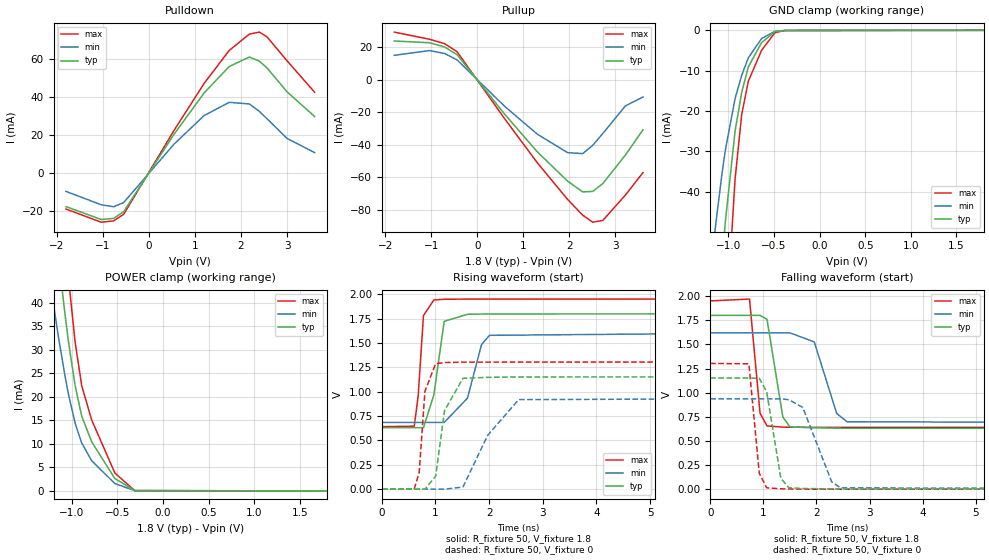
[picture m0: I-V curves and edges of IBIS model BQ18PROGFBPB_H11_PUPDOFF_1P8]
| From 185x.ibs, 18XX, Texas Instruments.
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|OQ18120COMPFZ_V_PDON_1P8; BUFFER WITH WEAK PULLDOWN ON
|   Model Cell BQ18PROGFBPB_H11_PUPDOFF_1P8
|BQ18PROGFBPB_H11_PUPDOFF_1P8
[Model]   BQ18PROGFBPB_H11_PUPDOFF_1P8
Model_type   I/O
Polarity   Non-Inverting
Enable   Active-Low
Vinl =  0.63
Vinh =  1.17
Cref =  15pF
Rref =  100.0000M
Vref =  0V
Vmeas =  0.9
C_comp   2.057622p   1.895389p   2.126353p
[Model Spec]
Vinl   0.63   0.567   0.6825
Vinh   1.17   1.053   1.2675
[Temperature Range]   25   125   -40
[Voltage Range]   1.8   1.62   1.95
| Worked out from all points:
|   slope of the pulldown table from 0 to 0.27 V, typ, clamps not added: 26.3 ohm
|   slope of the pullup table from 0 to 0.27 V, typ, clamps not added: 27.7 ohm
|   GND clamp passes 1 mA (typ) near -0.54 V on its own axis
|   POWER clamp passes 1 mA (typ) near -0.44 V on its own axis
|   rising waveform, R_fixture 50, V_fixture 1.8: 20-80 % time 158ps typ, 316ps min, 88.5ps max; typ from 0.63 V to 1.8 V
|   rising waveform, R_fixture 50, V_fixture 0: 20-80 % time 232ps typ, 451ps min, 107ps max; typ from 0 V to 1.15 V
|   falling waveform, R_fixture 50, V_fixture 1.8: 20-80 % time 173ps typ, 281ps min, 113ps max; typ from 1.8 V to 0.63 V
|   falling waveform, R_fixture 50, V_fixture 0: 20-80 % time 206ps typ, 394ps min, 117ps max; typ from 1.15 V to 0 V
| Nom Voltages:
|   BIASFET=1.8, VBBNW=1.1, VDD=1.1, VDDS=1.8, VSS=0, VSSS=0
| Min Voltages:
|   BIASFET=1.62, VBBNW=0.99, VDD=0.99, VDDS=1.62, VSS=0, VSSS=0
| Max Voltages:
|   BIASFET=1.95, VBBNW=1.21, VDD=1.21, VDDS=1.95, VSS=0, VSSS=0
[POWER_clamp]
|   voltage   I(typ)   I(min)   I(max)
-1.8V     178.9mA    128mA      243.2mA
-1.291V   75.76mA    51.65mA    107.4mA
-1.255V   68.98mA    46.64mA    97.96mA
-1.145V   49.38mA    32.55mA    70.53mA
-1.073V   37.35mA    24.29mA    53.42mA
-1.036V   31.7mA     20.49mA    45.27mA
-963.6mV  22.39mA    14.45mA    31.64mA
-890.9mV  15.9mA     10.19mA    22.36mA
-781.8mV  10.44mA    6.418mA    15.08mA
-527.3mV  2.627mA    1.561mA    3.8mA
-309.1mV  78.64uA    63.19uA    57.71uA
1.8V      -4.158nA   -210nA     -5.748nA
[Pulldown]
|   voltage   I(typ)   I(min)   I(max)
-1.8V     -17.77mA   -9.748mA   -19.05mA
-1.036V   -24.56mA   -16.8mA    -25.99mA
-763.6mV  -23.98mA   -17.86mA   -25.3mA
-545.5mV  -20.4mA    -15.61mA   -21.81mA
545.5mV   20.33mA    15.12mA    22.33mA
1.2V      42.13mA    30.21mA    47.14mA
1.745V    56.06mA    37.17mA    64.53mA
2.182V    61.03mA    36.32mA    73.12mA
2.4V      58.85mA    32.4mA     74.19mA
2.564V    55.36mA    28.55mA    71.7mA
3V        42.72mA    18.17mA    59.07mA
3.6V      29.69mA    10.66mA    42.5mA
[Pullup]
|   voltage   I(typ)   I(min)   I(max)
-1.8V     23.69mA    14.89mA    29.16mA
-1.036V   22.62mA    17.82mA    24.76mA
-709.1mV  20.05mA    16.02mA    22.07mA
-436.4mV  15.28mA    12.07mA    17.09mA
600mV     -21.35mA   -16.51mA   -24.17mA
1.309V    -44.48mA   -33.57mA   -51.19mA
1.964V    -62.36mA   -44.86mA   -73.59mA
2.291V    -68.93mA   -45.43mA   -83.23mA
2.509V    -68.65mA   -40.36mA   -87.54mA
2.727V    -63.85mA   -33.1mA    -86.46mA
3.218V    -46.34mA   -16.18mA   -70.92mA
3.6V      -30.82mA   -10.7mA    -57.09mA
[GND_clamp]
|   voltage   I(typ)   I(min)   I(max)
-1.8V     -337.7mA   -206.7mA   -550.8mA
-1.291V   -133.7mA   -80.77mA   -221.4mA
-1.145V   -81.03mA   -49.16mA   -133.6mA
-1.073V   -58.22mA   -35.89mA   -94.75mA
-1.036V   -47.89mA   -29.95mA   -77.04mA
-927.3mV  -25.01mA   -16.92mA   -36.88mA
-854.5mV  -15.35mA   -11.15mA   -20.84mA
-781.8mV  -9.051mA   -6.811mA   -12.6mA
-636.4mV  -3.048mA   -2.032mA   -4.945mA
-490.9mV  -357.6uA   -261.1uA   -600.3uA
-381.8mV  -30.89uA   -27.8uA    -45.52uA
1.8V      460.3pA    2.186uA    3.34nA
[Ramp]
| variable   typ   min   max
dV/dt_f 0.71597723/0.17847597n 0.57189968/0.29293619n 0.80177067/0.11580804n
dV/dt_r 0.69418521/0.23221913n 0.56332531/0.45155392n 0.78735006/0.10689518n
R_load = 50
[Rising Waveform]
R_fixture = 50
V_fixture = 1.8
V_fixture_min = 1.62
V_fixture_max = 1.95
|   time   V(typ)   V(min)   V(max)
0s        630.4mV    684.4mV    641mV
603.7ps   630.4mV    684.4mV    645.8mV
677.1ps   630.4mV    684.4mV    956.5mV
775.8ps   630.4mV    684.4mV    1.781V
968.9ps   966.1mV    684.4mV    1.941V
1.162ns   1.721V     684.4mV    1.948V
1.596ns   1.794V     933.4mV    1.95V
1.858ns   1.796V     1.483V     1.95V
2.007ns   1.797V     1.578V     1.95V
11.2ns    1.8V       1.62V      1.95V
[Rising Waveform]
R_fixture = 50
V_fixture = 0
V_fixture_min = 0
V_fixture_max = 0
|   time   V(typ)   V(min)   V(max)
0s        0V         0V         0V
602.3ps   0V         0V         0V
695.7ps   0V         0V         169.5mV
803.3ps   0V         0V         1.005V
1.003ns   134.2mV    0V         1.287V
1.169ns   806.6mV    0V         1.299V
1.511ns   1.137V     21.56mV    1.303V
1.973ns   1.147V     552.8mV    1.303V
2.55ns    1.151V     918.4mV    1.304V
11.2ns    1.153V     936.1mV    1.304V
[Falling Waveform]
R_fixture = 50
V_fixture = 1.8
V_fixture_min = 1.62
V_fixture_max = 1.95
|   time   V(typ)   V(min)   V(max)
0s        1.801V     1.62V      1.951V
740.3ps   1.801V     1.62V      1.97V
938.7ps   1.801V     1.62V      786.3mV
1.07ns    1.76V      1.62V      655mV
1.367ns   748.7mV    1.62V      643mV
1.5ns     645.7mV    1.62V      641.7mV
1.959ns   635.9mV    1.526V     640.7mV
2.381ns   632.2mV    785.2mV    640.6mV
2.575ns   631.6mV    698.6mV    640.6mV
11.2ns    629.7mV    684.6mV    640.3mV
[Falling Waveform]
R_fixture = 50
V_fixture = 0
V_fixture_min = 0
V_fixture_max = 0
|   time   V(typ)   V(min)   V(max)
0s        1.152V     935.8mV    1.303V
728.1ps   1.152V     935.8mV    1.299V
924.3ps   1.148V     935.8mV    164.2mV
1.063ns   1.01V      935.8mV    14.45mV
1.33ns    113.2mV    935.8mV    3.748mV
1.48ns    14.62mV    927.2mV    2.164mV
1.744ns   6.764mV    846mV      0V
2.286ns   3.142mV    77.79mV    0V
2.452ns   2.572mV    13.65mV    0V
11.2ns    0V         0V         0V
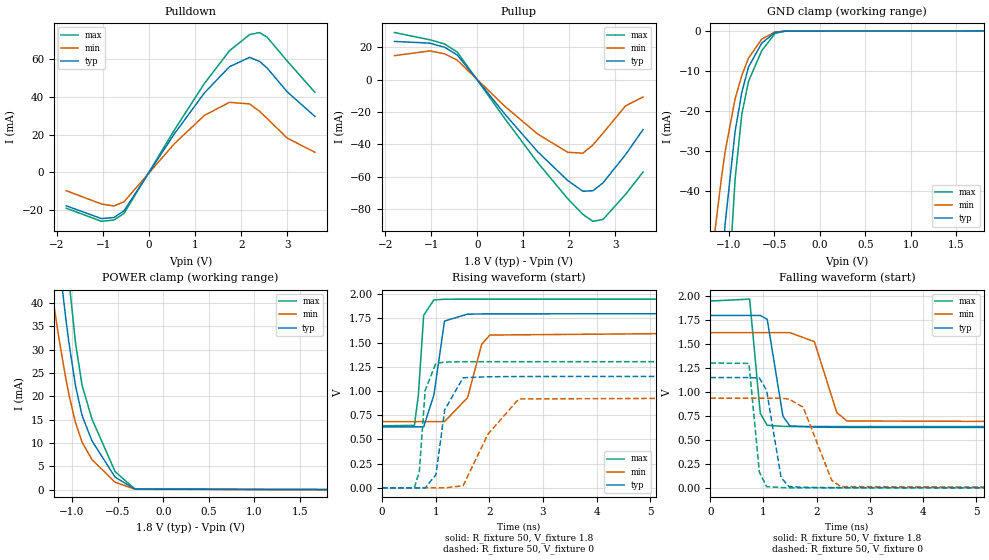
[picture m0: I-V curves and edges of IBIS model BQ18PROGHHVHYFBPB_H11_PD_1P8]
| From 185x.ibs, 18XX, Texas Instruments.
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|   Model Cell BQ18PROGHHVHYFBPB_H11_PD_1P8
|BQ18PROGHHVHYFBPB_H11_PD_1P8
[Model]   BQ18PROGHHVHYFBPB_H11_PD_1P8
Model_type   I/O
Polarity   Non-Inverting
Enable   Active-Low
Vinl =  0.63
Vinh =  1.17
Cref =  15pF
Rref =  100.0000M
Vref =  0V
Vmeas =  0.9
C_comp   2.057622p   1.895389p   2.126353p
[Model Spec]
Vinl   0.63   0.567   0.6825
Vinh   1.17   1.053   1.2675
[Temperature Range]   25   125   -40
[Voltage Range]   1.8   1.62   1.95
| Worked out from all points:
|   slope of the pulldown table from 0 to 0.27 V, typ, clamps not added: 26.3 ohm
|   slope of the pullup table from 0 to 0.27 V, typ, clamps not added: 27.7 ohm
|   GND clamp passes 1 mA (typ) near -0.54 V on its own axis
|   POWER clamp passes 1 mA (typ) near -0.44 V on its own axis
|   rising waveform, R_fixture 50, V_fixture 1.8: 20-80 % time 157ps typ, 316ps min, 88.5ps max; typ from 0.63 V to 1.8 V
|   rising waveform, R_fixture 50, V_fixture 0: 20-80 % time 232ps typ, 451ps min, 106ps max; typ from 0 V to 1.15 V
|   falling waveform, R_fixture 50, V_fixture 1.8: 20-80 % time 173ps typ, 281ps min, 113ps max; typ from 1.8 V to 0.629 V
|   falling waveform, R_fixture 50, V_fixture 0: 20-80 % time 206ps typ, 394ps min, 117ps max; typ from 1.15 V to 0 V
| Nom Voltages:
|   BIASFET=1.8, VBBNW=1.1, VDD=1.1, VDDS=1.8, VSS=0, VSSS=0
| Min Voltages:
|   BIASFET=1.62, VBBNW=0.99, VDD=0.99, VDDS=1.62, VSS=0, VSSS=0
| Max Voltages:
|   BIASFET=1.95, VBBNW=1.21, VDD=1.21, VDDS=1.95, VSS=0, VSSS=0
[POWER_clamp]
|   voltage   I(typ)   I(min)   I(max)
-1.8V     178.9mA    128mA      243.2mA
-1.291V   75.77mA    51.65mA    107.4mA
-1.255V   68.99mA    46.64mA    97.97mA
-1.145V   49.38mA    32.55mA    70.53mA
-1.073V   37.36mA    24.29mA    53.43mA
-1.036V   31.7mA     20.5mA     45.29mA
-963.6mV  22.4mA     14.45mA    31.67mA
-890.9mV  15.91mA    10.19mA    22.4mA
-781.8mV  10.46mA    6.423mA    15.12mA
-527.3mV  2.647mA    1.571mA    3.839mA
-309.1mV  99.61uA    72.86uA    97.96uA
1.8V      -4.125nA   -3.282uA   7.283uA
[Pulldown]
|   voltage   I(typ)   I(min)   I(max)
-1.8V     -17.77mA   -9.748mA   -19.05mA
-1.036V   -24.56mA   -16.8mA    -25.99mA
-763.6mV  -23.98mA   -17.86mA   -25.3mA
-545.5mV  -20.4mA    -15.61mA   -21.81mA
545.5mV   20.33mA    15.12mA    22.33mA
1.2V      42.13mA    30.21mA    47.14mA
1.745V    56.06mA    37.17mA    64.53mA
2.182V    61.03mA    36.32mA    73.12mA
2.4V      58.85mA    32.4mA     74.19mA
2.564V    55.36mA    28.55mA    71.7mA
3V        42.72mA    18.17mA    59.07mA
3.6V      29.69mA    10.66mA    42.5mA
[Pullup]
|   voltage   I(typ)   I(min)   I(max)
-1.8V     23.69mA    14.89mA    29.16mA
-1.036V   22.62mA    17.82mA    24.76mA
-709.1mV  20.05mA    16.02mA    22.07mA
-436.4mV  15.28mA    12.07mA    17.09mA
600mV     -21.35mA   -16.51mA   -24.17mA
1.309V    -44.48mA   -33.57mA   -51.19mA
1.964V    -62.36mA   -44.86mA   -73.59mA
2.291V    -68.93mA   -45.43mA   -83.23mA
2.509V    -68.65mA   -40.36mA   -87.54mA
2.727V    -63.85mA   -33.1mA    -86.46mA
3.218V    -46.34mA   -16.18mA   -70.92mA
3.6V      -30.82mA   -10.7mA    -57.09mA
[GND_clamp]
|   voltage   I(typ)   I(min)   I(max)
-1.8V     -337.7mA   -206.7mA   -550.8mA
-1.291V   -133.7mA   -80.77mA   -221.4mA
-1.145V   -81.03mA   -49.16mA   -133.6mA
-1.073V   -58.22mA   -35.9mA    -94.76mA
-1.036V   -47.89mA   -29.95mA   -77.05mA
-927.3mV  -25.01mA   -16.92mA   -36.89mA
-854.5mV  -15.36mA   -11.15mA   -20.86mA
-781.8mV  -9.064mA   -6.814mA   -12.63mA
-636.4mV  -3.063mA   -2.038mA   -4.969mA
-490.9mV  -371uA     -267.7uA   -622.4uA
-381.8mV  -42.42uA   -33.66uA   -64.54uA
1.8V      20.98uA    11.87uA    40.26uA
[Ramp]
| variable   typ   min   max
dV/dt_f 0.71590457/0.17852256n 0.57188619/0.29304934n  0.8016239/0.1157575n
dV/dt_r  0.6939603/0.2320826n 0.56320697/0.45144683n 0.78695366/0.10672385n
R_load = 50
[Rising Waveform]
R_fixture = 50
V_fixture = 1.8
V_fixture_min = 1.62
V_fixture_max = 1.95
|   time   V(typ)   V(min)   V(max)
0s        630.1mV    684.2mV    640.6mV
603.7ps   630.1mV    684.2mV    645.3mV
677.3ps   630.1mV    684.2mV    957.3mV
776ps     630.1mV    684.2mV    1.782V
966.9ps   959.9mV    684.2mV    1.941V
1.165ns   1.723V     684.2mV    1.948V
1.596ns   1.794V     933.2mV    1.949V
1.858ns   1.796V     1.483V     1.949V
2.01ns    1.797V     1.578V     1.949V
11.2ns    1.8V       1.62V      1.949V
[Rising Waveform]
R_fixture = 50
V_fixture = 0
V_fixture_min = 0
V_fixture_max = 0
|   time   V(typ)   V(min)   V(max)
0s        0V         0V         0V
602.3ps   0V         0V         0V
695.7ps   0V         0V         169.5mV
803.3ps   0V         0V         1.005V
1.004ns   134.9mV    0V         1.287V
1.169ns   806.5mV    0V         1.299V
1.511ns   1.137V     21.56mV    1.303V
1.973ns   1.147V     552.8mV    1.303V
2.55ns    1.15V      918.4mV    1.303V
11.2ns    1.152V     936mV      1.303V
[Falling Waveform]
R_fixture = 50
V_fixture = 1.8
V_fixture_min = 1.62
V_fixture_max = 1.95
|   time   V(typ)   V(min)   V(max)
0s        1.8V       1.62V      1.95V
740.3ps   1.8V       1.62V      1.97V
940.5ps   1.8V       1.62V      778.1mV
1.071ns   1.759V     1.62V      653.3mV
1.367ns   748.4mV    1.62V      641.9mV
1.499ns   644.8mV    1.62V      640.7mV
1.959ns   635.3mV    1.526V     640mV
2.381ns   631.8mV    784.9mV    639.9mV
2.573ns   631.1mV    698.3mV    639.9mV
11.2ns    629.3mV    684.4mV    639.9mV
[Falling Waveform]
R_fixture = 50
V_fixture = 0
V_fixture_min = 0
V_fixture_max = 0
|   time   V(typ)   V(min)   V(max)
0s        1.151V     935.6mV    1.303V
727.2ps   1.151V     935.6mV    1.299V
923.7ps   1.147V     935.6mV    164.7mV
1.06ns    1.017V     935.6mV    13.36mV
1.333ns   106.1mV    935.6mV    2.802mV
1.479ns   13.9mV     927.2mV    0V
1.748ns   6.062mV    841.7mV    0V
2.283ns   2.727mV    80.47mV    0V
2.451ns   2.176mV    13.21mV    0V
11.2ns    0V         0V         0V
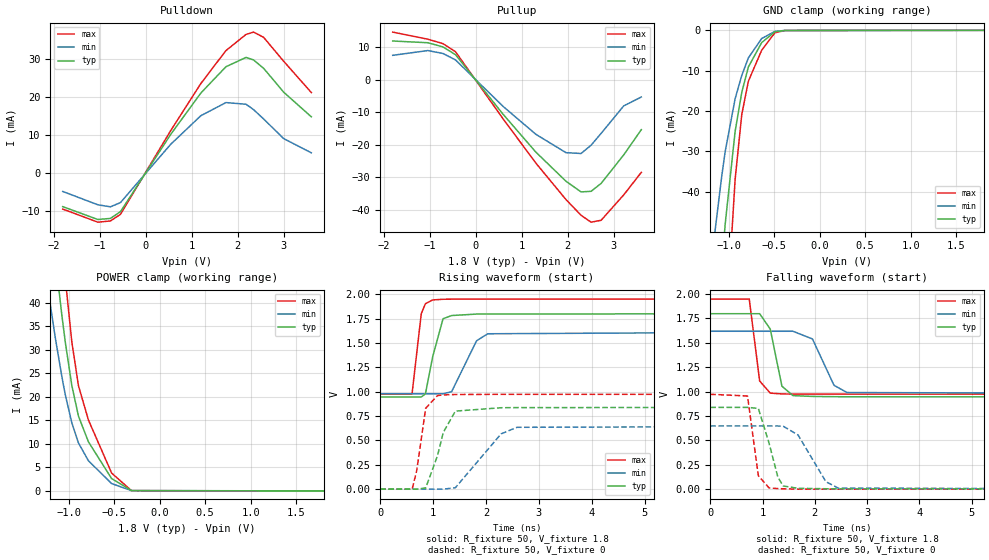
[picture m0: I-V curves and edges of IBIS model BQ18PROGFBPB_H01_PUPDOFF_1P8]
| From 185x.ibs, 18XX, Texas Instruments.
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|   Model Cell BQ18PROGFBPB_H01_PUPDOFF_1P8
|BQ18PROGFBPB_H01_PUPDOFF_1P8
[Model]   BQ18PROGFBPB_H01_PUPDOFF_1P8
Model_type   I/O
Polarity   Non-Inverting
Enable   Active-Low
Vinl =  0.63
Vinh =  1.17
Cref =  15pF
Rref =  100.0000M
Vref =  0V
Vmeas =  0.9
C_comp   2.057622p   1.895389p   2.126353p
[Model Spec]
Vinl   0.63   0.567   0.6825
Vinh   1.17   1.053   1.2675
[Temperature Range]   25   125   -40
[Voltage Range]   1.8   1.62   1.95
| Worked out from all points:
|   slope of the pulldown table from 0 to 0.27 V, typ, clamps not added: 52.6 ohm
|   slope of the pullup table from 0 to 0.27 V, typ, clamps not added: 55.3 ohm
|   GND clamp passes 1 mA (typ) near -0.54 V on its own axis
|   POWER clamp passes 1 mA (typ) near -0.44 V on its own axis
|   rising waveform, R_fixture 50, V_fixture 1.8: 20-80 % time 180ps typ, 348ps min, 111ps max; typ from 0.946 V to 1.8 V
|   rising waveform, R_fixture 50, V_fixture 0: 20-80 % time 262ps typ, 471ps min, 145ps max; typ from 0 V to 0.839 V
|   falling waveform, R_fixture 50, V_fixture 1.8: 20-80 % time 186ps typ, 311ps min, 127ps max; typ from 1.8 V to 0.945 V
|   falling waveform, R_fixture 50, V_fixture 0: 20-80 % time 222ps typ, 420ps min, 133ps max; typ from 0.839 V to 0 V
| Nom Voltages:
|   BIASFET=1.8, VBBNW=1.1, VDD=1.1, VDDS=1.8, VSS=0, VSSS=0
| Min Voltages:
|   BIASFET=1.62, VBBNW=0.99, VDD=0.99, VDDS=1.62, VSS=0, VSSS=0
| Max Voltages:
|   BIASFET=1.95, VBBNW=1.21, VDD=1.21, VDDS=1.95, VSS=0, VSSS=0
[POWER_clamp]
|   voltage   I(typ)   I(min)   I(max)
-1.8V     178.9mA    128mA      243.2mA
-1.291V   75.76mA    51.65mA    107.4mA
-1.255V   68.98mA    46.64mA    97.96mA
-1.145V   49.38mA    32.55mA    70.53mA
-1.073V   37.35mA    24.29mA    53.42mA
-1.036V   31.7mA     20.49mA    45.27mA
-963.6mV  22.39mA    14.45mA    31.64mA
-890.9mV  15.9mA     10.19mA    22.36mA
-781.8mV  10.44mA    6.418mA    15.08mA
-527.3mV  2.627mA    1.561mA    3.8mA
-309.1mV  78.64uA    63.19uA    57.71uA
1.8V      -4.158nA   -210nA     -5.748nA
[Pulldown]
|   voltage   I(typ)   I(min)   I(max)
-1.8V     -8.878mA   -4.872mA   -9.522mA
-1.036V   -12.28mA   -8.398mA   -12.99mA
-763.6mV  -11.99mA   -8.933mA   -12.66mA
-545.5mV  -10.21mA   -7.811mA   -10.92mA
545.5mV   10.19mA    7.571mA    11.19mA
1.2V      21.1mA     15.12mA    23.61mA
1.745V    28.05mA    18.59mA    32.31mA
2.182V    30.51mA    18.15mA    36.58mA
2.345V    29.85mA    16.74mA    37.2mA
2.564V    27.64mA    14.26mA    35.81mA
3V        21.33mA    9.076mA    29.49mA
3.6V      14.83mA    5.328mA    21.24mA
[Pullup]
|   voltage   I(typ)   I(min)   I(max)
-1.8V     11.84mA    7.444mA    14.58mA
-1.036V   11.31mA    8.912mA    12.39mA
-709.1mV  10.03mA    8.014mA    11.04mA
-436.4mV  7.65mA     6.042mA    8.559mA
600mV     -10.69mA   -8.267mA   -12.11mA
1.309V    -22.27mA   -16.8mA    -25.64mA
1.964V    -31.22mA   -22.44mA   -36.85mA
2.291V    -34.49mA   -22.7mA    -41.67mA
2.509V    -34.31mA   -20.15mA   -43.79mA
2.727V    -31.88mA   -16.52mA   -43.2mA
3.218V    -23.12mA   -8.08mA    -35.4mA
3.6V      -15.38mA   -5.348mA   -28.49mA
[GND_clamp]
|   voltage   I(typ)   I(min)   I(max)
-1.8V     -337.7mA   -206.7mA   -550.8mA
-1.291V   -133.7mA   -80.77mA   -221.4mA
-1.145V   -81.03mA   -49.16mA   -133.6mA
-1.073V   -58.22mA   -35.89mA   -94.75mA
-1.036V   -47.89mA   -29.95mA   -77.04mA
-927.3mV  -25.01mA   -16.92mA   -36.88mA
-854.5mV  -15.35mA   -11.15mA   -20.84mA
-781.8mV  -9.051mA   -6.811mA   -12.6mA
-636.4mV  -3.048mA   -2.032mA   -4.945mA
-490.9mV  -357.6uA   -261.1uA   -600.3uA
-381.8mV  -30.89uA   -27.8uA    -45.52uA
1.8V      460.3pA    2.186uA    3.34nA
[Ramp]
| variable   typ   min   max
dV/dt_f 0.52358561/0.19396371n 0.39343235/0.32035539n 0.59781385/0.12960236n
dV/dt_r 0.50647069/0.26284363n 0.39070878/0.47321148n 0.58938361/0.14674067n
R_load = 50
[Rising Waveform]
R_fixture = 50
V_fixture = 1.8
V_fixture_min = 1.62
V_fixture_max = 1.95
|   time   V(typ)   V(min)   V(max)
0s        945.6mV    978.6mV    974.3mV
600ps     945.6mV    978.6mV    974.3mV
775.9ps   945.6mV    978.6mV    1.802V
854.1ps   977.8mV    978.6mV    1.902V
990ps     1.356V     978.6mV    1.941V
1.187ns   1.748V     978.6mV    1.948V
1.349ns   1.781V     999.8mV    1.949V
1.821ns   1.796V     1.522V     1.95V
2.032ns   1.797V     1.594V     1.95V
11.2ns    1.8V       1.62V      1.95V
[Rising Waveform]
R_fixture = 50
V_fixture = 0
V_fixture_min = 0
V_fixture_max = 0
|   time   V(typ)   V(min)   V(max)
0s        0V         0V         0V
602.3ps   0V         0V         0V
688.9ps   0V         0V         190mV
858.7ps   12.5mV     0V         830mV
1.082ns   342.6mV    0V         960.5mV
1.192ns   582.6mV    0V         966.8mV
1.42ns    800.6mV    14.95mV    971.1mV
2.286ns   835.4mV    567.6mV    972.7mV
2.586ns   836.7mV    634.5mV    972.8mV
11.2ns    839.4mV    648mV      973.3mV
[Falling Waveform]
R_fixture = 50
V_fixture = 1.8
V_fixture_min = 1.62
V_fixture_max = 1.95
|   time   V(typ)   V(min)   V(max)
0s        1.799V     1.619V     1.949V
745.5ps   1.799V     1.619V     1.949V
944.3ps   1.799V     1.619V     1.109V
1.147ns   1.641V     1.619V     984.6mV
1.37ns    1.056V     1.619V     976.6mV
1.581ns   959mV      1.619V     974.8mV
1.954ns   950.7mV    1.54V      974.1mV
2.366ns   948.1mV    1.065V     974mV
2.615ns   947.2mV    990.6mV    974mV
11.2ns    945.1mV    978.4mV    973.9mV
[Falling Waveform]
R_fixture = 50
V_fixture = 0
V_fixture_min = 0
V_fixture_max = 0
|   time   V(typ)   V(min)   V(max)
0s        838.7mV    647.7mV    972.6mV
712.1ps   838.7mV    647.7mV    955.4mV
919.5ps   828.2mV    647.7mV    136.7mV
1.124ns   471.4mV    647.7mV    13.32mV
1.294ns   121.1mV    647.7mV    5.743mV
1.394ns   32.59mV    645.6mV    3.838mV
1.678ns   9.012mV    555.7mV    0V
2.212ns   4.261mV    76.18mV    0V
2.447ns   3.218mV    10.84mV    0V
11.2ns    0V         0V         0V
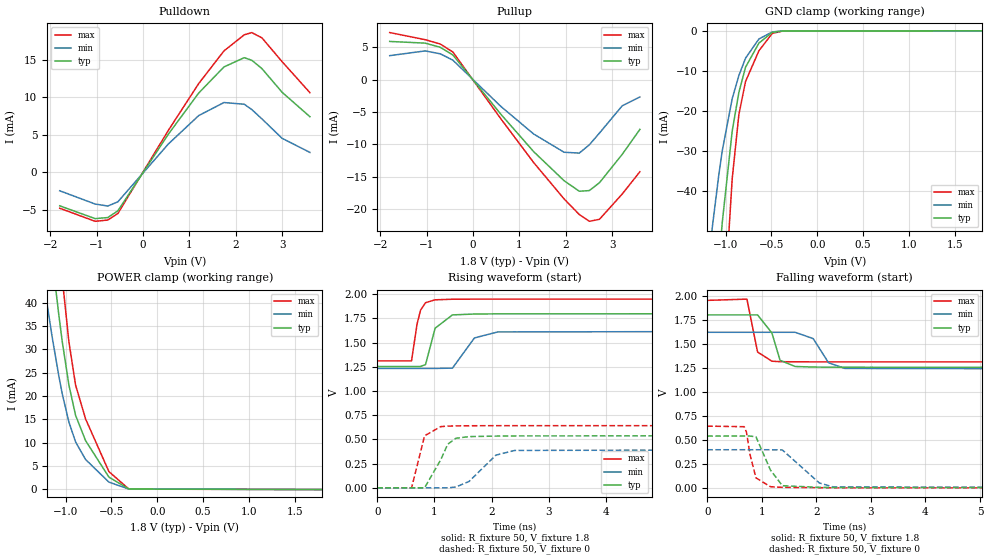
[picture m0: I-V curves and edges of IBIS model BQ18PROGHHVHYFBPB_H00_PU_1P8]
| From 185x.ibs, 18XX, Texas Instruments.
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|   Model Cell BQ18PROGHHVHYFBPB_H00_PU_1P8
|BQ18PROGHHVHYFBPB_H00_PU_1P8
[Model]   BQ18PROGHHVHYFBPB_H00_PU_1P8
Model_type   I/O
Polarity   Non-Inverting
Enable   Active-Low
Vinl =  0.63
Vinh =  1.17
Cref =  15pF
Rref =  100.0000M
Vref =  0V
Vmeas =  0.9
C_comp   2.057622p   1.895389p   2.126353p
[Model Spec]
Vinl   0.63   0.567   0.6825
Vinh   1.17   1.053   1.2675
[Temperature Range]   25   125   -40
[Voltage Range]   1.8   1.62   1.95
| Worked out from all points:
|   slope of the pulldown table from 0 to 0.27 V, typ, clamps not added: 105 ohm
|   slope of the pullup table from 0 to 0.27 V, typ, clamps not added: 110 ohm
|   GND clamp passes 1 mA (typ) near -0.54 V on its own axis
|   POWER clamp passes 1 mA (typ) near -0.44 V on its own axis
|   rising waveform, R_fixture 50, V_fixture 1.8: 20-80 % time 166ps typ, 283ps min, 114ps max; typ from 1.25 V to 1.8 V
|   rising waveform, R_fixture 50, V_fixture 0: 20-80 % time 249ps typ, 397ps min, 155ps max; typ from 0 V to 0.54 V
|   falling waveform, R_fixture 50, V_fixture 1.8: 20-80 % time 189ps typ, 243ps min, 128ps max; typ from 1.8 V to 1.25 V
|   falling waveform, R_fixture 50, V_fixture 0: 20-80 % time 223ps typ, 428ps min, 138ps max; typ from 0.539 V to 0 V
| Nom Voltages:
|   BIASFET=1.8, VBBNW=1.1, VDD=1.1, VDDS=1.8, VSS=0, VSSS=0
| Min Voltages:
|   BIASFET=1.62, VBBNW=0.99, VDD=0.99, VDDS=1.62, VSS=0, VSSS=0
| Max Voltages:
|   BIASFET=1.95, VBBNW=1.21, VDD=1.21, VDDS=1.95, VSS=0, VSSS=0
[POWER_clamp]
|   voltage   I(typ)   I(min)   I(max)
-1.8V     178.9mA    128mA      243.2mA
-1.291V   75.77mA    51.65mA    107.4mA
-1.255V   68.99mA    46.64mA    97.97mA
-1.145V   49.38mA    32.56mA    70.53mA
-1.073V   37.36mA    24.29mA    53.43mA
-1.036V   31.7mA     20.5mA     45.29mA
-963.6mV  22.4mA     14.45mA    31.67mA
-890.9mV  15.91mA    10.19mA    22.4mA
-781.8mV  10.46mA    6.424mA    15.12mA
-527.3mV  2.642mA    1.569mA    3.825mA
-309.1mV  87.37uA    67.92uA    72.68uA
1.8V      -19.86uA   -9.301uA   -38.48uA
[Pulldown]
|   voltage   I(typ)   I(min)   I(max)
-1.8V     -4.437mA   -2.435mA   -4.759mA
-1.036V   -6.139mA   -4.198mA   -6.496mA
-763.6mV  -5.999mA   -4.467mA   -6.331mA
-545.5mV  -5.109mA   -3.907mA   -5.464mA
545.5mV   5.097mA    3.788mA    5.6mA
1.2V      10.56mA    7.562mA    11.82mA
1.745V    14.03mA    9.297mA    16.16mA
2.182V    15.26mA    9.07mA     18.3mA
2.345V    14.92mA    8.367mA    18.6mA
2.564V    13.81mA    7.124mA    17.9mA
3V        10.66mA    4.536mA    14.73mA
3.6V      7.413mA    2.663mA    10.61mA
[Pullup]
|   voltage   I(typ)   I(min)   I(max)
-1.8V     5.919mA    3.721mA    7.292mA
-1.036V   5.658mA    4.456mA    6.194mA
-709.1mV  5.017mA    4.008mA    5.523mA
-436.4mV  3.827mA    3.023mA    4.283mA
600mV     -5.351mA   -4.136mA   -6.059mA
1.309V    -11.14mA   -8.407mA   -12.83mA
1.964V    -15.62mA   -11.22mA   -18.44mA
2.291V    -17.25mA   -11.35mA   -20.85mA
2.509V    -17.15mA   -10.07mA   -21.9mA
2.727V    -15.93mA   -8.253mA   -21.59mA
3.218V    -11.55mA   -4.037mA   -17.68mA
3.6V      -7.684mA   -2.673mA   -14.23mA
[GND_clamp]
|   voltage   I(typ)   I(min)   I(max)
-1.8V     -337.7mA   -206.7mA   -550.9mA
-1.291V   -133.7mA   -80.77mA   -221.4mA
-1.145V   -81.03mA   -49.16mA   -133.6mA
-1.073V   -58.22mA   -35.9mA    -94.77mA
-1.036V   -47.89mA   -29.96mA   -77.06mA
-927.3mV  -25.01mA   -16.92mA   -36.9mA
-854.5mV  -15.36mA   -11.15mA   -20.87mA
-781.8mV  -9.067mA   -6.815mA   -12.64mA
-636.4mV  -3.067mA   -2.039mA   -4.983mA
-490.9mV  -377.1uA   -269.8uA   -638.6uA
-381.8mV  -50.69uA   -36.67uA   -84.39uA
1.8V      451.8pA    4.855uA    -6.741uA
[Ramp]
| variable   typ   min   max
dV/dt_f 0.33660464/0.19893366n 0.23803924/0.25684653n 0.39263769/0.12927024n
dV/dt_r 0.32636552/0.25155921n  0.2399141/0.40049741n 0.39058123/0.15574269n
R_load = 50
[Rising Waveform]
R_fixture = 50
V_fixture = 1.8
V_fixture_min = 1.62
V_fixture_max = 1.95
|   time   V(typ)   V(min)   V(max)
0s        1.254V     1.234V     1.312V
600ps     1.254V     1.234V     1.312V
698.4ps   1.254V     1.234V     1.697V
758.8ps   1.254V     1.234V     1.837V
845.2ps   1.274V     1.234V     1.913V
1.013ns   1.65V      1.234V     1.943V
1.316ns   1.787V     1.237V     1.949V
1.7ns     1.796V     1.549V     1.95V
2.108ns   1.798V     1.611V     1.95V
11.2ns    1.8V       1.62V      1.95V
[Rising Waveform]
R_fixture = 50
V_fixture = 0
V_fixture_min = 0
V_fixture_max = 0
|   time   V(typ)   V(min)   V(max)
0s        0V         0V         0V
601.1ps   0V         0V         0V
828ps     0V         0V         537.4mV
1.111ns   290.3mV    0V         632.8mV
1.233ns   450.8mV    0V         637.5mV
1.378ns   512.8mV    9.254mV    640.1mV
1.605ns   529.5mV    65.66mV    641.7mV
2.077ns   534.9mV    338.6mV    642.4mV
2.406ns   536.6mV    386.8mV    642.5mV
11.2ns    539.8mV    396.9mV    643mV
[Falling Waveform]
R_fixture = 50
V_fixture = 1.8
V_fixture_min = 1.62
V_fixture_max = 1.95
|   time   V(typ)   V(min)   V(max)
0s        1.8V       1.619V     1.951V
728.5ps   1.8V       1.619V     1.964V
923.2ps   1.8V       1.619V     1.414V
1.186ns   1.612V     1.619V     1.318V
1.335ns   1.328V     1.619V     1.313V
1.612ns   1.263V     1.619V     1.312V
1.943ns   1.257V     1.553V     1.311V
2.224ns   1.256V     1.302V     1.311V
2.522ns   1.255V     1.243V     1.311V
11.2ns    1.253V     1.234V     1.311V
[Falling Waveform]
R_fixture = 50
V_fixture = 0
V_fixture_min = 0
V_fixture_max = 0
|   time   V(typ)   V(min)   V(max)
0s        538.9mV    396.7mV    642.4mV
677.8ps   538.9mV    396.7mV    636.5mV
720.4ps   538.9mV    396.7mV    579.5mV
783.2ps   538.9mV    396.7mV    351.2mV
894ps     531.3mV    396.7mV    103.9mV
1.159ns   185.8mV    396.7mV    11.89mV
1.378ns   22.6mV     394.1mV    5.252mV
2.055ns   5.315mV    51.26mV    2.066mV
2.309ns   4.088mV    9.328mV    0V
11.2ns    0V         0V         0V
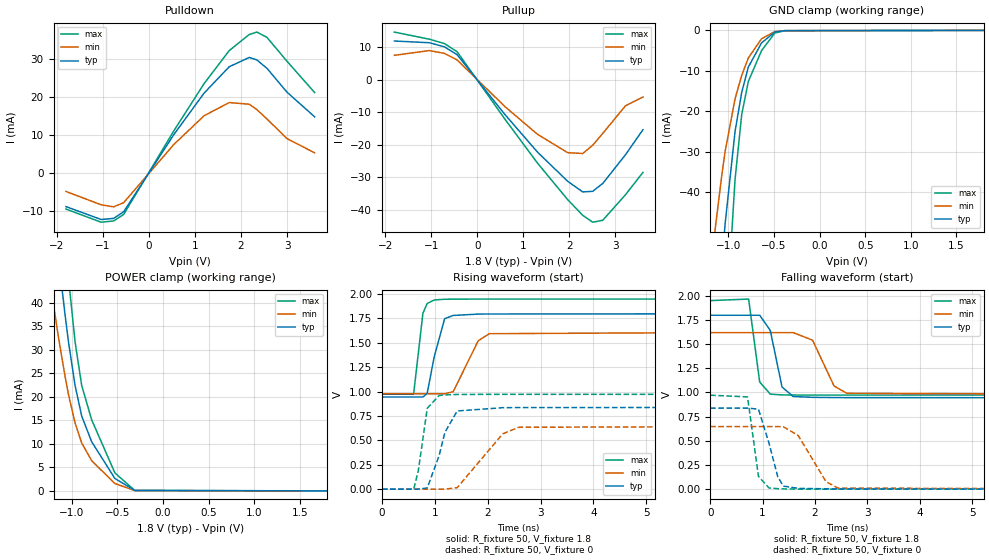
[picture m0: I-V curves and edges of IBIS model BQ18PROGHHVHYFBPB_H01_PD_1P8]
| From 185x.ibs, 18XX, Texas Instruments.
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|   Model Cell BQ18PROGHHVHYFBPB_H01_PD_1P8
|BQ18PROGHHVHYFBPB_H01_PD_1P8
[Model]   BQ18PROGHHVHYFBPB_H01_PD_1P8
Model_type   I/O
Polarity   Non-Inverting
Enable   Active-Low
Vinl =  0.63
Vinh =  1.17
Cref =  15pF
Rref =  100.0000M
Vref =  0V
Vmeas =  0.9
C_comp   2.057622p   1.895389p   2.126353p
[Model Spec]
Vinl   0.63   0.567   0.6825
Vinh   1.17   1.053   1.2675
[Temperature Range]   25   125   -40
[Voltage Range]   1.8   1.62   1.95
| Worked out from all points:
|   slope of the pulldown table from 0 to 0.27 V, typ, clamps not added: 52.6 ohm
|   slope of the pullup table from 0 to 0.27 V, typ, clamps not added: 55.3 ohm
|   GND clamp passes 1 mA (typ) near -0.54 V on its own axis
|   POWER clamp passes 1 mA (typ) near -0.44 V on its own axis
|   rising waveform, R_fixture 50, V_fixture 1.8: 20-80 % time 180ps typ, 348ps min, 111ps max; typ from 0.945 V to 1.8 V
|   rising waveform, R_fixture 50, V_fixture 0: 20-80 % time 261ps typ, 471ps min, 145ps max; typ from 0 V to 0.839 V
|   falling waveform, R_fixture 50, V_fixture 1.8: 20-80 % time 186ps typ, 311ps min, 127ps max; typ from 1.8 V to 0.945 V
|   falling waveform, R_fixture 50, V_fixture 0: 20-80 % time 222ps typ, 420ps min, 132ps max; typ from 0.838 V to 0 V
| Nom Voltages:
|   BIASFET=1.8, VBBNW=1.1, VDD=1.1, VDDS=1.8, VSS=0, VSSS=0
| Min Voltages:
|   BIASFET=1.62, VBBNW=0.99, VDD=0.99, VDDS=1.62, VSS=0, VSSS=0
| Max Voltages:
|   BIASFET=1.95, VBBNW=1.21, VDD=1.21, VDDS=1.95, VSS=0, VSSS=0
[POWER_clamp]
|   voltage   I(typ)   I(min)   I(max)
-1.8V     178.9mA    128mA      243.2mA
-1.291V   75.77mA    51.65mA    107.4mA
-1.255V   68.99mA    46.64mA    97.97mA
-1.145V   49.38mA    32.55mA    70.53mA
-1.073V   37.36mA    24.29mA    53.43mA
-1.036V   31.7mA     20.5mA     45.29mA
-963.6mV  22.4mA     14.45mA    31.67mA
-890.9mV  15.91mA    10.19mA    22.4mA
-781.8mV  10.46mA    6.423mA    15.12mA
-527.3mV  2.647mA    1.571mA    3.839mA
-309.1mV  99.61uA    72.86uA    97.96uA
1.8V      -4.125nA   -3.282uA   7.283uA
[Pulldown]
|   voltage   I(typ)   I(min)   I(max)
-1.8V     -8.878mA   -4.872mA   -9.522mA
-1.036V   -12.28mA   -8.398mA   -12.99mA
-763.6mV  -11.99mA   -8.933mA   -12.66mA
-545.5mV  -10.21mA   -7.811mA   -10.92mA
545.5mV   10.19mA    7.571mA    11.19mA
1.2V      21.1mA     15.12mA    23.61mA
1.745V    28.05mA    18.59mA    32.31mA
2.182V    30.51mA    18.15mA    36.58mA
2.345V    29.85mA    16.74mA    37.2mA
2.564V    27.64mA    14.26mA    35.81mA
3V        21.33mA    9.076mA    29.49mA
3.6V      14.83mA    5.328mA    21.24mA
[Pullup]
|   voltage   I(typ)   I(min)   I(max)
-1.8V     11.84mA    7.444mA    14.58mA
-1.036V   11.31mA    8.912mA    12.39mA
-709.1mV  10.03mA    8.014mA    11.04mA
-436.4mV  7.65mA     6.042mA    8.559mA
600mV     -10.69mA   -8.267mA   -12.11mA
1.309V    -22.27mA   -16.8mA    -25.64mA
1.964V    -31.22mA   -22.44mA   -36.85mA
2.291V    -34.49mA   -22.7mA    -41.67mA
2.509V    -34.31mA   -20.15mA   -43.79mA
2.727V    -31.88mA   -16.52mA   -43.2mA
3.218V    -23.12mA   -8.08mA    -35.4mA
3.6V      -15.38mA   -5.348mA   -28.49mA
[GND_clamp]
|   voltage   I(typ)   I(min)   I(max)
-1.8V     -337.7mA   -206.7mA   -550.8mA
-1.291V   -133.7mA   -80.77mA   -221.4mA
-1.145V   -81.03mA   -49.16mA   -133.6mA
-1.073V   -58.22mA   -35.9mA    -94.76mA
-1.036V   -47.89mA   -29.95mA   -77.05mA
-927.3mV  -25.01mA   -16.92mA   -36.89mA
-854.5mV  -15.36mA   -11.15mA   -20.86mA
-781.8mV  -9.064mA   -6.814mA   -12.63mA
-636.4mV  -3.063mA   -2.038mA   -4.969mA
-490.9mV  -371uA     -267.7uA   -622.4uA
-381.8mV  -42.42uA   -33.66uA   -64.54uA
1.8V      20.98uA    11.87uA    40.26uA
[Ramp]
| variable   typ   min   max
dV/dt_f 0.52355412/0.19413645n 0.39343369/0.32047926n 0.59773386/0.12968086n
dV/dt_r 0.50617381/0.26262029n 0.39056407/0.47298446n 0.58884915/0.14651097n
R_load = 50
[Rising Waveform]
R_fixture = 50
V_fixture = 1.8
V_fixture_min = 1.62
V_fixture_max = 1.95
|   time   V(typ)   V(min)   V(max)
0s        945.1mV    978.3mV    973.4mV
600ps     945.1mV    978.3mV    973.4mV
775.9ps   945.1mV    978.3mV    1.802V
856.3ps   981.6mV    978.3mV    1.903V
991ps     1.359V     978.3mV    1.94V
1.187ns   1.748V     978.3mV    1.947V
1.349ns   1.781V     999.5mV    1.948V
1.821ns   1.795V     1.521V     1.949V
2.031ns   1.796V     1.594V     1.949V
11.2ns    1.799V     1.619V     1.949V
[Rising Waveform]
R_fixture = 50
V_fixture = 0
V_fixture_min = 0
V_fixture_max = 0
|   time   V(typ)   V(min)   V(max)
0s        0V         0V         0V
602.3ps   0V         0V         0V
688.9ps   0V         0V         190mV
858.7ps   12.5mV     0V         829.9mV
1.083ns   345.2mV    0V         960.4mV
1.192ns   582.6mV    0V         966.7mV
1.424ns   801.6mV    15.58mV    971mV
2.286ns   835.3mV    567.6mV    972.4mV
2.586ns   836.6mV    634.5mV    972.4mV
11.2ns    839mV      647.8mV    972.5mV
[Falling Waveform]
R_fixture = 50
V_fixture = 1.8
V_fixture_min = 1.62
V_fixture_max = 1.95
|   time   V(typ)   V(min)   V(max)
0s        1.799V     1.619V     1.95V
733.3ps   1.799V     1.619V     1.966V
943.8ps   1.799V     1.619V     1.109V
1.146ns   1.642V     1.619V     982.7mV
1.37ns    1.057V     1.619V     975mV
1.583ns   957.9mV    1.619V     973.5mV
1.952ns   949.8mV    1.541V     973.1mV
2.363ns   947.4mV    1.067V     973mV
2.609ns   946.5mV    990.8mV    973mV
11.2ns    944.5mV    978.1mV    973mV
[Falling Waveform]
R_fixture = 50
V_fixture = 0
V_fixture_min = 0
V_fixture_max = 0
|   time   V(typ)   V(min)   V(max)
0s        838.2mV    647.5mV    971.7mV
712.1ps   838.2mV    647.5mV    954.4mV
920.7ps   827.2mV    647.5mV    132.3mV
1.122ns   474.8mV    647.5mV    12.24mV
1.289ns   128.3mV    647.5mV    4.836mV
1.394ns   31.77mV    645.4mV    2.907mV
1.678ns   8.347mV    555.4mV    0V
2.211ns   3.791mV    76.53mV    0V
2.442ns   2.792mV    10.72mV    0V
11.2ns    0V         0V         0V
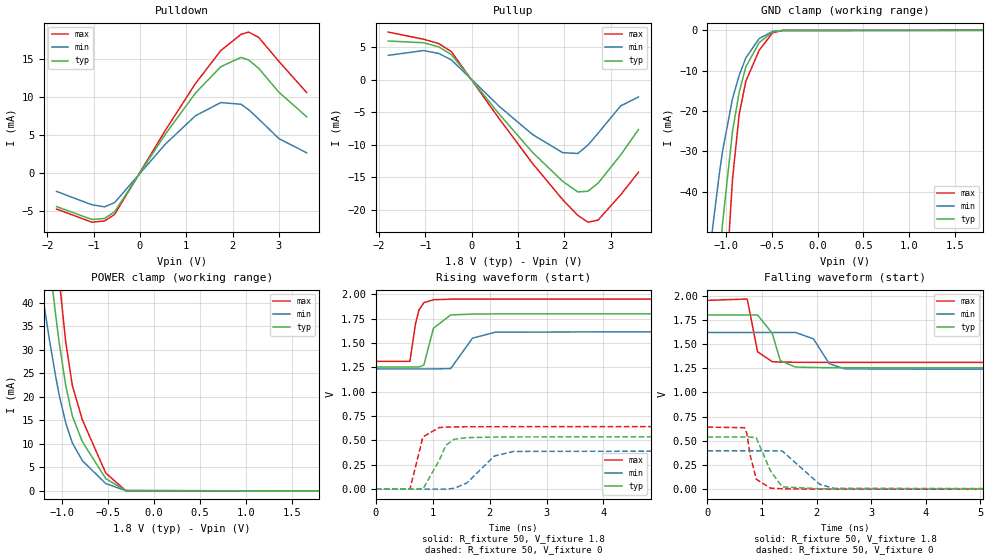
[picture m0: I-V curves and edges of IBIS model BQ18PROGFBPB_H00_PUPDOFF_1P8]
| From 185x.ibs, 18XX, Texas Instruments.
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|   Model Cell BQ18PROGFBPB_H00_PUPDOFF_1P8
|BQ18PROGFBPB_H00_PUPDOFF_1P8
[Model]   BQ18PROGFBPB_H00_PUPDOFF_1P8
Model_type   I/O
Polarity   Non-Inverting
Enable   Active-Low
Vinl =  0.63
Vinh =  1.17
Cref =  15pF
Rref =  100.0000M
Vref =  0V
Vmeas =  0.9
C_comp   2.057622p   1.895389p   2.126353p
[Model Spec]
Vinl   0.63   0.567   0.6825
Vinh   1.17   1.053   1.2675
[Temperature Range]   25   125   -40
[Voltage Range]   1.8   1.62   1.95
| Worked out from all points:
|   slope of the pulldown table from 0 to 0.27 V, typ, clamps not added: 105 ohm
|   slope of the pullup table from 0 to 0.27 V, typ, clamps not added: 110 ohm
|   GND clamp passes 1 mA (typ) near -0.54 V on its own axis
|   POWER clamp passes 1 mA (typ) near -0.44 V on its own axis
|   rising waveform, R_fixture 50, V_fixture 1.8: 20-80 % time 165ps typ, 283ps min, 114ps max; typ from 1.25 V to 1.8 V
|   rising waveform, R_fixture 50, V_fixture 0: 20-80 % time 249ps typ, 397ps min, 154ps max; typ from 0 V to 0.539 V
|   falling waveform, R_fixture 50, V_fixture 1.8: 20-80 % time 189ps typ, 243ps min, 127ps max; typ from 1.8 V to 1.25 V
|   falling waveform, R_fixture 50, V_fixture 0: 20-80 % time 222ps typ, 428ps min, 138ps max; typ from 0.538 V to 0 V
| Nom Voltages:
|   BIASFET=1.8, VBBNW=1.1, VDD=1.1, VDDS=1.8, VSS=0, VSSS=0
| Min Voltages:
|   BIASFET=1.62, VBBNW=0.99, VDD=0.99, VDDS=1.62, VSS=0, VSSS=0
| Max Voltages:
|   BIASFET=1.95, VBBNW=1.21, VDD=1.21, VDDS=1.95, VSS=0, VSSS=0
[POWER_clamp]
|   voltage   I(typ)   I(min)   I(max)
-1.8V     178.9mA    128mA      243.2mA
-1.291V   75.76mA    51.65mA    107.4mA
-1.255V   68.98mA    46.64mA    97.96mA
-1.145V   49.38mA    32.55mA    70.53mA
-1.073V   37.35mA    24.29mA    53.42mA
-1.036V   31.7mA     20.49mA    45.27mA
-963.6mV  22.39mA    14.45mA    31.64mA
-890.9mV  15.9mA     10.19mA    22.36mA
-781.8mV  10.44mA    6.418mA    15.08mA
-527.3mV  2.627mA    1.561mA    3.8mA
-309.1mV  78.64uA    63.19uA    57.71uA
1.8V      -4.158nA   -210nA     -5.748nA
[Pulldown]
|   voltage   I(typ)   I(min)   I(max)
-1.8V     -4.437mA   -2.435mA   -4.759mA
-1.036V   -6.139mA   -4.198mA   -6.496mA
-763.6mV  -5.999mA   -4.467mA   -6.331mA
-545.5mV  -5.109mA   -3.907mA   -5.464mA
545.5mV   5.097mA    3.788mA    5.6mA
1.2V      10.56mA    7.562mA    11.82mA
1.745V    14.03mA    9.297mA    16.16mA
2.182V    15.26mA    9.07mA     18.3mA
2.345V    14.92mA    8.367mA    18.6mA
2.564V    13.81mA    7.124mA    17.9mA
3V        10.66mA    4.536mA    14.73mA
3.6V      7.413mA    2.663mA    10.61mA
[Pullup]
|   voltage   I(typ)   I(min)   I(max)
-1.8V     5.919mA    3.721mA    7.292mA
-1.036V   5.658mA    4.456mA    6.194mA
-709.1mV  5.017mA    4.008mA    5.523mA
-436.4mV  3.827mA    3.023mA    4.283mA
600mV     -5.351mA   -4.136mA   -6.059mA
1.309V    -11.14mA   -8.407mA   -12.83mA
1.964V    -15.62mA   -11.22mA   -18.44mA
2.291V    -17.25mA   -11.35mA   -20.85mA
2.509V    -17.15mA   -10.07mA   -21.9mA
2.727V    -15.93mA   -8.253mA   -21.59mA
3.218V    -11.55mA   -4.037mA   -17.68mA
3.6V      -7.684mA   -2.673mA   -14.23mA
[GND_clamp]
|   voltage   I(typ)   I(min)   I(max)
-1.8V     -337.7mA   -206.7mA   -550.8mA
-1.291V   -133.7mA   -80.77mA   -221.4mA
-1.145V   -81.03mA   -49.16mA   -133.6mA
-1.073V   -58.22mA   -35.89mA   -94.75mA
-1.036V   -47.89mA   -29.95mA   -77.04mA
-927.3mV  -25.01mA   -16.92mA   -36.88mA
-854.5mV  -15.35mA   -11.15mA   -20.84mA
-781.8mV  -9.051mA   -6.811mA   -12.6mA
-636.4mV  -3.048mA   -2.032mA   -4.945mA
-490.9mV  -357.6uA   -261.1uA   -600.3uA
-381.8mV  -30.89uA   -27.8uA    -45.52uA
1.8V      460.3pA    2.186uA    3.34nA
[Ramp]
| variable   typ   min   max
dV/dt_f 0.33688529/0.19869218n 0.23816037/0.25660027n 0.39317493/0.12890122n
dV/dt_r  0.3263572/0.25156704n 0.23990668/0.40047855n 0.39059547/0.15581964n
R_load = 50
[Rising Waveform]
R_fixture = 50
V_fixture = 1.8
V_fixture_min = 1.62
V_fixture_max = 1.95
|   time   V(typ)   V(min)   V(max)
0s        1.253V     1.233V     1.311V
600ps     1.253V     1.233V     1.311V
698.4ps   1.253V     1.233V     1.697V
758.8ps   1.253V     1.233V     1.838V
845.2ps   1.273V     1.233V     1.913V
1.013ns   1.651V     1.233V     1.943V
1.316ns   1.787V     1.237V     1.949V
1.7ns     1.796V     1.549V     1.95V
2.106ns   1.798V     1.611V     1.95V
11.2ns    1.8V       1.62V      1.95V
[Rising Waveform]
R_fixture = 50
V_fixture = 0
V_fixture_min = 0
V_fixture_max = 0
|   time   V(typ)   V(min)   V(max)
0s        0V         0V         0V
601.1ps   0V         0V         0V
828ps     0V         0V         536mV
1.113ns   293.3mV    0V         631.7mV
1.233ns   449.8mV    0V         636.2mV
1.379ns   512.1mV    8.992mV    638.8mV
1.602ns   528.7mV    63.74mV    640.4mV
2.081ns   534.3mV    339.6mV    641.1mV
2.417ns   535.9mV    386.9mV    641.2mV
11.2ns    539.1mV    396.6mV    641.8mV
[Falling Waveform]
R_fixture = 50
V_fixture = 1.8
V_fixture_min = 1.62
V_fixture_max = 1.95
|   time   V(typ)   V(min)   V(max)
0s        1.8V       1.619V     1.951V
728.5ps   1.8V       1.619V     1.964V
918.9ps   1.8V       1.619V     1.419V
1.186ns   1.611V     1.619V     1.317V
1.335ns   1.328V     1.619V     1.313V
1.612ns   1.262V     1.619V     1.311V
1.943ns   1.257V     1.553V     1.31V
2.233ns   1.255V     1.296V     1.31V
2.523ns   1.254V     1.242V     1.31V
11.2ns    1.252V     1.234V     1.31V
[Falling Waveform]
R_fixture = 50
V_fixture = 0
V_fixture_min = 0
V_fixture_max = 0
|   time   V(typ)   V(min)   V(max)
0s        538.2mV    396.3mV    641.1mV
677.8ps   538.2mV    396.3mV    635.2mV
722.6ps   538.2mV    396.3mV    572.9mV
783.3ps   538.2mV    396.3mV    349.6mV
894.1ps   530.6mV    396.3mV    102.6mV
1.155ns   189.6mV    396.3mV    10.83mV
1.369ns   23.36mV    394.9mV    4.139mV
2.058ns   4.64mV     49.84mV    0V
2.313ns   3.413mV    8.84mV     0V
11.2ns    0V         0V         0V
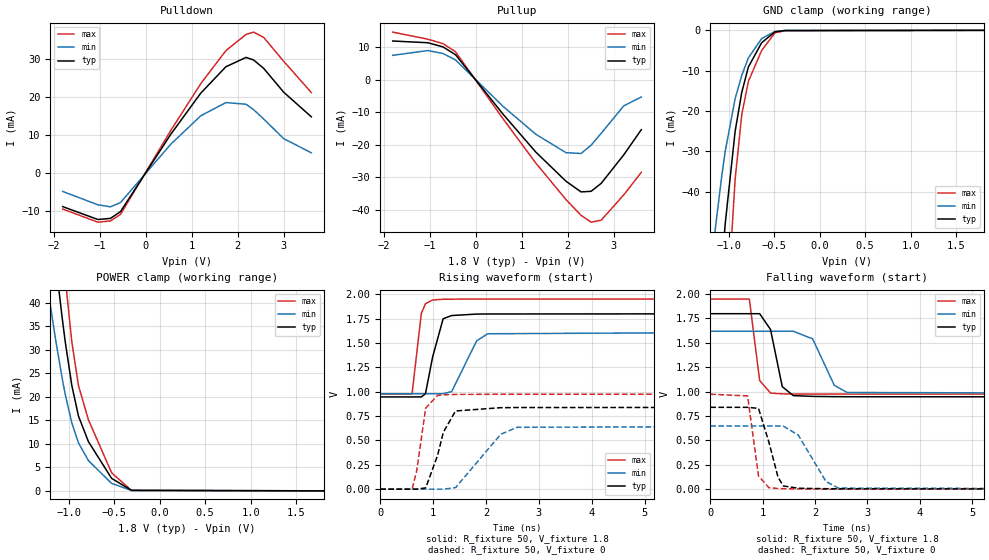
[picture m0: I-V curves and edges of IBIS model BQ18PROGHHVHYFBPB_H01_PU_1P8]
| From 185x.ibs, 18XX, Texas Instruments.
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|   Model Cell BQ18PROGHHVHYFBPB_H01_PU_1P8
|BQ18PROGHHVHYFBPB_H01_PU_1P8
[Model]   BQ18PROGHHVHYFBPB_H01_PU_1P8
Model_type   I/O
Polarity   Non-Inverting
Enable   Active-Low
Vinl =  0.63
Vinh =  1.17
Cref =  15pF
Rref =  100.0000M
Vref =  0V
Vmeas =  0.9
C_comp   2.057622p   1.895389p   2.126353p
[Model Spec]
Vinl   0.63   0.567   0.6825
Vinh   1.17   1.053   1.2675
[Temperature Range]   25   125   -40
[Voltage Range]   1.8   1.62   1.95
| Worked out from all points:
|   slope of the pulldown table from 0 to 0.27 V, typ, clamps not added: 52.6 ohm
|   slope of the pullup table from 0 to 0.27 V, typ, clamps not added: 55.3 ohm
|   GND clamp passes 1 mA (typ) near -0.54 V on its own axis
|   POWER clamp passes 1 mA (typ) near -0.44 V on its own axis
|   rising waveform, R_fixture 50, V_fixture 1.8: 20-80 % time 180ps typ, 348ps min, 111ps max; typ from 0.946 V to 1.8 V
|   rising waveform, R_fixture 50, V_fixture 0: 20-80 % time 262ps typ, 471ps min, 145ps max; typ from 0 V to 0.84 V
|   falling waveform, R_fixture 50, V_fixture 1.8: 20-80 % time 186ps typ, 311ps min, 127ps max; typ from 1.8 V to 0.946 V
|   falling waveform, R_fixture 50, V_fixture 0: 20-80 % time 223ps typ, 421ps min, 133ps max; typ from 0.839 V to 0 V
| Nom Voltages:
|   BIASFET=1.8, VBBNW=1.1, VDD=1.1, VDDS=1.8, VSS=0, VSSS=0
| Min Voltages:
|   BIASFET=1.62, VBBNW=0.99, VDD=0.99, VDDS=1.62, VSS=0, VSSS=0
| Max Voltages:
|   BIASFET=1.95, VBBNW=1.21, VDD=1.21, VDDS=1.95, VSS=0, VSSS=0
[POWER_clamp]
|   voltage   I(typ)   I(min)   I(max)
-1.8V     178.9mA    128mA      243.2mA
-1.291V   75.77mA    51.65mA    107.4mA
-1.255V   68.99mA    46.64mA    97.97mA
-1.145V   49.38mA    32.56mA    70.53mA
-1.073V   37.36mA    24.29mA    53.43mA
-1.036V   31.7mA     20.5mA     45.29mA
-963.6mV  22.4mA     14.45mA    31.67mA
-890.9mV  15.91mA    10.19mA    22.4mA
-781.8mV  10.46mA    6.424mA    15.12mA
-527.3mV  2.642mA    1.569mA    3.825mA
-309.1mV  87.37uA    67.92uA    72.68uA
1.8V      -19.86uA   -9.301uA   -38.48uA
[Pulldown]
|   voltage   I(typ)   I(min)   I(max)
-1.8V     -8.878mA   -4.872mA   -9.522mA
-1.036V   -12.28mA   -8.398mA   -12.99mA
-763.6mV  -11.99mA   -8.933mA   -12.66mA
-545.5mV  -10.21mA   -7.811mA   -10.92mA
545.5mV   10.19mA    7.571mA    11.19mA
1.2V      21.1mA     15.12mA    23.61mA
1.745V    28.05mA    18.59mA    32.31mA
2.182V    30.51mA    18.15mA    36.58mA
2.345V    29.85mA    16.74mA    37.2mA
2.564V    27.64mA    14.26mA    35.81mA
3V        21.33mA    9.076mA    29.49mA
3.6V      14.83mA    5.328mA    21.24mA
[Pullup]
|   voltage   I(typ)   I(min)   I(max)
-1.8V     11.84mA    7.444mA    14.58mA
-1.036V   11.31mA    8.912mA    12.39mA
-709.1mV  10.03mA    8.014mA    11.04mA
-436.4mV  7.65mA     6.042mA    8.559mA
600mV     -10.69mA   -8.267mA   -12.11mA
1.309V    -22.27mA   -16.8mA    -25.64mA
1.964V    -31.22mA   -22.44mA   -36.85mA
2.291V    -34.49mA   -22.7mA    -41.67mA
2.509V    -34.31mA   -20.15mA   -43.79mA
2.727V    -31.88mA   -16.52mA   -43.2mA
3.218V    -23.12mA   -8.08mA    -35.4mA
3.6V      -15.38mA   -5.348mA   -28.49mA
[GND_clamp]
|   voltage   I(typ)   I(min)   I(max)
-1.8V     -337.7mA   -206.7mA   -550.9mA
-1.291V   -133.7mA   -80.77mA   -221.4mA
-1.145V   -81.03mA   -49.16mA   -133.6mA
-1.073V   -58.22mA   -35.9mA    -94.77mA
-1.036V   -47.89mA   -29.96mA   -77.06mA
-927.3mV  -25.01mA   -16.92mA   -36.9mA
-854.5mV  -15.36mA   -11.15mA   -20.87mA
-781.8mV  -9.067mA   -6.815mA   -12.64mA
-636.4mV  -3.067mA   -2.039mA   -4.983mA
-490.9mV  -377.1uA   -269.8uA   -638.6uA
-381.8mV  -50.69uA   -36.67uA   -84.39uA
1.8V      451.8pA    4.855uA    -6.741uA
[Ramp]
| variable   typ   min   max
dV/dt_f 0.52329862/0.19400049n 0.39329283/0.3205897n 0.59728475/0.12966253n
dV/dt_r 0.50645215/0.26281451n 0.39070748/0.4732133n 0.58931064/0.14668723n
R_load = 50
[Rising Waveform]
R_fixture = 50
V_fixture = 1.8
V_fixture_min = 1.62
V_fixture_max = 1.95
|   time   V(typ)   V(min)   V(max)
0s        946.1mV    978.8mV    975.2mV
600ps     946.1mV    978.8mV    975.2mV
775.9ps   946.1mV    978.8mV    1.802V
854.3ps   978.7mV    978.8mV    1.902V
989.8ps   1.356V     978.8mV    1.941V
1.188ns   1.748V     978.8mV    1.948V
1.35ns    1.781V     1.001V     1.949V
1.821ns   1.796V     1.521V     1.95V
2.032ns   1.797V     1.594V     1.95V
11.2ns    1.8V       1.62V      1.95V
[Rising Waveform]
R_fixture = 50
V_fixture = 0
V_fixture_min = 0
V_fixture_max = 0
|   time   V(typ)   V(min)   V(max)
0s        0V         0V         0V
602.3ps   0V         0V         0V
687ps     0V         0V         184.8mV
858.6ps   12.96mV    0V         830.9mV
1.083ns   346.2mV    0V         961.5mV
1.193ns   584.4mV    0V         967.7mV
1.423ns   802.1mV    15.78mV    972mV
2.277ns   835.8mV    563.1mV    973.6mV
2.585ns   837.2mV    634.7mV    973.6mV
11.2ns    839.8mV    648.2mV    974.1mV
[Falling Waveform]
R_fixture = 50
V_fixture = 1.8
V_fixture_min = 1.62
V_fixture_max = 1.95
|   time   V(typ)   V(min)   V(max)
0s        1.799V     1.619V     1.949V
745.5ps   1.799V     1.619V     1.949V
942.6ps   1.799V     1.619V     1.114V
1.15ns    1.637V     1.619V     985.1mV
1.374ns   1.051V     1.619V     977.3mV
1.584ns   959.2mV    1.619V     975.6mV
1.954ns   951.1mV    1.541V     975mV
2.367ns   948.5mV    1.065V     974.9mV
2.61ns    947.6mV    991.2mV    974.8mV
11.2ns    945.5mV    978.6mV    974.8mV
[Falling Waveform]
R_fixture = 50
V_fixture = 0
V_fixture_min = 0
V_fixture_max = 0
|   time   V(typ)   V(min)   V(max)
0s        839.1mV    648mV      973.4mV
712.1ps   839.1mV    648mV      956.2mV
920.7ps   828.2mV    648mV      134.8mV
1.121ns   477.7mV    648mV      14.47mV
1.294ns   121.4mV    648mV      6.667mV
1.394ns   33.18mV    645.9mV    4.768mV
1.678ns   9.509mV    556mV      2.524mV
2.209ns   4.77mV     78.23mV    0V
2.447ns   3.712mV    11.1mV     0V
11.2ns    0V         0V         0V
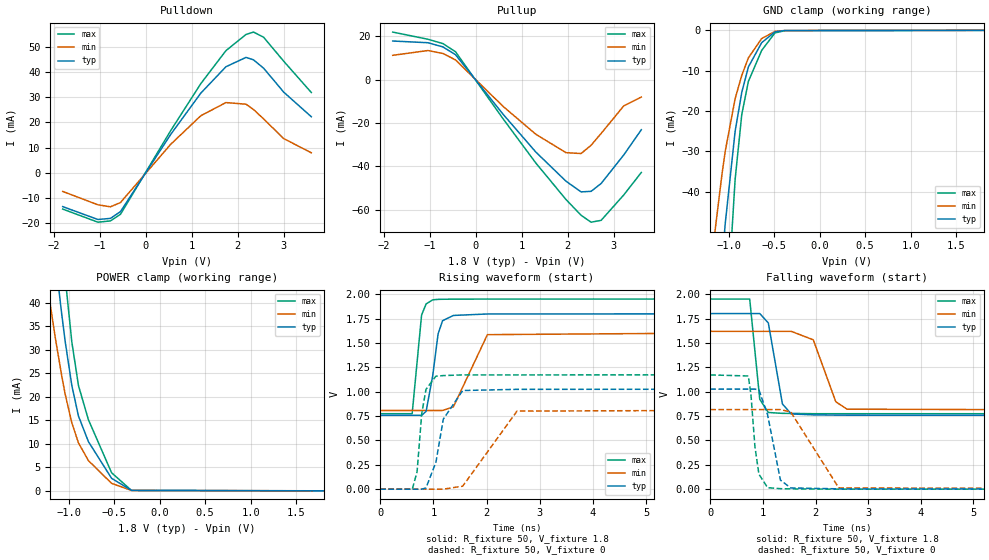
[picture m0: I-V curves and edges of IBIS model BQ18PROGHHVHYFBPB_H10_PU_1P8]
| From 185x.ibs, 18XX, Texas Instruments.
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|   Model Cell BQ18PROGHHVHYFBPB_H10_PU_1P8
|BQ18PROGHHVHYFBPB_H10_PU_1P8
[Model]   BQ18PROGHHVHYFBPB_H10_PU_1P8
Model_type   I/O
Polarity   Non-Inverting
Enable   Active-Low
Vinl =  0.63
Vinh =  1.17
Cref =  15pF
Rref =  100.0000M
Vref =  0V
Vmeas =  0.9
C_comp   2.057622p   1.895389p   2.126353p
[Model Spec]
Vinl   0.63   0.567   0.6825
Vinh   1.17   1.053   1.2675
[Temperature Range]   25   125   -40
[Voltage Range]   1.8   1.62   1.95
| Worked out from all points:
|   slope of the pulldown table from 0 to 0.27 V, typ, clamps not added: 35.1 ohm
|   slope of the pullup table from 0 to 0.27 V, typ, clamps not added: 36.9 ohm
|   GND clamp passes 1 mA (typ) near -0.54 V on its own axis
|   POWER clamp passes 1 mA (typ) near -0.44 V on its own axis
|   rising waveform, R_fixture 50, V_fixture 1.8: 20-80 % time 170ps typ, 338ps min, 99.6ps max; typ from 0.757 V to 1.8 V
|   rising waveform, R_fixture 50, V_fixture 0: 20-80 % time 245ps typ, 464ps min, 124ps max; typ from 0 V to 1.03 V
|   falling waveform, R_fixture 50, V_fixture 1.8: 20-80 % time 177ps typ, 296ps min, 118ps max; typ from 1.8 V to 0.757 V
|   falling waveform, R_fixture 50, V_fixture 0: 20-80 % time 214ps typ, 407ps min, 123ps max; typ from 1.03 V to 0 V
| Nom Voltages:
|   BIASFET=1.8, VBBNW=1.1, VDD=1.1, VDDS=1.8, VSS=0, VSSS=0
| Min Voltages:
|   BIASFET=1.62, VBBNW=0.99, VDD=0.99, VDDS=1.62, VSS=0, VSSS=0
| Max Voltages:
|   BIASFET=1.95, VBBNW=1.21, VDD=1.21, VDDS=1.95, VSS=0, VSSS=0
[POWER_clamp]
|   voltage   I(typ)   I(min)   I(max)
-1.8V     178.9mA    128mA      243.2mA
-1.291V   75.77mA    51.65mA    107.4mA
-1.255V   68.99mA    46.64mA    97.97mA
-1.145V   49.38mA    32.56mA    70.53mA
-1.073V   37.36mA    24.29mA    53.43mA
-1.036V   31.7mA     20.5mA     45.29mA
-963.6mV  22.4mA     14.45mA    31.67mA
-890.9mV  15.91mA    10.19mA    22.4mA
-781.8mV  10.46mA    6.424mA    15.12mA
-527.3mV  2.642mA    1.569mA    3.825mA
-309.1mV  87.37uA    67.92uA    72.68uA
1.8V      -19.86uA   -9.301uA   -38.48uA
[Pulldown]
|   voltage   I(typ)   I(min)   I(max)
-1.8V     -13.32mA   -7.309mA   -14.29mA
-1.036V   -18.42mA   -12.6mA    -19.49mA
-763.6mV  -17.99mA   -13.4mA    -18.98mA
-545.5mV  -15.31mA   -11.71mA   -16.37mA
545.5mV   15.26mA    11.35mA    16.77mA
1.2V      31.62mA    22.67mA    35.39mA
1.745V    42.06mA    27.88mA    48.43mA
2.182V    45.77mA    27.23mA    54.85mA
2.345V    44.8mA     25.13mA    55.79mA
2.564V    41.49mA    21.4mA     53.75mA
3V        32.02mA    13.62mA    44.26mA
3.6V      22.26mA    7.993mA    31.86mA
[Pullup]
|   voltage   I(typ)   I(min)   I(max)
-1.8V     17.76mA    11.17mA    21.87mA
-1.036V   16.97mA    13.37mA    18.58mA
-709.1mV  15.04mA    12.02mA    16.56mA
-436.4mV  11.47mA    9.059mA    12.83mA
600mV     -16.02mA   -12.39mA   -18.14mA
1.309V    -33.38mA   -25.19mA   -38.43mA
1.964V    -46.8mA    -33.65mA   -55.23mA
2.291V    -51.71mA   -34.06mA   -62.47mA
2.509V    -51.47mA   -30.25mA   -65.67mA
2.727V    -47.85mA   -24.8mA    -64.82mA
3.218V    -34.72mA   -12.13mA   -53.14mA
3.6V      -23.1mA    -8.023mA   -42.77mA
[GND_clamp]
|   voltage   I(typ)   I(min)   I(max)
-1.8V     -337.7mA   -206.7mA   -550.9mA
-1.291V   -133.7mA   -80.77mA   -221.4mA
-1.145V   -81.03mA   -49.16mA   -133.6mA
-1.073V   -58.22mA   -35.9mA    -94.77mA
-1.036V   -47.89mA   -29.96mA   -77.06mA
-927.3mV  -25.01mA   -16.92mA   -36.9mA
-854.5mV  -15.36mA   -11.15mA   -20.87mA
-781.8mV  -9.067mA   -6.815mA   -12.64mA
-636.4mV  -3.067mA   -2.039mA   -4.983mA
-490.9mV  -377.1uA   -269.8uA   -638.6uA
-381.8mV  -50.69uA   -36.67uA   -84.39uA
1.8V      451.8pA    4.855uA    -6.741uA
[Ramp]
| variable   typ   min   max
dV/dt_f 0.63839798/0.18363879n 0.49775738/0.30728171n 0.72008186/0.12058707n
dV/dt_r 0.61836911/0.24555922n 0.49166646/0.46489159n 0.70834653/0.12489331n
R_load = 50
[Rising Waveform]
R_fixture = 50
V_fixture = 1.8
V_fixture_min = 1.62
V_fixture_max = 1.95
|   time   V(typ)   V(min)   V(max)
0s        757mV      807.2mV    774.1mV
600ps     757mV      807.2mV    774.1mV
777.2ps   757mV      807.2mV    1.786V
862.4ps   798.3mV    807.2mV    1.9V
987.1ps   1.165V     807.2mV    1.942V
1.088ns   1.593V     807.2mV    1.947V
1.172ns   1.728V     807.2mV    1.948V
1.376ns   1.782V     844.2mV    1.949V
2.016ns   1.797V     1.585V     1.95V
11.2ns    1.8V       1.62V      1.95V
[Rising Waveform]
R_fixture = 50
V_fixture = 0
V_fixture_min = 0
V_fixture_max = 0
|   time   V(typ)   V(min)   V(max)
0s        0V         0V         0V
602.7ps   0V         0V         0V
692.5ps   0V         0V         178.6mV
780.1ps   0V         0V         774.1mV
860.1ps   12.5mV     0V         1.024V
1.047ns   276.4mV    0V         1.159V
1.186ns   717.9mV    0V         1.165V
1.551ns   1.012V     30.83mV    1.172V
2.573ns   1.024V     800.8mV    1.172V
11.2ns    1.026V     816.7mV    1.173V
[Falling Waveform]
R_fixture = 50
V_fixture = 1.8
V_fixture_min = 1.62
V_fixture_max = 1.95
|   time   V(typ)   V(min)   V(max)
0s        1.801V     1.619V     1.95V
749.2ps   1.801V     1.619V     1.95V
940.3ps   1.801V     1.619V     922mV
1.103ns   1.705V     1.619V     786.6mV
1.371ns   873.8mV    1.619V     777.5mV
1.538ns   771.7mV    1.619V     777.1mV
1.957ns   762.1mV    1.532V     774.1mV
2.385ns   759.5mV    896.4mV    773.9mV
2.598ns   758.7mV    820.4mV    773.9mV
11.2ns    756.7mV    806.6mV    773.7mV
[Falling Waveform]
R_fixture = 50
V_fixture = 0
V_fixture_min = 0
V_fixture_max = 0
|   time   V(typ)   V(min)   V(max)
0s        1.026V     816.3mV    1.172V
722.6ps   1.026V     816.3mV    1.161V
772.5ps   1.026V     816.3mV    970.7mV
849.3ps   1.026V     816.3mV    431.7mV
924.4ps   1.019V     816.3mV    153.2mV
1.089ns   762.2mV    816.3mV    15.42mV
1.333ns   93.03mV    816.3mV    5.045mV
1.529ns   12.48mV    792mV      2.879mV
2.442ns   3.363mV    12.84mV    0V
11.2ns    0V         0V         0V
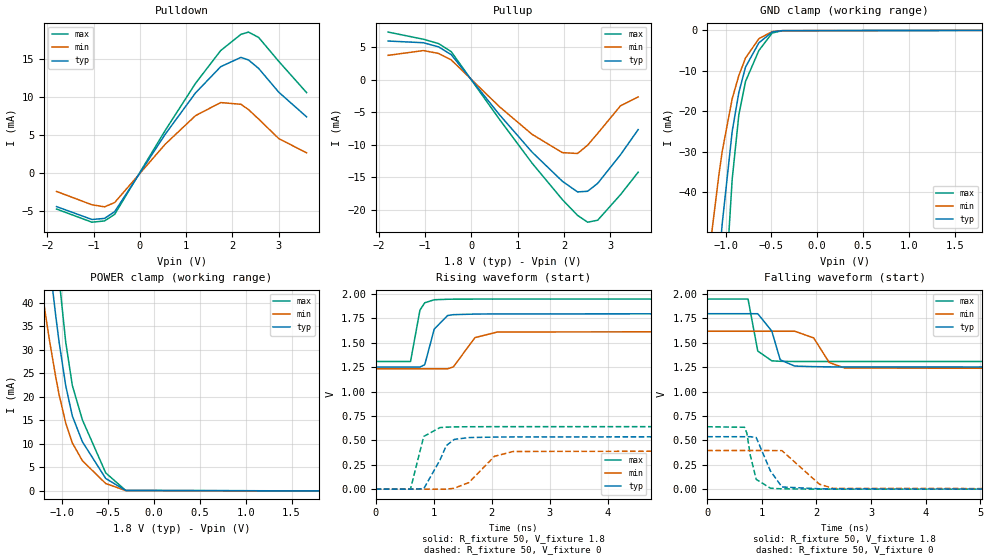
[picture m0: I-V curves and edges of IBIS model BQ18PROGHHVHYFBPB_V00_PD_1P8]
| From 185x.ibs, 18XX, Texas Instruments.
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|   Model Cell BQ18PROGHHVHYFBPB_V00_PD_1P8
|BQ18PROGHHVHYFBPB_V00_PD_1P8
[Model]   BQ18PROGHHVHYFBPB_V00_PD_1P8
Model_type   I/O
Polarity   Non-Inverting
Enable   Active-Low
Vinl =  0.63
Vinh =  1.17
Cref =  15pF
Rref =  100.0000M
Vref =  0V
Vmeas =  0.9
C_comp   2.023746p   1.863846p   2.096173p
[Model Spec]
Vinl   0.63   0.567   0.6825
Vinh   1.17   1.053   1.2675
[Temperature Range]   25   125   -40
[Voltage Range]   1.8   1.62   1.95
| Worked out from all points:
|   slope of the pulldown table from 0 to 0.27 V, typ, clamps not added: 105 ohm
|   slope of the pullup table from 0 to 0.27 V, typ, clamps not added: 110 ohm
|   GND clamp passes 1 mA (typ) near -0.54 V on its own axis
|   POWER clamp passes 1 mA (typ) near -0.44 V on its own axis
|   rising waveform, R_fixture 50, V_fixture 1.8: 20-80 % time 165ps typ, 291ps min, 113ps max; typ from 1.25 V to 1.8 V
|   rising waveform, R_fixture 50, V_fixture 0: 20-80 % time 244ps typ, 372ps min, 152ps max; typ from 0 V to 0.539 V
|   falling waveform, R_fixture 50, V_fixture 1.8: 20-80 % time 188ps typ, 245ps min, 125ps max; typ from 1.8 V to 1.25 V
|   falling waveform, R_fixture 50, V_fixture 0: 20-80 % time 221ps typ, 426ps min, 135ps max; typ from 0.538 V to 0 V
| Nom Voltages:
|   BIASFET=1.8, VBBNW=1.1, VDD=1.1, VDDS=1.8, VSS=0, VSSS=0
| Min Voltages:
|   BIASFET=1.62, VBBNW=0.99, VDD=0.99, VDDS=1.62, VSS=0, VSSS=0
| Max Voltages:
|   BIASFET=1.95, VBBNW=1.21, VDD=1.21, VDDS=1.95, VSS=0, VSSS=0
[POWER_clamp]
|   voltage   I(typ)   I(min)   I(max)
-1.8V     178.9mA    128mA      243.2mA
-1.291V   75.77mA    51.65mA    107.4mA
-1.255V   68.99mA    46.64mA    97.97mA
-1.145V   49.38mA    32.55mA    70.53mA
-1.073V   37.36mA    24.29mA    53.43mA
-1.036V   31.7mA     20.5mA     45.29mA
-963.6mV  22.4mA     14.45mA    31.67mA
-890.9mV  15.91mA    10.19mA    22.4mA
-781.8mV  10.46mA    6.423mA    15.12mA
-527.3mV  2.647mA    1.571mA    3.839mA
-309.1mV  99.61uA    72.86uA    97.96uA
1.8V      -4.125nA   -3.282uA   7.283uA
[Pulldown]
|   voltage   I(typ)   I(min)   I(max)
-1.8V     -4.437mA   -2.435mA   -4.759mA
-1.036V   -6.139mA   -4.198mA   -6.496mA
-763.6mV  -5.999mA   -4.467mA   -6.331mA
-545.5mV  -5.109mA   -3.907mA   -5.464mA
545.5mV   5.097mA    3.788mA    5.6mA
1.2V      10.56mA    7.562mA    11.82mA
1.745V    14.03mA    9.297mA    16.16mA
2.182V    15.26mA    9.07mA     18.3mA
2.345V    14.92mA    8.367mA    18.6mA
2.564V    13.81mA    7.124mA    17.9mA
3V        10.66mA    4.536mA    14.73mA
3.6V      7.413mA    2.663mA    10.61mA
[Pullup]
|   voltage   I(typ)   I(min)   I(max)
-1.8V     5.919mA    3.721mA    7.292mA
-1.036V   5.658mA    4.456mA    6.194mA
-709.1mV  5.017mA    4.008mA    5.523mA
-436.4mV  3.827mA    3.023mA    4.283mA
600mV     -5.351mA   -4.136mA   -6.059mA
1.309V    -11.14mA   -8.407mA   -12.83mA
1.964V    -15.62mA   -11.22mA   -18.44mA
2.291V    -17.25mA   -11.35mA   -20.85mA
2.509V    -17.15mA   -10.07mA   -21.9mA
2.727V    -15.93mA   -8.253mA   -21.59mA
3.218V    -11.55mA   -4.037mA   -17.68mA
3.6V      -7.684mA   -2.673mA   -14.23mA
[GND_clamp]
|   voltage   I(typ)   I(min)   I(max)
-1.8V     -337.7mA   -206.7mA   -550.8mA
-1.291V   -133.7mA   -80.77mA   -221.4mA
-1.145V   -81.03mA   -49.16mA   -133.6mA
-1.073V   -58.22mA   -35.9mA    -94.76mA
-1.036V   -47.89mA   -29.95mA   -77.05mA
-927.3mV  -25.01mA   -16.92mA   -36.89mA
-854.5mV  -15.36mA   -11.15mA   -20.86mA
-781.8mV  -9.064mA   -6.814mA   -12.63mA
-636.4mV  -3.063mA   -2.038mA   -4.969mA
-490.9mV  -371uA     -267.7uA   -622.4uA
-381.8mV  -42.42uA   -33.66uA   -64.54uA
1.8V      20.98uA    11.87uA    40.26uA
[Ramp]
| variable   typ   min   max
dV/dt_f 0.33671098/0.19749295n  0.2380905/0.2596576n 0.39325396/0.1269039n
dV/dt_r 0.32573421/0.2471601n 0.23966939/0.37485689n 0.38960443/0.15291426n
R_load = 50
[Rising Waveform]
R_fixture = 50
V_fixture = 1.8
V_fixture_min = 1.62
V_fixture_max = 1.95
|   time   V(typ)   V(min)   V(max)
0s        1.252V     1.234V     1.309V
601.3ps   1.252V     1.234V     1.309V
763.2ps   1.252V     1.234V     1.836V
846.5ps   1.277V     1.234V     1.911V
1.009ns   1.641V     1.234V     1.942V
1.239ns   1.78V      1.234V     1.947V
1.337ns   1.789V     1.253V     1.948V
1.711ns   1.795V     1.554V     1.949V
2.092ns   1.797V     1.611V     1.949V
11.2ns    1.799V     1.619V     1.949V
[Rising Waveform]
R_fixture = 50
V_fixture = 0
V_fixture_min = 0
V_fixture_max = 0
|   time   V(typ)   V(min)   V(max)
0s        0V         0V         0V
600ps     0V         0V         0V
828.2ps   4.056mV    0V         540.3mV
1.107ns   297.7mV    0V         631.5mV
1.217ns   446.8mV    0V         635.8mV
1.356ns   510.6mV    9.762mV    638.5mV
1.608ns   529.1mV    68.66mV    640.2mV
2.046ns   534mV      337.1mV    640.8mV
2.367ns   535.7mV    386.2mV    640.8mV
11.2ns    538.7mV    396.4mV    640.9mV
[Falling Waveform]
R_fixture = 50
V_fixture = 1.8
V_fixture_min = 1.62
V_fixture_max = 1.95
|   time   V(typ)   V(min)   V(max)
0s        1.799V     1.619V     1.949V
748.1ps   1.799V     1.619V     1.949V
925.9ps   1.799V     1.619V     1.416V
1.183ns   1.621V     1.619V     1.316V
1.337ns   1.326V     1.619V     1.311V
1.603ns   1.262V     1.619V     1.309V
1.949ns   1.256V     1.551V     1.309V
2.235ns   1.254V     1.298V     1.309V
2.518ns   1.253V     1.242V     1.309V
11.2ns    1.252V     1.234V     1.309V
[Falling Waveform]
R_fixture = 50
V_fixture = 0
V_fixture_min = 0
V_fixture_max = 0
|   time   V(typ)   V(min)   V(max)
0s        538mV      396mV      640.1mV
682.3ps   538mV      396mV      634.7mV
726.9ps   538mV      396mV      573.8mV
788.2ps   538mV      396mV      350.4mV
897.8ps   529.6mV    396mV      100.7mV
1.158ns   186.4mV    396mV      9.753mV
1.369ns   22.33mV    395.1mV    3.314mV
2.056ns   4.211mV    50.34mV    0V
2.306ns   3.04mV     8.711mV    0V
11.2ns    0V         0V         0V
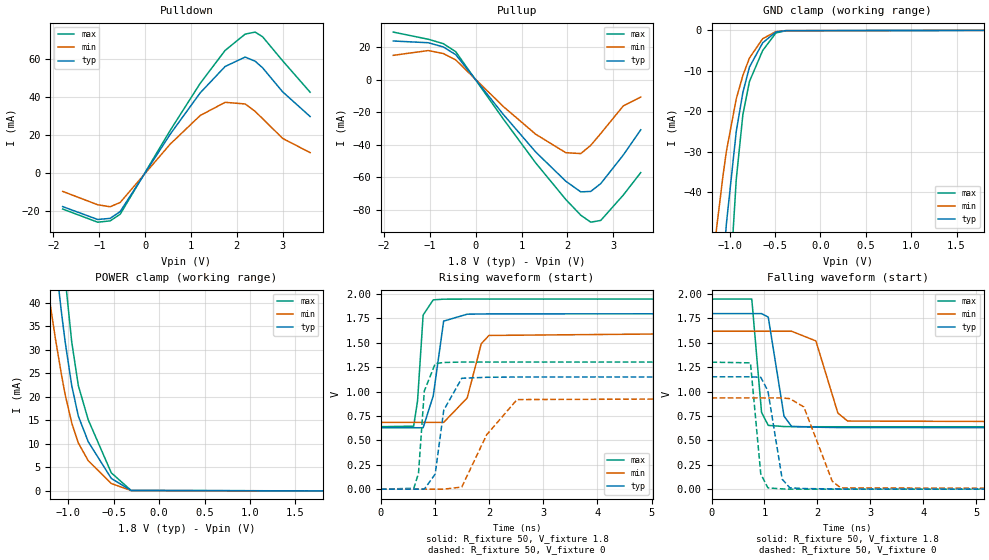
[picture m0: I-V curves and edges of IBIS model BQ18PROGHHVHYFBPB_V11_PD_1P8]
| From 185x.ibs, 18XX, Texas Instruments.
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|   Model Cell BQ18PROGHHVHYFBPB_V11_PD_1P8
|BQ18PROGHHVHYFBPB_V11_PD_1P8
[Model]   BQ18PROGHHVHYFBPB_V11_PD_1P8
Model_type   I/O
Polarity   Non-Inverting
Enable   Active-Low
Vinl =  0.63
Vinh =  1.17
Cref =  15pF
Rref =  100.0000M
Vref =  0V
Vmeas =  0.9
C_comp   2.023746p   1.863846p   2.096173p
[Model Spec]
Vinl   0.63   0.567   0.6825
Vinh   1.17   1.053   1.2675
[Temperature Range]   25   125   -40
[Voltage Range]   1.8   1.62   1.95
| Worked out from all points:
|   slope of the pulldown table from 0 to 0.27 V, typ, clamps not added: 26.3 ohm
|   slope of the pullup table from 0 to 0.27 V, typ, clamps not added: 27.7 ohm
|   GND clamp passes 1 mA (typ) near -0.54 V on its own axis
|   POWER clamp passes 1 mA (typ) near -0.44 V on its own axis
|   rising waveform, R_fixture 50, V_fixture 1.8: 20-80 % time 151ps typ, 309ps min, 83.6ps max; typ from 0.63 V to 1.8 V
|   rising waveform, R_fixture 50, V_fixture 0: 20-80 % time 225ps typ, 434ps min, 105ps max; typ from 0 V to 1.15 V
|   falling waveform, R_fixture 50, V_fixture 1.8: 20-80 % time 171ps typ, 275ps min, 111ps max; typ from 1.8 V to 0.629 V
|   falling waveform, R_fixture 50, V_fixture 0: 20-80 % time 205ps typ, 392ps min, 115ps max; typ from 1.15 V to 0 V
| Nom Voltages:
|   BIASFET=1.8, VBBNW=1.1, VDD=1.1, VDDS=1.8, VSS=0, VSSS=0
| Min Voltages:
|   BIASFET=1.62, VBBNW=0.99, VDD=0.99, VDDS=1.62, VSS=0, VSSS=0
| Max Voltages:
|   BIASFET=1.95, VBBNW=1.21, VDD=1.21, VDDS=1.95, VSS=0, VSSS=0
[POWER_clamp]
|   voltage   I(typ)   I(min)   I(max)
-1.8V     178.9mA    128mA      243.2mA
-1.291V   75.77mA    51.65mA    107.4mA
-1.255V   68.99mA    46.64mA    97.97mA
-1.145V   49.38mA    32.55mA    70.53mA
-1.073V   37.36mA    24.29mA    53.43mA
-1.036V   31.7mA     20.5mA     45.29mA
-963.6mV  22.4mA     14.45mA    31.67mA
-890.9mV  15.91mA    10.19mA    22.4mA
-781.8mV  10.46mA    6.423mA    15.12mA
-527.3mV  2.647mA    1.571mA    3.839mA
-309.1mV  99.61uA    72.86uA    97.96uA
1.8V      -4.125nA   -3.282uA   7.283uA
[Pulldown]
|   voltage   I(typ)   I(min)   I(max)
-1.8V     -17.77mA   -9.748mA   -19.05mA
-1.036V   -24.56mA   -16.8mA    -25.99mA
-763.6mV  -23.98mA   -17.86mA   -25.3mA
-545.5mV  -20.4mA    -15.61mA   -21.81mA
545.5mV   20.33mA    15.12mA    22.33mA
1.2V      42.13mA    30.21mA    47.14mA
1.745V    56.06mA    37.17mA    64.53mA
2.182V    61.03mA    36.32mA    73.12mA
2.4V      58.85mA    32.4mA     74.19mA
2.564V    55.36mA    28.55mA    71.7mA
3V        42.72mA    18.17mA    59.07mA
3.6V      29.69mA    10.66mA    42.5mA
[Pullup]
|   voltage   I(typ)   I(min)   I(max)
-1.8V     23.69mA    14.89mA    29.16mA
-1.036V   22.62mA    17.82mA    24.76mA
-709.1mV  20.05mA    16.02mA    22.07mA
-436.4mV  15.28mA    12.07mA    17.09mA
600mV     -21.35mA   -16.51mA   -24.17mA
1.309V    -44.48mA   -33.57mA   -51.19mA
1.964V    -62.36mA   -44.86mA   -73.59mA
2.291V    -68.93mA   -45.43mA   -83.23mA
2.509V    -68.65mA   -40.36mA   -87.54mA
2.727V    -63.85mA   -33.1mA    -86.46mA
3.218V    -46.34mA   -16.18mA   -70.92mA
3.6V      -30.82mA   -10.7mA    -57.09mA
[GND_clamp]
|   voltage   I(typ)   I(min)   I(max)
-1.8V     -337.7mA   -206.7mA   -550.8mA
-1.291V   -133.7mA   -80.77mA   -221.4mA
-1.145V   -81.03mA   -49.16mA   -133.6mA
-1.073V   -58.22mA   -35.9mA    -94.76mA
-1.036V   -47.89mA   -29.95mA   -77.05mA
-927.3mV  -25.01mA   -16.92mA   -36.89mA
-854.5mV  -15.36mA   -11.15mA   -20.86mA
-781.8mV  -9.064mA   -6.814mA   -12.63mA
-636.4mV  -3.063mA   -2.038mA   -4.969mA
-490.9mV  -371uA     -267.7uA   -622.4uA
-381.8mV  -42.42uA   -33.66uA   -64.54uA
1.8V      20.98uA    11.87uA    40.26uA
[Ramp]
| variable   typ   min   max
dV/dt_f 0.71592462/0.17675867n 0.57198334/0.28742144n 0.80209979/0.11411192n
dV/dt_r 0.69326228/0.22541061n  0.5628769/0.43453714n 0.78615039/0.10523163n
R_load = 50
[Rising Waveform]
R_fixture = 50
V_fixture = 1.8
V_fixture_min = 1.62
V_fixture_max = 1.95
|   time   V(typ)   V(min)   V(max)
0s        630mV      684.6mV    640.6mV
604.3ps   630mV      684.6mV    645.7mV
677.1ps   630mV      684.6mV    905.3mV
780ps     630mV      684.6mV    1.785V
966.8ps   956.5mV    684.6mV    1.941V
1.159ns   1.723V     684.6mV    1.948V
1.594ns   1.794V     935.3mV    1.949V
1.854ns   1.796V     1.491V     1.949V
1.995ns   1.797V     1.576V     1.949V
11.2ns    1.8V       1.62V      1.949V
[Rising Waveform]
R_fixture = 50
V_fixture = 0
V_fixture_min = 0
V_fixture_max = 0
|   time   V(typ)   V(min)   V(max)
0s        0V         0V         0V
607.9ps   0V         0V         8.921mV
694.7ps   0V         0V         163.6mV
801.7ps   0V         0V         1.006V
1.003ns   154.7mV    0V         1.287V
1.161ns   810.2mV    0V         1.299V
1.494ns   1.137V     21.67mV    1.303V
1.952ns   1.147V     556.2mV    1.303V
2.514ns   1.15V      918.5mV    1.303V
11.2ns    1.152V     936mV      1.303V
[Falling Waveform]
R_fixture = 50
V_fixture = 1.8
V_fixture_min = 1.62
V_fixture_max = 1.95
|   time   V(typ)   V(min)   V(max)
0s        1.8V       1.619V     1.949V
760.8ps   1.8V       1.619V     1.949V
945ps     1.8V       1.619V     787.4mV
1.072ns   1.764V     1.619V     653.8mV
1.37ns    749.1mV    1.619V     641.9mV
1.513ns   643.3mV    1.619V     640.7mV
1.972ns   635.2mV    1.52V      640mV
2.388ns   631.7mV    779.4mV    639.9mV
2.572ns   631.1mV    698.4mV    639.9mV
11.2ns    629.3mV    684.4mV    639.9mV
[Falling Waveform]
R_fixture = 50
V_fixture = 0
V_fixture_min = 0
V_fixture_max = 0
|   time   V(typ)   V(min)   V(max)
0s        1.152V     935.4mV    1.302V
735.9ps   1.152V     935.4mV    1.295V
930.6ps   1.147V     935.4mV    155.6mV
1.066ns   1.007V     935.4mV    12.76mV
1.336ns   101.8mV    935.4mV    2.807mV
1.48ns    13.64mV    927.9mV    0V
1.745ns   6.092mV    842.9mV    0V
2.282ns   2.732mV    80.31mV    0V
2.444ns   2.199mV    13.39mV    0V
11.2ns    0V         0V         0V
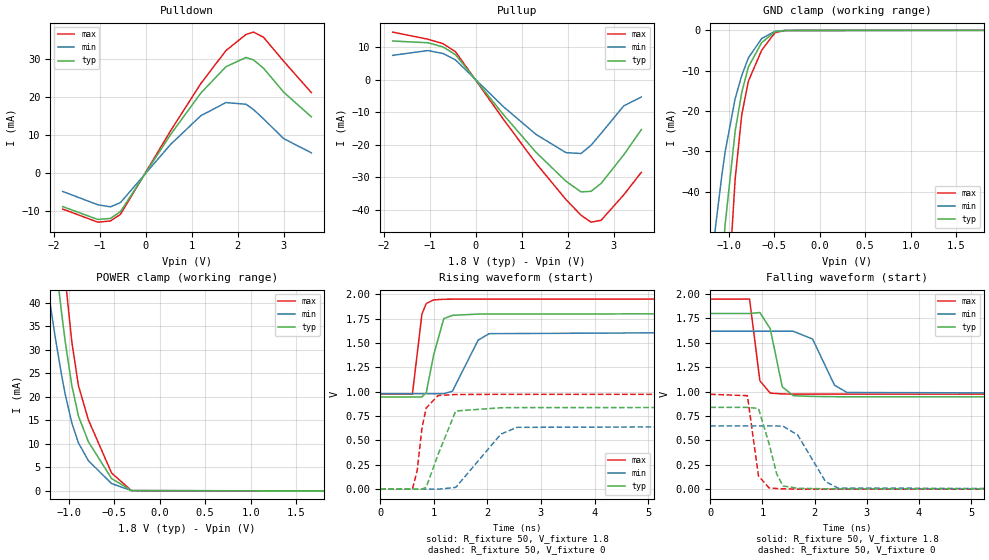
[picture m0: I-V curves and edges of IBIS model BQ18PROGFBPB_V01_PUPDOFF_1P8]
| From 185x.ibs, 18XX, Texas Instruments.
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|   Model Cell BQ18PROGFBPB_V01_PUPDOFF_1P8
|BQ18PROGFBPB_V01_PUPDOFF_1P8
[Model]   BQ18PROGFBPB_V01_PUPDOFF_1P8
Model_type   I/O
Polarity   Non-Inverting
Enable   Active-Low
Vinl =  0.63
Vinh =  1.17
Cref =  15pF
Rref =  100.0000M
Vref =  0V
Vmeas =  0.9
C_comp   2.023746p   1.863846p   2.096173p
[Model Spec]
Vinl   0.63   0.567   0.6825
Vinh   1.17   1.053   1.2675
[Temperature Range]   25   125   -40
[Voltage Range]   1.8   1.62   1.95
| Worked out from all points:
|   slope of the pulldown table from 0 to 0.27 V, typ, clamps not added: 52.6 ohm
|   slope of the pullup table from 0 to 0.27 V, typ, clamps not added: 55.3 ohm
|   GND clamp passes 1 mA (typ) near -0.54 V on its own axis
|   POWER clamp passes 1 mA (typ) near -0.44 V on its own axis
|   rising waveform, R_fixture 50, V_fixture 1.8: 20-80 % time 178ps typ, 354ps min, 109ps max; typ from 0.946 V to 1.8 V
|   rising waveform, R_fixture 50, V_fixture 0: 20-80 % time 255ps typ, 460ps min, 142ps max; typ from 0 V to 0.839 V
|   falling waveform, R_fixture 50, V_fixture 1.8: 20-80 % time 188ps typ, 320ps min, 127ps max; typ from 1.8 V to 0.945 V
|   falling waveform, R_fixture 50, V_fixture 0: 20-80 % time 222ps typ, 422ps min, 132ps max; typ from 0.839 V to 0 V
| Nom Voltages:
|   BIASFET=1.8, VBBNW=1.1, VDD=1.1, VDDS=1.8, VSS=0, VSSS=0
| Min Voltages:
|   BIASFET=1.62, VBBNW=0.99, VDD=0.99, VDDS=1.62, VSS=0, VSSS=0
| Max Voltages:
|   BIASFET=1.95, VBBNW=1.21, VDD=1.21, VDDS=1.95, VSS=0, VSSS=0
[POWER_clamp]
|   voltage   I(typ)   I(min)   I(max)
-1.8V     178.9mA    128mA      243.2mA
-1.291V   75.76mA    51.65mA    107.4mA
-1.255V   68.98mA    46.64mA    97.96mA
-1.145V   49.38mA    32.55mA    70.53mA
-1.073V   37.35mA    24.29mA    53.42mA
-1.036V   31.7mA     20.49mA    45.27mA
-963.6mV  22.39mA    14.45mA    31.64mA
-890.9mV  15.9mA     10.19mA    22.36mA
-781.8mV  10.44mA    6.418mA    15.08mA
-527.3mV  2.627mA    1.561mA    3.8mA
-309.1mV  78.64uA    63.19uA    57.71uA
1.8V      -4.158nA   -210nA     -5.748nA
[Pulldown]
|   voltage   I(typ)   I(min)   I(max)
-1.8V     -8.878mA   -4.872mA   -9.522mA
-1.036V   -12.28mA   -8.398mA   -12.99mA
-763.6mV  -11.99mA   -8.933mA   -12.66mA
-545.5mV  -10.21mA   -7.811mA   -10.92mA
545.5mV   10.19mA    7.571mA    11.19mA
1.2V      21.1mA     15.12mA    23.61mA
1.745V    28.05mA    18.59mA    32.31mA
2.182V    30.51mA    18.15mA    36.58mA
2.345V    29.85mA    16.74mA    37.2mA
2.564V    27.64mA    14.26mA    35.81mA
3V        21.33mA    9.076mA    29.49mA
3.6V      14.83mA    5.328mA    21.24mA
[Pullup]
|   voltage   I(typ)   I(min)   I(max)
-1.8V     11.84mA    7.444mA    14.58mA
-1.036V   11.31mA    8.912mA    12.39mA
-709.1mV  10.03mA    8.014mA    11.04mA
-436.4mV  7.65mA     6.042mA    8.559mA
600mV     -10.69mA   -8.267mA   -12.11mA
1.309V    -22.27mA   -16.8mA    -25.64mA
1.964V    -31.22mA   -22.44mA   -36.85mA
2.291V    -34.49mA   -22.7mA    -41.67mA
2.509V    -34.31mA   -20.15mA   -43.79mA
2.727V    -31.88mA   -16.52mA   -43.2mA
3.218V    -23.12mA   -8.08mA    -35.4mA
3.6V      -15.38mA   -5.348mA   -28.49mA
[GND_clamp]
|   voltage   I(typ)   I(min)   I(max)
-1.8V     -337.7mA   -206.7mA   -550.8mA
-1.291V   -133.7mA   -80.77mA   -221.4mA
-1.145V   -81.03mA   -49.16mA   -133.6mA
-1.073V   -58.22mA   -35.89mA   -94.75mA
-1.036V   -47.89mA   -29.95mA   -77.04mA
-927.3mV  -25.01mA   -16.92mA   -36.88mA
-854.5mV  -15.35mA   -11.15mA   -20.84mA
-781.8mV  -9.051mA   -6.811mA   -12.6mA
-636.4mV  -3.048mA   -2.032mA   -4.945mA
-490.9mV  -357.6uA   -261.1uA   -600.3uA
-381.8mV  -30.89uA   -27.8uA    -45.52uA
1.8V      460.3pA    2.186uA    3.34nA
[Ramp]
| variable   typ   min   max
dV/dt_f 0.52344967/0.19484218n 0.39336708/0.33023955n 0.59805676/0.12977931n
dV/dt_r  0.5059813/0.25553375n 0.39051218/0.46243441n 0.58877073/0.14331561n
R_load = 50
[Rising Waveform]
R_fixture = 50
V_fixture = 1.8
V_fixture_min = 1.62
V_fixture_max = 1.95
|   time   V(typ)   V(min)   V(max)
0s        946.1mV    979mV      974.6mV
600ps     946.1mV    979mV      974.6mV
778.1ps   946.1mV    979mV      1.798V
859.8ps   991.9mV    979mV      1.905V
994.2ps   1.371V     979mV      1.941V
1.185ns   1.749V     979mV      1.948V
1.348ns   1.783V     1.005V     1.949V
1.826ns   1.796V     1.528V     1.95V
2.031ns   1.797V     1.595V     1.95V
11.2ns    1.8V       1.62V      1.95V
[Rising Waveform]
R_fixture = 50
V_fixture = 0
V_fixture_min = 0
V_fixture_max = 0
|   time   V(typ)   V(min)   V(max)
0s        0V         0V         0V
600ps     0V         0V         0V
688.8ps   0V         0V         189.3mV
779.6ps   0V         0V         632.9mV
856.7ps   18.87mV    0V         832.4mV
1.08ns    357.3mV    0V         960.6mV
1.409ns   801.5mV    17.88mV    971.1mV
2.252ns   835.3mV    564.7mV    972.7mV
2.553ns   836.6mV    634.3mV    972.8mV
11.2ns    839.4mV    648mV      973.3mV
[Falling Waveform]
R_fixture = 50
V_fixture = 1.8
V_fixture_min = 1.62
V_fixture_max = 1.95
|   time   V(typ)   V(min)   V(max)
0s        1.801V     1.619V     1.949V
753.2ps   1.801V     1.619V     1.949V
950.9ps   1.811V     1.619V     1.112V
1.149ns   1.646V     1.619V     985mV
1.38ns    1.05V      1.619V     976.5mV
1.591ns   958.5mV    1.619V     974.8mV
1.962ns   950.7mV    1.539V     974.1mV
2.382ns   948mV      1.066V     974mV
2.622ns   947.1mV    991mV      974mV
11.2ns    945.1mV    978.4mV    973.9mV
[Falling Waveform]
R_fixture = 50
V_fixture = 0
V_fixture_min = 0
V_fixture_max = 0
|   time   V(typ)   V(min)   V(max)
0s        838.6mV    647.7mV    972.6mV
712ps     838.6mV    647.7mV    958.5mV
924.2ps   827mV      647.7mV    135.1mV
1.127ns   467.5mV    647.7mV    13.26mV
1.274ns   156.1mV    647.7mV    6.324mV
1.394ns   33.14mV    646.1mV    3.872mV
1.677ns   9.003mV    554.6mV    0V
2.21ns    4.263mV    77.94mV    0V
2.449ns   3.207mV    10.95mV    0V
11.2ns    0V         0V         0V
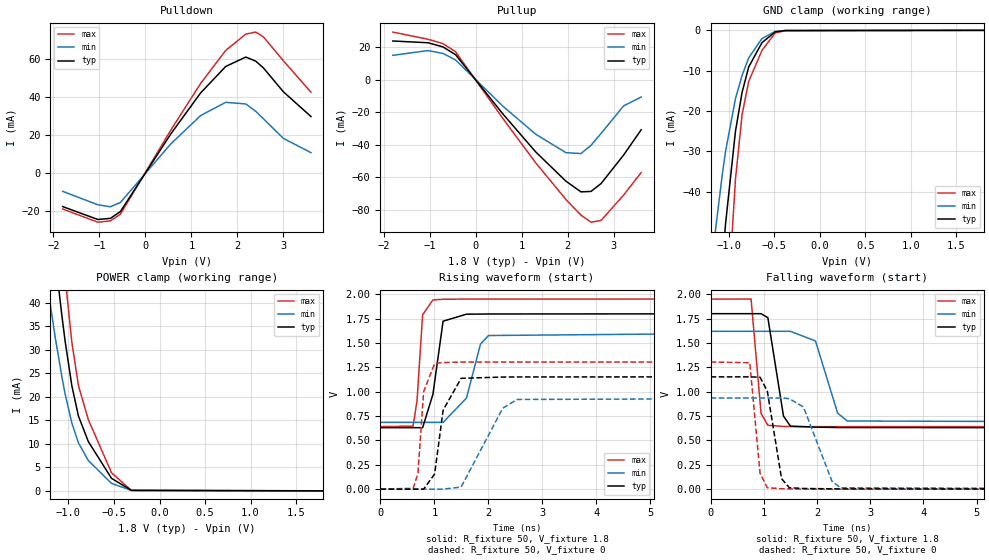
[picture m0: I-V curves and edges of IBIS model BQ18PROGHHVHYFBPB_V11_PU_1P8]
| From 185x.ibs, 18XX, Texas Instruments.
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|   Model Cell BQ18PROGHHVHYFBPB_V11_PU_1P8
|BQ18PROGHHVHYFBPB_V11_PU_1P8
[Model]   BQ18PROGHHVHYFBPB_V11_PU_1P8
Model_type   I/O
Polarity   Non-Inverting
Enable   Active-Low
Vinl =  0.63
Vinh =  1.17
Cref =  15pF
Rref =  100.0000M
Vref =  0V
Vmeas =  0.9
C_comp   2.023746p   1.863846p   2.096173p
[Model Spec]
Vinl   0.63   0.567   0.6825
Vinh   1.17   1.053   1.2675
[Temperature Range]   25   125   -40
[Voltage Range]   1.8   1.62   1.95
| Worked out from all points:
|   slope of the pulldown table from 0 to 0.27 V, typ, clamps not added: 26.3 ohm
|   slope of the pullup table from 0 to 0.27 V, typ, clamps not added: 27.7 ohm
|   GND clamp passes 1 mA (typ) near -0.54 V on its own axis
|   POWER clamp passes 1 mA (typ) near -0.44 V on its own axis
|   rising waveform, R_fixture 50, V_fixture 1.8: 20-80 % time 151ps typ, 309ps min, 83.7ps max; typ from 0.631 V to 1.8 V
|   rising waveform, R_fixture 50, V_fixture 0: 20-80 % time 225ps typ, 434ps min, 105ps max; typ from 0 V to 1.15 V
|   falling waveform, R_fixture 50, V_fixture 1.8: 20-80 % time 171ps typ, 275ps min, 111ps max; typ from 1.8 V to 0.63 V
|   falling waveform, R_fixture 50, V_fixture 0: 20-80 % time 205ps typ, 392ps min, 115ps max; typ from 1.15 V to 0 V
| Nom Voltages:
|   BIASFET=1.8, VBBNW=1.1, VDD=1.1, VDDS=1.8, VSS=0, VSSS=0
| Min Voltages:
|   BIASFET=1.62, VBBNW=0.99, VDD=0.99, VDDS=1.62, VSS=0, VSSS=0
| Max Voltages:
|   BIASFET=1.95, VBBNW=1.21, VDD=1.21, VDDS=1.95, VSS=0, VSSS=0
[POWER_clamp]
|   voltage   I(typ)   I(min)   I(max)
-1.8V     178.9mA    128mA      243.2mA
-1.291V   75.77mA    51.65mA    107.4mA
-1.255V   68.99mA    46.64mA    97.97mA
-1.145V   49.38mA    32.56mA    70.53mA
-1.073V   37.36mA    24.29mA    53.43mA
-1.036V   31.7mA     20.5mA     45.29mA
-963.6mV  22.4mA     14.45mA    31.67mA
-890.9mV  15.91mA    10.19mA    22.4mA
-781.8mV  10.46mA    6.424mA    15.12mA
-527.3mV  2.642mA    1.569mA    3.825mA
-309.1mV  87.37uA    67.92uA    72.68uA
1.8V      -19.86uA   -9.301uA   -38.48uA
[Pulldown]
|   voltage   I(typ)   I(min)   I(max)
-1.8V     -17.77mA   -9.748mA   -19.05mA
-1.036V   -24.56mA   -16.8mA    -25.99mA
-763.6mV  -23.98mA   -17.86mA   -25.3mA
-545.5mV  -20.4mA    -15.61mA   -21.81mA
545.5mV   20.33mA    15.12mA    22.33mA
1.2V      42.13mA    30.21mA    47.14mA
1.745V    56.06mA    37.17mA    64.53mA
2.182V    61.03mA    36.32mA    73.12mA
2.4V      58.85mA    32.4mA     74.19mA
2.564V    55.35mA    28.55mA    71.7mA
3V        42.72mA    18.17mA    59.07mA
3.6V      29.69mA    10.66mA    42.5mA
[Pullup]
|   voltage   I(typ)   I(min)   I(max)
-1.8V     23.69mA    14.89mA    29.16mA
-1.036V   22.62mA    17.82mA    24.76mA
-709.1mV  20.05mA    16.02mA    22.07mA
-436.4mV  15.28mA    12.07mA    17.09mA
600mV     -21.35mA   -16.51mA   -24.17mA
1.309V    -44.48mA   -33.57mA   -51.19mA
1.964V    -62.36mA   -44.86mA   -73.59mA
2.291V    -68.93mA   -45.43mA   -83.23mA
2.509V    -68.65mA   -40.36mA   -87.54mA
2.727V    -63.85mA   -33.1mA    -86.46mA
3.218V    -46.34mA   -16.18mA   -70.92mA
3.6V      -30.82mA   -10.7mA    -57.09mA
[GND_clamp]
|   voltage   I(typ)   I(min)   I(max)
-1.8V     -337.7mA   -206.7mA   -550.9mA
-1.291V   -133.7mA   -80.77mA   -221.4mA
-1.145V   -81.03mA   -49.16mA   -133.6mA
-1.073V   -58.22mA   -35.9mA    -94.77mA
-1.036V   -47.89mA   -29.96mA   -77.06mA
-927.3mV  -25.01mA   -16.92mA   -36.9mA
-854.5mV  -15.36mA   -11.15mA   -20.87mA
-781.8mV  -9.067mA   -6.815mA   -12.64mA
-636.4mV  -3.067mA   -2.039mA   -4.983mA
-490.9mV  -377.1uA   -269.8uA   -638.6uA
-381.8mV  -50.69uA   -36.67uA   -84.39uA
1.8V      451.8pA    4.855uA    -6.741uA
[Ramp]
| variable   typ   min   max
dV/dt_f 0.71577256/0.17663125n 0.57188015/0.28728471n 0.80184326/0.11412022n
dV/dt_r 0.69343427/0.22549232n 0.56297665/0.43460794n 0.78641943/0.10529604n
R_load = 50
[Rising Waveform]
R_fixture = 50
V_fixture = 1.8
V_fixture_min = 1.62
V_fixture_max = 1.95
|   time   V(typ)   V(min)   V(max)
0s        630.6mV    684.9mV    641.7mV
604.3ps   630.6mV    684.9mV    646.7mV
677.1ps   630.6mV    684.9mV    906.7mV
781ps     630.6mV    684.9mV    1.789V
971.5ps   972.9mV    684.9mV    1.941V
1.16ns    1.723V     684.9mV    1.948V
1.594ns   1.795V     935.7mV    1.95V
1.853ns   1.796V     1.489V     1.95V
2.001ns   1.797V     1.576V     1.95V
11.2ns    1.8V       1.62V      1.95V
[Rising Waveform]
R_fixture = 50
V_fixture = 0
V_fixture_min = 0
V_fixture_max = 0
|   time   V(typ)   V(min)   V(max)
0s        0V         0V         0V
607.9ps   0V         0V         9.548mV
694.7ps   0V         0V         164.5mV
799.9ps   0V         0V         1.001V
1.003ns   155.2mV    0V         1.288V
1.161ns   810.8mV    0V         1.299V
1.494ns   1.137V     21.87mV    1.304V
2.265ns   1.15V      830.1mV    1.304V
2.529ns   1.151V     920.1mV    1.304V
11.2ns    1.153V     936.3mV    1.304V
[Falling Waveform]
R_fixture = 50
V_fixture = 1.8
V_fixture_min = 1.62
V_fixture_max = 1.95
|   time   V(typ)   V(min)   V(max)
0s        1.8V       1.619V     1.95V
760.7ps   1.8V       1.619V     1.95V
947.9ps   1.8V       1.619V     777.7mV
1.076ns   1.759V     1.619V     655.6mV
1.37ns    749.7mV    1.619V     643.6mV
1.501ns   646mV      1.619V     642.3mV
1.972ns   636.2mV    1.52V      641.3mV
2.388ns   632.5mV    780.2mV    641.2mV
2.568ns   631.9mV    699.4mV    641.1mV
11.2ns    630mV      684.8mV    640.9mV
[Falling Waveform]
R_fixture = 50
V_fixture = 0
V_fixture_min = 0
V_fixture_max = 0
|   time   V(typ)   V(min)   V(max)
0s        1.152V     935.8mV    1.304V
735.9ps   1.152V     935.8mV    1.297V
929.3ps   1.148V     935.8mV    163.1mV
1.066ns   1.006V     935.8mV    14.73mV
1.334ns   107.7mV    935.8mV    4.354mV
1.48ns    14.88mV    928.2mV    2.792mV
1.745ns   7.077mV    843.4mV    0V
2.282ns   3.484mV    81.29mV    0V
2.443ns   2.923mV    14.12mV    0V
11.2ns    0V         0V         0V
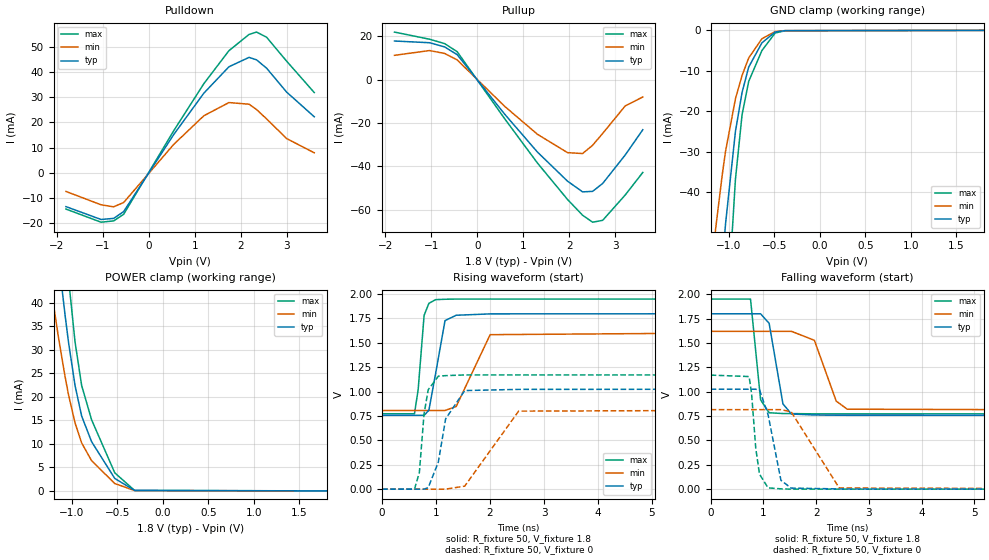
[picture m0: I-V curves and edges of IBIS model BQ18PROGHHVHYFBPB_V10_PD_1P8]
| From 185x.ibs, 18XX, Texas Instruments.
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|   Model Cell BQ18PROGHHVHYFBPB_V10_PD_1P8
|BQ18PROGHHVHYFBPB_V10_PD_1P8
[Model]   BQ18PROGHHVHYFBPB_V10_PD_1P8
Model_type   I/O
Polarity   Non-Inverting
Enable   Active-Low
Vinl =  0.63
Vinh =  1.17
Cref =  15pF
Rref =  100.0000M
Vref =  0V
Vmeas =  0.9
C_comp   2.023746p   1.863846p   2.096173p
[Model Spec]
Vinl   0.63   0.567   0.6825
Vinh   1.17   1.053   1.2675
[Temperature Range]   25   125   -40
[Voltage Range]   1.8   1.62   1.95
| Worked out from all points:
|   slope of the pulldown table from 0 to 0.27 V, typ, clamps not added: 35.1 ohm
|   slope of the pullup table from 0 to 0.27 V, typ, clamps not added: 36.9 ohm
|   GND clamp passes 1 mA (typ) near -0.54 V on its own axis
|   POWER clamp passes 1 mA (typ) near -0.44 V on its own axis
|   rising waveform, R_fixture 50, V_fixture 1.8: 20-80 % time 165ps typ, 333ps min, 95.5ps max; typ from 0.757 V to 1.8 V
|   rising waveform, R_fixture 50, V_fixture 0: 20-80 % time 238ps typ, 448ps min, 122ps max; typ from 0 V to 1.03 V
|   falling waveform, R_fixture 50, V_fixture 1.8: 20-80 % time 176ps typ, 293ps min, 116ps max; typ from 1.8 V to 0.756 V
|   falling waveform, R_fixture 50, V_fixture 0: 20-80 % time 212ps typ, 405ps min, 121ps max; typ from 1.02 V to 0 V
| Nom Voltages:
|   BIASFET=1.8, VBBNW=1.1, VDD=1.1, VDDS=1.8, VSS=0, VSSS=0
| Min Voltages:
|   BIASFET=1.62, VBBNW=0.99, VDD=0.99, VDDS=1.62, VSS=0, VSSS=0
| Max Voltages:
|   BIASFET=1.95, VBBNW=1.21, VDD=1.21, VDDS=1.95, VSS=0, VSSS=0
[POWER_clamp]
|   voltage   I(typ)   I(min)   I(max)
-1.8V     178.9mA    128mA      243.2mA
-1.291V   75.77mA    51.65mA    107.4mA
-1.255V   68.99mA    46.64mA    97.97mA
-1.145V   49.38mA    32.55mA    70.53mA
-1.073V   37.36mA    24.29mA    53.43mA
-1.036V   31.7mA     20.5mA     45.29mA
-963.6mV  22.4mA     14.45mA    31.67mA
-890.9mV  15.91mA    10.19mA    22.4mA
-781.8mV  10.46mA    6.423mA    15.12mA
-527.3mV  2.647mA    1.571mA    3.839mA
-309.1mV  99.61uA    72.86uA    97.96uA
1.8V      -4.125nA   -3.282uA   7.283uA
[Pulldown]
|   voltage   I(typ)   I(min)   I(max)
-1.8V     -13.32mA   -7.309mA   -14.29mA
-1.036V   -18.42mA   -12.6mA    -19.49mA
-763.6mV  -17.99mA   -13.4mA    -18.98mA
-545.5mV  -15.31mA   -11.71mA   -16.37mA
545.5mV   15.26mA    11.35mA    16.77mA
1.2V      31.62mA    22.67mA    35.39mA
1.745V    42.06mA    27.88mA    48.43mA
2.182V    45.77mA    27.23mA    54.85mA
2.345V    44.8mA     25.13mA    55.79mA
2.564V    41.49mA    21.4mA     53.75mA
3V        32.02mA    13.62mA    44.26mA
3.6V      22.26mA    7.993mA    31.86mA
[Pullup]
|   voltage   I(typ)   I(min)   I(max)
-1.8V     17.76mA    11.17mA    21.87mA
-1.036V   16.97mA    13.37mA    18.58mA
-709.1mV  15.04mA    12.02mA    16.56mA
-436.4mV  11.47mA    9.059mA    12.83mA
600mV     -16.02mA   -12.39mA   -18.14mA
1.309V    -33.38mA   -25.19mA   -38.43mA
1.964V    -46.8mA    -33.65mA   -55.23mA
2.291V    -51.71mA   -34.06mA   -62.47mA
2.509V    -51.47mA   -30.25mA   -65.67mA
2.727V    -47.85mA   -24.8mA    -64.82mA
3.218V    -34.72mA   -12.13mA   -53.14mA
3.6V      -23.1mA    -8.023mA   -42.77mA
[GND_clamp]
|   voltage   I(typ)   I(min)   I(max)
-1.8V     -337.7mA   -206.7mA   -550.8mA
-1.291V   -133.7mA   -80.77mA   -221.4mA
-1.145V   -81.03mA   -49.16mA   -133.6mA
-1.073V   -58.22mA   -35.9mA    -94.76mA
-1.036V   -47.89mA   -29.95mA   -77.05mA
-927.3mV  -25.01mA   -16.92mA   -36.89mA
-854.5mV  -15.36mA   -11.15mA   -20.86mA
-781.8mV  -9.064mA   -6.814mA   -12.63mA
-636.4mV  -3.063mA   -2.038mA   -4.969mA
-490.9mV  -371uA     -267.7uA   -622.4uA
-381.8mV  -42.42uA   -33.66uA   -64.54uA
1.8V      20.98uA    11.87uA    40.26uA
[Ramp]
| variable   typ   min   max
dV/dt_f 0.63858388/0.18210411n 0.49778914/0.30377606n 0.72067378/0.11891882n
dV/dt_r  0.6175354/0.2389103n 0.49127207/0.44907217n 0.70725412/0.12208471n
R_load = 50
[Rising Waveform]
R_fixture = 50
V_fixture = 1.8
V_fixture_min = 1.62
V_fixture_max = 1.95
|   time   V(typ)   V(min)   V(max)
0s        756.7mV    806.5mV    773.1mV
600ps     756.7mV    806.5mV    773.1mV
668.4ps   756.7mV    806.5mV    1.02V
778.7ps   756.7mV    806.5mV    1.782V
867.3ps   808.9mV    806.5mV    1.905V
991.3ps   1.184V     806.5mV    1.943V
1.166ns   1.728V     806.5mV    1.947V
1.373ns   1.783V     847.4mV    1.949V
2.002ns   1.797V     1.584V     1.949V
11.2ns    1.8V       1.62V      1.949V
[Rising Waveform]
R_fixture = 50
V_fixture = 0
V_fixture_min = 0
V_fixture_max = 0
|   time   V(typ)   V(min)   V(max)
0s        0V         0V         0V
600.5ps   0V         0V         0V
691ps     0V         0V         170.9mV
777.4ps   0V         0V         771.2mV
854.8ps   15.97mV    0V         1.019V
1.042ns   276.5mV    0V         1.158V
1.177ns   720.4mV    0V         1.164V
1.531ns   1.011V     31.28mV    1.171V
2.53ns    1.023V     800mV      1.171V
11.2ns    1.026V     816.4mV    1.171V
[Falling Waveform]
R_fixture = 50
V_fixture = 1.8
V_fixture_min = 1.62
V_fixture_max = 1.95
|   time   V(typ)   V(min)   V(max)
0s        1.799V     1.619V     1.95V
756.8ps   1.799V     1.619V     1.95V
947.5ps   1.799V     1.619V     916.8mV
1.11ns    1.701V     1.619V     783.8mV
1.372ns   874.2mV    1.619V     775.7mV
1.533ns   770.8mV    1.619V     775.2mV
1.968ns   760.8mV    1.527V     772.5mV
2.382ns   758.5mV    903.3mV    772.4mV
2.59ns    757.9mV    820.5mV    772.4mV
11.2ns    755.9mV    806.2mV    772.4mV
[Falling Waveform]
R_fixture = 50
V_fixture = 0
V_fixture_min = 0
V_fixture_max = 0
|   time   V(typ)   V(min)   V(max)
0s        1.025V     816mV      1.17V
730.2ps   1.025V     816mV      1.155V
777.4ps   1.025V     816mV      977.7mV
855.6ps   1.025V     816mV      422.3mV
926.9ps   1.018V     816mV      153.9mV
1.09ns    763.2mV    816mV      13.36mV
1.334ns   90.49mV    816mV      3.363mV
1.528ns   10.93mV    793mV      0V
2.44ns    2.536mV    11.81mV    0V
11.2ns    0V         0V         0V
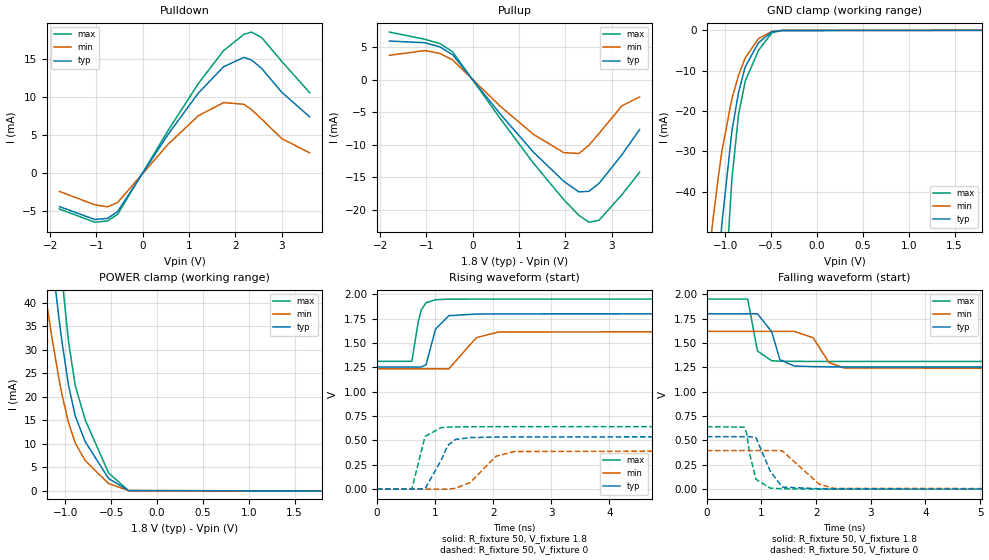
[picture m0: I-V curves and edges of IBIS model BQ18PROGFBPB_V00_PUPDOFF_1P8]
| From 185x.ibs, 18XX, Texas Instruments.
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|   Model Cell BQ18PROGFBPB_V00_PUPDOFF_1P8
|BQ18PROGFBPB_V00_PUPDOFF_1P8
[Model]   BQ18PROGFBPB_V00_PUPDOFF_1P8
Model_type   I/O
Polarity   Non-Inverting
Enable   Active-Low
Vinl =  0.63
Vinh =  1.17
Cref =  15pF
Rref =  100.0000M
Vref =  0V
Vmeas =  0.9
C_comp   2.023746p   1.863846p   2.096173p
[Model Spec]
Vinl   0.63   0.567   0.6825
Vinh   1.17   1.053   1.2675
[Temperature Range]   25   125   -40
[Voltage Range]   1.8   1.62   1.95
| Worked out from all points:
|   slope of the pulldown table from 0 to 0.27 V, typ, clamps not added: 105 ohm
|   slope of the pullup table from 0 to 0.27 V, typ, clamps not added: 110 ohm
|   GND clamp passes 1 mA (typ) near -0.54 V on its own axis
|   POWER clamp passes 1 mA (typ) near -0.44 V on its own axis
|   rising waveform, R_fixture 50, V_fixture 1.8: 20-80 % time 165ps typ, 290ps min, 112ps max; typ from 1.25 V to 1.8 V
|   rising waveform, R_fixture 50, V_fixture 0: 20-80 % time 244ps typ, 372ps min, 152ps max; typ from 0 V to 0.539 V
|   falling waveform, R_fixture 50, V_fixture 1.8: 20-80 % time 188ps typ, 245ps min, 125ps max; typ from 1.8 V to 1.25 V
|   falling waveform, R_fixture 50, V_fixture 0: 20-80 % time 221ps typ, 426ps min, 135ps max; typ from 0.538 V to 0 V
| Nom Voltages:
|   BIASFET=1.8, VBBNW=1.1, VDD=1.1, VDDS=1.8, VSS=0, VSSS=0
| Min Voltages:
|   BIASFET=1.62, VBBNW=0.99, VDD=0.99, VDDS=1.62, VSS=0, VSSS=0
| Max Voltages:
|   BIASFET=1.95, VBBNW=1.21, VDD=1.21, VDDS=1.95, VSS=0, VSSS=0
[POWER_clamp]
|   voltage   I(typ)   I(min)   I(max)
-1.8V     178.9mA    128mA      243.2mA
-1.291V   75.76mA    51.65mA    107.4mA
-1.255V   68.98mA    46.64mA    97.96mA
-1.145V   49.38mA    32.55mA    70.53mA
-1.073V   37.35mA    24.29mA    53.42mA
-1.036V   31.7mA     20.49mA    45.27mA
-963.6mV  22.39mA    14.45mA    31.64mA
-890.9mV  15.9mA     10.19mA    22.36mA
-781.8mV  10.44mA    6.418mA    15.08mA
-527.3mV  2.627mA    1.561mA    3.8mA
-309.1mV  78.64uA    63.19uA    57.71uA
1.8V      -4.158nA   -210nA     -5.748nA
[Pulldown]
|   voltage   I(typ)   I(min)   I(max)
-1.8V     -4.437mA   -2.435mA   -4.759mA
-1.036V   -6.139mA   -4.198mA   -6.496mA
-763.6mV  -5.999mA   -4.467mA   -6.331mA
-545.5mV  -5.109mA   -3.907mA   -5.464mA
545.5mV   5.097mA    3.788mA    5.6mA
1.2V      10.56mA    7.562mA    11.82mA
1.745V    14.03mA    9.297mA    16.16mA
2.182V    15.26mA    9.07mA     18.3mA
2.345V    14.92mA    8.367mA    18.6mA
2.564V    13.81mA    7.124mA    17.9mA
3V        10.66mA    4.536mA    14.73mA
3.6V      7.413mA    2.663mA    10.61mA
[Pullup]
|   voltage   I(typ)   I(min)   I(max)
-1.8V     5.919mA    3.721mA    7.292mA
-1.036V   5.658mA    4.456mA    6.194mA
-709.1mV  5.017mA    4.008mA    5.523mA
-436.4mV  3.827mA    3.023mA    4.283mA
600mV     -5.351mA   -4.136mA   -6.059mA
1.309V    -11.14mA   -8.407mA   -12.83mA
1.964V    -15.62mA   -11.22mA   -18.44mA
2.291V    -17.25mA   -11.35mA   -20.85mA
2.509V    -17.15mA   -10.07mA   -21.9mA
2.727V    -15.93mA   -8.253mA   -21.59mA
3.218V    -11.55mA   -4.037mA   -17.68mA
3.6V      -7.684mA   -2.673mA   -14.23mA
[GND_clamp]
|   voltage   I(typ)   I(min)   I(max)
-1.8V     -337.7mA   -206.7mA   -550.8mA
-1.291V   -133.7mA   -80.77mA   -221.4mA
-1.145V   -81.03mA   -49.16mA   -133.6mA
-1.073V   -58.22mA   -35.89mA   -94.75mA
-1.036V   -47.89mA   -29.95mA   -77.04mA
-927.3mV  -25.01mA   -16.92mA   -36.88mA
-854.5mV  -15.35mA   -11.15mA   -20.84mA
-781.8mV  -9.051mA   -6.811mA   -12.6mA
-636.4mV  -3.048mA   -2.032mA   -4.945mA
-490.9mV  -357.6uA   -261.1uA   -600.3uA
-381.8mV  -30.89uA   -27.8uA    -45.52uA
1.8V      460.3pA    2.186uA    3.34nA
[Ramp]
| variable   typ   min   max
dV/dt_f  0.3367078/0.19733797n 0.23808231/0.25956038n 0.39325664/0.12669416n
dV/dt_r 0.32602391/0.24740059n  0.2397976/0.37509845n 0.39014805/0.15327039n
R_load = 50
[Rising Waveform]
R_fixture = 50
V_fixture = 1.8
V_fixture_min = 1.62
V_fixture_max = 1.95
|   time   V(typ)   V(min)   V(max)
0s        1.253V     1.235V     1.311V
601.3ps   1.253V     1.235V     1.311V
710.9ps   1.253V     1.235V     1.716V
763.2ps   1.253V     1.235V     1.838V
846.5ps   1.277V     1.235V     1.913V
1.009ns   1.642V     1.235V     1.943V
1.239ns   1.78V      1.235V     1.949V
1.711ns   1.796V     1.554V     1.95V
2.092ns   1.798V     1.612V     1.95V
11.2ns    1.8V       1.62V      1.95V
[Rising Waveform]
R_fixture = 50
V_fixture = 0
V_fixture_min = 0
V_fixture_max = 0
|   time   V(typ)   V(min)   V(max)
0s        0V         0V         0V
600ps     0V         0V         0V
828.2ps   4.056mV    0V         540.3mV
1.107ns   297.7mV    0V         631.7mV
1.217ns   446.8mV    0V         636mV
1.357ns   510.8mV    9.934mV    638.7mV
1.608ns   529.2mV    68.66mV    640.4mV
2.046ns   534.1mV    337.1mV    641.1mV
2.367ns   535.8mV    386.2mV    641.2mV
11.2ns    539.1mV    396.6mV    641.8mV
[Falling Waveform]
R_fixture = 50
V_fixture = 1.8
V_fixture_min = 1.62
V_fixture_max = 1.95
|   time   V(typ)   V(min)   V(max)
0s        1.799V     1.619V     1.95V
748.1ps   1.799V     1.619V     1.95V
925.8ps   1.799V     1.619V     1.417V
1.186ns   1.616V     1.619V     1.317V
1.337ns   1.328V     1.619V     1.313V
1.599ns   1.263V     1.619V     1.311V
1.945ns   1.257V     1.553V     1.31V
2.235ns   1.255V     1.298V     1.31V
2.518ns   1.254V     1.243V     1.31V
11.2ns    1.252V     1.234V     1.31V
[Falling Waveform]
R_fixture = 50
V_fixture = 0
V_fixture_min = 0
V_fixture_max = 0
|   time   V(typ)   V(min)   V(max)
0s        538.4mV    396.2mV    641mV
682.3ps   538.4mV    396.2mV    635.6mV
726.9ps   538.4mV    396.2mV    574.8mV
788.2ps   538.4mV    396.2mV    351.4mV
897.9ps   530mV      396.2mV    101.7mV
1.159ns   185.7mV    396.2mV    10.67mV
1.378ns   21.53mV    394.3mV    4.005mV
2.054ns   4.651mV    51.66mV    0V
2.316ns   3.392mV    8.559mV    0V
11.2ns    0V         0V         0V
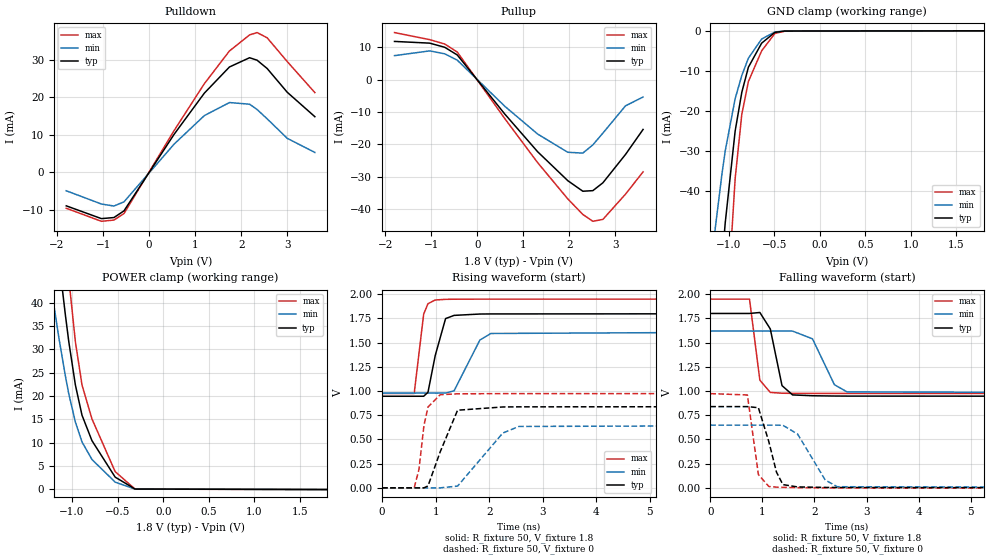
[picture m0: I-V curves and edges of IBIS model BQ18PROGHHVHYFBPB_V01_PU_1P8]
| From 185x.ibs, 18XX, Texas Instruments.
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|   Model Cell BQ18PROGHHVHYFBPB_V01_PU_1P8
|BQ18PROGHHVHYFBPB_V01_PU_1P8
[Model]   BQ18PROGHHVHYFBPB_V01_PU_1P8
Model_type   I/O
Polarity   Non-Inverting
Enable   Active-Low
Vinl =  0.63
Vinh =  1.17
Cref =  15pF
Rref =  100.0000M
Vref =  0V
Vmeas =  0.9
C_comp   2.023746p   1.863846p   2.096173p
[Model Spec]
Vinl   0.63   0.567   0.6825
Vinh   1.17   1.053   1.2675
[Temperature Range]   25   125   -40
[Voltage Range]   1.8   1.62   1.95
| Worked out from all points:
|   slope of the pulldown table from 0 to 0.27 V, typ, clamps not added: 52.6 ohm
|   slope of the pullup table from 0 to 0.27 V, typ, clamps not added: 55.3 ohm
|   GND clamp passes 1 mA (typ) near -0.54 V on its own axis
|   POWER clamp passes 1 mA (typ) near -0.44 V on its own axis
|   rising waveform, R_fixture 50, V_fixture 1.8: 20-80 % time 178ps typ, 354ps min, 109ps max; typ from 0.947 V to 1.8 V
|   rising waveform, R_fixture 50, V_fixture 0: 20-80 % time 255ps typ, 460ps min, 142ps max; typ from 0 V to 0.84 V
|   falling waveform, R_fixture 50, V_fixture 1.8: 20-80 % time 188ps typ, 321ps min, 127ps max; typ from 1.8 V to 0.946 V
|   falling waveform, R_fixture 50, V_fixture 0: 20-80 % time 222ps typ, 422ps min, 132ps max; typ from 0.839 V to 0 V
| Nom Voltages:
|   BIASFET=1.8, VBBNW=1.1, VDD=1.1, VDDS=1.8, VSS=0, VSSS=0
| Min Voltages:
|   BIASFET=1.62, VBBNW=0.99, VDD=0.99, VDDS=1.62, VSS=0, VSSS=0
| Max Voltages:
|   BIASFET=1.95, VBBNW=1.21, VDD=1.21, VDDS=1.95, VSS=0, VSSS=0
[POWER_clamp]
|   voltage   I(typ)   I(min)   I(max)
-1.8V     178.9mA    128mA      243.2mA
-1.291V   75.77mA    51.65mA    107.4mA
-1.255V   68.99mA    46.64mA    97.97mA
-1.145V   49.38mA    32.56mA    70.53mA
-1.073V   37.36mA    24.29mA    53.43mA
-1.036V   31.7mA     20.5mA     45.29mA
-963.6mV  22.4mA     14.45mA    31.67mA
-890.9mV  15.91mA    10.19mA    22.4mA
-781.8mV  10.46mA    6.424mA    15.12mA
-527.3mV  2.642mA    1.569mA    3.825mA
-309.1mV  87.37uA    67.92uA    72.68uA
1.8V      -19.86uA   -9.301uA   -38.48uA
[Pulldown]
|   voltage   I(typ)   I(min)   I(max)
-1.8V     -8.878mA   -4.872mA   -9.522mA
-1.036V   -12.28mA   -8.398mA   -12.99mA
-763.6mV  -11.99mA   -8.933mA   -12.66mA
-545.5mV  -10.21mA   -7.811mA   -10.92mA
545.5mV   10.19mA    7.571mA    11.19mA
1.2V      21.1mA     15.12mA    23.61mA
1.745V    28.05mA    18.59mA    32.31mA
2.182V    30.51mA    18.15mA    36.58mA
2.345V    29.85mA    16.74mA    37.2mA
2.564V    27.64mA    14.26mA    35.81mA
3V        21.33mA    9.076mA    29.49mA
3.6V      14.83mA    5.328mA    21.24mA
[Pullup]
|   voltage   I(typ)   I(min)   I(max)
-1.8V     11.84mA    7.444mA    14.58mA
-1.036V   11.31mA    8.912mA    12.39mA
-709.1mV  10.03mA    8.014mA    11.04mA
-436.4mV  7.65mA     6.042mA    8.559mA
600mV     -10.69mA   -8.267mA   -12.11mA
1.309V    -22.27mA   -16.8mA    -25.64mA
1.964V    -31.22mA   -22.44mA   -36.85mA
2.291V    -34.49mA   -22.7mA    -41.67mA
2.509V    -34.31mA   -20.15mA   -43.79mA
2.727V    -31.88mA   -16.52mA   -43.2mA
3.218V    -23.12mA   -8.08mA    -35.4mA
3.6V      -15.38mA   -5.348mA   -28.49mA
[GND_clamp]
|   voltage   I(typ)   I(min)   I(max)
-1.8V     -337.7mA   -206.7mA   -550.9mA
-1.291V   -133.7mA   -80.77mA   -221.4mA
-1.145V   -81.03mA   -49.16mA   -133.6mA
-1.073V   -58.22mA   -35.9mA    -94.77mA
-1.036V   -47.89mA   -29.96mA   -77.06mA
-927.3mV  -25.01mA   -16.92mA   -36.9mA
-854.5mV  -15.36mA   -11.15mA   -20.87mA
-781.8mV  -9.067mA   -6.815mA   -12.64mA
-636.4mV  -3.067mA   -2.039mA   -4.983mA
-490.9mV  -377.1uA   -269.8uA   -638.6uA
-381.8mV  -50.69uA   -36.67uA   -84.39uA
1.8V      451.8pA    4.855uA    -6.741uA
[Ramp]
| variable   typ   min   max
dV/dt_f 0.52316113/0.19486241n  0.3932267/0.33044961n 0.59752428/0.12982056n
dV/dt_r 0.50596279/0.25549797n 0.39051083/0.46242953n 0.58869792/0.14325111n
R_load = 50
[Rising Waveform]
R_fixture = 50
V_fixture = 1.8
V_fixture_min = 1.62
V_fixture_max = 1.95
|   time   V(typ)   V(min)   V(max)
0s        946.5mV    979.2mV    975.5mV
600ps     946.5mV    979.2mV    975.5mV
777.3ps   946.5mV    979.2mV    1.796V
857.4ps   987.7mV    979.2mV    1.903V
993ps     1.368V     979.2mV    1.941V
1.186ns   1.749V     979.2mV    1.948V
1.345ns   1.782V     1.003V     1.949V
1.826ns   1.796V     1.527V     1.95V
2.031ns   1.797V     1.595V     1.95V
11.2ns    1.8V       1.62V      1.95V
[Rising Waveform]
R_fixture = 50
V_fixture = 0
V_fixture_min = 0
V_fixture_max = 0
|   time   V(typ)   V(min)   V(max)
0s        0V         0V         0V
600ps     0V         0V         0V
688.8ps   0V         0V         190.4mV
782ps     0V         0V         643.2mV
857.9ps   20.11mV    0V         835.8mV
1.085ns   371.2mV    0V         962mV
1.41ns    802.2mV    18.25mV    971.9mV
2.254ns   835.8mV    565.9mV    973.6mV
2.553ns   837.1mV    634.5mV    973.6mV
11.2ns    839.8mV    648.3mV    974.1mV
[Falling Waveform]
R_fixture = 50
V_fixture = 1.8
V_fixture_min = 1.62
V_fixture_max = 1.95
|   time   V(typ)   V(min)   V(max)
0s        1.801V     1.619V     1.949V
753.2ps   1.801V     1.619V     1.949V
951.4ps   1.811V     1.619V     1.112V
1.152ns   1.641V     1.619V     985.5mV
1.377ns   1.056V     1.619V     977.4mV
1.579ns   959.8mV    1.619V     975.7mV
1.962ns   951.1mV    1.539V     975mV
2.383ns   948.4mV    1.065V     974.8mV
2.625ns   947.6mV    991.1mV    974.8mV
11.2ns    945.5mV    978.6mV    974.8mV
[Falling Waveform]
R_fixture = 50
V_fixture = 0
V_fixture_min = 0
V_fixture_max = 0
|   time   V(typ)   V(min)   V(max)
0s        839.1mV    647.9mV    973.2mV
712ps     839.1mV    647.9mV    959.4mV
923.6ps   827.7mV    647.9mV    137.4mV
1.123ns   478.4mV    647.9mV    14.56mV
1.271ns   161.7mV    647.9mV    7.338mV
1.394ns   33.64mV    646.3mV    4.8mV
1.677ns   9.507mV    554.9mV    2.529mV
2.207ns   4.776mV    80.83mV    0V
2.438ns   3.739mV    11.91mV    0V
11.2ns    0V         0V         0V
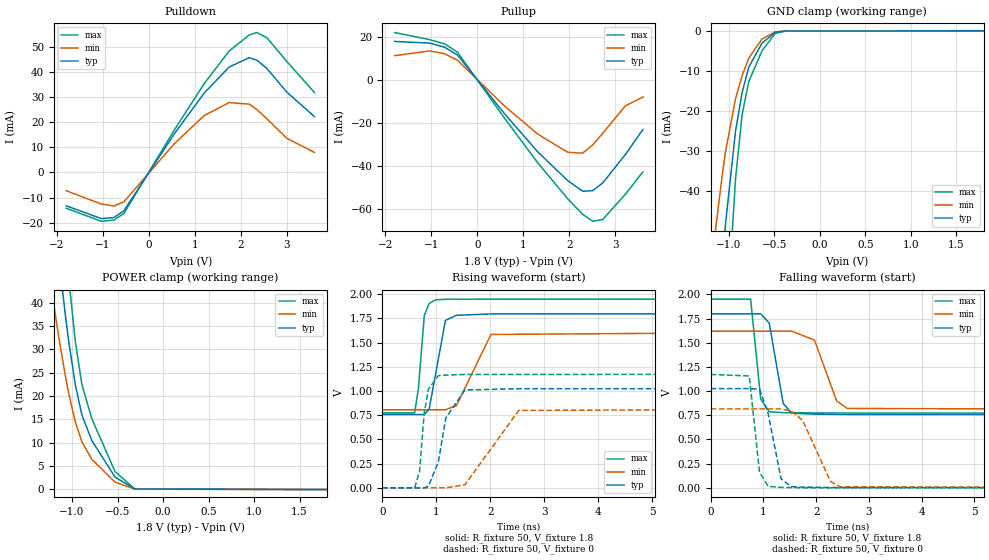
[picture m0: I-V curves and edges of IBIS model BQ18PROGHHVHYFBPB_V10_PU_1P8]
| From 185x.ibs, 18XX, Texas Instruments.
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|   Model Cell BQ18PROGHHVHYFBPB_V10_PU_1P8
|BQ18PROGHHVHYFBPB_V10_PU_1P8
[Model]   BQ18PROGHHVHYFBPB_V10_PU_1P8
Model_type   I/O
Polarity   Non-Inverting
Enable   Active-Low
Vinl =  0.63
Vinh =  1.17
Cref =  15pF
Rref =  100.0000M
Vref =  0V
Vmeas =  0.9
C_comp   2.023746p   1.863846p   2.096173p
[Model Spec]
Vinl   0.63   0.567   0.6825
Vinh   1.17   1.053   1.2675
[Temperature Range]   25   125   -40
[Voltage Range]   1.8   1.62   1.95
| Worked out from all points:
|   slope of the pulldown table from 0 to 0.27 V, typ, clamps not added: 35.1 ohm
|   slope of the pullup table from 0 to 0.27 V, typ, clamps not added: 36.9 ohm
|   GND clamp passes 1 mA (typ) near -0.54 V on its own axis
|   POWER clamp passes 1 mA (typ) near -0.44 V on its own axis
|   rising waveform, R_fixture 50, V_fixture 1.8: 20-80 % time 165ps typ, 334ps min, 95.5ps max; typ from 0.758 V to 1.8 V
|   rising waveform, R_fixture 50, V_fixture 0: 20-80 % time 238ps typ, 448ps min, 122ps max; typ from 0 V to 1.03 V
|   falling waveform, R_fixture 50, V_fixture 1.8: 20-80 % time 175ps typ, 293ps min, 116ps max; typ from 1.8 V to 0.757 V
|   falling waveform, R_fixture 50, V_fixture 0: 20-80 % time 213ps typ, 405ps min, 121ps max; typ from 1.03 V to 0 V
| Nom Voltages:
|   BIASFET=1.8, VBBNW=1.1, VDD=1.1, VDDS=1.8, VSS=0, VSSS=0
| Min Voltages:
|   BIASFET=1.62, VBBNW=0.99, VDD=0.99, VDDS=1.62, VSS=0, VSSS=0
| Max Voltages:
|   BIASFET=1.95, VBBNW=1.21, VDD=1.21, VDDS=1.95, VSS=0, VSSS=0
[POWER_clamp]
|   voltage   I(typ)   I(min)   I(max)
-1.8V     178.9mA    128mA      243.2mA
-1.291V   75.77mA    51.65mA    107.4mA
-1.255V   68.99mA    46.64mA    97.97mA
-1.145V   49.38mA    32.56mA    70.53mA
-1.073V   37.36mA    24.29mA    53.43mA
-1.036V   31.7mA     20.5mA     45.29mA
-963.6mV  22.4mA     14.45mA    31.67mA
-890.9mV  15.91mA    10.19mA    22.4mA
-781.8mV  10.46mA    6.424mA    15.12mA
-527.3mV  2.642mA    1.569mA    3.825mA
-309.1mV  87.37uA    67.92uA    72.68uA
1.8V      -19.86uA   -9.301uA   -38.48uA
[Pulldown]
|   voltage   I(typ)   I(min)   I(max)
-1.8V     -13.32mA   -7.309mA   -14.29mA
-1.036V   -18.42mA   -12.6mA    -19.49mA
-763.6mV  -17.99mA   -13.4mA    -18.98mA
-545.5mV  -15.31mA   -11.71mA   -16.37mA
545.5mV   15.26mA    11.35mA    16.77mA
1.2V      31.62mA    22.67mA    35.39mA
1.745V    42.06mA    27.88mA    48.43mA
2.182V    45.77mA    27.23mA    54.85mA
2.345V    44.8mA     25.13mA    55.79mA
2.564V    41.49mA    21.4mA     53.75mA
3V        32.02mA    13.62mA    44.26mA
3.6V      22.26mA    7.993mA    31.86mA
[Pullup]
|   voltage   I(typ)   I(min)   I(max)
-1.8V     17.76mA    11.17mA    21.87mA
-1.036V   16.97mA    13.37mA    18.58mA
-709.1mV  15.04mA    12.02mA    16.56mA
-436.4mV  11.47mA    9.059mA    12.83mA
600mV     -16.02mA   -12.39mA   -18.14mA
1.309V    -33.38mA   -25.19mA   -38.43mA
1.964V    -46.8mA    -33.65mA   -55.23mA
2.291V    -51.71mA   -34.06mA   -62.47mA
2.509V    -51.47mA   -30.25mA   -65.67mA
2.727V    -47.85mA   -24.8mA    -64.82mA
3.218V    -34.72mA   -12.13mA   -53.14mA
3.6V      -23.1mA    -8.023mA   -42.77mA
[GND_clamp]
|   voltage   I(typ)   I(min)   I(max)
-1.8V     -337.7mA   -206.7mA   -550.9mA
-1.291V   -133.7mA   -80.77mA   -221.4mA
-1.145V   -81.03mA   -49.16mA   -133.6mA
-1.073V   -58.22mA   -35.9mA    -94.77mA
-1.036V   -47.89mA   -29.96mA   -77.06mA
-927.3mV  -25.01mA   -16.92mA   -36.9mA
-854.5mV  -15.36mA   -11.15mA   -20.87mA
-781.8mV  -9.067mA   -6.815mA   -12.64mA
-636.4mV  -3.067mA   -2.039mA   -4.983mA
-490.9mV  -377.1uA   -269.8uA   -638.6uA
-381.8mV  -50.69uA   -36.67uA   -84.39uA
1.8V      451.8pA    4.855uA    -6.741uA
[Ramp]
| variable   typ   min   max
dV/dt_f 0.63836013/0.18193159n 0.49766628/0.30370677n 0.72033626/0.11891701n
dV/dt_r 0.61775622/0.23901749n  0.4913944/0.44918813n 0.70760727/0.12218771n
R_load = 50
[Rising Waveform]
R_fixture = 50
V_fixture = 1.8
V_fixture_min = 1.62
V_fixture_max = 1.95
|   time   V(typ)   V(min)   V(max)
0s        757.5mV    806.9mV    774.4mV
600ps     757.5mV    806.9mV    774.4mV
668.4ps   757.5mV    806.9mV    1.022V
779.4ps   757.5mV    806.9mV    1.784V
867.2ps   809.6mV    806.9mV    1.904V
990.6ps   1.182V     806.9mV    1.943V
1.17ns    1.73V      806.9mV    1.948V
1.373ns   1.783V     847.8mV    1.949V
2.014ns   1.797V     1.585V     1.95V
11.2ns    1.8V       1.62V      1.95V
[Rising Waveform]
R_fixture = 50
V_fixture = 0
V_fixture_min = 0
V_fixture_max = 0
|   time   V(typ)   V(min)   V(max)
0s        0V         0V         0V
600.5ps   0V         0V         0V
691ps     0V         0V         171.8mV
777.4ps   0V         0V         772.3mV
854.8ps   16.38mV    0V         1.02V
1.039ns   267.7mV    0V         1.159V
1.177ns   721mV      0V         1.165V
1.531ns   1.011V     31.47mV    1.172V
2.53ns    1.024V     800.2mV    1.172V
11.2ns    1.026V     816.7mV    1.173V
[Falling Waveform]
R_fixture = 50
V_fixture = 1.8
V_fixture_min = 1.62
V_fixture_max = 1.95
|   time   V(typ)   V(min)   V(max)
0s        1.799V     1.62V      1.951V
756.8ps   1.799V     1.62V      1.951V
947.4ps   1.799V     1.62V      919.4mV
1.109ns   1.703V     1.62V      786.5mV
1.374ns   872.4mV    1.62V      777.5mV
1.534ns   772.1mV    1.62V      777.2mV
1.968ns   762mV      1.527V     774.1mV
2.386ns   759.5mV    899.4mV    773.9mV
2.588ns   758.8mV    821.1mV    773.9mV
11.2ns    756.7mV    806.6mV    773.7mV
[Falling Waveform]
R_fixture = 50
V_fixture = 0
V_fixture_min = 0
V_fixture_max = 0
|   time   V(typ)   V(min)   V(max)
0s        1.026V     816.4mV    1.172V
730.2ps   1.026V     816.4mV    1.157V
926ps     1.019V     816.4mV    159.1mV
1.09ns    764.5mV    816.4mV    15.49mV
1.334ns   92.34mV    816.4mV    5.07mV
1.529ns   12.14mV    793.3mV    2.889mV
1.742ns   8.003mV    698.2mV    0V
2.27ns    4.039mV    67.99mV    0V
2.445ns   3.348mV    12.13mV    0V
11.2ns    0V         0V         0V
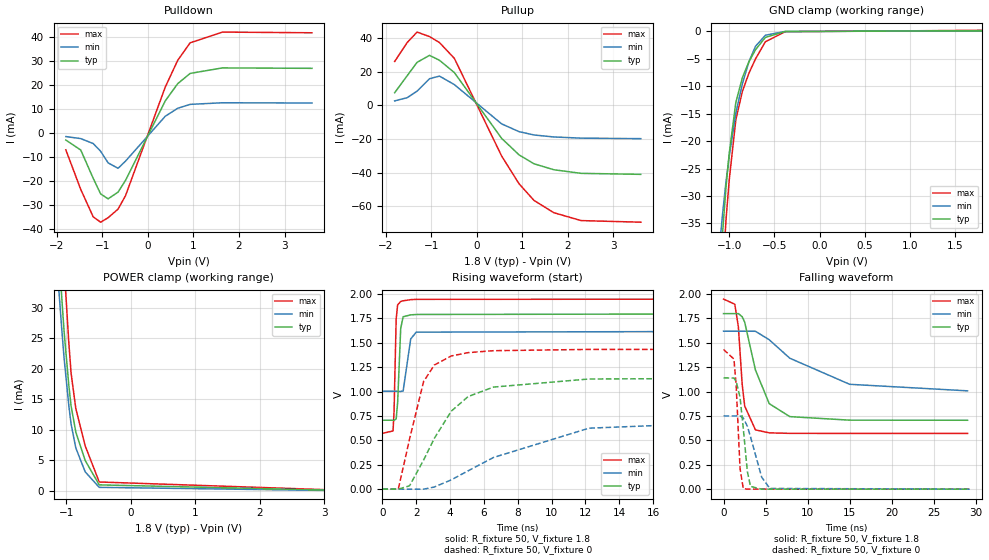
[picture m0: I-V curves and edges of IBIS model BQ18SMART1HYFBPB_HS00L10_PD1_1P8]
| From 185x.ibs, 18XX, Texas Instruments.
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|   Model Cell BQ18SMART1HYFBPB_HS00L10_PD1_1P8
|BQ18SMART1HYFBPB_HS00L10_PD1_1P8
[Model]   BQ18SMART1HYFBPB_HS00L10_PD1_1P8
Model_type   I/O
Polarity   Non-Inverting
Enable   Active-Low
Vinl =  0.63
Vinh =  1.17
Cref =  15pF
Rref =  100.0000M
Vref =  0V
Vmeas =  0.9
C_comp   0.915143p   0.8088923p   1.028577p
[Model Spec]
Vinl   0.63   0.567   0.6825
Vinh   1.17   1.053   1.2675
[Temperature Range]   25   125   -40
[Voltage Range]   1.8   1.62   1.95
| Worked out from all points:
|   slope of the pulldown table from 0 to 0.27 V, typ, clamps not added: 27.2 ohm
|   slope of the pullup table from 0 to 0.27 V, typ, clamps not added: 26 ohm
|   GND clamp passes 1 mA (typ) near -0.59 V on its own axis
|   POWER clamp passes 1 mA (typ) near -0.49 V on its own axis
|   rising waveform, R_fixture 50, V_fixture 1.8: 20-80 % time 148ps typ, 272ps min, 102ps max; typ from 0.707 V to 1.8 V
|   rising waveform, R_fixture 50, V_fixture 0: 20-80 % time 2.51ns typ, 6.51ns min, 1.19ns max; typ from 0 V to 1.14 V
|   falling waveform, R_fixture 50, V_fixture 1.8: 20-80 % time 2.18ns typ, 6.61ns min, 775ps max; typ from 1.8 V to 0.706 V
|   falling waveform, R_fixture 50, V_fixture 0: 20-80 % time 758ps typ, 1.42ns min, 463ps max; typ from 1.14 V to 0 V
| Nom Voltages:
|   BIASFET=1.8, VBBNW=1.1, VDD=1.1, VDDS=1.8, VSS=0, VSSS=0
| Min Voltages:
|   BIASFET=1.62, VBBNW=0.99, VDD=0.99, VDDS=1.62, VSS=0, VSSS=0
| Max Voltages:
|   BIASFET=1.95, VBBNW=1.21, VDD=1.21, VDDS=1.95, VSS=0, VSSS=0
[POWER_clamp]
|   voltage   I(typ)   I(min)   I(max)
-1.8V     196.9mA    157.5mA    250.4mA
-1.182V   51.67mA    43mA       68.61mA
-1.145V   44.45mA    37.16mA    60.1mA
-1.109V   37.9mA     31.74mA    52.07mA
-1.073V   31.79mA    26.6mA     44.33mA
-1.036V   26.12mA    21.74mA    36.87mA
-963.6mV  17.39mA    14.07mA    24.42mA
-927.3mV  13.91mA    10.96mA    19.29mA
-854.5mV  9.657mA    7.054mA    13.5mA
-709.1mV  4.995mA    3.131mA    7.393mA
-490.9mV  991uA      585.4uA    1.466mA
3.6V      0A         0A         0A
[Pulldown]
|   voltage   I(typ)   I(min)   I(max)
-1.8V     -2.835mA   -1.376mA   -6.938mA
-1.473V   -6.994mA   -2.229mA   -23.44mA
-1.2V     -18.79mA   -4.282mA   -34.89mA
-1.036V   -25.34mA   -7.531mA   -37.14mA
-872.7mV  -27.39mA   -12.36mA   -35.28mA
-654.5mV  -24.59mA   -14.63mA   -31.68mA
-490.9mV  -19.69mA   -11.65mA   -26.08mA
381.8mV   13.54mA    7.116mA    19.32mA
654.5mV   20.72mA    10.44mA    30.47mA
927.3mV   25mA       12.07mA    37.79mA
1.636V    27.3mA     12.74mA    42.26mA
3.6V      27.12mA    12.64mA    41.97mA
[Pullup]
|   voltage   I(typ)   I(min)   I(max)
-1.8V     7.614mA    2.74mA     26.22mA
-1.527V   17.69mA    4.626mA    37.43mA
-1.309V   25.69mA    8.541mA    43.72mA
-1.036V   29.87mA    15.94mA    41.05mA
-818.2mV  26.95mA    17.52mA    37.49mA
-490.9mV  19.61mA    12.45mA    28.08mA
545.5mV   -19.54mA   -10.94mA   -30.03mA
927.3mV   -29.38mA   -15.56mA   -46.58mA
1.255V    -34.7mA    -17.56mA   -56.51mA
1.691V    -38.25mA   -18.74mA   -63.85mA
2.291V    -40.42mA   -19.45mA   -68.55mA
3.6V      -41.01mA   -19.75mA   -69.5mA
[GND_clamp]
|   voltage   I(typ)   I(min)   I(max)
-1.8V     -274mA     -200.4mA   -365.5mA
-1.109V   -45.41mA   -39.33mA   -55.91mA
-1.073V   -36.49mA   -33.11mA   -44.46mA
-1.036V   -28.34mA   -27.37mA   -34.29mA
-1V       -22.19mA   -22.71mA   -27mA
-927.3mV  -12.97mA   -14.93mA   -16.12mA
-854.5mV  -8.452mA   -9.555mA   -10.93mA
-781.8mV  -5.549mA   -5.539mA   -7.634mA
-709.1mV  -3.363mA   -2.741mA   -5.028mA
-600mV    -1.121mA   -737.1uA   -1.924mA
-381.8mV  -62.21uA   -38.42uA   -93.33uA
1.8V      98.66uA    51.35uA    168.2uA
[Ramp]
| variable   typ   min   max
dV/dt_f 0.65759362/2.176685n  0.37106084/6.7099942n 0.82813149/0.77723501n
dV/dt_r  0.6959629/2.5200848n 0.45658763/6.7157164n 0.87460399/1.2026121n
R_load = 50
[Rising Waveform]
R_fixture = 50
V_fixture = 1.8
V_fixture_min = 1.62
V_fixture_max = 1.95
|   time   V(typ)   V(min)   V(max)
0s        706.6mV    1.003V     571.4mV
629.7ps   706.6mV    1.003V     596.9mV
689.6ps   706.6mV    1.003V     791.4mV
815.8ps   719mV      1.003V     1.745V
902.3ps   887.9mV    1.003V     1.889V
1.083ns   1.646V     1.001V     1.923V
1.227ns   1.767V     1.006V     1.93V
1.674ns   1.786V     1.539V     1.942V
2ns       1.79V      1.609V     1.945V
28.98ns   1.798V     1.619V     1.948V
[Rising Waveform]
R_fixture = 50
V_fixture = 0
V_fixture_min = 0
V_fixture_max = 0
|   time   V(typ)   V(min)   V(max)
0s        0V         0V         0V
943.7ps   0V         0V         2.344mV
1.607ns   34.54mV    0V         514.1mV
2.437ns   298.7mV    0V         1.103V
3.071ns   520.9mV    22.18mV    1.272V
4.071ns   799.2mV    95.39mV    1.365V
5.067ns   948.7mV    188.1mV    1.399V
6.567ns   1.046V     324.7mV    1.419V
12.21ns   1.129V     624.9mV    1.432V
29.23ns   1.141V     742.2mV    1.432V
[Falling Waveform]
R_fixture = 50
V_fixture = 1.8
V_fixture_min = 1.62
V_fixture_max = 1.95
|   time   V(typ)   V(min)   V(max)
0s        1.798V     1.618V     1.947V
1.341ns   1.798V     1.618V     1.894V
1.763ns   1.798V     1.618V     1.661V
2.217ns   1.766V     1.618V     1.071V
2.514ns   1.71V      1.618V     851.1mV
3.79ns    1.22V      1.617V     607.2mV
5.431ns   875.5mV    1.53V      576.7mV
7.872ns   743mV      1.341V     571.5mV
14.98ns   706.7mV    1.074V     571mV
28.98ns   705.8mV    1.007V     571mV
[Falling Waveform]
R_fixture = 50
V_fixture = 0
V_fixture_min = 0
V_fixture_max = 0
|   time   V(typ)   V(min)   V(max)
0s        1.14V      750mV      1.431V
1.237ns   1.138V     750mV      1.332V
1.508ns   1.102V     750mV      1.052V
1.961ns   941.1mV    750mV      210.7mV
2.349ns   619.2mV    728.3mV    5.779mV
2.829ns   181.7mV    644.4mV    0V
3.2ns     28.3mV     536.8mV    0V
4.533ns   0V         122.4mV    0V
5.503ns   0V         7.451mV    0V
29.23ns   0V         0V         0V
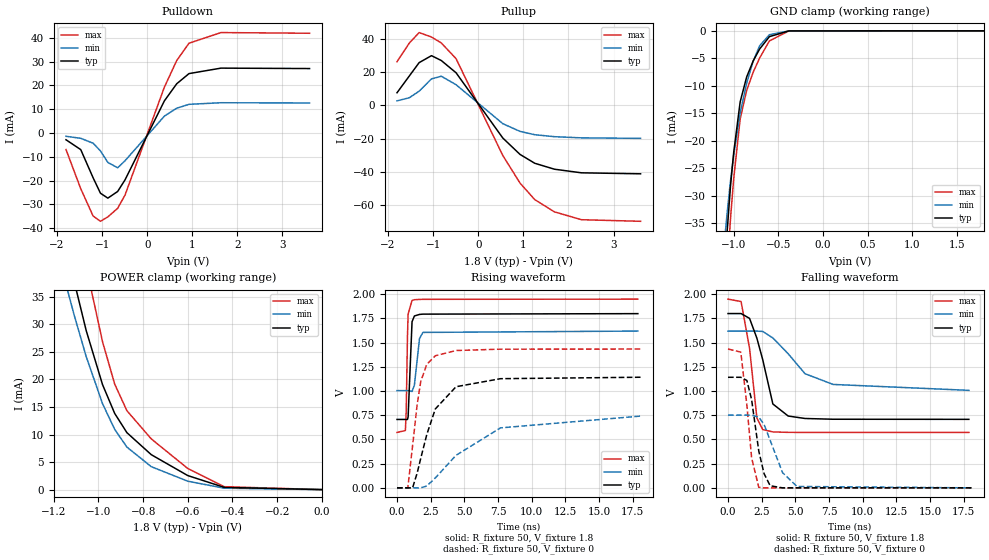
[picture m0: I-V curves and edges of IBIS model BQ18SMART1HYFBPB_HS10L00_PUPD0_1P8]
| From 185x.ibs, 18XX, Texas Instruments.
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|   Model Cell BQ18SMART1HYFBPB_HS10L00_PUPD0_1P8
|BQ18SMART1HYFBPB_HS10L00_PUPD0_1P8
[Model]   BQ18SMART1HYFBPB_HS10L00_PUPD0_1P8
Model_type   I/O
Polarity   Non-Inverting
Enable   Active-Low
Vinl =  0.63
Vinh =  1.17
Cref =  15pF
Rref =  100.0000M
Vref =  0V
Vmeas =  0.9
C_comp   0.915143p   0.8088923p   1.028577p
[Model Spec]
Vinl   0.63   0.567   0.6825
Vinh   1.17   1.053   1.2675
[Temperature Range]   25   125   -40
[Voltage Range]   1.8   1.62   1.95
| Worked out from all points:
|   slope of the pulldown table from 0 to 0.27 V, typ, clamps not added: 27.2 ohm
|   slope of the pullup table from 0 to 0.27 V, typ, clamps not added: 26 ohm
|   GND clamp passes 1 mA (typ) near -0.59 V on its own axis
|   POWER clamp passes 1 mA (typ) near -0.50 V on its own axis
|   rising waveform, R_fixture 50, V_fixture 1.8: 20-80 % time 148ps typ, 272ps min, 103ps max; typ from 0.707 V to 1.8 V
|   rising waveform, R_fixture 50, V_fixture 0: 20-80 % time 1.61ns typ, 4ns min, 797ps max; typ from 0 V to 1.14 V
|   falling waveform, R_fixture 50, V_fixture 1.8: 20-80 % time 1.12ns typ, 2.63ns min, 693ps max; typ from 1.8 V to 0.708 V
|   falling waveform, R_fixture 50, V_fixture 0: 20-80 % time 760ps typ, 1.23ns min, 569ps max; typ from 1.14 V to 0 V
| Nom Voltages:
|   BIASFET=1.8, VBBNW=1.1, VDD=1.1, VDDS=1.8, VSS=0, VSSS=0
| Min Voltages:
|   BIASFET=1.62, VBBNW=0.99, VDD=0.99, VDDS=1.62, VSS=0, VSSS=0
| Max Voltages:
|   BIASFET=1.95, VBBNW=1.21, VDD=1.21, VDDS=1.95, VSS=0, VSSS=0
[POWER_clamp]
|   voltage   I(typ)   I(min)   I(max)
-1.8V     196.8mA    157.5mA    250.4mA
-1.164V   48mA       40.06mA    64.23mA
-1.127V   41.11mA    34.43mA    55.95mA
-1.109V   37.83mA    31.72mA    51.94mA
-1.055V   28.88mA    24.15mA    40.47mA
-981.8mV  19.06mA    15.6mA     26.85mA
-927.3mV  13.83mA    10.93mA    19.15mA
-872.7mV  10.34mA    7.72mA     14.33mA
-763.6mV  6.344mA    4.165mA    9.211mA
-600mV    2.546mA    1.527mA    3.832mA
-436.4mV  402.5uA    253uA      527.5uA
0V        291.8pA    1.073nA    4.224nA
[Pulldown]
|   voltage   I(typ)   I(min)   I(max)
-1.8V     -2.835mA   -1.376mA   -6.938mA
-1.473V   -6.994mA   -2.229mA   -23.44mA
-1.2V     -18.79mA   -4.282mA   -34.89mA
-1.036V   -25.33mA   -7.531mA   -37.14mA
-872.7mV  -27.39mA   -12.36mA   -35.28mA
-654.5mV  -24.59mA   -14.63mA   -31.68mA
-490.9mV  -19.69mA   -11.65mA   -26.08mA
381.8mV   13.54mA    7.117mA    19.32mA
654.5mV   20.72mA    10.44mA    30.48mA
927.3mV   25mA       12.07mA    37.79mA
1.636V    27.3mA     12.74mA    42.26mA
3.6V      27.12mA    12.64mA    41.97mA
[Pullup]
|   voltage   I(typ)   I(min)   I(max)
-1.8V     7.614mA    2.74mA     26.22mA
-1.527V   17.69mA    4.626mA    37.43mA
-1.309V   25.69mA    8.541mA    43.72mA
-1.036V   29.87mA    15.94mA    41.05mA
-818.2mV  26.95mA    17.52mA    37.49mA
-490.9mV  19.61mA    12.45mA    28.08mA
545.5mV   -19.54mA   -10.94mA   -30.03mA
927.3mV   -29.38mA   -15.56mA   -46.58mA
1.255V    -34.7mA    -17.56mA   -56.51mA
1.691V    -38.25mA   -18.74mA   -63.85mA
2.291V    -40.42mA   -19.45mA   -68.55mA
3.6V      -41.01mA   -19.75mA   -69.5mA
[GND_clamp]
|   voltage   I(typ)   I(min)   I(max)
-1.8V     -274mA     -200.4mA   -365.5mA
-1.109V   -45.37mA   -39.32mA   -55.85mA
-1.073V   -36.45mA   -33.1mA    -44.39mA
-1.036V   -28.3mA    -27.35mA   -34.22mA
-1V       -22.14mA   -22.69mA   -26.92mA
-927.3mV  -12.91mA   -14.91mA   -16.03mA
-854.5mV  -8.387mA   -9.532mA   -10.83mA
-781.8mV  -5.484mA   -5.512mA   -7.535mA
-709.1mV  -3.298mA   -2.71mA    -4.931mA
-600mV    -1.058mA   -705.2uA   -1.831mA
-381.8mV  -13.32uA   -12.31uA   -19.39uA
1.8V      291.8pA    820.3nA    4.087nA
[Ramp]
| variable   typ   min   max
dV/dt_f 0.65712997/1.1205314n 0.36990921/2.65474n   0.82838853/0.69634204n
dV/dt_r 0.69705051/1.6154855n 0.45840264/4.1584211n   0.871089/0.80114753n
R_load = 50
[Rising Waveform]
R_fixture = 50
V_fixture = 1.8
V_fixture_min = 1.62
V_fixture_max = 1.95
|   time   V(typ)   V(min)   V(max)
0s        706.8mV    1.005V     572.9mV
621ps     706.8mV    1.005V     592.4mV
682ps     706.8mV    1.005V     787.5mV
776.8ps   706.8mV    1.005V     1.567V
824.2ps   733mV      1.005V     1.796V
1.116ns   1.717V     995.7mV    1.937V
1.291ns   1.776V     1.062V     1.944V
1.669ns   1.792V     1.542V     1.947V
1.921ns   1.795V     1.606V     1.948V
17.87ns   1.8V       1.62V      1.95V
[Rising Waveform]
R_fixture = 50
V_fixture = 0
V_fixture_min = 0
V_fixture_max = 0
|   time   V(typ)   V(min)   V(max)
0s        0V         0V         0V
800.9ps   0V         0V         0V
1.155ns   0V         0V         434.4mV
1.499ns   155mV      0V         864mV
1.759ns   303.5mV    0V         1.097V
2.208ns   550.2mV    19.13mV    1.276V
2.844ns   815.6mV    102.6mV    1.365V
4.38ns    1.045V     336.6mV    1.419V
7.679ns   1.128V     619.6mV    1.433V
18.07ns   1.143V     741.5mV    1.434V
[Falling Waveform]
R_fixture = 50
V_fixture = 1.8
V_fixture_min = 1.62
V_fixture_max = 1.95
|   time   V(typ)   V(min)   V(max)
0s        1.8V       1.619V     1.949V
970.3ps   1.8V       1.619V     1.924V
1.599ns   1.75V      1.619V     1.441V
2.141ns   1.546V     1.619V     721.4mV
2.578ns   1.322V     1.615V     601.8mV
3.327ns   866.3mV    1.548V     577.9mV
4.464ns   741.8mV    1.385V     573.1mV
5.711ns   716.5mV    1.179V     572.7mV
7.797ns   708.6mV    1.068V     572.6mV
17.87ns   707.6mV    1.007V     572.6mV
[Falling Waveform]
R_fixture = 50
V_fixture = 0
V_fixture_min = 0
V_fixture_max = 0
|   time   V(typ)   V(min)   V(max)
0s        1.142V     750.8mV    1.434V
948ps     1.142V     750.8mV    1.402V
1.399ns   1.109V     750.8mV    855mV
1.751ns   910.7mV    750.8mV    309.5mV
2.282ns   380.8mV    730.1mV    6.411mV
2.672ns   147.8mV    655.7mV    0V
3.126ns   21.94mV    490.6mV    0V
4.047ns   0V         157.2mV    0V
5.116ns   0V         14.32mV    0V
18.07ns   0V         0V         0V
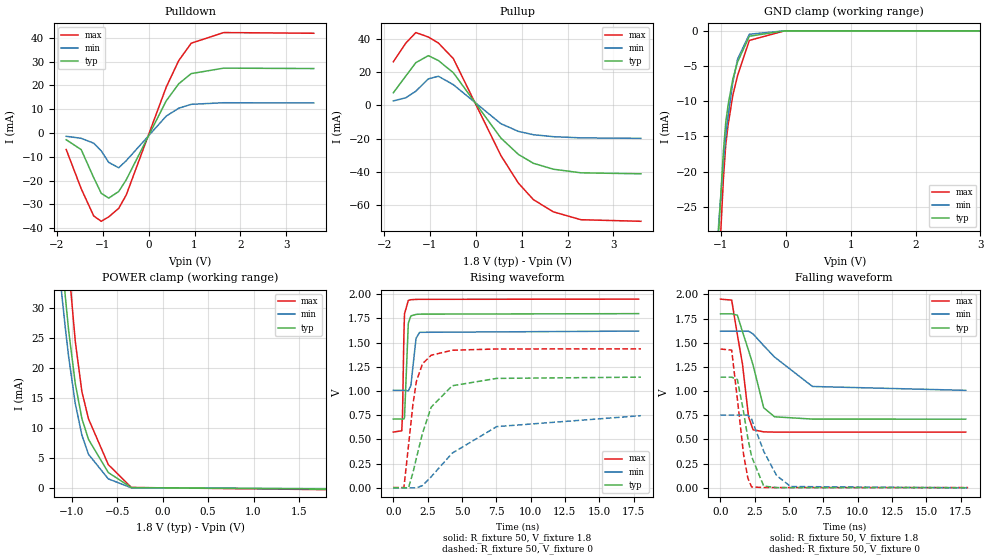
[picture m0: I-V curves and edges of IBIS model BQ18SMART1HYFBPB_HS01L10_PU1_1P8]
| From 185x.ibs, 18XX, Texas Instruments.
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|   Model Cell BQ18SMART1HYFBPB_HS01L10_PU1_1P8
|BQ18SMART1HYFBPB_HS01L10_PU1_1P8
[Model]   BQ18SMART1HYFBPB_HS01L10_PU1_1P8
Model_type   I/O
Polarity   Non-Inverting
Enable   Active-Low
Vinl =  0.63
Vinh =  1.17
Cref =  15pF
Rref =  100.0000M
Vref =  0V
Vmeas =  0.9
C_comp   0.915143p   0.8088923p   1.028577p
[Model Spec]
Vinl   0.63   0.567   0.6825
Vinh   1.17   1.053   1.2675
[Temperature Range]   25   125   -40
[Voltage Range]   1.8   1.62   1.95
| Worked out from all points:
|   slope of the pulldown table from 0 to 0.27 V, typ, clamps not added: 27.2 ohm
|   slope of the pullup table from 0 to 0.27 V, typ, clamps not added: 26 ohm
|   GND clamp passes 1 mA (typ) near -0.58 V on its own axis
|   POWER clamp passes 1 mA (typ) near -0.49 V on its own axis
|   rising waveform, R_fixture 50, V_fixture 1.8: 20-80 % time 144ps typ, 263ps min, 100ps max; typ from 0.711 V to 1.8 V
|   rising waveform, R_fixture 50, V_fixture 0: 20-80 % time 1.52ns typ, 3.82ns min, 755ps max; typ from 0 V to 1.14 V
|   falling waveform, R_fixture 50, V_fixture 1.8: 20-80 % time 1.25ns typ, 2.27ns min, 823ps max; typ from 1.8 V to 0.71 V
|   falling waveform, R_fixture 50, V_fixture 0: 20-80 % time 911ps typ, 1.36ns min, 691ps max; typ from 1.14 V to 0.002 V
| Nom Voltages:
|   BIASFET=1.8, VBBNW=1.1, VDD=1.1, VDDS=1.8, VSS=0, VSSS=0
| Min Voltages:
|   BIASFET=1.62, VBBNW=0.99, VDD=0.99, VDDS=1.62, VSS=0, VSSS=0
| Max Voltages:
|   BIASFET=1.95, VBBNW=1.21, VDD=1.21, VDDS=1.95, VSS=0, VSSS=0
[POWER_clamp]
|   voltage   I(typ)   I(min)   I(max)
-1.8V     196.9mA    157.5mA    250.4mA
-1.182V   51.7mA     43.01mA    68.62mA
-1.145V   44.47mA    37.18mA    60.11mA
-1.109V   37.92mA    31.75mA    52.08mA
-1.073V   31.81mA    26.61mA    44.34mA
-1.036V   26.13mA    21.76mA    36.87mA
-963.6mV  17.41mA    14.08mA    24.42mA
-890.9mV  11.59mA    8.834mA    16.07mA
-818.2mV  8.134mA    5.657mA    11.55mA
-600mV    2.616mA    1.567mA    3.937mA
-345.5mV  117.2uA    78.7uA     135.4uA
1.8V      -127.5uA   -60.72uA   -226.5uA
[Pulldown]
|   voltage   I(typ)   I(min)   I(max)
-1.8V     -2.835mA   -1.376mA   -6.938mA
-1.473V   -6.994mA   -2.229mA   -23.44mA
-1.2V     -18.79mA   -4.282mA   -34.89mA
-1.036V   -25.34mA   -7.531mA   -37.14mA
-872.7mV  -27.39mA   -12.36mA   -35.28mA
-654.5mV  -24.59mA   -14.63mA   -31.68mA
-490.9mV  -19.69mA   -11.65mA   -26.08mA
381.8mV   13.54mA    7.117mA    19.32mA
654.5mV   20.72mA    10.44mA    30.48mA
927.3mV   25mA       12.07mA    37.79mA
1.636V    27.3mA     12.74mA    42.26mA
3.6V      27.12mA    12.64mA    41.97mA
[Pullup]
|   voltage   I(typ)   I(min)   I(max)
-1.8V     7.614mA    2.74mA     26.22mA
-1.527V   17.69mA    4.626mA    37.43mA
-1.309V   25.69mA    8.541mA    43.72mA
-1.036V   29.87mA    15.94mA    41.05mA
-818.2mV  26.95mA    17.52mA    37.49mA
-490.9mV  19.61mA    12.45mA    28.08mA
545.5mV   -19.54mA   -10.94mA   -30.03mA
927.3mV   -29.38mA   -15.56mA   -46.58mA
1.255V    -34.7mA    -17.56mA   -56.51mA
1.691V    -38.25mA   -18.74mA   -63.85mA
2.291V    -40.42mA   -19.45mA   -68.55mA
3.6V      -41.01mA   -19.75mA   -69.5mA
[GND_clamp]
|   voltage   I(typ)   I(min)   I(max)
-1.8V     -274mA     -200.4mA   -365.5mA
-1.109V   -45.43mA   -39.33mA   -55.98mA
-1.073V   -36.51mA   -33.12mA   -44.53mA
-1.036V   -28.36mA   -27.37mA   -34.36mA
-963.6mV  -17.09mA   -18.57mA   -21.02mA
-927.3mV  -12.99mA   -14.94mA   -16.2mA
-890.9mV  -10.53mA   -12.1mA    -13.35mA
-818.2mV  -6.846mA   -7.311mA   -9.151mA
-745.5mV  -4.434mA   -4.029mA   -6.378mA
-563.6mV  -767.1uA   -485.3uA   -1.366mA
-18.18mV  0A         0A         0A
3.6V      0A         0A         0A
[Ramp]
| variable   typ   min   max
dV/dt_f 0.65562144/1.2551784n 0.36878884/2.2814508n 0.82663589/0.82605524n
dV/dt_r 0.69430171/1.5290793n 0.45773225/3.9254767n 0.86826391/0.75854135n
R_load = 50
[Rising Waveform]
R_fixture = 50
V_fixture = 1.8
V_fixture_min = 1.62
V_fixture_max = 1.95
|   time   V(typ)   V(min)   V(max)
0s        710.9mV    1.007V     576.6mV
613.8ps   710.9mV    1.007V     589.6mV
672.6ps   710.9mV    1.007V     774.4mV
767.8ps   710.9mV    1.007V     1.569V
814.3ps   727mV      1.007V     1.797V
1.092ns   1.701V     1.002V     1.937V
1.279ns   1.777V     1.057V     1.944V
1.654ns   1.792V     1.545V     1.947V
1.917ns   1.795V     1.607V     1.948V
17.87ns   1.8V       1.62V      1.95V
[Rising Waveform]
R_fixture = 50
V_fixture = 0
V_fixture_min = 0
V_fixture_max = 0
|   time   V(typ)   V(min)   V(max)
0s        0V         0V         3.631mV
770.9ps   0V         0V         3.631mV
1.103ns   0V         0V         435.1mV
1.43ns    156.7mV    0V         865mV
1.681ns   308.2mV    0V         1.101V
2.124ns   563.6mV    23.53mV    1.282V
2.754ns   833.4mV    114mV      1.37V
4.291ns   1.055V     358.9mV    1.422V
7.531ns   1.131V     632.8mV    1.435V
18.04ns   1.144V     745.8mV    1.436V
[Falling Waveform]
R_fixture = 50
V_fixture = 1.8
V_fixture_min = 1.62
V_fixture_max = 1.95
|   time   V(typ)   V(min)   V(max)
0s        1.799V     1.619V     1.951V
816.6ps   1.799V     1.619V     1.941V
1.234ns   1.785V     1.619V     1.58V
1.602ns   1.615V     1.619V     1.282V
2.048ns   1.42V      1.619V     733.2mV
2.379ns   1.268V     1.591V     600.8mV
3.149ns   828.3mV    1.47V      578.8mV
3.943ns   734.6mV    1.352V     576.4mV
6.703ns   710.8mV    1.048V     576.1mV
17.87ns   710.3mV    1.008V     576.1mV
[Falling Waveform]
R_fixture = 50
V_fixture = 0
V_fixture_min = 0
V_fixture_max = 0
|   time   V(typ)   V(min)   V(max)
0s        1.144V     753.1mV    1.435V
816.7ps   1.144V     753.1mV    1.424V
1.23ns    1.121V     753.1mV    919.1mV
1.684ns   785mV      753.1mV    345.7mV
1.996ns   512.5mV    751.8mV    100.2mV
2.268ns   323.5mV    710.9mV    9.324mV
3.153ns   17.63mV    377.8mV    3.204mV
4.094ns   2.748mV    126.4mV    3.074mV
5.116ns   2.212mV    13.76mV    3.07mV
18.04ns   2.13mV     0V         3.068mV
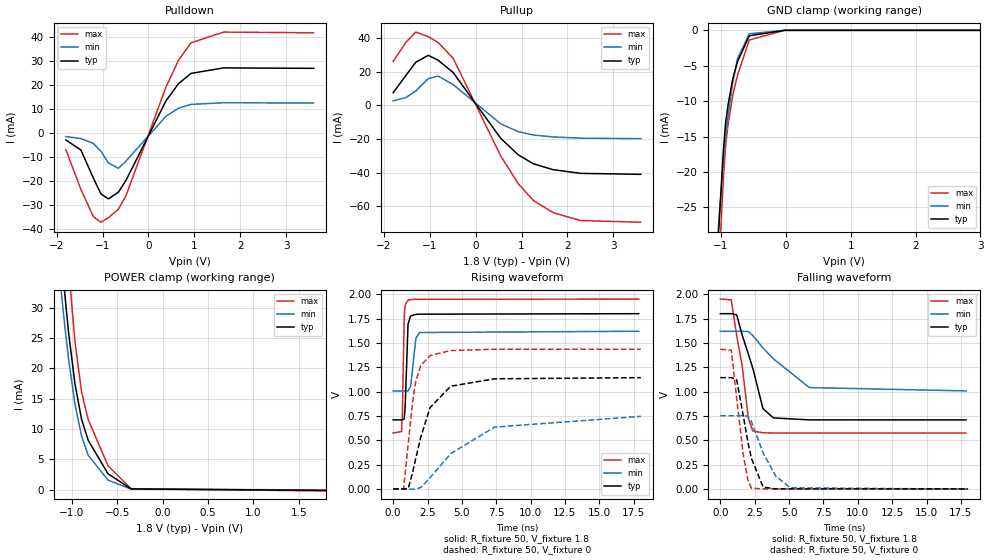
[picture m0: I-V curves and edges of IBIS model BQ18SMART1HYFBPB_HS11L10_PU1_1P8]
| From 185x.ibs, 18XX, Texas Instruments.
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|   Model Cell BQ18SMART1HYFBPB_HS11L10_PU1_1P8
|BQ18SMART1HYFBPB_HS11L10_PU1_1P8
[Model]   BQ18SMART1HYFBPB_HS11L10_PU1_1P8
Model_type   I/O
Polarity   Non-Inverting
Enable   Active-Low
Vinl =  0.63
Vinh =  1.17
Cref =  15pF
Rref =  100.0000M
Vref =  0V
Vmeas =  0.9
C_comp   0.915143p   0.8088923p   1.028577p
[Model Spec]
Vinl   0.63   0.567   0.6825
Vinh   1.17   1.053   1.2675
[Temperature Range]   25   125   -40
[Voltage Range]   1.8   1.62   1.95
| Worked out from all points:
|   slope of the pulldown table from 0 to 0.27 V, typ, clamps not added: 27.2 ohm
|   slope of the pullup table from 0 to 0.27 V, typ, clamps not added: 26 ohm
|   GND clamp passes 1 mA (typ) near -0.58 V on its own axis
|   POWER clamp passes 1 mA (typ) near -0.49 V on its own axis
|   rising waveform, R_fixture 50, V_fixture 1.8: 20-80 % time 144ps typ, 262ps min, 100ps max; typ from 0.711 V to 1.8 V
|   rising waveform, R_fixture 50, V_fixture 0: 20-80 % time 1.48ns typ, 3.7ns min, 732ps max; typ from 0.002 V to 1.14 V
|   falling waveform, R_fixture 50, V_fixture 1.8: 20-80 % time 1.29ns typ, 2.28ns min, 850ps max; typ from 1.8 V to 0.71 V
|   falling waveform, R_fixture 50, V_fixture 0: 20-80 % time 952ps typ, 1.41ns min, 718ps max; typ from 1.14 V to 0.002 V
| Nom Voltages:
|   BIASFET=1.8, VBBNW=1.1, VDD=1.1, VDDS=1.8, VSS=0, VSSS=0
| Min Voltages:
|   BIASFET=1.62, VBBNW=0.99, VDD=0.99, VDDS=1.62, VSS=0, VSSS=0
| Max Voltages:
|   BIASFET=1.95, VBBNW=1.21, VDD=1.21, VDDS=1.95, VSS=0, VSSS=0
[POWER_clamp]
|   voltage   I(typ)   I(min)   I(max)
-1.8V     196.9mA    157.5mA    250.4mA
-1.182V   51.7mA     43.01mA    68.62mA
-1.145V   44.47mA    37.18mA    60.11mA
-1.109V   37.92mA    31.75mA    52.08mA
-1.073V   31.81mA    26.61mA    44.34mA
-1.036V   26.13mA    21.76mA    36.87mA
-963.6mV  17.41mA    14.08mA    24.42mA
-890.9mV  11.59mA    8.834mA    16.07mA
-818.2mV  8.134mA    5.657mA    11.55mA
-600mV    2.616mA    1.567mA    3.937mA
-345.5mV  117.2uA    78.7uA     135.4uA
1.8V      -127.5uA   -60.72uA   -226.5uA
[Pulldown]
|   voltage   I(typ)   I(min)   I(max)
-1.8V     -2.835mA   -1.376mA   -6.938mA
-1.473V   -6.994mA   -2.229mA   -23.44mA
-1.2V     -18.79mA   -4.282mA   -34.89mA
-1.036V   -25.34mA   -7.531mA   -37.14mA
-872.7mV  -27.39mA   -12.36mA   -35.28mA
-654.5mV  -24.59mA   -14.63mA   -31.68mA
-490.9mV  -19.69mA   -11.65mA   -26.08mA
381.8mV   13.54mA    7.117mA    19.32mA
654.5mV   20.72mA    10.44mA    30.48mA
927.3mV   25mA       12.07mA    37.79mA
1.636V    27.3mA     12.74mA    42.26mA
3.6V      27.12mA    12.64mA    41.97mA
[Pullup]
|   voltage   I(typ)   I(min)   I(max)
-1.8V     7.614mA    2.74mA     26.22mA
-1.527V   17.69mA    4.626mA    37.43mA
-1.309V   25.69mA    8.541mA    43.72mA
-1.036V   29.87mA    15.94mA    41.05mA
-818.2mV  26.95mA    17.52mA    37.49mA
-490.9mV  19.61mA    12.45mA    28.08mA
545.5mV   -19.54mA   -10.94mA   -30.03mA
927.3mV   -29.38mA   -15.56mA   -46.58mA
1.255V    -34.7mA    -17.56mA   -56.51mA
1.691V    -38.25mA   -18.74mA   -63.85mA
2.291V    -40.42mA   -19.45mA   -68.55mA
3.6V      -41.01mA   -19.75mA   -69.5mA
[GND_clamp]
|   voltage   I(typ)   I(min)   I(max)
-1.8V     -274mA     -200.4mA   -365.5mA
-1.109V   -45.43mA   -39.33mA   -55.98mA
-1.073V   -36.51mA   -33.12mA   -44.53mA
-1.036V   -28.36mA   -27.37mA   -34.36mA
-963.6mV  -17.09mA   -18.57mA   -21.02mA
-927.3mV  -12.99mA   -14.94mA   -16.2mA
-890.9mV  -10.53mA   -12.1mA    -13.35mA
-818.2mV  -6.846mA   -7.311mA   -9.151mA
-745.5mV  -4.434mA   -4.029mA   -6.378mA
-563.6mV  -767.1uA   -485.3uA   -1.366mA
-18.18mV  0A         0A         0A
3.6V      0A         0A         0A
[Ramp]
| variable   typ   min   max
dV/dt_f 0.65574149/1.2920013n 0.36885284/2.2951142n 0.82680744/0.85220966n
dV/dt_r 0.69345661/1.4809501n 0.45740214/3.7937834n  0.8680054/0.73513279n
R_load = 50
[Rising Waveform]
R_fixture = 50
V_fixture = 1.8
V_fixture_min = 1.62
V_fixture_max = 1.95
|   time   V(typ)   V(min)   V(max)
0s        710.7mV    1.008V     577mV
613.9ps   710.7mV    1.008V     590.9mV
672.8ps   710.7mV    1.008V     785.8mV
808.8ps   722.6mV    1.008V     1.786V
882.3ps   875.7mV    1.008V     1.89V
1.085ns   1.694V     1.008V     1.938V
1.272ns   1.777V     1.053V     1.944V
1.657ns   1.793V     1.55V      1.948V
1.922ns   1.795V     1.607V     1.948V
17.87ns   1.8V       1.62V      1.95V
[Rising Waveform]
R_fixture = 50
V_fixture = 0
V_fixture_min = 0
V_fixture_max = 0
|   time   V(typ)   V(min)   V(max)
0s        2.003mV    0V         3.646mV
756ps     2.003mV    0V         3.646mV
1.099ns   7.164mV    0V         468.8mV
1.404ns   163.8mV    0V         878.1mV
1.638ns   310.4mV    0V         1.103V
2.01ns    533.8mV    17.61mV    1.268V
2.683ns   836.1mV    116.9mV    1.37V
4.19ns    1.056V     364.9mV    1.422V
7.377ns   1.132V     636.8mV    1.435V
18.02ns   1.144V     746.9mV    1.436V
[Falling Waveform]
R_fixture = 50
V_fixture = 1.8
V_fixture_min = 1.62
V_fixture_max = 1.95
|   time   V(typ)   V(min)   V(max)
0s        1.8V       1.619V     1.95V
796.7ps   1.8V       1.619V     1.942V
1.185ns   1.788V     1.619V     1.578V
1.586ns   1.582V     1.619V     1.265V
2.033ns   1.387V     1.617V     729.7mV
2.361ns   1.24V      1.575V     597.5mV
3.098ns   826.8mV    1.449V     578.2mV
3.864ns   730.8mV    1.336V     576.3mV
6.474ns   710.7mV    1.042V     576.1mV
17.87ns   710.3mV    1.008V     576.1mV
[Falling Waveform]
R_fixture = 50
V_fixture = 0
V_fixture_min = 0
V_fixture_max = 0
|   time   V(typ)   V(min)   V(max)
0s        1.144V     753.3mV    1.435V
796.8ps   1.144V     753.3mV    1.425V
1.185ns   1.125V     753.3mV    934mV
1.662ns   755.4mV    753.3mV    357.2mV
1.995ns   487.7mV    748.1mV    97.36mV
2.264ns   314mV      693.1mV    9.187mV
3.11ns    21.37mV    371.9mV    3.218mV
4.027ns   2.812mV    133.7mV    3.074mV
5.086ns   2.21mV     14.32mV    3.07mV
18.02ns   2.13mV     0V         3.068mV
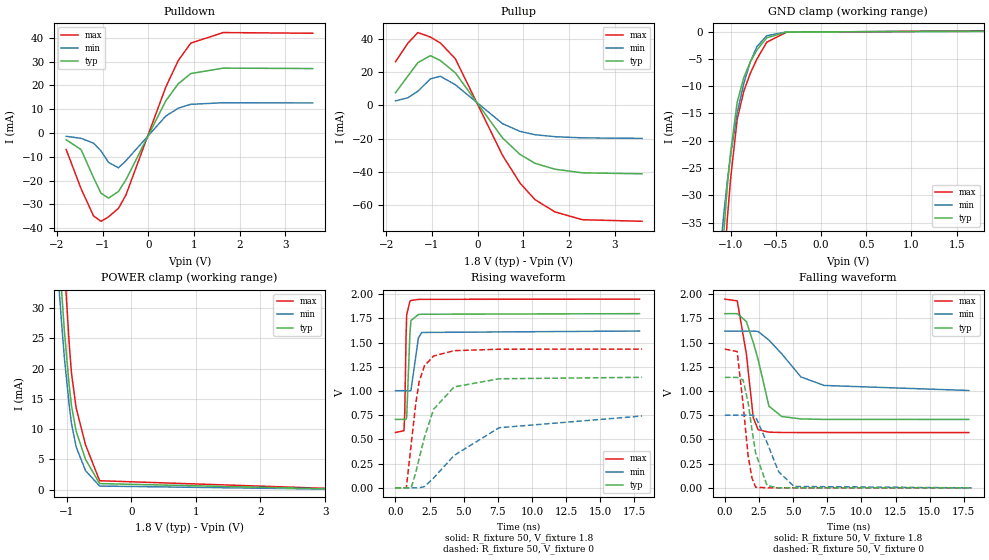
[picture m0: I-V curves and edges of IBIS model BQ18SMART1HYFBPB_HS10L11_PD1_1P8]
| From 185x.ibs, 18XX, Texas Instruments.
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|   Model Cell BQ18SMART1HYFBPB_HS10L11_PD1_1P8
|BQ18SMART1HYFBPB_HS10L11_PD1_1P8
[Model]   BQ18SMART1HYFBPB_HS10L11_PD1_1P8
Model_type   I/O
Polarity   Non-Inverting
Enable   Active-Low
Vinl =  0.63
Vinh =  1.17
Cref =  15pF
Rref =  100.0000M
Vref =  0V
Vmeas =  0.9
C_comp   0.915143p   0.8088923p   1.028577p
[Model Spec]
Vinl   0.63   0.567   0.6825
Vinh   1.17   1.053   1.2675
[Temperature Range]   25   125   -40
[Voltage Range]   1.8   1.62   1.95
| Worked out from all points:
|   slope of the pulldown table from 0 to 0.27 V, typ, clamps not added: 27.2 ohm
|   slope of the pullup table from 0 to 0.27 V, typ, clamps not added: 26 ohm
|   GND clamp passes 1 mA (typ) near -0.59 V on its own axis
|   POWER clamp passes 1 mA (typ) near -0.49 V on its own axis
|   rising waveform, R_fixture 50, V_fixture 1.8: 20-80 % time 147ps typ, 270ps min, 102ps max; typ from 0.706 V to 1.8 V
|   rising waveform, R_fixture 50, V_fixture 0: 20-80 % time 1.58ns typ, 3.94ns min, 785ps max; typ from 0 V to 1.14 V
|   falling waveform, R_fixture 50, V_fixture 1.8: 20-80 % time 1.14ns typ, 2.33ns min, 733ps max; typ from 1.8 V to 0.706 V
|   falling waveform, R_fixture 50, V_fixture 0: 20-80 % time 796ps typ, 1.23ns min, 606ps max; typ from 1.14 V to 0 V
| Nom Voltages:
|   BIASFET=1.8, VBBNW=1.1, VDD=1.1, VDDS=1.8, VSS=0, VSSS=0
| Min Voltages:
|   BIASFET=1.62, VBBNW=0.99, VDD=0.99, VDDS=1.62, VSS=0, VSSS=0
| Max Voltages:
|   BIASFET=1.95, VBBNW=1.21, VDD=1.21, VDDS=1.95, VSS=0, VSSS=0
[POWER_clamp]
|   voltage   I(typ)   I(min)   I(max)
-1.8V     196.9mA    157.5mA    250.4mA
-1.182V   51.67mA    43mA       68.61mA
-1.145V   44.45mA    37.16mA    60.1mA
-1.109V   37.9mA     31.74mA    52.07mA
-1.073V   31.79mA    26.6mA     44.33mA
-1.036V   26.12mA    21.74mA    36.87mA
-963.6mV  17.39mA    14.07mA    24.42mA
-927.3mV  13.91mA    10.96mA    19.29mA
-854.5mV  9.657mA    7.054mA    13.5mA
-709.1mV  4.995mA    3.131mA    7.393mA
-490.9mV  991uA      585.4uA    1.466mA
3.6V      0A         0A         0A
[Pulldown]
|   voltage   I(typ)   I(min)   I(max)
-1.8V     -2.835mA   -1.376mA   -6.938mA
-1.473V   -6.994mA   -2.229mA   -23.44mA
-1.2V     -18.79mA   -4.282mA   -34.89mA
-1.036V   -25.34mA   -7.531mA   -37.14mA
-872.7mV  -27.39mA   -12.36mA   -35.28mA
-654.5mV  -24.59mA   -14.63mA   -31.68mA
-490.9mV  -19.69mA   -11.65mA   -26.08mA
381.8mV   13.54mA    7.116mA    19.32mA
654.5mV   20.72mA    10.44mA    30.47mA
927.3mV   25mA       12.07mA    37.79mA
1.636V    27.3mA     12.74mA    42.26mA
3.6V      27.12mA    12.64mA    41.97mA
[Pullup]
|   voltage   I(typ)   I(min)   I(max)
-1.8V     7.614mA    2.74mA     26.22mA
-1.527V   17.69mA    4.626mA    37.43mA
-1.309V   25.69mA    8.541mA    43.72mA
-1.036V   29.87mA    15.94mA    41.05mA
-818.2mV  26.95mA    17.52mA    37.49mA
-490.9mV  19.61mA    12.45mA    28.08mA
545.5mV   -19.54mA   -10.94mA   -30.03mA
927.3mV   -29.38mA   -15.56mA   -46.58mA
1.255V    -34.7mA    -17.56mA   -56.51mA
1.691V    -38.25mA   -18.74mA   -63.85mA
2.291V    -40.42mA   -19.45mA   -68.55mA
3.6V      -41.01mA   -19.75mA   -69.5mA
[GND_clamp]
|   voltage   I(typ)   I(min)   I(max)
-1.8V     -274mA     -200.4mA   -365.5mA
-1.109V   -45.41mA   -39.33mA   -55.91mA
-1.073V   -36.49mA   -33.11mA   -44.46mA
-1.036V   -28.34mA   -27.37mA   -34.29mA
-1V       -22.19mA   -22.71mA   -27mA
-927.3mV  -12.97mA   -14.93mA   -16.12mA
-854.5mV  -8.452mA   -9.555mA   -10.93mA
-781.8mV  -5.549mA   -5.539mA   -7.634mA
-709.1mV  -3.363mA   -2.741mA   -5.028mA
-600mV    -1.121mA   -737.1uA   -1.924mA
-381.8mV  -62.21uA   -38.42uA   -93.33uA
1.8V      98.66uA    51.35uA    168.2uA
[Ramp]
| variable   typ   min   max
dV/dt_f 0.65721807/1.1412918n 0.37038608/2.3526251n  0.8281624/0.73541785n
dV/dt_r 0.69569282/1.5884559n 0.45761755/4.0789241n 0.86915836/0.78787475n
R_load = 50
[Rising Waveform]
R_fixture = 50
V_fixture = 1.8
V_fixture_min = 1.62
V_fixture_max = 1.95
|   time   V(typ)   V(min)   V(max)
0s        706.4mV    1.003V     571.6mV
619.2ps   706.4mV    1.003V     589.3mV
678.9ps   706.4mV    1.003V     776.6mV
775ps     706.4mV    1.003V     1.57V
820.4ps   727.2mV    1.003V     1.786V
1.054ns   1.589V     1.003V     1.926V
1.129ns   1.727V     1.003V     1.934V
1.677ns   1.789V     1.548V     1.945V
1.924ns   1.792V     1.604V     1.946V
17.87ns   1.798V     1.619V     1.948V
[Rising Waveform]
R_fixture = 50
V_fixture = 0
V_fixture_min = 0
V_fixture_max = 0
|   time   V(typ)   V(min)   V(max)
0s        0V         0V         0V
794.4ps   0V         0V         0V
1.149ns   0V         0V         448.4mV
1.48ns    155.7mV    0V         866.7mV
1.731ns   301.8mV    0V         1.094V
2.117ns   519.2mV    13.06mV    1.259V
2.789ns   810.7mV    101.1mV    1.361V
4.296ns   1.042V     335.1mV    1.416V
7.592ns   1.126V     620.7mV    1.431V
18.06ns   1.141V     741.6mV    1.432V
[Falling Waveform]
R_fixture = 50
V_fixture = 1.8
V_fixture_min = 1.62
V_fixture_max = 1.95
|   time   V(typ)   V(min)   V(max)
0s        1.798V     1.618V     1.948V
909.8ps   1.798V     1.618V     1.93V
1.576ns   1.717V     1.618V     1.384V
2.081ns   1.501V     1.618V     726mV
2.436ns   1.326V     1.614V     600.4mV
3.231ns   842.9mV    1.525V     574.9mV
4.171ns   736.8mV    1.383V     571.4mV
5.571ns   711.4mV    1.145V     571mV
7.279ns   706.5mV    1.057V     571mV
17.87ns   705.8mV    1.005V     571mV
[Falling Waveform]
R_fixture = 50
V_fixture = 0
V_fixture_min = 0
V_fixture_max = 0
|   time   V(typ)   V(min)   V(max)
0s        1.14V      750.1mV    1.432V
903.4ps   1.14V      750.1mV    1.407V
1.341ns   1.114V     750.1mV    857.8mV
1.703ns   883.9mV    750.1mV    332.4mV
1.991ns   596.2mV    750.1mV    99.83mV
2.254ns   359.1mV    732.9mV    7.12mV
3.098ns   22.15mV    463.9mV    0V
3.935ns   0V         168.4mV    0V
5.063ns   0V         14.91mV    0V
18.06ns   0V         0V         0V
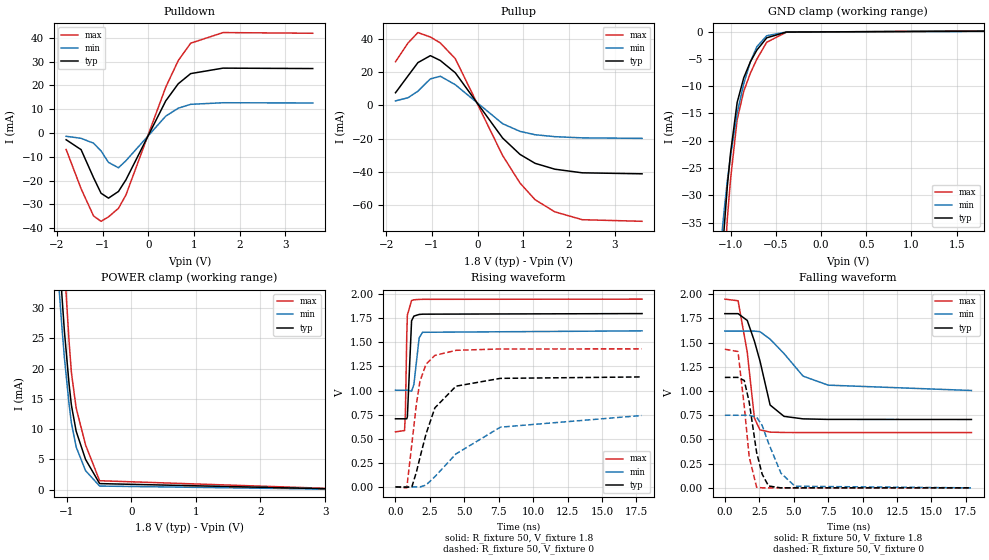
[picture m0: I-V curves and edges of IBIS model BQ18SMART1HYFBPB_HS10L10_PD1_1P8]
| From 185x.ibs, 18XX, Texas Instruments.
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|   Model Cell BQ18SMART1HYFBPB_HS10L10_PD1_1P8
|BQ18SMART1HYFBPB_HS10L10_PD1_1P8
[Model]   BQ18SMART1HYFBPB_HS10L10_PD1_1P8
Model_type   I/O
Polarity   Non-Inverting
Enable   Active-Low
Vinl =  0.63
Vinh =  1.17
Cref =  15pF
Rref =  100.0000M
Vref =  0V
Vmeas =  0.9
C_comp   0.915143p   0.8088923p   1.028577p
[Model Spec]
Vinl   0.63   0.567   0.6825
Vinh   1.17   1.053   1.2675
[Temperature Range]   25   125   -40
[Voltage Range]   1.8   1.62   1.95
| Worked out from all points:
|   slope of the pulldown table from 0 to 0.27 V, typ, clamps not added: 27.2 ohm
|   slope of the pullup table from 0 to 0.27 V, typ, clamps not added: 26 ohm
|   GND clamp passes 1 mA (typ) near -0.59 V on its own axis
|   POWER clamp passes 1 mA (typ) near -0.49 V on its own axis
|   rising waveform, R_fixture 50, V_fixture 1.8: 20-80 % time 147ps typ, 271ps min, 102ps max; typ from 0.707 V to 1.8 V
|   rising waveform, R_fixture 50, V_fixture 0: 20-80 % time 1.58ns typ, 3.94ns min, 786ps max; typ from 0 V to 1.14 V
|   falling waveform, R_fixture 50, V_fixture 1.8: 20-80 % time 1.13ns typ, 2.42ns min, 722ps max; typ from 1.8 V to 0.706 V
|   falling waveform, R_fixture 50, V_fixture 0: 20-80 % time 787ps typ, 1.24ns min, 597ps max; typ from 1.14 V to 0 V
| Nom Voltages:
|   BIASFET=1.8, VBBNW=1.1, VDD=1.1, VDDS=1.8, VSS=0, VSSS=0
| Min Voltages:
|   BIASFET=1.62, VBBNW=0.99, VDD=0.99, VDDS=1.62, VSS=0, VSSS=0
| Max Voltages:
|   BIASFET=1.95, VBBNW=1.21, VDD=1.21, VDDS=1.95, VSS=0, VSSS=0
[POWER_clamp]
|   voltage   I(typ)   I(min)   I(max)
-1.8V     196.9mA    157.5mA    250.4mA
-1.182V   51.67mA    43mA       68.61mA
-1.145V   44.45mA    37.16mA    60.1mA
-1.109V   37.9mA     31.74mA    52.07mA
-1.073V   31.79mA    26.6mA     44.33mA
-1.036V   26.12mA    21.74mA    36.87mA
-963.6mV  17.39mA    14.07mA    24.42mA
-927.3mV  13.91mA    10.96mA    19.29mA
-854.5mV  9.657mA    7.054mA    13.5mA
-709.1mV  4.995mA    3.131mA    7.393mA
-490.9mV  991uA      585.4uA    1.466mA
3.6V      0A         0A         0A
[Pulldown]
|   voltage   I(typ)   I(min)   I(max)
-1.8V     -2.835mA   -1.376mA   -6.938mA
-1.473V   -6.994mA   -2.229mA   -23.44mA
-1.2V     -18.79mA   -4.282mA   -34.89mA
-1.036V   -25.34mA   -7.531mA   -37.14mA
-872.7mV  -27.39mA   -12.36mA   -35.28mA
-654.5mV  -24.59mA   -14.63mA   -31.68mA
-490.9mV  -19.69mA   -11.65mA   -26.08mA
381.8mV   13.54mA    7.116mA    19.32mA
654.5mV   20.72mA    10.44mA    30.47mA
927.3mV   25mA       12.07mA    37.79mA
1.636V    27.3mA     12.74mA    42.26mA
3.6V      27.12mA    12.64mA    41.97mA
[Pullup]
|   voltage   I(typ)   I(min)   I(max)
-1.8V     7.614mA    2.74mA     26.22mA
-1.527V   17.69mA    4.626mA    37.43mA
-1.309V   25.69mA    8.541mA    43.72mA
-1.036V   29.87mA    15.94mA    41.05mA
-818.2mV  26.95mA    17.52mA    37.49mA
-490.9mV  19.61mA    12.45mA    28.08mA
545.5mV   -19.54mA   -10.94mA   -30.03mA
927.3mV   -29.38mA   -15.56mA   -46.58mA
1.255V    -34.7mA    -17.56mA   -56.51mA
1.691V    -38.25mA   -18.74mA   -63.85mA
2.291V    -40.42mA   -19.45mA   -68.55mA
3.6V      -41.01mA   -19.75mA   -69.5mA
[GND_clamp]
|   voltage   I(typ)   I(min)   I(max)
-1.8V     -274mA     -200.4mA   -365.5mA
-1.109V   -45.41mA   -39.33mA   -55.91mA
-1.073V   -36.49mA   -33.11mA   -44.46mA
-1.036V   -28.34mA   -27.37mA   -34.29mA
-1V       -22.19mA   -22.71mA   -27mA
-927.3mV  -12.97mA   -14.93mA   -16.12mA
-854.5mV  -8.452mA   -9.555mA   -10.93mA
-781.8mV  -5.549mA   -5.539mA   -7.634mA
-709.1mV  -3.363mA   -2.741mA   -5.028mA
-600mV    -1.121mA   -737.1uA   -1.924mA
-381.8mV  -62.21uA   -38.42uA   -93.33uA
1.8V      98.66uA    51.35uA    168.2uA
[Ramp]
| variable   typ   min   max
dV/dt_f  0.6572587/1.1339197n  0.3704657/2.4415858n  0.8281726/0.72536256n
dV/dt_r 0.69534671/1.5908432n 0.45750405/4.0856132n 0.86877462/0.78913594n
R_load = 50
[Rising Waveform]
R_fixture = 50
V_fixture = 1.8
V_fixture_min = 1.62
V_fixture_max = 1.95
|   time   V(typ)   V(min)   V(max)
0s        706.6mV    1.003V     571.7mV
657.9ps   706.6mV    1.003V     584.7mV
720.4ps   706.6mV    1.003V     768mV
818.2ps   706.6mV    1.003V     1.567V
863.1ps   727.5mV    1.003V     1.784V
1.168ns   1.723V     992.4mV    1.933V
1.337ns   1.772V     1.063V     1.941V
1.717ns   1.789V     1.545V     1.945V
1.963ns   1.792V     1.604V     1.946V
17.91ns   1.798V     1.619V     1.948V
[Rising Waveform]
R_fixture = 50
V_fixture = 0
V_fixture_min = 0
V_fixture_max = 0
|   time   V(typ)   V(min)   V(max)
0s        0V         0V         0V
818.8ps   -3.223mV   0V         -9.825mV
1.187ns   0V         0V         442.9mV
1.523ns   156.3mV    0V         865.5mV
1.779ns   305.5mV    0V         1.097V
2.218ns   549.5mV    19.19mV    1.273V
2.862ns   820.1mV    106.3mV    1.364V
4.395ns   1.045V     342.6mV    1.417V
7.618ns   1.126V     619.8mV    1.431V
17.87ns   1.141V     740.5mV    1.432V
[Falling Waveform]
R_fixture = 50
V_fixture = 1.8
V_fixture_min = 1.62
V_fixture_max = 1.95
|   time   V(typ)   V(min)   V(max)
0s        1.798V     1.618V     1.948V
963.9ps   1.798V     1.618V     1.931V
1.629ns   1.728V     1.618V     1.399V
2.149ns   1.514V     1.618V     720.7mV
2.55ns    1.311V     1.612V     597.9mV
3.289ns   855mV      1.535V     575.3mV
4.299ns   738mV      1.386V     571.5mV
5.683ns   712.1mV    1.153V     571mV
7.509ns   706.6mV    1.06V      571mV
17.91ns   705.8mV    1.005V     571mV
[Falling Waveform]
R_fixture = 50
V_fixture = 0
V_fixture_min = 0
V_fixture_max = 0
|   time   V(typ)   V(min)   V(max)
0s        1.14V      749.5mV    1.431V
954.8ps   1.14V      749.5mV    1.407V
1.411ns   1.108V     749.5mV    843mV
1.769ns   886.8mV    749.5mV    320.5mV
2.307ns   366mV      729.4mV    7.111mV
2.713ns   140.7mV    644.1mV    0V
3.175ns   19.47mV    461.1mV    0V
4.072ns   0V         152.3mV    0V
5.094ns   0V         16.59mV    0V
17.87ns   0V         0V         0V
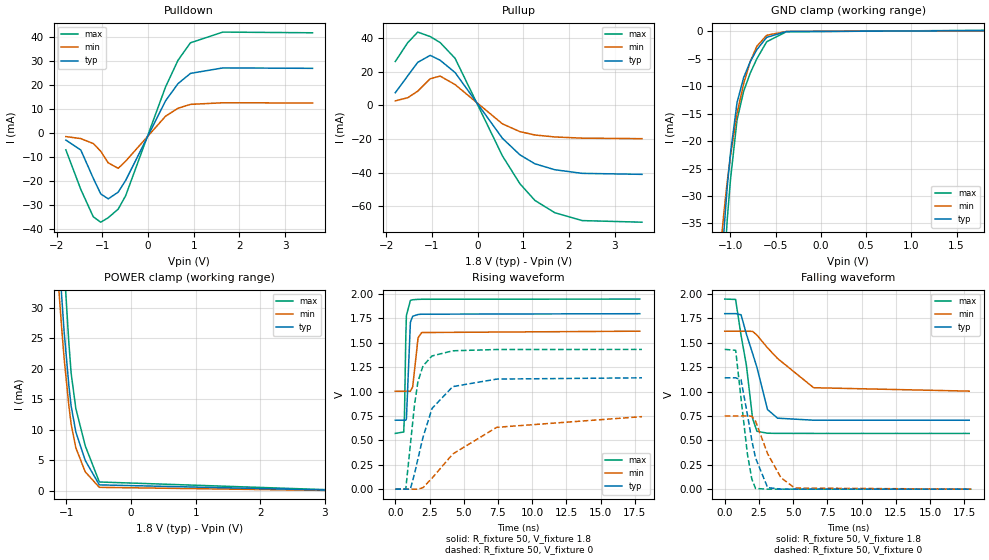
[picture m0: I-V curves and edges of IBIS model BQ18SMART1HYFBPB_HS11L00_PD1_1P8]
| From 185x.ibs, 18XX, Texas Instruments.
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|   Model Cell BQ18SMART1HYFBPB_HS11L00_PD1_1P8
|BQ18SMART1HYFBPB_HS11L00_PD1_1P8
[Model]   BQ18SMART1HYFBPB_HS11L00_PD1_1P8
Model_type   I/O
Polarity   Non-Inverting
Enable   Active-Low
Vinl =  0.63
Vinh =  1.17
Cref =  15pF
Rref =  100.0000M
Vref =  0V
Vmeas =  0.9
C_comp   0.915143p   0.8088923p   1.028577p
[Model Spec]
Vinl   0.63   0.567   0.6825
Vinh   1.17   1.053   1.2675
[Temperature Range]   25   125   -40
[Voltage Range]   1.8   1.62   1.95
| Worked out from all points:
|   slope of the pulldown table from 0 to 0.27 V, typ, clamps not added: 27.2 ohm
|   slope of the pullup table from 0 to 0.27 V, typ, clamps not added: 26 ohm
|   GND clamp passes 1 mA (typ) near -0.59 V on its own axis
|   POWER clamp passes 1 mA (typ) near -0.49 V on its own axis
|   rising waveform, R_fixture 50, V_fixture 1.8: 20-80 % time 145ps typ, 264ps min, 102ps max; typ from 0.707 V to 1.8 V
|   rising waveform, R_fixture 50, V_fixture 0: 20-80 % time 1.49ns typ, 3.71ns min, 739ps max; typ from 0 V to 1.14 V
|   falling waveform, R_fixture 50, V_fixture 1.8: 20-80 % time 1.28ns typ, 2.28ns min, 841ps max; typ from 1.8 V to 0.706 V
|   falling waveform, R_fixture 50, V_fixture 0: 20-80 % time 943ps typ, 1.4ns min, 712ps max; typ from 1.14 V to 0 V
| Nom Voltages:
|   BIASFET=1.8, VBBNW=1.1, VDD=1.1, VDDS=1.8, VSS=0, VSSS=0
| Min Voltages:
|   BIASFET=1.62, VBBNW=0.99, VDD=0.99, VDDS=1.62, VSS=0, VSSS=0
| Max Voltages:
|   BIASFET=1.95, VBBNW=1.21, VDD=1.21, VDDS=1.95, VSS=0, VSSS=0
[POWER_clamp]
|   voltage   I(typ)   I(min)   I(max)
-1.8V     196.9mA    157.5mA    250.4mA
-1.182V   51.67mA    43mA       68.61mA
-1.145V   44.45mA    37.16mA    60.1mA
-1.109V   37.9mA     31.74mA    52.07mA
-1.073V   31.79mA    26.6mA     44.33mA
-1.036V   26.12mA    21.74mA    36.87mA
-963.6mV  17.39mA    14.07mA    24.42mA
-927.3mV  13.91mA    10.96mA    19.29mA
-854.5mV  9.657mA    7.054mA    13.5mA
-709.1mV  4.995mA    3.131mA    7.393mA
-490.9mV  991uA      585.4uA    1.466mA
3.6V      0A         0A         0A
[Pulldown]
|   voltage   I(typ)   I(min)   I(max)
-1.8V     -2.835mA   -1.376mA   -6.938mA
-1.473V   -6.994mA   -2.229mA   -23.44mA
-1.2V     -18.79mA   -4.282mA   -34.89mA
-1.036V   -25.34mA   -7.531mA   -37.14mA
-872.7mV  -27.39mA   -12.36mA   -35.28mA
-654.5mV  -24.59mA   -14.63mA   -31.68mA
-490.9mV  -19.69mA   -11.65mA   -26.08mA
381.8mV   13.54mA    7.116mA    19.32mA
654.5mV   20.72mA    10.44mA    30.47mA
927.3mV   25mA       12.07mA    37.79mA
1.636V    27.3mA     12.74mA    42.26mA
3.6V      27.12mA    12.64mA    41.97mA
[Pullup]
|   voltage   I(typ)   I(min)   I(max)
-1.8V     7.614mA    2.74mA     26.22mA
-1.527V   17.69mA    4.626mA    37.43mA
-1.309V   25.69mA    8.541mA    43.72mA
-1.036V   29.87mA    15.94mA    41.05mA
-818.2mV  26.95mA    17.52mA    37.49mA
-490.9mV  19.61mA    12.45mA    28.08mA
545.5mV   -19.54mA   -10.94mA   -30.03mA
927.3mV   -29.38mA   -15.56mA   -46.58mA
1.255V    -34.7mA    -17.56mA   -56.51mA
1.691V    -38.25mA   -18.74mA   -63.85mA
2.291V    -40.42mA   -19.45mA   -68.55mA
3.6V      -41.01mA   -19.75mA   -69.5mA
[GND_clamp]
|   voltage   I(typ)   I(min)   I(max)
-1.8V     -274mA     -200.4mA   -365.5mA
-1.109V   -45.41mA   -39.33mA   -55.91mA
-1.073V   -36.49mA   -33.11mA   -44.46mA
-1.036V   -28.34mA   -27.37mA   -34.29mA
-1V       -22.19mA   -22.71mA   -27mA
-927.3mV  -12.97mA   -14.93mA   -16.12mA
-854.5mV  -8.452mA   -9.555mA   -10.93mA
-781.8mV  -5.549mA   -5.539mA   -7.634mA
-709.1mV  -3.363mA   -2.741mA   -5.028mA
-600mV    -1.121mA   -737.1uA   -1.924mA
-381.8mV  -62.21uA   -38.42uA   -93.33uA
1.8V      98.66uA    51.35uA    168.2uA
[Ramp]
| variable   typ   min   max
dV/dt_f 0.65744473/1.2819511n 0.37041402/2.2877673n 0.82855589/0.84476991n
dV/dt_r 0.69339479/1.4923745n 0.45700173/3.8149661n 0.86794372/0.74189976n
R_load = 50
[Rising Waveform]
R_fixture = 50
V_fixture = 1.8
V_fixture_min = 1.62
V_fixture_max = 1.95
|   time   V(typ)   V(min)   V(max)
0s        706.6mV    1.004V     571.3mV
614.7ps   706.6mV    1.004V     585.7mV
672.9ps   706.6mV    1.004V     771.9mV
768ps     706.6mV    1.004V     1.562V
813ps     721.5mV    1.004V     1.781V
1.104ns   1.711V     1.004V     1.934V
1.272ns   1.772V     1.049V     1.941V
1.665ns   1.79V      1.551V     1.945V
1.927ns   1.793V     1.605V     1.946V
17.87ns   1.798V     1.619V     1.948V
[Rising Waveform]
R_fixture = 50
V_fixture = 0
V_fixture_min = 0
V_fixture_max = 0
|   time   V(typ)   V(min)   V(max)
0s        0V         0V         0V
764.7ps   0V         0V         0V
1.1ns     0V         0V         454.4mV
1.415ns   161.8mV    0V         874.7mV
1.654ns   311mV      0V         1.101V
2.024ns   531.1mV    15.46mV    1.263V
2.686ns   827.6mV    112.6mV    1.365V
4.2ns     1.051V     360.5mV    1.418V
7.411ns   1.128V     633.7mV    1.431V
18.03ns   1.141V     743.3mV    1.432V
[Falling Waveform]
R_fixture = 50
V_fixture = 1.8
V_fixture_min = 1.62
V_fixture_max = 1.95
|   time   V(typ)   V(min)   V(max)
0s        1.798V     1.618V     1.947V
794.3ps   1.798V     1.618V     1.943V
1.192ns   1.786V     1.618V     1.576V
1.582ns   1.589V     1.618V     1.27V
2.036ns   1.39V      1.616V     724.1mV
2.353ns   1.247V     1.578V     593.1mV
3.125ns   815.3mV    1.448V     573mV
3.865ns   726.9mV    1.338V     571.2mV
6.497ns   706.2mV    1.039V     571mV
17.87ns   705.8mV    1.004V     571mV
[Falling Waveform]
R_fixture = 50
V_fixture = 0
V_fixture_min = 0
V_fixture_max = 0
|   time   V(typ)   V(min)   V(max)
0s        1.14V      750mV      1.432V
799.5ps   1.14V      750mV      1.422V
1.192ns   1.121V     750mV      928.2mV
1.659ns   762.4mV    750mV      357.9mV
1.983ns   496.5mV    746.9mV    101.4mV
2.252ns   319mV      696.6mV    6.953mV
3.134ns   16.41mV    363.7mV    0V
4.108ns   0V         117.6mV    0V
5.123ns   0V         11.26mV    0V
18.03ns   0V         0V         0V
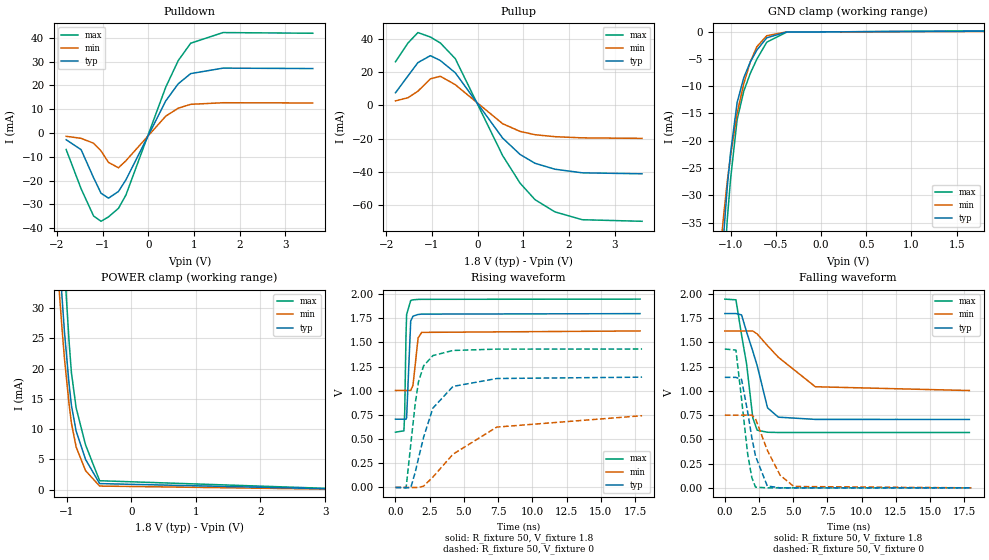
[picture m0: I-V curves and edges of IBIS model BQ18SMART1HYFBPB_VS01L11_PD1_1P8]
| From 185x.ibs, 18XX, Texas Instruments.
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|   Model Cell BQ18SMART1HYFBPB_VS01L11_PD1_1P8
|BQ18SMART1HYFBPB_VS01L11_PD1_1P8
[Model]   BQ18SMART1HYFBPB_VS01L11_PD1_1P8
Model_type   I/O
Polarity   Non-Inverting
Enable   Active-Low
Vinl =  0.63
Vinh =  1.17
Cref =  15pF
Rref =  100.0000M
Vref =  0V
Vmeas =  0.9
C_comp   0.9029199p   0.7983694p   1.014934p
[Model Spec]
Vinl   0.63   0.567   0.6825
Vinh   1.17   1.053   1.2675
[Temperature Range]   25   125   -40
[Voltage Range]   1.8   1.62   1.95
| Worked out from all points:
|   slope of the pulldown table from 0 to 0.27 V, typ, clamps not added: 27.2 ohm
|   slope of the pullup table from 0 to 0.27 V, typ, clamps not added: 26 ohm
|   GND clamp passes 1 mA (typ) near -0.59 V on its own axis
|   POWER clamp passes 1 mA (typ) near -0.49 V on its own axis
|   rising waveform, R_fixture 50, V_fixture 1.8: 20-80 % time 143ps typ, 262ps min, 100ps max; typ from 0.706 V to 1.8 V
|   rising waveform, R_fixture 50, V_fixture 0: 20-80 % time 1.53ns typ, 3.8ns min, 759ps max; typ from 0 V to 1.14 V
|   falling waveform, R_fixture 50, V_fixture 1.8: 20-80 % time 1.25ns typ, 2.25ns min, 820ps max; typ from 1.8 V to 0.706 V
|   falling waveform, R_fixture 50, V_fixture 0: 20-80 % time 908ps typ, 1.34ns min, 689ps max; typ from 1.14 V to 0 V
| Nom Voltages:
|   BIASFET=1.8, VBBNW=1.1, VDD=1.1, VDDS=1.8, VSS=0, VSSS=0
| Min Voltages:
|   BIASFET=1.62, VBBNW=0.99, VDD=0.99, VDDS=1.62, VSS=0, VSSS=0
| Max Voltages:
|   BIASFET=1.95, VBBNW=1.21, VDD=1.21, VDDS=1.95, VSS=0, VSSS=0
[POWER_clamp]
|   voltage   I(typ)   I(min)   I(max)
-1.8V     196.9mA    157.5mA    250.4mA
-1.182V   51.67mA    43mA       68.61mA
-1.145V   44.45mA    37.16mA    60.1mA
-1.109V   37.9mA     31.74mA    52.07mA
-1.073V   31.79mA    26.6mA     44.33mA
-1.036V   26.12mA    21.74mA    36.87mA
-963.6mV  17.39mA    14.07mA    24.42mA
-927.3mV  13.91mA    10.96mA    19.29mA
-854.5mV  9.657mA    7.054mA    13.5mA
-709.1mV  4.995mA    3.131mA    7.393mA
-490.9mV  991uA      585.4uA    1.466mA
3.6V      0A         0A         0A
[Pulldown]
|   voltage   I(typ)   I(min)   I(max)
-1.8V     -2.835mA   -1.376mA   -6.938mA
-1.473V   -6.994mA   -2.229mA   -23.44mA
-1.2V     -18.79mA   -4.282mA   -34.89mA
-1.036V   -25.34mA   -7.531mA   -37.14mA
-872.7mV  -27.39mA   -12.36mA   -35.28mA
-654.5mV  -24.59mA   -14.63mA   -31.68mA
-490.9mV  -19.69mA   -11.65mA   -26.08mA
381.8mV   13.54mA    7.116mA    19.32mA
654.5mV   20.72mA    10.44mA    30.47mA
927.3mV   25mA       12.07mA    37.79mA
1.636V    27.3mA     12.74mA    42.26mA
3.6V      27.12mA    12.64mA    41.97mA
[Pullup]
|   voltage   I(typ)   I(min)   I(max)
-1.8V     7.614mA    2.74mA     26.22mA
-1.527V   17.69mA    4.626mA    37.43mA
-1.309V   25.69mA    8.541mA    43.72mA
-1.036V   29.87mA    15.94mA    41.05mA
-818.2mV  26.95mA    17.52mA    37.49mA
-490.9mV  19.61mA    12.45mA    28.08mA
545.5mV   -19.54mA   -10.94mA   -30.03mA
927.3mV   -29.38mA   -15.56mA   -46.58mA
1.255V    -34.7mA    -17.56mA   -56.51mA
1.691V    -38.25mA   -18.74mA   -63.85mA
2.291V    -40.42mA   -19.45mA   -68.55mA
3.6V      -41.01mA   -19.75mA   -69.5mA
[GND_clamp]
|   voltage   I(typ)   I(min)   I(max)
-1.8V     -274mA     -200.4mA   -365.5mA
-1.109V   -45.41mA   -39.33mA   -55.91mA
-1.073V   -36.49mA   -33.11mA   -44.46mA
-1.036V   -28.34mA   -27.37mA   -34.29mA
-1V       -22.19mA   -22.71mA   -27mA
-927.3mV  -12.97mA   -14.93mA   -16.12mA
-854.5mV  -8.452mA   -9.555mA   -10.93mA
-781.8mV  -5.549mA   -5.539mA   -7.634mA
-709.1mV  -3.363mA   -2.741mA   -5.028mA
-600mV    -1.121mA   -737.1uA   -1.924mA
-381.8mV  -62.21uA   -38.42uA   -93.33uA
1.8V      98.66uA    51.35uA    168.2uA
[Ramp]
| variable   typ   min   max
dV/dt_f 0.65733886/1.2514729n 0.37034028/2.2655488n 0.82842148/0.82388976n
dV/dt_r 0.69503507/1.5338301n  0.4575574/3.9251301n 0.86868078/0.76223549n
R_load = 50
[Rising Waveform]
R_fixture = 50
V_fixture = 1.8
V_fixture_min = 1.62
V_fixture_max = 1.95
|   time   V(typ)   V(min)   V(max)
0s        706.3mV    1.003V     571.9mV
614.5ps   706.3mV    1.003V     585.6mV
672.7ps   706.3mV    1.003V     771.8mV
768ps     706.3mV    1.003V     1.573V
813.2ps   722.2mV    1.003V     1.788V
1.112ns   1.721V     1.003V     1.934V
1.278ns   1.772V     1.056V     1.941V
1.653ns   1.789V     1.546V     1.945V
1.916ns   1.793V     1.604V     1.946V
17.87ns   1.798V     1.619V     1.948V
[Rising Waveform]
R_fixture = 50
V_fixture = 0
V_fixture_min = 0
V_fixture_max = 0
|   time   V(typ)   V(min)   V(max)
0s        0V         0V         0V
779.5ps   -4.084mV   0V         0V
1.122ns   0V         0V         451.5mV
1.444ns   159mV      0V         870.8mV
1.682ns   303.1mV    0V         1.093V
2.055ns   520.3mV    13.43mV    1.258V
2.733ns   820.7mV    107.8mV    1.364V
4.202ns   1.045V     344mV      1.417V
7.403ns   1.127V     624.6mV    1.431V
18.02ns   1.141V     742.1mV    1.432V
[Falling Waveform]
R_fixture = 50
V_fixture = 1.8
V_fixture_min = 1.62
V_fixture_max = 1.95
|   time   V(typ)   V(min)   V(max)
0s        1.798V     1.618V     1.947V
811.5ps   1.798V     1.618V     1.94V
1.224ns   1.784V     1.618V     1.576V
1.592ns   1.608V     1.618V     1.276V
2.042ns   1.41V      1.618V     722.8mV
2.363ns   1.262V     1.588V     595.2mV
3.12ns    825.4mV    1.467V     573.6mV
3.912ns   729.3mV    1.347V     571.3mV
6.616ns   706.3mV    1.043V     571mV
17.87ns   705.8mV    1.004V     571mV
[Falling Waveform]
R_fixture = 50
V_fixture = 0
V_fixture_min = 0
V_fixture_max = 0
|   time   V(typ)   V(min)   V(max)
0s        1.14V      750.4mV    1.432V
811.5ps   1.14V      750.4mV    1.421V
1.224ns   1.118V     750.4mV    912.5mV
1.671ns   781.1mV    750.4mV    346.2mV
1.974ns   516.9mV    750.4mV    105.1mV
2.245ns   326.5mV    712.4mV    7.241mV
3.102ns   19.39mV    388.1mV    0V
4.041ns   0V         130.1mV    0V
5.042ns   0V         14.2mV     0V
18.02ns   0V         0V         0V
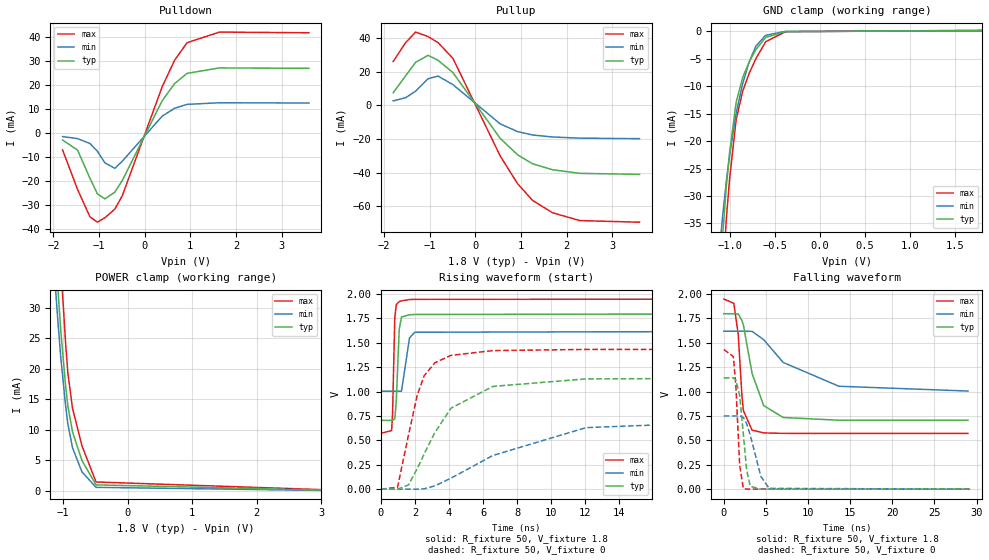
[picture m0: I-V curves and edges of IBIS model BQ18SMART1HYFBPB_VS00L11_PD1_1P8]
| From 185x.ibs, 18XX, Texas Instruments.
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|   Model Cell BQ18SMART1HYFBPB_VS00L11_PD1_1P8
|BQ18SMART1HYFBPB_VS00L11_PD1_1P8
[Model]   BQ18SMART1HYFBPB_VS00L11_PD1_1P8
Model_type   I/O
Polarity   Non-Inverting
Enable   Active-Low
Vinl =  0.63
Vinh =  1.17
Cref =  15pF
Rref =  100.0000M
Vref =  0V
Vmeas =  0.9
C_comp   0.9029199p   0.7983694p   1.014934p
[Model Spec]
Vinl   0.63   0.567   0.6825
Vinh   1.17   1.053   1.2675
[Temperature Range]   25   125   -40
[Voltage Range]   1.8   1.62   1.95
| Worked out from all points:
|   slope of the pulldown table from 0 to 0.27 V, typ, clamps not added: 27.2 ohm
|   slope of the pullup table from 0 to 0.27 V, typ, clamps not added: 26 ohm
|   GND clamp passes 1 mA (typ) near -0.59 V on its own axis
|   POWER clamp passes 1 mA (typ) near -0.49 V on its own axis
|   rising waveform, R_fixture 50, V_fixture 1.8: 20-80 % time 147ps typ, 269ps min, 101ps max; typ from 0.705 V to 1.8 V
|   rising waveform, R_fixture 50, V_fixture 0: 20-80 % time 2.44ns typ, 6.34ns min, 1.17ns max; typ from 0 V to 1.14 V
|   falling waveform, R_fixture 50, V_fixture 1.8: 20-80 % time 1.67ns typ, 5.27ns min, 657ps max; typ from 1.8 V to 0.706 V
|   falling waveform, R_fixture 50, V_fixture 0: 20-80 % time 709ps typ, 1.33ns min, 482ps max; typ from 1.14 V to 0 V
| Nom Voltages:
|   BIASFET=1.8, VBBNW=1.1, VDD=1.1, VDDS=1.8, VSS=0, VSSS=0
| Min Voltages:
|   BIASFET=1.62, VBBNW=0.99, VDD=0.99, VDDS=1.62, VSS=0, VSSS=0
| Max Voltages:
|   BIASFET=1.95, VBBNW=1.21, VDD=1.21, VDDS=1.95, VSS=0, VSSS=0
[POWER_clamp]
|   voltage   I(typ)   I(min)   I(max)
-1.8V     196.9mA    157.5mA    250.4mA
-1.182V   51.67mA    43mA       68.61mA
-1.145V   44.45mA    37.16mA    60.1mA
-1.109V   37.9mA     31.74mA    52.07mA
-1.073V   31.79mA    26.6mA     44.33mA
-1.036V   26.12mA    21.74mA    36.87mA
-963.6mV  17.39mA    14.07mA    24.42mA
-927.3mV  13.91mA    10.96mA    19.29mA
-854.5mV  9.657mA    7.054mA    13.5mA
-709.1mV  4.995mA    3.131mA    7.393mA
-490.9mV  991uA      585.4uA    1.466mA
3.6V      0A         0A         0A
[Pulldown]
|   voltage   I(typ)   I(min)   I(max)
-1.8V     -2.835mA   -1.376mA   -6.938mA
-1.473V   -6.994mA   -2.229mA   -23.44mA
-1.2V     -18.79mA   -4.282mA   -34.89mA
-1.036V   -25.34mA   -7.531mA   -37.14mA
-872.7mV  -27.39mA   -12.36mA   -35.28mA
-654.5mV  -24.59mA   -14.63mA   -31.68mA
-490.9mV  -19.69mA   -11.65mA   -26.08mA
381.8mV   13.54mA    7.116mA    19.32mA
654.5mV   20.72mA    10.44mA    30.47mA
927.3mV   25mA       12.07mA    37.79mA
1.636V    27.3mA     12.74mA    42.26mA
3.6V      27.12mA    12.64mA    41.97mA
[Pullup]
|   voltage   I(typ)   I(min)   I(max)
-1.8V     7.614mA    2.74mA     26.22mA
-1.527V   17.69mA    4.626mA    37.43mA
-1.309V   25.69mA    8.541mA    43.72mA
-1.036V   29.87mA    15.94mA    41.05mA
-818.2mV  26.95mA    17.52mA    37.49mA
-490.9mV  19.61mA    12.45mA    28.08mA
545.5mV   -19.54mA   -10.94mA   -30.03mA
927.3mV   -29.38mA   -15.56mA   -46.58mA
1.255V    -34.7mA    -17.56mA   -56.51mA
1.691V    -38.25mA   -18.74mA   -63.85mA
2.291V    -40.42mA   -19.45mA   -68.55mA
3.6V      -41.01mA   -19.75mA   -69.5mA
[GND_clamp]
|   voltage   I(typ)   I(min)   I(max)
-1.8V     -274mA     -200.4mA   -365.5mA
-1.109V   -45.41mA   -39.33mA   -55.91mA
-1.073V   -36.49mA   -33.11mA   -44.46mA
-1.036V   -28.34mA   -27.37mA   -34.29mA
-1V       -22.19mA   -22.71mA   -27mA
-927.3mV  -12.97mA   -14.93mA   -16.12mA
-854.5mV  -8.452mA   -9.555mA   -10.93mA
-781.8mV  -5.549mA   -5.539mA   -7.634mA
-709.1mV  -3.363mA   -2.741mA   -5.028mA
-600mV    -1.121mA   -737.1uA   -1.924mA
-381.8mV  -62.21uA   -38.42uA   -93.33uA
1.8V      98.66uA    51.35uA    168.2uA
[Ramp]
| variable   typ   min   max
dV/dt_f 0.65748427/1.6777558n 0.37095328/5.2924621n 0.82805451/0.66024246n
dV/dt_r 0.69621084/2.455609n  0.45675343/6.5148168n 0.87496233/1.177027n
R_load = 50
[Rising Waveform]
R_fixture = 50
V_fixture = 1.8
V_fixture_min = 1.62
V_fixture_max = 1.95
|   time   V(typ)   V(min)   V(max)
0s        705.1mV    1.004V     571.9mV
631.8ps   705.1mV    1.004V     601.2mV
687.2ps   705.1mV    1.004V     784.7mV
816ps     720.2mV    1.004V     1.756V
902.7ps   894.7mV    1.004V     1.89V
1.076ns   1.638V     1.004V     1.922V
1.211ns   1.765V     1.004V     1.93V
1.68ns    1.787V     1.55V      1.943V
1.988ns   1.79V      1.608V     1.945V
28.98ns   1.798V     1.619V     1.948V
[Rising Waveform]
R_fixture = 50
V_fixture = 0
V_fixture_min = 0
V_fixture_max = 0
|   time   V(typ)   V(min)   V(max)
0s        0V         0V         0V
977.2ps   0V         0V         19.07mV
1.612ns   42.68mV    0V         546.6mV
2.132ns   209.1mV    0V         961.1mV
2.542ns   361.4mV    3.817mV    1.162V
3.164ns   578.7mV    33.29mV    1.295V
4.113ns   830mV      112.5mV    1.371V
6.579ns   1.053V     345.7mV    1.42V
12.05ns   1.13V      630.8mV    1.432V
29.24ns   1.141V     743.5mV    1.432V
[Falling Waveform]
R_fixture = 50
V_fixture = 1.8
V_fixture_min = 1.62
V_fixture_max = 1.95
|   time   V(typ)   V(min)   V(max)
0s        1.797V     1.618V     1.947V
1.192ns   1.797V     1.618V     1.904V
1.716ns   1.795V     1.618V     1.581V
2.145ns   1.729V     1.618V     970.8mV
2.324ns   1.683V     1.618V     804.9mV
3.361ns   1.184V     1.616V     604.2mV
4.741ns   855.8mV    1.531V     576.4mV
7.05ns    734.1mV    1.298V     571.3mV
13.67ns   706.2mV    1.054V     571mV
28.98ns   705.8mV    1.005V     571mV
[Falling Waveform]
R_fixture = 50
V_fixture = 0
V_fixture_min = 0
V_fixture_max = 0
|   time   V(typ)   V(min)   V(max)
0s        1.14V      749.9mV    1.431V
1.141ns   1.14V      749.9mV    1.357V
1.432ns   1.117V     749.9mV    1.059V
1.887ns   959mV      749.9mV    242mV
2.328ns   558.1mV    733.6mV    5.58mV
2.713ns   196.7mV    672.2mV    0V
3.137ns   30.45mV    554.1mV    0V
4.403ns   0V         130.2mV    0V
5.375ns   0V         8.623mV    0V
29.24ns   0V         0V         0V
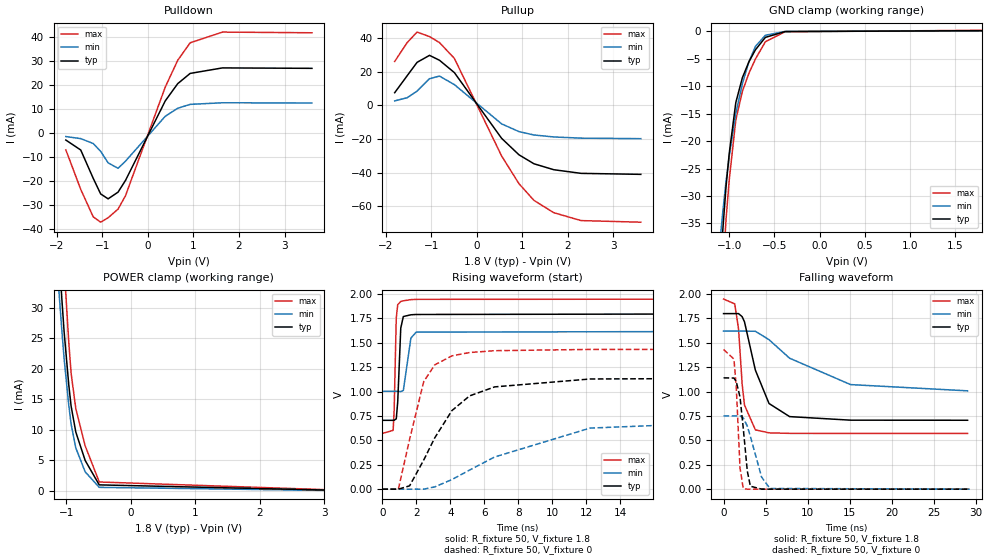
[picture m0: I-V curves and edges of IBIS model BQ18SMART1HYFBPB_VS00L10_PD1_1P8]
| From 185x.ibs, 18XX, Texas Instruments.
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|   Model Cell BQ18SMART1HYFBPB_VS00L10_PD1_1P8
|BQ18SMART1HYFBPB_VS00L10_PD1_1P8
[Model]   BQ18SMART1HYFBPB_VS00L10_PD1_1P8
Model_type   I/O
Polarity   Non-Inverting
Enable   Active-Low
Vinl =  0.63
Vinh =  1.17
Cref =  15pF
Rref =  100.0000M
Vref =  0V
Vmeas =  0.9
C_comp   0.9029199p   0.7983694p   1.014934p
[Model Spec]
Vinl   0.63   0.567   0.6825
Vinh   1.17   1.053   1.2675
[Temperature Range]   25   125   -40
[Voltage Range]   1.8   1.62   1.95
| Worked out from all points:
|   slope of the pulldown table from 0 to 0.27 V, typ, clamps not added: 27.2 ohm
|   slope of the pullup table from 0 to 0.27 V, typ, clamps not added: 26 ohm
|   GND clamp passes 1 mA (typ) near -0.59 V on its own axis
|   POWER clamp passes 1 mA (typ) near -0.49 V on its own axis
|   rising waveform, R_fixture 50, V_fixture 1.8: 20-80 % time 147ps typ, 271ps min, 102ps max; typ from 0.705 V to 1.8 V
|   rising waveform, R_fixture 50, V_fixture 0: 20-80 % time 2.51ns typ, 6.5ns min, 1.19ns max; typ from 0 V to 1.14 V
|   falling waveform, R_fixture 50, V_fixture 1.8: 20-80 % time 2.17ns typ, 6.6ns min, 772ps max; typ from 1.8 V to 0.706 V
|   falling waveform, R_fixture 50, V_fixture 0: 20-80 % time 757ps typ, 1.42ns min, 464ps max; typ from 1.14 V to 0 V
| Nom Voltages:
|   BIASFET=1.8, VBBNW=1.1, VDD=1.1, VDDS=1.8, VSS=0, VSSS=0
| Min Voltages:
|   BIASFET=1.62, VBBNW=0.99, VDD=0.99, VDDS=1.62, VSS=0, VSSS=0
| Max Voltages:
|   BIASFET=1.95, VBBNW=1.21, VDD=1.21, VDDS=1.95, VSS=0, VSSS=0
[POWER_clamp]
|   voltage   I(typ)   I(min)   I(max)
-1.8V     196.9mA    157.5mA    250.4mA
-1.182V   51.67mA    43mA       68.61mA
-1.145V   44.45mA    37.16mA    60.1mA
-1.109V   37.9mA     31.74mA    52.07mA
-1.073V   31.79mA    26.6mA     44.33mA
-1.036V   26.12mA    21.74mA    36.87mA
-963.6mV  17.39mA    14.07mA    24.42mA
-927.3mV  13.91mA    10.96mA    19.29mA
-854.5mV  9.657mA    7.054mA    13.5mA
-709.1mV  4.995mA    3.131mA    7.393mA
-490.9mV  991uA      585.4uA    1.466mA
3.6V      0A         0A         0A
[Pulldown]
|   voltage   I(typ)   I(min)   I(max)
-1.8V     -2.835mA   -1.376mA   -6.938mA
-1.473V   -6.994mA   -2.229mA   -23.44mA
-1.2V     -18.79mA   -4.282mA   -34.89mA
-1.036V   -25.34mA   -7.531mA   -37.14mA
-872.7mV  -27.39mA   -12.36mA   -35.28mA
-654.5mV  -24.59mA   -14.63mA   -31.68mA
-490.9mV  -19.69mA   -11.65mA   -26.08mA
381.8mV   13.54mA    7.116mA    19.32mA
654.5mV   20.72mA    10.44mA    30.47mA
927.3mV   25mA       12.07mA    37.79mA
1.636V    27.3mA     12.74mA    42.26mA
3.6V      27.12mA    12.64mA    41.97mA
[Pullup]
|   voltage   I(typ)   I(min)   I(max)
-1.8V     7.614mA    2.74mA     26.22mA
-1.527V   17.69mA    4.626mA    37.43mA
-1.309V   25.69mA    8.541mA    43.72mA
-1.036V   29.87mA    15.94mA    41.05mA
-818.2mV  26.95mA    17.52mA    37.49mA
-490.9mV  19.61mA    12.45mA    28.08mA
545.5mV   -19.54mA   -10.94mA   -30.03mA
927.3mV   -29.38mA   -15.56mA   -46.58mA
1.255V    -34.7mA    -17.56mA   -56.51mA
1.691V    -38.25mA   -18.74mA   -63.85mA
2.291V    -40.42mA   -19.45mA   -68.55mA
3.6V      -41.01mA   -19.75mA   -69.5mA
[GND_clamp]
|   voltage   I(typ)   I(min)   I(max)
-1.8V     -274mA     -200.4mA   -365.5mA
-1.109V   -45.41mA   -39.33mA   -55.91mA
-1.073V   -36.49mA   -33.11mA   -44.46mA
-1.036V   -28.34mA   -27.37mA   -34.29mA
-1V       -22.19mA   -22.71mA   -27mA
-927.3mV  -12.97mA   -14.93mA   -16.12mA
-854.5mV  -8.452mA   -9.555mA   -10.93mA
-781.8mV  -5.549mA   -5.539mA   -7.634mA
-709.1mV  -3.363mA   -2.741mA   -5.028mA
-600mV    -1.121mA   -737.1uA   -1.924mA
-381.8mV  -62.21uA   -38.42uA   -93.33uA
1.8V      98.66uA    51.35uA    168.2uA
[Ramp]
| variable   typ   min   max
dV/dt_f 0.65758292/2.1679293n 0.37105728/6.6908475n 0.82812344/0.77436324n
dV/dt_r 0.69600125/2.5188772n 0.45660556/6.7080826n 0.87466562/1.2029274n
R_load = 50
[Rising Waveform]
R_fixture = 50
V_fixture = 1.8
V_fixture_min = 1.62
V_fixture_max = 1.95
|   time   V(typ)   V(min)   V(max)
0s        705.4mV    1.003V     571mV
634.8ps   705.4mV    1.003V     602.7mV
693.7ps   705.4mV    1.003V     810.8mV
818.4ps   720.9mV    1.003V     1.754V
904.5ps   894.6mV    1.003V     1.89V
1.084ns   1.651V     1V         1.923V
1.235ns   1.769V     1.012V     1.93V
1.682ns   1.787V     1.549V     1.942V
1.994ns   1.79V      1.609V     1.945V
28.98ns   1.798V     1.619V     1.948V
[Rising Waveform]
R_fixture = 50
V_fixture = 0
V_fixture_min = 0
V_fixture_max = 0
|   time   V(typ)   V(min)   V(max)
0s        0V         0V         0V
939.9ps   0V         0V         0V
1.605ns   34.23mV    0V         510.8mV
2.438ns   299.3mV    0V         1.103V
3.087ns   526.3mV    23.41mV    1.274V
4.096ns   804.8mV    98.38mV    1.366V
5.137ns   955.7mV    195.8mV    1.4V
6.614ns   1.048V     329.7mV    1.419V
12.24ns   1.129V     626mV      1.432V
29.23ns   1.141V     742.3mV    1.432V
[Falling Waveform]
R_fixture = 50
V_fixture = 1.8
V_fixture_min = 1.62
V_fixture_max = 1.95
|   time   V(typ)   V(min)   V(max)
0s        1.798V     1.619V     1.947V
1.329ns   1.798V     1.619V     1.898V
1.784ns   1.798V     1.619V     1.641V
2.216ns   1.766V     1.619V     1.071V
2.492ns   1.713V     1.619V     860.9mV
3.781ns   1.219V     1.617V     607.4mV
5.403ns   877.1mV    1.531V     576.8mV
7.849ns   743.1mV    1.341V     571.5mV
15.09ns   706.6mV    1.071V     571mV
28.98ns   705.8mV    1.007V     571mV
[Falling Waveform]
R_fixture = 50
V_fixture = 0
V_fixture_min = 0
V_fixture_max = 0
|   time   V(typ)   V(min)   V(max)
0s        1.14V      750.1mV    1.431V
1.238ns   1.138V     750.1mV    1.332V
1.514ns   1.101V     750.1mV    1.045V
1.958ns   943mV      750.1mV    216.8mV
2.343ns   624.4mV    729mV      6.212mV
2.822ns   185.9mV    645.9mV    0V
3.188ns   30.42mV    539.9mV    0V
4.522ns   0V         123.5mV    0V
5.501ns   0V         7.308mV    0V
29.23ns   0V         0V         0V
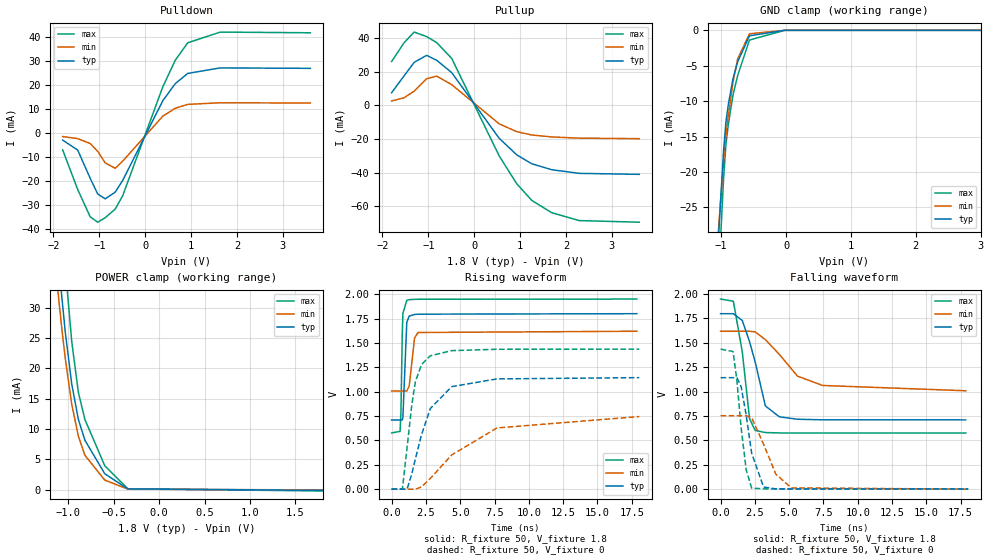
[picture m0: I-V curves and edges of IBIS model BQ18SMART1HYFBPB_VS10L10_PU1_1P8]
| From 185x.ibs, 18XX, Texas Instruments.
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|   Model Cell BQ18SMART1HYFBPB_VS10L10_PU1_1P8
|BQ18SMART1HYFBPB_VS10L10_PU1_1P8
[Model]   BQ18SMART1HYFBPB_VS10L10_PU1_1P8
Model_type   I/O
Polarity   Non-Inverting
Enable   Active-Low
Vinl =  0.63
Vinh =  1.17
Cref =  15pF
Rref =  100.0000M
Vref =  0V
Vmeas =  0.9
C_comp   0.9029199p   0.7983694p   1.014934p
[Model Spec]
Vinl   0.63   0.567   0.6825
Vinh   1.17   1.053   1.2675
[Temperature Range]   25   125   -40
[Voltage Range]   1.8   1.62   1.95
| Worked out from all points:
|   slope of the pulldown table from 0 to 0.27 V, typ, clamps not added: 27.2 ohm
|   slope of the pullup table from 0 to 0.27 V, typ, clamps not added: 26 ohm
|   GND clamp passes 1 mA (typ) near -0.58 V on its own axis
|   POWER clamp passes 1 mA (typ) near -0.49 V on its own axis
|   rising waveform, R_fixture 50, V_fixture 1.8: 20-80 % time 146ps typ, 269ps min, 101ps max; typ from 0.71 V to 1.8 V
|   rising waveform, R_fixture 50, V_fixture 0: 20-80 % time 1.58ns typ, 3.94ns min, 782ps max; typ from 0 V to 1.14 V
|   falling waveform, R_fixture 50, V_fixture 1.8: 20-80 % time 1.13ns typ, 2.42ns min, 726ps max; typ from 1.8 V to 0.71 V
|   falling waveform, R_fixture 50, V_fixture 0: 20-80 % time 790ps typ, 1.24ns min, 601ps max; typ from 1.14 V to 0.002 V
| Nom Voltages:
|   BIASFET=1.8, VBBNW=1.1, VDD=1.1, VDDS=1.8, VSS=0, VSSS=0
| Min Voltages:
|   BIASFET=1.62, VBBNW=0.99, VDD=0.99, VDDS=1.62, VSS=0, VSSS=0
| Max Voltages:
|   BIASFET=1.95, VBBNW=1.21, VDD=1.21, VDDS=1.95, VSS=0, VSSS=0
[POWER_clamp]
|   voltage   I(typ)   I(min)   I(max)
-1.8V     196.9mA    157.5mA    250.4mA
-1.182V   51.7mA     43.01mA    68.62mA
-1.145V   44.47mA    37.18mA    60.11mA
-1.109V   37.92mA    31.75mA    52.08mA
-1.073V   31.81mA    26.61mA    44.34mA
-1.036V   26.13mA    21.76mA    36.87mA
-963.6mV  17.41mA    14.08mA    24.42mA
-890.9mV  11.59mA    8.834mA    16.07mA
-818.2mV  8.134mA    5.657mA    11.55mA
-600mV    2.616mA    1.567mA    3.937mA
-345.5mV  117.2uA    78.7uA     135.4uA
1.8V      -127.5uA   -60.72uA   -226.5uA
[Pulldown]
|   voltage   I(typ)   I(min)   I(max)
-1.8V     -2.835mA   -1.376mA   -6.938mA
-1.473V   -6.994mA   -2.229mA   -23.44mA
-1.2V     -18.79mA   -4.282mA   -34.89mA
-1.036V   -25.34mA   -7.531mA   -37.14mA
-872.7mV  -27.39mA   -12.36mA   -35.28mA
-654.5mV  -24.59mA   -14.63mA   -31.68mA
-490.9mV  -19.69mA   -11.65mA   -26.08mA
381.8mV   13.54mA    7.117mA    19.32mA
654.5mV   20.72mA    10.44mA    30.48mA
927.3mV   25mA       12.07mA    37.79mA
1.636V    27.3mA     12.74mA    42.26mA
3.6V      27.12mA    12.64mA    41.97mA
[Pullup]
|   voltage   I(typ)   I(min)   I(max)
-1.8V     7.614mA    2.74mA     26.22mA
-1.527V   17.69mA    4.626mA    37.43mA
-1.309V   25.69mA    8.541mA    43.72mA
-1.036V   29.87mA    15.94mA    41.05mA
-818.2mV  26.95mA    17.52mA    37.49mA
-490.9mV  19.61mA    12.45mA    28.08mA
545.5mV   -19.54mA   -10.94mA   -30.03mA
927.3mV   -29.38mA   -15.56mA   -46.58mA
1.255V    -34.7mA    -17.56mA   -56.51mA
1.691V    -38.25mA   -18.74mA   -63.85mA
2.291V    -40.42mA   -19.45mA   -68.55mA
3.6V      -41.01mA   -19.75mA   -69.5mA
[GND_clamp]
|   voltage   I(typ)   I(min)   I(max)
-1.8V     -274mA     -200.4mA   -365.5mA
-1.109V   -45.43mA   -39.33mA   -55.98mA
-1.073V   -36.51mA   -33.12mA   -44.53mA
-1.036V   -28.36mA   -27.37mA   -34.36mA
-963.6mV  -17.09mA   -18.57mA   -21.02mA
-927.3mV  -12.99mA   -14.94mA   -16.2mA
-890.9mV  -10.53mA   -12.1mA    -13.35mA
-818.2mV  -6.846mA   -7.311mA   -9.151mA
-745.5mV  -4.434mA   -4.029mA   -6.378mA
-563.6mV  -767.1uA   -485.3uA   -1.366mA
-18.18mV  0A         0A         0A
3.6V      0A         0A         0A
[Ramp]
| variable   typ   min   max
dV/dt_f 0.65550714/1.1386884n 0.36886459/2.442572n  0.82636156/0.72951097n
dV/dt_r 0.69492264/1.5827637n 0.45781703/4.0724252n 0.86844388/0.7848183n
R_load = 50
[Rising Waveform]
R_fixture = 50
V_fixture = 1.8
V_fixture_min = 1.62
V_fixture_max = 1.95
|   time   V(typ)   V(min)   V(max)
0s        709.9mV    1.007V     577mV
616.6ps   709.9mV    1.007V     592.2mV
678.2ps   709.9mV    1.007V     782mV
776.5ps   709.9mV    1.007V     1.593V
820.6ps   733.7mV    1.007V     1.801V
1.105ns   1.71V      1.007V     1.937V
1.277ns   1.775V     1.055V     1.944V
1.673ns   1.792V     1.551V     1.947V
1.929ns   1.795V     1.607V     1.948V
17.87ns   1.8V       1.62V      1.95V
[Rising Waveform]
R_fixture = 50
V_fixture = 0
V_fixture_min = 0
V_fixture_max = 0
|   time   V(typ)   V(min)   V(max)
0s        0V         0V         3.679mV
786.1ps   0V         0V         3.679mV
1.124ns   0V         0V         424.2mV
1.469ns   156.5mV    0V         863mV
1.73ns    308.5mV    0V         1.101V
2.179ns   558.7mV    23.01mV    1.28V
2.818ns   826.7mV    110.1mV    1.368V
4.383ns   1.052V     351.4mV    1.421V
7.686ns   1.131V     628.3mV    1.435V
18.05ns   1.144V     744.6mV    1.436V
[Falling Waveform]
R_fixture = 50
V_fixture = 1.8
V_fixture_min = 1.62
V_fixture_max = 1.95
|   time   V(typ)   V(min)   V(max)
0s        1.799V     1.619V     1.949V
930.1ps   1.799V     1.619V     1.927V
1.583ns   1.729V     1.619V     1.406V
2.114ns   1.511V     1.619V     721.9mV
2.522ns   1.304V     1.612V     602.5mV
3.263ns   854mV      1.533V     580.4mV
4.282ns   741.7mV    1.382V     576.5mV
5.606ns   716.9mV    1.159V     576.1mV
7.444ns   711.1mV    1.063V     576.1mV
17.87ns   710.3mV    1.009V     576.1mV
[Falling Waveform]
R_fixture = 50
V_fixture = 0
V_fixture_min = 0
V_fixture_max = 0
|   time   V(typ)   V(min)   V(max)
0s        1.143V     752.9mV    1.435V
910.5ps   1.143V     752.9mV    1.411V
1.192ns   1.142V     752.9mV    1.111V
1.496ns   1.052V     752.9mV    630.8mV
1.869ns   757.1mV    752.9mV    197mV
2.265ns   369mV      731.9mV    10.52mV
3.134ns   21.68mV    461.2mV    3.243mV
4.026ns   2.942mV    154.3mV    3.079mV
5.154ns   2.23mV     13.22mV    3.07mV
18.05ns   2.13mV     0V         3.068mV
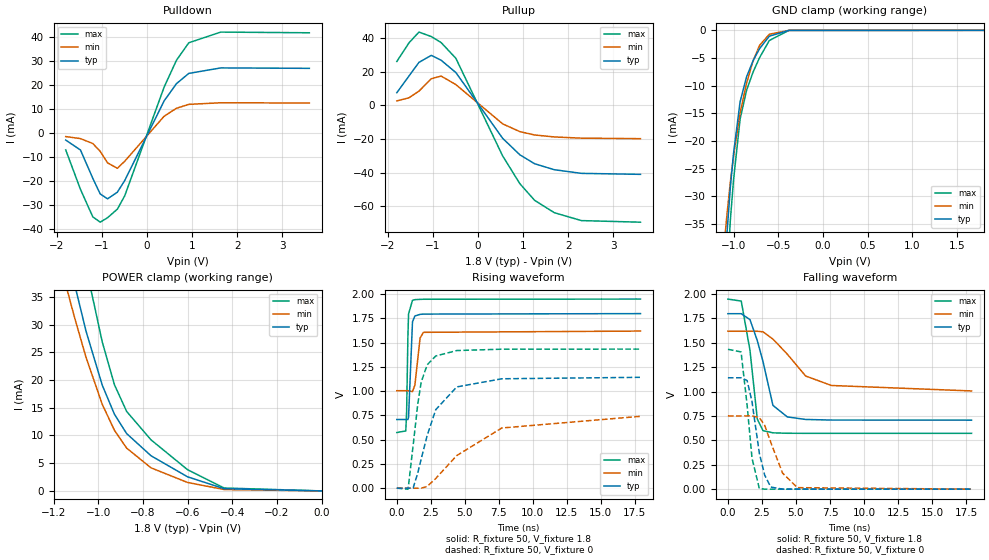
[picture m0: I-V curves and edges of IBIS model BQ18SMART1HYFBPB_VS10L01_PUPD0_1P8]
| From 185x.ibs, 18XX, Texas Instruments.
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|   Model Cell BQ18SMART1HYFBPB_VS10L01_PUPD0_1P8
|BQ18SMART1HYFBPB_VS10L01_PUPD0_1P8
[Model]   BQ18SMART1HYFBPB_VS10L01_PUPD0_1P8
Model_type   I/O
Polarity   Non-Inverting
Enable   Active-Low
Vinl =  0.63
Vinh =  1.17
Cref =  15pF
Rref =  100.0000M
Vref =  0V
Vmeas =  0.9
C_comp   0.9029199p   0.7983694p   1.014934p
[Model Spec]
Vinl   0.63   0.567   0.6825
Vinh   1.17   1.053   1.2675
[Temperature Range]   25   125   -40
[Voltage Range]   1.8   1.62   1.95
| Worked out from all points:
|   slope of the pulldown table from 0 to 0.27 V, typ, clamps not added: 27.2 ohm
|   slope of the pullup table from 0 to 0.27 V, typ, clamps not added: 26 ohm
|   GND clamp passes 1 mA (typ) near -0.59 V on its own axis
|   POWER clamp passes 1 mA (typ) near -0.50 V on its own axis
|   rising waveform, R_fixture 50, V_fixture 1.8: 20-80 % time 146ps typ, 269ps min, 101ps max; typ from 0.708 V to 1.8 V
|   rising waveform, R_fixture 50, V_fixture 0: 20-80 % time 1.6ns typ, 3.97ns min, 796ps max; typ from 0 V to 1.14 V
|   falling waveform, R_fixture 50, V_fixture 1.8: 20-80 % time 1.12ns typ, 2.48ns min, 709ps max; typ from 1.8 V to 0.708 V
|   falling waveform, R_fixture 50, V_fixture 0: 20-80 % time 772ps typ, 1.22ns min, 583ps max; typ from 1.14 V to 0 V
| Nom Voltages:
|   BIASFET=1.8, VBBNW=1.1, VDD=1.1, VDDS=1.8, VSS=0, VSSS=0
| Min Voltages:
|   BIASFET=1.62, VBBNW=0.99, VDD=0.99, VDDS=1.62, VSS=0, VSSS=0
| Max Voltages:
|   BIASFET=1.95, VBBNW=1.21, VDD=1.21, VDDS=1.95, VSS=0, VSSS=0
[POWER_clamp]
|   voltage   I(typ)   I(min)   I(max)
-1.8V     196.8mA    157.5mA    250.4mA
-1.164V   48mA       40.06mA    64.23mA
-1.127V   41.11mA    34.43mA    55.95mA
-1.109V   37.83mA    31.72mA    51.94mA
-1.055V   28.88mA    24.15mA    40.47mA
-981.8mV  19.06mA    15.6mA     26.85mA
-927.3mV  13.83mA    10.93mA    19.15mA
-872.7mV  10.34mA    7.72mA     14.33mA
-763.6mV  6.344mA    4.165mA    9.211mA
-600mV    2.546mA    1.527mA    3.832mA
-436.4mV  402.5uA    253uA      527.5uA
0V        291.8pA    1.073nA    4.224nA
[Pulldown]
|   voltage   I(typ)   I(min)   I(max)
-1.8V     -2.835mA   -1.376mA   -6.938mA
-1.473V   -6.994mA   -2.229mA   -23.44mA
-1.2V     -18.79mA   -4.282mA   -34.89mA
-1.036V   -25.33mA   -7.531mA   -37.14mA
-872.7mV  -27.39mA   -12.36mA   -35.28mA
-654.5mV  -24.59mA   -14.63mA   -31.68mA
-490.9mV  -19.69mA   -11.65mA   -26.08mA
381.8mV   13.54mA    7.117mA    19.32mA
654.5mV   20.72mA    10.44mA    30.48mA
927.3mV   25mA       12.07mA    37.79mA
1.636V    27.3mA     12.74mA    42.26mA
3.6V      27.12mA    12.64mA    41.97mA
[Pullup]
|   voltage   I(typ)   I(min)   I(max)
-1.8V     7.614mA    2.74mA     26.22mA
-1.527V   17.69mA    4.626mA    37.43mA
-1.309V   25.69mA    8.541mA    43.72mA
-1.036V   29.87mA    15.94mA    41.05mA
-818.2mV  26.95mA    17.52mA    37.49mA
-490.9mV  19.61mA    12.45mA    28.08mA
545.5mV   -19.54mA   -10.94mA   -30.03mA
927.3mV   -29.38mA   -15.56mA   -46.58mA
1.255V    -34.7mA    -17.56mA   -56.51mA
1.691V    -38.25mA   -18.74mA   -63.85mA
2.291V    -40.42mA   -19.45mA   -68.55mA
3.6V      -41.01mA   -19.75mA   -69.5mA
[GND_clamp]
|   voltage   I(typ)   I(min)   I(max)
-1.8V     -274mA     -200.4mA   -365.5mA
-1.109V   -45.37mA   -39.32mA   -55.85mA
-1.073V   -36.45mA   -33.1mA    -44.39mA
-1.036V   -28.3mA    -27.35mA   -34.22mA
-1V       -22.14mA   -22.69mA   -26.92mA
-927.3mV  -12.91mA   -14.91mA   -16.03mA
-854.5mV  -8.387mA   -9.532mA   -10.83mA
-781.8mV  -5.484mA   -5.512mA   -7.535mA
-709.1mV  -3.298mA   -2.71mA    -4.931mA
-600mV    -1.058mA   -705.2uA   -1.831mA
-381.8mV  -13.32uA   -12.31uA   -19.39uA
1.8V      291.8pA    820.3nA    4.087nA
[Ramp]
| variable   typ   min   max
dV/dt_f 0.65706314/1.1261949n 0.36979713/2.5047358n 0.82836251/0.71296366n
dV/dt_r 0.69743118/1.6114033n 0.45852634/4.1436975n 0.87181546/0.79980413n
R_load = 50
[Rising Waveform]
R_fixture = 50
V_fixture = 1.8
V_fixture_min = 1.62
V_fixture_max = 1.95
|   time   V(typ)   V(min)   V(max)
0s        707.6mV    1.005V     573.4mV
659.2ps   707.6mV    1.005V     590.2mV
721.8ps   707.6mV    1.005V     788.5mV
814.9ps   707.6mV    1.005V     1.564V
862.8ps   732.1mV    1.005V     1.797V
1.153ns   1.716V     995.8mV    1.937V
1.33ns    1.776V     1.064V     1.944V
1.71ns    1.792V     1.548V     1.947V
1.957ns   1.795V     1.607V     1.948V
17.91ns   1.8V       1.62V      1.95V
[Rising Waveform]
R_fixture = 50
V_fixture = 0
V_fixture_min = 0
V_fixture_max = 0
|   time   V(typ)   V(min)   V(max)
0s        0V         0V         0V
827.3ps   0V         0V         -10.33mV
1.196ns   0V         0V         436.7mV
1.542ns   156.8mV    0V         868mV
1.795ns   302.5mV    0V         1.095V
2.235ns   544.9mV    17.94mV    1.273V
2.861ns   809.5mV    99.89mV    1.363V
4.407ns   1.044V     336.5mV    1.419V
7.716ns   1.128V     620.5mV    1.433V
17.87ns   1.143V     740.4mV    1.434V
[Falling Waveform]
R_fixture = 50
V_fixture = 1.8
V_fixture_min = 1.62
V_fixture_max = 1.95
|   time   V(typ)   V(min)   V(max)
0s        1.799V     1.619V     1.949V
981ps     1.799V     1.619V     1.928V
1.622ns   1.738V     1.619V     1.423V
2.16ns    1.523V     1.619V     718.2mV
2.579ns   1.308V     1.613V     600.3mV
3.309ns   859.1mV    1.539V     577.5mV
4.366ns   740.7mV    1.384V     573.1mV
5.714ns   714.7mV    1.16V      572.6mV
7.607ns   708.5mV    1.063V     572.6mV
17.91ns   707.6mV    1.007V     572.6mV
[Falling Waveform]
R_fixture = 50
V_fixture = 0
V_fixture_min = 0
V_fixture_max = 0
|   time   V(typ)   V(min)   V(max)
0s        1.142V     751.1mV    1.434V
965.2ps   1.142V     751.1mV    1.407V
1.41ns    1.114V     751.1mV    863.1mV
1.77ns    898.7mV    751.1mV    318.4mV
2.308ns   369.2mV    733.9mV    6.803mV
2.703ns   143.3mV    654mV      0V
3.149ns   21.93mV    480.5mV    0V
4.014ns   0V         165.7mV    0V
5.1ns     0V         15.55mV    0V
17.87ns   0V         0V         0V
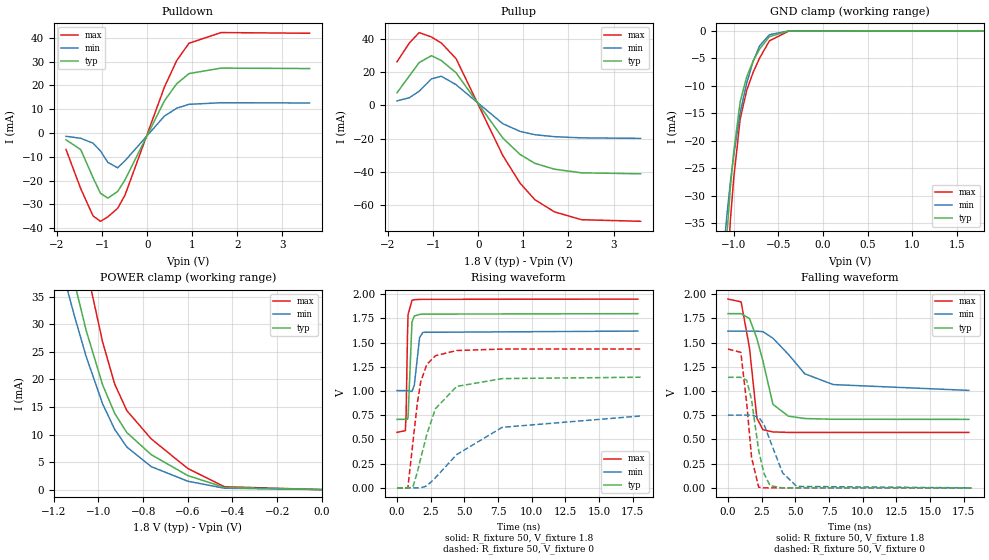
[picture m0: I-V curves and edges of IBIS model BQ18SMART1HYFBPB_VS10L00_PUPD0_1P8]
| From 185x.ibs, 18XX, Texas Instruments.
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|   Model Cell BQ18SMART1HYFBPB_VS10L00_PUPD0_1P8
|BQ18SMART1HYFBPB_VS10L00_PUPD0_1P8
[Model]   BQ18SMART1HYFBPB_VS10L00_PUPD0_1P8
Model_type   I/O
Polarity   Non-Inverting
Enable   Active-Low
Vinl =  0.63
Vinh =  1.17
Cref =  15pF
Rref =  100.0000M
Vref =  0V
Vmeas =  0.9
C_comp   0.9029199p   0.7983694p   1.014934p
[Model Spec]
Vinl   0.63   0.567   0.6825
Vinh   1.17   1.053   1.2675
[Temperature Range]   25   125   -40
[Voltage Range]   1.8   1.62   1.95
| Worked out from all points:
|   slope of the pulldown table from 0 to 0.27 V, typ, clamps not added: 27.2 ohm
|   slope of the pullup table from 0 to 0.27 V, typ, clamps not added: 26 ohm
|   GND clamp passes 1 mA (typ) near -0.59 V on its own axis
|   POWER clamp passes 1 mA (typ) near -0.50 V on its own axis
|   rising waveform, R_fixture 50, V_fixture 1.8: 20-80 % time 147ps typ, 270ps min, 102ps max; typ from 0.708 V to 1.8 V
|   rising waveform, R_fixture 50, V_fixture 0: 20-80 % time 1.61ns typ, 4.01ns min, 798ps max; typ from 0 V to 1.14 V
|   falling waveform, R_fixture 50, V_fixture 1.8: 20-80 % time 1.12ns typ, 2.62ns min, 695ps max; typ from 1.8 V to 0.708 V
|   falling waveform, R_fixture 50, V_fixture 0: 20-80 % time 761ps typ, 1.23ns min, 571ps max; typ from 1.14 V to 0 V
| Nom Voltages:
|   BIASFET=1.8, VBBNW=1.1, VDD=1.1, VDDS=1.8, VSS=0, VSSS=0
| Min Voltages:
|   BIASFET=1.62, VBBNW=0.99, VDD=0.99, VDDS=1.62, VSS=0, VSSS=0
| Max Voltages:
|   BIASFET=1.95, VBBNW=1.21, VDD=1.21, VDDS=1.95, VSS=0, VSSS=0
[POWER_clamp]
|   voltage   I(typ)   I(min)   I(max)
-1.8V     196.8mA    157.5mA    250.4mA
-1.164V   48mA       40.06mA    64.23mA
-1.127V   41.11mA    34.43mA    55.95mA
-1.109V   37.83mA    31.72mA    51.94mA
-1.055V   28.88mA    24.15mA    40.47mA
-981.8mV  19.06mA    15.6mA     26.85mA
-927.3mV  13.83mA    10.93mA    19.15mA
-872.7mV  10.34mA    7.72mA     14.33mA
-763.6mV  6.344mA    4.165mA    9.211mA
-600mV    2.546mA    1.527mA    3.832mA
-436.4mV  402.5uA    253uA      527.5uA
0V        291.8pA    1.073nA    4.224nA
[Pulldown]
|   voltage   I(typ)   I(min)   I(max)
-1.8V     -2.835mA   -1.376mA   -6.938mA
-1.473V   -6.994mA   -2.229mA   -23.44mA
-1.2V     -18.79mA   -4.282mA   -34.89mA
-1.036V   -25.33mA   -7.531mA   -37.14mA
-872.7mV  -27.39mA   -12.36mA   -35.28mA
-654.5mV  -24.59mA   -14.63mA   -31.68mA
-490.9mV  -19.69mA   -11.65mA   -26.08mA
381.8mV   13.54mA    7.117mA    19.32mA
654.5mV   20.72mA    10.44mA    30.48mA
927.3mV   25mA       12.07mA    37.79mA
1.636V    27.3mA     12.74mA    42.26mA
3.6V      27.12mA    12.64mA    41.97mA
[Pullup]
|   voltage   I(typ)   I(min)   I(max)
-1.8V     7.614mA    2.74mA     26.22mA
-1.527V   17.69mA    4.626mA    37.43mA
-1.309V   25.69mA    8.541mA    43.72mA
-1.036V   29.87mA    15.94mA    41.05mA
-818.2mV  26.95mA    17.52mA    37.49mA
-490.9mV  19.61mA    12.45mA    28.08mA
545.5mV   -19.54mA   -10.94mA   -30.03mA
927.3mV   -29.38mA   -15.56mA   -46.58mA
1.255V    -34.7mA    -17.56mA   -56.51mA
1.691V    -38.25mA   -18.74mA   -63.85mA
2.291V    -40.42mA   -19.45mA   -68.55mA
3.6V      -41.01mA   -19.75mA   -69.5mA
[GND_clamp]
|   voltage   I(typ)   I(min)   I(max)
-1.8V     -274mA     -200.4mA   -365.5mA
-1.109V   -45.37mA   -39.32mA   -55.85mA
-1.073V   -36.45mA   -33.1mA    -44.39mA
-1.036V   -28.3mA    -27.35mA   -34.22mA
-1V       -22.14mA   -22.69mA   -26.92mA
-927.3mV  -12.91mA   -14.91mA   -16.03mA
-854.5mV  -8.387mA   -9.532mA   -10.83mA
-781.8mV  -5.484mA   -5.512mA   -7.535mA
-709.1mV  -3.298mA   -2.71mA    -4.931mA
-600mV    -1.058mA   -705.2uA   -1.831mA
-381.8mV  -13.32uA   -12.31uA   -19.39uA
1.8V      291.8pA    820.3nA    4.087nA
[Ramp]
| variable   typ   min   max
dV/dt_f 0.65711672/1.1212892n 0.36988978/2.6488065n 0.82837898/0.69832646n
dV/dt_r 0.69713197/1.6146061n 0.45843375/4.1533197n 0.87129507/0.80136973n
R_load = 50
[Rising Waveform]
R_fixture = 50
V_fixture = 1.8
V_fixture_min = 1.62
V_fixture_max = 1.95
|   time   V(typ)   V(min)   V(max)
0s        707.7mV    1.005V     573.3mV
618.8ps   707.7mV    1.005V     590.5mV
677.8ps   707.7mV    1.005V     767.1mV
777.3ps   707.7mV    1.005V     1.58V
820.8ps   730.8mV    1.005V     1.791V
1.11ns    1.713V     995.9mV    1.937V
1.286ns   1.776V     1.062V     1.944V
1.675ns   1.792V     1.552V     1.947V
1.924ns   1.795V     1.607V     1.948V
17.87ns   1.8V       1.62V      1.95V
[Rising Waveform]
R_fixture = 50
V_fixture = 0
V_fixture_min = 0
V_fixture_max = 0
|   time   V(typ)   V(min)   V(max)
0s        0V         0V         0V
801.9ps   0V         0V         0V
1.177ns   8.006mV    0V         465.1mV
1.507ns   160.5mV    0V         873.1mV
1.757ns   303.7mV    0V         1.096V
2.209ns   551.7mV    19.8mV     1.276V
2.848ns   817.7mV    104.3mV    1.365V
4.426ns   1.048V     344mV      1.419V
7.809ns   1.129V     625.6mV    1.434V
18.07ns   1.143V     742.6mV    1.434V
[Falling Waveform]
R_fixture = 50
V_fixture = 1.8
V_fixture_min = 1.62
V_fixture_max = 1.95
|   time   V(typ)   V(min)   V(max)
0s        1.8V       1.619V     1.95V
971.7ps   1.8V       1.619V     1.922V
1.596ns   1.749V     1.619V     1.443V
2.142ns   1.543V     1.619V     720.1mV
2.591ns   1.311V     1.614V     600.6mV
3.335ns   862.2mV    1.546V     577.8mV
4.481ns   740.8mV    1.379V     573.1mV
5.699ns   716.4mV    1.178V     572.7mV
7.812ns   708.6mV    1.067V     572.6mV
17.87ns   707.6mV    1.007V     572.6mV
[Falling Waveform]
R_fixture = 50
V_fixture = 0
V_fixture_min = 0
V_fixture_max = 0
|   time   V(typ)   V(min)   V(max)
0s        1.142V     751.4mV    1.434V
949.5ps   1.142V     751.4mV    1.4V
1.385ns   1.112V     751.4mV    877.3mV
1.75ns    908.4mV    751.4mV    311mV
2.277ns   382.5mV    730.3mV    6.852mV
2.671ns   147.4mV    654.5mV    0V
3.123ns   21.95mV    488.3mV    0V
4.043ns   0V         156.5mV    0V
5.096ns   0V         14.91mV    0V
18.07ns   0V         0V         0V
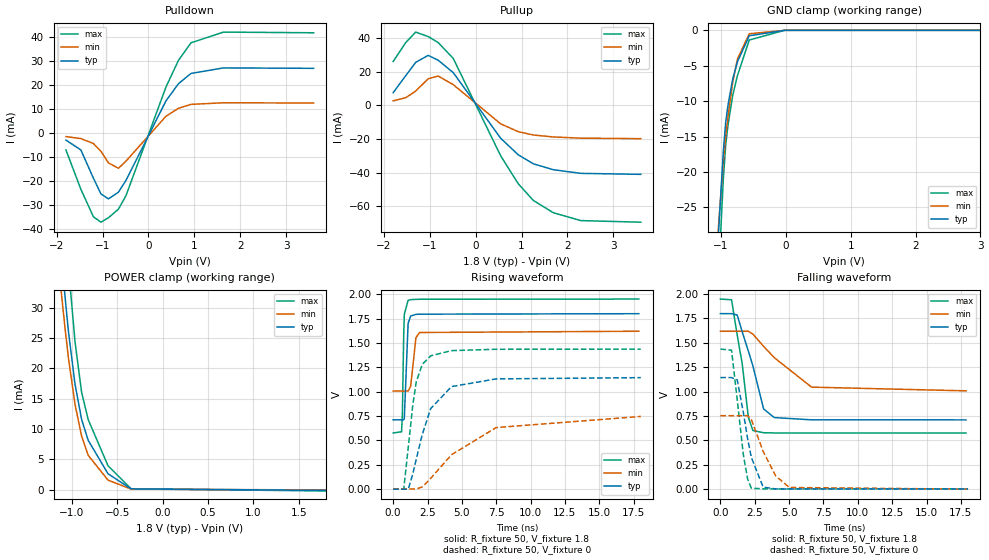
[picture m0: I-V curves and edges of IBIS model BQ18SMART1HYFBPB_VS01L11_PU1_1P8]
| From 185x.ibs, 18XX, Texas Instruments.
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|   Model Cell BQ18SMART1HYFBPB_VS01L11_PU1_1P8
|BQ18SMART1HYFBPB_VS01L11_PU1_1P8
[Model]   BQ18SMART1HYFBPB_VS01L11_PU1_1P8
Model_type   I/O
Polarity   Non-Inverting
Enable   Active-Low
Vinl =  0.63
Vinh =  1.17
Cref =  15pF
Rref =  100.0000M
Vref =  0V
Vmeas =  0.9
C_comp   0.9029199p   0.7983694p   1.014934p
[Model Spec]
Vinl   0.63   0.567   0.6825
Vinh   1.17   1.053   1.2675
[Temperature Range]   25   125   -40
[Voltage Range]   1.8   1.62   1.95
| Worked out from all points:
|   slope of the pulldown table from 0 to 0.27 V, typ, clamps not added: 27.2 ohm
|   slope of the pullup table from 0 to 0.27 V, typ, clamps not added: 26 ohm
|   GND clamp passes 1 mA (typ) near -0.58 V on its own axis
|   POWER clamp passes 1 mA (typ) near -0.49 V on its own axis
|   rising waveform, R_fixture 50, V_fixture 1.8: 20-80 % time 142ps typ, 261ps min, 99ps max; typ from 0.711 V to 1.8 V
|   rising waveform, R_fixture 50, V_fixture 0: 20-80 % time 1.52ns typ, 3.81ns min, 755ps max; typ from 0 V to 1.14 V
|   falling waveform, R_fixture 50, V_fixture 1.8: 20-80 % time 1.25ns typ, 2.26ns min, 823ps max; typ from 1.8 V to 0.71 V
|   falling waveform, R_fixture 50, V_fixture 0: 20-80 % time 910ps typ, 1.35ns min, 690ps max; typ from 1.14 V to 0.002 V
| Nom Voltages:
|   BIASFET=1.8, VBBNW=1.1, VDD=1.1, VDDS=1.8, VSS=0, VSSS=0
| Min Voltages:
|   BIASFET=1.62, VBBNW=0.99, VDD=0.99, VDDS=1.62, VSS=0, VSSS=0
| Max Voltages:
|   BIASFET=1.95, VBBNW=1.21, VDD=1.21, VDDS=1.95, VSS=0, VSSS=0
[POWER_clamp]
|   voltage   I(typ)   I(min)   I(max)
-1.8V     196.9mA    157.5mA    250.4mA
-1.182V   51.7mA     43.01mA    68.62mA
-1.145V   44.47mA    37.18mA    60.11mA
-1.109V   37.92mA    31.75mA    52.08mA
-1.073V   31.81mA    26.61mA    44.34mA
-1.036V   26.13mA    21.76mA    36.87mA
-963.6mV  17.41mA    14.08mA    24.42mA
-890.9mV  11.59mA    8.834mA    16.07mA
-818.2mV  8.134mA    5.657mA    11.55mA
-600mV    2.616mA    1.567mA    3.937mA
-345.5mV  117.2uA    78.7uA     135.4uA
1.8V      -127.5uA   -60.72uA   -226.5uA
[Pulldown]
|   voltage   I(typ)   I(min)   I(max)
-1.8V     -2.835mA   -1.376mA   -6.938mA
-1.473V   -6.994mA   -2.229mA   -23.44mA
-1.2V     -18.79mA   -4.282mA   -34.89mA
-1.036V   -25.34mA   -7.531mA   -37.14mA
-872.7mV  -27.39mA   -12.36mA   -35.28mA
-654.5mV  -24.59mA   -14.63mA   -31.68mA
-490.9mV  -19.69mA   -11.65mA   -26.08mA
381.8mV   13.54mA    7.117mA    19.32mA
654.5mV   20.72mA    10.44mA    30.48mA
927.3mV   25mA       12.07mA    37.79mA
1.636V    27.3mA     12.74mA    42.26mA
3.6V      27.12mA    12.64mA    41.97mA
[Pullup]
|   voltage   I(typ)   I(min)   I(max)
-1.8V     7.614mA    2.74mA     26.22mA
-1.527V   17.69mA    4.626mA    37.43mA
-1.309V   25.69mA    8.541mA    43.72mA
-1.036V   29.87mA    15.94mA    41.05mA
-818.2mV  26.95mA    17.52mA    37.49mA
-490.9mV  19.61mA    12.45mA    28.08mA
545.5mV   -19.54mA   -10.94mA   -30.03mA
927.3mV   -29.38mA   -15.56mA   -46.58mA
1.255V    -34.7mA    -17.56mA   -56.51mA
1.691V    -38.25mA   -18.74mA   -63.85mA
2.291V    -40.42mA   -19.45mA   -68.55mA
3.6V      -41.01mA   -19.75mA   -69.5mA
[GND_clamp]
|   voltage   I(typ)   I(min)   I(max)
-1.8V     -274mA     -200.4mA   -365.5mA
-1.109V   -45.43mA   -39.33mA   -55.98mA
-1.073V   -36.51mA   -33.12mA   -44.53mA
-1.036V   -28.36mA   -27.37mA   -34.36mA
-963.6mV  -17.09mA   -18.57mA   -21.02mA
-927.3mV  -12.99mA   -14.94mA   -16.2mA
-890.9mV  -10.53mA   -12.1mA    -13.35mA
-818.2mV  -6.846mA   -7.311mA   -9.151mA
-745.5mV  -4.434mA   -4.029mA   -6.378mA
-563.6mV  -767.1uA   -485.3uA   -1.366mA
-18.18mV  0A         0A         0A
3.6V      0A         0A         0A
[Ramp]
| variable   typ   min   max
dV/dt_f 0.65559493/1.2544118n 0.36875408/2.2682712n 0.82661715/0.82601788n
dV/dt_r  0.6946523/1.5269792n 0.45787499/3.9174531n 0.86848313/0.75792641n
R_load = 50
[Rising Waveform]
R_fixture = 50
V_fixture = 1.8
V_fixture_min = 1.62
V_fixture_max = 1.95
|   time   V(typ)   V(min)   V(max)
0s        710.9mV    1.006V     576.2mV
613.9ps   710.9mV    1.006V     588.7mV
671.4ps   710.9mV    1.006V     764.2mV
768.1ps   710.9mV    1.006V     1.576V
812.3ps   724.9mV    1.006V     1.794V
1.09ns    1.701V     1.006V     1.937V
1.273ns   1.776V     1.054V     1.944V
1.659ns   1.793V     1.553V     1.947V
1.918ns   1.795V     1.607V     1.948V
17.87ns   1.8V       1.62V      1.95V
[Rising Waveform]
R_fixture = 50
V_fixture = 0
V_fixture_min = 0
V_fixture_max = 0
|   time   V(typ)   V(min)   V(max)
0s        0V         2.244mV    3.903mV
774.3ps   0V         2.244mV    3.903mV
1.104ns   0V         2.244mV    433.6mV
1.438ns   160.5mV    2.244mV    872.7mV
1.686ns   310.5mV    2.244mV    1.104V
2.118ns   560mV      22.66mV    1.28V
2.734ns   827mV      110.7mV    1.368V
4.243ns   1.052V     352.9mV    1.421V
7.491ns   1.131V     631.7mV    1.435V
18.02ns   1.144V     745.9mV    1.436V
[Falling Waveform]
R_fixture = 50
V_fixture = 1.8
V_fixture_min = 1.62
V_fixture_max = 1.95
|   time   V(typ)   V(min)   V(max)
0s        1.8V       1.619V     1.949V
813ps     1.8V       1.619V     1.942V
1.225ns   1.785V     1.619V     1.579V
1.593ns   1.611V     1.619V     1.282V
2.037ns   1.416V     1.619V     735.3mV
2.367ns   1.264V     1.589V     600.7mV
3.147ns   822.2mV    1.464V     578.6mV
3.922ns   733.9mV    1.348V     576.4mV
6.637ns   710.8mV    1.046V     576.1mV
17.87ns   710.3mV    1.008V     576.1mV
[Falling Waveform]
R_fixture = 50
V_fixture = 0
V_fixture_min = 0
V_fixture_max = 0
|   time   V(typ)   V(min)   V(max)
0s        1.144V     753.4mV    1.436V
812.9ps   1.144V     753.4mV    1.425V
1.225ns   1.121V     753.4mV    918.2mV
1.677ns   781.6mV    753.4mV    346.5mV
1.983ns   515.4mV    753mV      104.3mV
2.254ns   326mV      713.7mV    9.874mV
3.111ns   20.85mV    388.2mV    3.222mV
4.018ns   2.835mV    137.1mV    3.075mV
5.016ns   2.224mV    17.25mV    3.07mV
18.02ns   2.13mV     0V         3.068mV
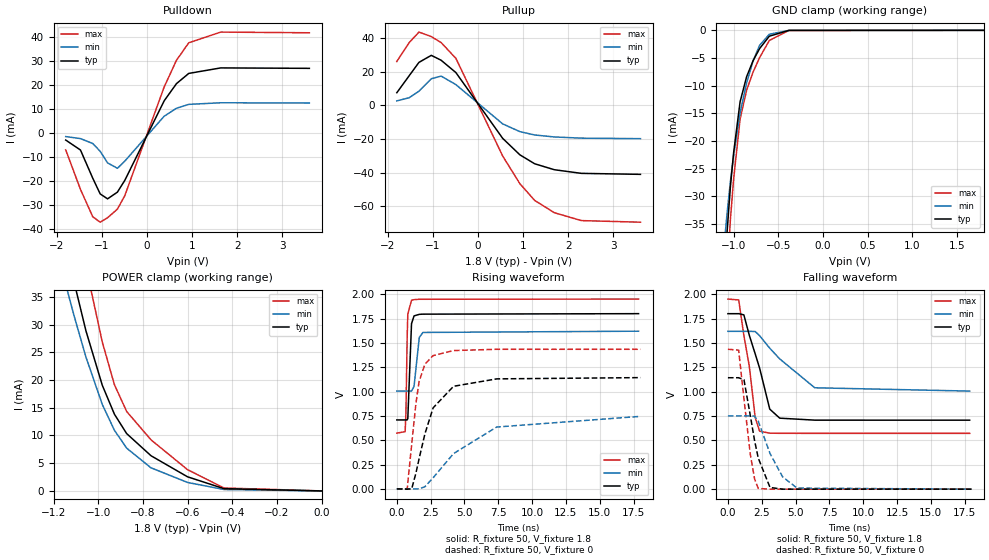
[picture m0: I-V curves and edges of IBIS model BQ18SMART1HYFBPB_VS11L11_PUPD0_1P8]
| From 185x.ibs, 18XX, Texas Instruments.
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|   Model Cell BQ18SMART1HYFBPB_VS11L11_PUPD0_1P8
|BQ18SMART1HYFBPB_VS11L11_PUPD0_1P8
[Model]   BQ18SMART1HYFBPB_VS11L11_PUPD0_1P8
Model_type   I/O
Polarity   Non-Inverting
Enable   Active-Low
Vinl =  0.63
Vinh =  1.17
Cref =  15pF
Rref =  100.0000M
Vref =  0V
Vmeas =  0.9
C_comp   0.9029199p   0.7983694p   1.014934p
[Model Spec]
Vinl   0.63   0.567   0.6825
Vinh   1.17   1.053   1.2675
[Temperature Range]   25   125   -40
[Voltage Range]   1.8   1.62   1.95
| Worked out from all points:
|   slope of the pulldown table from 0 to 0.27 V, typ, clamps not added: 27.2 ohm
|   slope of the pullup table from 0 to 0.27 V, typ, clamps not added: 26 ohm
|   GND clamp passes 1 mA (typ) near -0.59 V on its own axis
|   POWER clamp passes 1 mA (typ) near -0.50 V on its own axis
|   rising waveform, R_fixture 50, V_fixture 1.8: 20-80 % time 142ps typ, 260ps min, 99.7ps max; typ from 0.708 V to 1.8 V
|   rising waveform, R_fixture 50, V_fixture 0: 20-80 % time 1.48ns typ, 3.69ns min, 734ps max; typ from 0 V to 1.14 V
|   falling waveform, R_fixture 50, V_fixture 1.8: 20-80 % time 1.28ns typ, 2.27ns min, 846ps max; typ from 1.8 V to 0.708 V
|   falling waveform, R_fixture 50, V_fixture 0: 20-80 % time 946ps typ, 1.4ns min, 715ps max; typ from 1.14 V to 0 V
| Nom Voltages:
|   BIASFET=1.8, VBBNW=1.1, VDD=1.1, VDDS=1.8, VSS=0, VSSS=0
| Min Voltages:
|   BIASFET=1.62, VBBNW=0.99, VDD=0.99, VDDS=1.62, VSS=0, VSSS=0
| Max Voltages:
|   BIASFET=1.95, VBBNW=1.21, VDD=1.21, VDDS=1.95, VSS=0, VSSS=0
[POWER_clamp]
|   voltage   I(typ)   I(min)   I(max)
-1.8V     196.8mA    157.5mA    250.4mA
-1.164V   48mA       40.06mA    64.23mA
-1.127V   41.11mA    34.43mA    55.95mA
-1.109V   37.83mA    31.72mA    51.94mA
-1.055V   28.88mA    24.15mA    40.47mA
-981.8mV  19.06mA    15.6mA     26.85mA
-927.3mV  13.83mA    10.93mA    19.15mA
-872.7mV  10.34mA    7.72mA     14.33mA
-763.6mV  6.344mA    4.165mA    9.211mA
-600mV    2.546mA    1.527mA    3.832mA
-436.4mV  402.5uA    253uA      527.5uA
0V        291.8pA    1.073nA    4.224nA
[Pulldown]
|   voltage   I(typ)   I(min)   I(max)
-1.8V     -2.835mA   -1.376mA   -6.938mA
-1.473V   -6.994mA   -2.229mA   -23.44mA
-1.2V     -18.79mA   -4.282mA   -34.89mA
-1.036V   -25.33mA   -7.531mA   -37.14mA
-872.7mV  -27.39mA   -12.36mA   -35.28mA
-654.5mV  -24.59mA   -14.63mA   -31.68mA
-490.9mV  -19.69mA   -11.65mA   -26.08mA
381.8mV   13.54mA    7.117mA    19.32mA
654.5mV   20.72mA    10.44mA    30.48mA
927.3mV   25mA       12.07mA    37.79mA
1.636V    27.3mA     12.74mA    42.26mA
3.6V      27.12mA    12.64mA    41.97mA
[Pullup]
|   voltage   I(typ)   I(min)   I(max)
-1.8V     7.614mA    2.74mA     26.22mA
-1.527V   17.69mA    4.626mA    37.43mA
-1.309V   25.69mA    8.541mA    43.72mA
-1.036V   29.87mA    15.94mA    41.05mA
-818.2mV  26.95mA    17.52mA    37.49mA
-490.9mV  19.61mA    12.45mA    28.08mA
545.5mV   -19.54mA   -10.94mA   -30.03mA
927.3mV   -29.38mA   -15.56mA   -46.58mA
1.255V    -34.7mA    -17.56mA   -56.51mA
1.691V    -38.25mA   -18.74mA   -63.85mA
2.291V    -40.42mA   -19.45mA   -68.55mA
3.6V      -41.01mA   -19.75mA   -69.5mA
[GND_clamp]
|   voltage   I(typ)   I(min)   I(max)
-1.8V     -274mA     -200.4mA   -365.5mA
-1.109V   -45.37mA   -39.32mA   -55.85mA
-1.073V   -36.45mA   -33.1mA    -44.39mA
-1.036V   -28.3mA    -27.35mA   -34.22mA
-1V       -22.14mA   -22.69mA   -26.92mA
-927.3mV  -12.91mA   -14.91mA   -16.03mA
-854.5mV  -8.387mA   -9.532mA   -10.83mA
-781.8mV  -5.484mA   -5.512mA   -7.535mA
-709.1mV  -3.298mA   -2.71mA    -4.931mA
-600mV    -1.058mA   -705.2uA   -1.831mA
-381.8mV  -13.32uA   -12.31uA   -19.39uA
1.8V      291.8pA    820.3nA    4.087nA
[Ramp]
| variable   typ   min   max
dV/dt_f 0.65733812/1.2871641n  0.3698187/2.284684n  0.82886709/0.84928682n
dV/dt_r 0.69481369/1.4824092n 0.45795013/3.7913858n 0.86954614/0.73629587n
R_load = 50
[Rising Waveform]
R_fixture = 50
V_fixture = 1.8
V_fixture_min = 1.62
V_fixture_max = 1.95
|   time   V(typ)   V(min)   V(max)
0s        708.3mV    1.005V     572.8mV
615.2ps   708.3mV    1.005V     587.5mV
672.7ps   708.3mV    1.005V     775.4mV
767.1ps   708.3mV    1.005V     1.573V
812.8ps   723.1mV    1.005V     1.794V
1.087ns   1.697V     1.005V     1.938V
1.273ns   1.777V     1.053V     1.944V
1.66ns    1.793V     1.555V     1.948V
1.926ns   1.795V     1.607V     1.948V
17.87ns   1.8V       1.62V      1.95V
[Rising Waveform]
R_fixture = 50
V_fixture = 0
V_fixture_min = 0
V_fixture_max = 0
|   time   V(typ)   V(min)   V(max)
0s        0V         0V         0V
766.5ps   -3.04mV    0V         0V
1.1ns     0V         0V         458.9mV
1.412ns   161.7mV    0V         877.5mV
1.649ns   310.8mV    0V         1.104V
2.079ns   566.2mV    22.29mV    1.282V
2.685ns   832.5mV    114.3mV    1.369V
4.194ns   1.054V     363mV      1.421V
7.384ns   1.13V      635.3mV    1.434V
18.01ns   1.143V     745mV      1.434V
[Falling Waveform]
R_fixture = 50
V_fixture = 1.8
V_fixture_min = 1.62
V_fixture_max = 1.95
|   time   V(typ)   V(min)   V(max)
0s        1.8V       1.619V     1.95V
797.5ps   1.8V       1.619V     1.941V
1.178ns   1.788V     1.619V     1.578V
1.585ns   1.577V     1.619V     1.257V
2.018ns   1.387V     1.617V     733.5mV
2.344ns   1.241V     1.574V     594.5mV
3.092ns   821.2mV    1.446V     574.6mV
3.829ns   728.4mV    1.336V     572.9mV
6.42ns    708mV      1.04V      572.6mV
17.87ns   707.6mV    1.006V     572.6mV
[Falling Waveform]
R_fixture = 50
V_fixture = 0
V_fixture_min = 0
V_fixture_max = 0
|   time   V(typ)   V(min)   V(max)
0s        1.143V     751.8mV    1.435V
792.9ps   1.143V     751.8mV    1.426V
1.187ns   1.122V     751.8mV    926mV
1.652ns   757.5mV    751.8mV    359.8mV
1.971ns   498.2mV    748.9mV    105mV
2.244ns   318.3mV    696.7mV    7.166mV
3.113ns   17.44mV    366mV      0V
4.035ns   0V         127.5mV    0V
5.109ns   0V         10.98mV    0V
18.01ns   0V         0V         0V
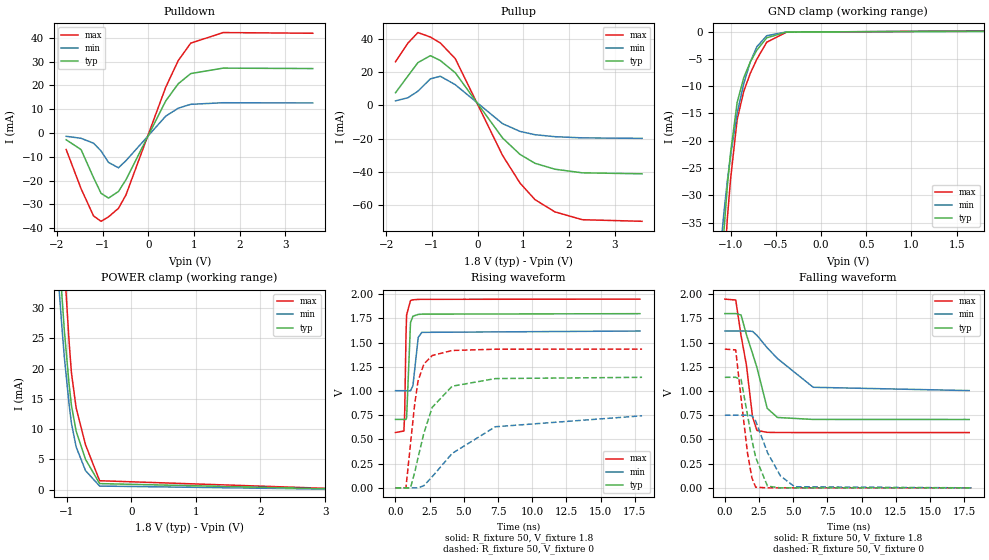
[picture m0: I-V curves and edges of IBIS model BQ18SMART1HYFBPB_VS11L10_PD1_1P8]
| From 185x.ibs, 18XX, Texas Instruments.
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|   Model Cell BQ18SMART1HYFBPB_VS11L10_PD1_1P8
|BQ18SMART1HYFBPB_VS11L10_PD1_1P8
[Model]   BQ18SMART1HYFBPB_VS11L10_PD1_1P8
Model_type   I/O
Polarity   Non-Inverting
Enable   Active-Low
Vinl =  0.63
Vinh =  1.17
Cref =  15pF
Rref =  100.0000M
Vref =  0V
Vmeas =  0.9
C_comp   0.9029199p   0.7983694p   1.014934p
[Model Spec]
Vinl   0.63   0.567   0.6825
Vinh   1.17   1.053   1.2675
[Temperature Range]   25   125   -40
[Voltage Range]   1.8   1.62   1.95
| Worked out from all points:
|   slope of the pulldown table from 0 to 0.27 V, typ, clamps not added: 27.2 ohm
|   slope of the pullup table from 0 to 0.27 V, typ, clamps not added: 26 ohm
|   GND clamp passes 1 mA (typ) near -0.59 V on its own axis
|   POWER clamp passes 1 mA (typ) near -0.49 V on its own axis
|   rising waveform, R_fixture 50, V_fixture 1.8: 20-80 % time 144ps typ, 262ps min, 101ps max; typ from 0.706 V to 1.8 V
|   rising waveform, R_fixture 50, V_fixture 0: 20-80 % time 1.48ns typ, 3.7ns min, 737ps max; typ from 0 V to 1.14 V
|   falling waveform, R_fixture 50, V_fixture 1.8: 20-80 % time 1.29ns typ, 2.29ns min, 849ps max; typ from 1.8 V to 0.706 V
|   falling waveform, R_fixture 50, V_fixture 0: 20-80 % time 952ps typ, 1.41ns min, 719ps max; typ from 1.14 V to 0 V
| Nom Voltages:
|   BIASFET=1.8, VBBNW=1.1, VDD=1.1, VDDS=1.8, VSS=0, VSSS=0
| Min Voltages:
|   BIASFET=1.62, VBBNW=0.99, VDD=0.99, VDDS=1.62, VSS=0, VSSS=0
| Max Voltages:
|   BIASFET=1.95, VBBNW=1.21, VDD=1.21, VDDS=1.95, VSS=0, VSSS=0
[POWER_clamp]
|   voltage   I(typ)   I(min)   I(max)
-1.8V     196.9mA    157.5mA    250.4mA
-1.182V   51.67mA    43mA       68.61mA
-1.145V   44.45mA    37.16mA    60.1mA
-1.109V   37.9mA     31.74mA    52.07mA
-1.073V   31.79mA    26.6mA     44.33mA
-1.036V   26.12mA    21.74mA    36.87mA
-963.6mV  17.39mA    14.07mA    24.42mA
-927.3mV  13.91mA    10.96mA    19.29mA
-854.5mV  9.657mA    7.054mA    13.5mA
-709.1mV  4.995mA    3.131mA    7.393mA
-490.9mV  991uA      585.4uA    1.466mA
3.6V      0A         0A         0A
[Pulldown]
|   voltage   I(typ)   I(min)   I(max)
-1.8V     -2.835mA   -1.376mA   -6.938mA
-1.473V   -6.994mA   -2.229mA   -23.44mA
-1.2V     -18.79mA   -4.282mA   -34.89mA
-1.036V   -25.34mA   -7.531mA   -37.14mA
-872.7mV  -27.39mA   -12.36mA   -35.28mA
-654.5mV  -24.59mA   -14.63mA   -31.68mA
-490.9mV  -19.69mA   -11.65mA   -26.08mA
381.8mV   13.54mA    7.116mA    19.32mA
654.5mV   20.72mA    10.44mA    30.47mA
927.3mV   25mA       12.07mA    37.79mA
1.636V    27.3mA     12.74mA    42.26mA
3.6V      27.12mA    12.64mA    41.97mA
[Pullup]
|   voltage   I(typ)   I(min)   I(max)
-1.8V     7.614mA    2.74mA     26.22mA
-1.527V   17.69mA    4.626mA    37.43mA
-1.309V   25.69mA    8.541mA    43.72mA
-1.036V   29.87mA    15.94mA    41.05mA
-818.2mV  26.95mA    17.52mA    37.49mA
-490.9mV  19.61mA    12.45mA    28.08mA
545.5mV   -19.54mA   -10.94mA   -30.03mA
927.3mV   -29.38mA   -15.56mA   -46.58mA
1.255V    -34.7mA    -17.56mA   -56.51mA
1.691V    -38.25mA   -18.74mA   -63.85mA
2.291V    -40.42mA   -19.45mA   -68.55mA
3.6V      -41.01mA   -19.75mA   -69.5mA
[GND_clamp]
|   voltage   I(typ)   I(min)   I(max)
-1.8V     -274mA     -200.4mA   -365.5mA
-1.109V   -45.41mA   -39.33mA   -55.91mA
-1.073V   -36.49mA   -33.11mA   -44.46mA
-1.036V   -28.34mA   -27.37mA   -34.29mA
-1V       -22.19mA   -22.71mA   -27mA
-927.3mV  -12.97mA   -14.93mA   -16.12mA
-854.5mV  -8.452mA   -9.555mA   -10.93mA
-781.8mV  -5.549mA   -5.539mA   -7.634mA
-709.1mV  -3.363mA   -2.741mA   -5.028mA
-600mV    -1.121mA   -737.1uA   -1.924mA
-381.8mV  -62.21uA   -38.42uA   -93.33uA
1.8V      98.66uA    51.35uA    168.2uA
[Ramp]
| variable   typ   min   max
dV/dt_f 0.65747681/1.2908455n  0.3704297/2.2944132n 0.82860069/0.8522379n
dV/dt_r 0.69333817/1.4866931n 0.45698641/3.7962924n 0.86796155/0.73936676n
R_load = 50
[Rising Waveform]
R_fixture = 50
V_fixture = 1.8
V_fixture_min = 1.62
V_fixture_max = 1.95
|   time   V(typ)   V(min)   V(max)
0s        706.2mV    1.003V     571.3mV
615.6ps   706.2mV    1.003V     586.8mV
673.8ps   706.2mV    1.003V     780.1mV
767.3ps   706.2mV    1.003V     1.567V
812.6ps   721.4mV    1.003V     1.785V
1.099ns   1.708V     1.003V     1.934V
1.275ns   1.772V     1.054V     1.941V
1.662ns   1.79V      1.553V     1.945V
1.928ns   1.793V     1.605V     1.946V
17.87ns   1.798V     1.619V     1.948V
[Rising Waveform]
R_fixture = 50
V_fixture = 0
V_fixture_min = 0
V_fixture_max = 0
|   time   V(typ)   V(min)   V(max)
0s        0V         0V         0V
763.6ps   0V         0V         0V
1.096ns   0V         0V         453.3mV
1.406ns   159.7mV    0V         868.9mV
1.649ns   311.5mV    0V         1.101V
2.071ns   561.6mV    22.15mV    1.277V
2.688ns   831.9mV    115.7mV    1.366V
4.141ns   1.049V     355.3mV    1.418V
7.304ns   1.128V     630.8mV    1.431V
18.03ns   1.141V     743.8mV    1.432V
[Falling Waveform]
R_fixture = 50
V_fixture = 1.8
V_fixture_min = 1.62
V_fixture_max = 1.95
|   time   V(typ)   V(min)   V(max)
0s        1.799V     1.619V     1.948V
797.8ps   1.799V     1.619V     1.939V
1.186ns   1.784V     1.619V     1.573V
1.58ns    1.581V     1.619V     1.266V
2.027ns   1.386V     1.615V     730.2mV
2.348ns   1.242V     1.574V     592.9mV
3.097ns   821.6mV    1.446V     573mV
3.845ns   726.5mV    1.335V     571.2mV
6.463ns   706.1mV    1.038V     571mV
17.87ns   705.8mV    1.004V     571mV
[Falling Waveform]
R_fixture = 50
V_fixture = 0
V_fixture_min = 0
V_fixture_max = 0
|   time   V(typ)   V(min)   V(max)
0s        1.141V     750.3mV    1.432V
793.2ps   1.141V     750.3mV    1.424V
1.188ns   1.119V     750.3mV    926mV
1.659ns   752.1mV    750.3mV    357.4mV
1.983ns   491.5mV    745.6mV    101.7mV
2.258ns   313.5mV    689.8mV    6.563mV
3.121ns   17.54mV    363.2mV    0V
4.067ns   0V         123.2mV    0V
5.107ns   0V         11.52mV    0V
18.03ns   0V         0V         0V
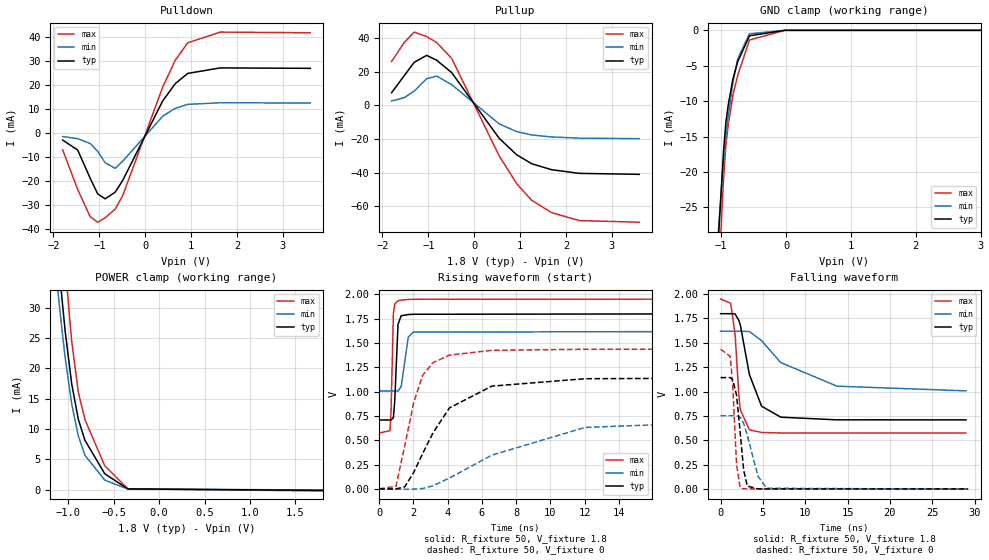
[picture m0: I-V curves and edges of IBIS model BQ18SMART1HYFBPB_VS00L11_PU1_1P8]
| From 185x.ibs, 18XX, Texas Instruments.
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|   Model Cell BQ18SMART1HYFBPB_VS00L11_PU1_1P8
|BQ18SMART1HYFBPB_VS00L11_PU1_1P8
[Model]   BQ18SMART1HYFBPB_VS00L11_PU1_1P8
Model_type   I/O
Polarity   Non-Inverting
Enable   Active-Low
Vinl =  0.63
Vinh =  1.17
Cref =  15pF
Rref =  100.0000M
Vref =  0V
Vmeas =  0.9
C_comp   0.9029199p   0.7983694p   1.014934p
[Model Spec]
Vinl   0.63   0.567   0.6825
Vinh   1.17   1.053   1.2675
[Temperature Range]   25   125   -40
[Voltage Range]   1.8   1.62   1.95
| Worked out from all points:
|   slope of the pulldown table from 0 to 0.27 V, typ, clamps not added: 27.2 ohm
|   slope of the pullup table from 0 to 0.27 V, typ, clamps not added: 26 ohm
|   GND clamp passes 1 mA (typ) near -0.58 V on its own axis
|   POWER clamp passes 1 mA (typ) near -0.49 V on its own axis
|   rising waveform, R_fixture 50, V_fixture 1.8: 20-80 % time 146ps typ, 268ps min, 100ps max; typ from 0.71 V to 1.8 V
|   rising waveform, R_fixture 50, V_fixture 0: 20-80 % time 2.43ns typ, 6.33ns min, 1.16ns max; typ from 0.003 V to 1.14 V
|   falling waveform, R_fixture 50, V_fixture 1.8: 20-80 % time 1.69ns typ, 5.28ns min, 662ps max; typ from 1.8 V to 0.71 V
|   falling waveform, R_fixture 50, V_fixture 0: 20-80 % time 711ps typ, 1.34ns min, 483ps max; typ from 1.14 V to 0.002 V
| Nom Voltages:
|   BIASFET=1.8, VBBNW=1.1, VDD=1.1, VDDS=1.8, VSS=0, VSSS=0
| Min Voltages:
|   BIASFET=1.62, VBBNW=0.99, VDD=0.99, VDDS=1.62, VSS=0, VSSS=0
| Max Voltages:
|   BIASFET=1.95, VBBNW=1.21, VDD=1.21, VDDS=1.95, VSS=0, VSSS=0
[POWER_clamp]
|   voltage   I(typ)   I(min)   I(max)
-1.8V     196.9mA    157.5mA    250.4mA
-1.182V   51.7mA     43.01mA    68.62mA
-1.145V   44.47mA    37.18mA    60.11mA
-1.109V   37.92mA    31.75mA    52.08mA
-1.073V   31.81mA    26.61mA    44.34mA
-1.036V   26.13mA    21.76mA    36.87mA
-963.6mV  17.41mA    14.08mA    24.42mA
-890.9mV  11.59mA    8.834mA    16.07mA
-818.2mV  8.134mA    5.657mA    11.55mA
-600mV    2.616mA    1.567mA    3.937mA
-345.5mV  117.2uA    78.7uA     135.4uA
1.8V      -127.5uA   -60.72uA   -226.5uA
[Pulldown]
|   voltage   I(typ)   I(min)   I(max)
-1.8V     -2.835mA   -1.376mA   -6.938mA
-1.473V   -6.994mA   -2.229mA   -23.44mA
-1.2V     -18.79mA   -4.282mA   -34.89mA
-1.036V   -25.34mA   -7.531mA   -37.14mA
-872.7mV  -27.39mA   -12.36mA   -35.28mA
-654.5mV  -24.59mA   -14.63mA   -31.68mA
-490.9mV  -19.69mA   -11.65mA   -26.08mA
381.8mV   13.54mA    7.117mA    19.32mA
654.5mV   20.72mA    10.44mA    30.48mA
927.3mV   25mA       12.07mA    37.79mA
1.636V    27.3mA     12.74mA    42.26mA
3.6V      27.12mA    12.64mA    41.97mA
[Pullup]
|   voltage   I(typ)   I(min)   I(max)
-1.8V     7.614mA    2.74mA     26.22mA
-1.527V   17.69mA    4.626mA    37.43mA
-1.309V   25.69mA    8.541mA    43.72mA
-1.036V   29.87mA    15.94mA    41.05mA
-818.2mV  26.95mA    17.52mA    37.49mA
-490.9mV  19.61mA    12.45mA    28.08mA
545.5mV   -19.54mA   -10.94mA   -30.03mA
927.3mV   -29.38mA   -15.56mA   -46.58mA
1.255V    -34.7mA    -17.56mA   -56.51mA
1.691V    -38.25mA   -18.74mA   -63.85mA
2.291V    -40.42mA   -19.45mA   -68.55mA
3.6V      -41.01mA   -19.75mA   -69.5mA
[GND_clamp]
|   voltage   I(typ)   I(min)   I(max)
-1.8V     -274mA     -200.4mA   -365.5mA
-1.109V   -45.43mA   -39.33mA   -55.98mA
-1.073V   -36.51mA   -33.12mA   -44.53mA
-1.036V   -28.36mA   -27.37mA   -34.36mA
-963.6mV  -17.09mA   -18.57mA   -21.02mA
-927.3mV  -12.99mA   -14.94mA   -16.2mA
-890.9mV  -10.53mA   -12.1mA    -13.35mA
-818.2mV  -6.846mA   -7.311mA   -9.151mA
-745.5mV  -4.434mA   -4.029mA   -6.378mA
-563.6mV  -767.1uA   -485.3uA   -1.366mA
-18.18mV  0A         0A         0A
3.6V      0A         0A         0A
[Ramp]
| variable   typ   min   max
dV/dt_f 0.65576966/1.6904402n 0.36940454/5.30086n   0.82627128/0.66526862n
dV/dt_r 0.69524061/2.4441913n 0.45695026/6.5015528n 0.87197292/1.1693115n
R_load = 50
[Rising Waveform]
R_fixture = 50
V_fixture = 1.8
V_fixture_min = 1.62
V_fixture_max = 1.95
|   time   V(typ)   V(min)   V(max)
0s        709.6mV    1.008V     576.4mV
628.5ps   709.6mV    1.008V     600.1mV
688.7ps   709.6mV    1.008V     793.4mV
827.3ps   734.3mV    1.008V     1.801V
904.3ps   901.6mV    1.008V     1.9V
1.099ns   1.692V     1.008V     1.932V
1.283ns   1.779V     1.052V     1.939V
1.693ns   1.791V     1.56V      1.946V
1.989ns   1.794V     1.611V     1.948V
28.98ns   1.8V       1.62V      1.95V
[Rising Waveform]
R_fixture = 50
V_fixture = 0
V_fixture_min = 0
V_fixture_max = 0
|   time   V(typ)   V(min)   V(max)
0s        2.78mV     0V         3.247mV
978.9ps   2.78mV     0V         29.49mV
1.488ns   23.66mV    0V         443.1mV
2.014ns   172mV      0V         888.3mV
2.534ns   364.5mV    6.481mV    1.167V
3.145ns   578.9mV    34.91mV    1.298V
4.098ns   833.1mV    113.9mV    1.375V
6.574ns   1.057V     348.6mV    1.424V
12.02ns   1.133V     633.4mV    1.435V
29.24ns   1.144V     746.1mV    1.436V
[Falling Waveform]
R_fixture = 50
V_fixture = 1.8
V_fixture_min = 1.62
V_fixture_max = 1.95
|   time   V(typ)   V(min)   V(max)
0s        1.799V     1.62V      1.949V
1.193ns   1.799V     1.62V      1.906V
1.72ns    1.796V     1.62V      1.584V
2.143ns   1.732V     1.62V      985.2mV
2.325ns   1.686V     1.62V      814.8mV
3.403ns   1.175V     1.616V     608.2mV
4.839ns   850.8mV    1.523V     581mV
7.101ns   738.2mV    1.298V     576.4mV
13.74ns   710.8mV    1.056V     576.1mV
28.98ns   710.3mV    1.008V     576.1mV
[Falling Waveform]
R_fixture = 50
V_fixture = 0
V_fixture_min = 0
V_fixture_max = 0
|   time   V(typ)   V(min)   V(max)
0s        1.144V     752.8mV    1.435V
1.142ns   1.144V     752.8mV    1.361V
1.434ns   1.12V      752.8mV    1.065V
1.888ns   964.6mV    752.8mV    249.6mV
2.324ns   572.2mV    737.3mV    9.456mV
2.72ns    199mV      674.6mV    4.335mV
3.148ns   31.93mV    554.8mV    3.433mV
4.403ns   2.857mV    134.2mV    3.117mV
5.435ns   2.358mV    9.199mV    3.082mV
29.24ns   2.13mV     0V         3.068mV
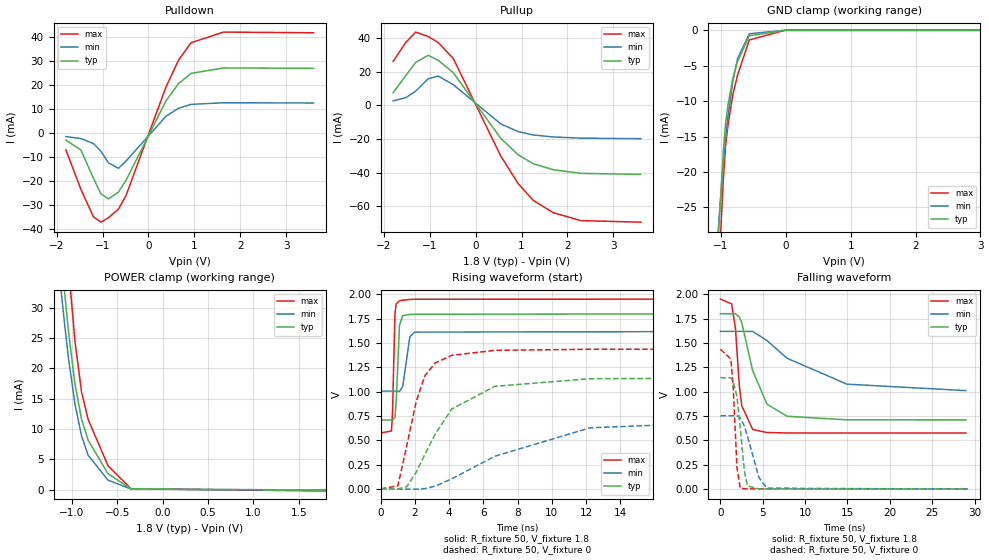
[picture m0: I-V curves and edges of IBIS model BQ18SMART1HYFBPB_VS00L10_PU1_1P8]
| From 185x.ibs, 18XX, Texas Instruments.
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|   Model Cell BQ18SMART1HYFBPB_VS00L10_PU1_1P8
|BQ18SMART1HYFBPB_VS00L10_PU1_1P8
[Model]   BQ18SMART1HYFBPB_VS00L10_PU1_1P8
Model_type   I/O
Polarity   Non-Inverting
Enable   Active-Low
Vinl =  0.63
Vinh =  1.17
Cref =  15pF
Rref =  100.0000M
Vref =  0V
Vmeas =  0.9
C_comp   0.9029199p   0.7983694p   1.014934p
[Model Spec]
Vinl   0.63   0.567   0.6825
Vinh   1.17   1.053   1.2675
[Temperature Range]   25   125   -40
[Voltage Range]   1.8   1.62   1.95
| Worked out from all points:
|   slope of the pulldown table from 0 to 0.27 V, typ, clamps not added: 27.2 ohm
|   slope of the pullup table from 0 to 0.27 V, typ, clamps not added: 26 ohm
|   GND clamp passes 1 mA (typ) near -0.58 V on its own axis
|   POWER clamp passes 1 mA (typ) near -0.49 V on its own axis
|   rising waveform, R_fixture 50, V_fixture 1.8: 20-80 % time 146ps typ, 270ps min, 101ps max; typ from 0.71 V to 1.8 V
|   rising waveform, R_fixture 50, V_fixture 0: 20-80 % time 2.5ns typ, 6.51ns min, 1.19ns max; typ from 0.003 V to 1.14 V
|   falling waveform, R_fixture 50, V_fixture 1.8: 20-80 % time 2.18ns typ, 6.59ns min, 782ps max; typ from 1.8 V to 0.71 V
|   falling waveform, R_fixture 50, V_fixture 0: 20-80 % time 759ps typ, 1.43ns min, 465ps max; typ from 1.14 V to 0.002 V
| Nom Voltages:
|   BIASFET=1.8, VBBNW=1.1, VDD=1.1, VDDS=1.8, VSS=0, VSSS=0
| Min Voltages:
|   BIASFET=1.62, VBBNW=0.99, VDD=0.99, VDDS=1.62, VSS=0, VSSS=0
| Max Voltages:
|   BIASFET=1.95, VBBNW=1.21, VDD=1.21, VDDS=1.95, VSS=0, VSSS=0
[POWER_clamp]
|   voltage   I(typ)   I(min)   I(max)
-1.8V     196.9mA    157.5mA    250.4mA
-1.182V   51.7mA     43.01mA    68.62mA
-1.145V   44.47mA    37.18mA    60.11mA
-1.109V   37.92mA    31.75mA    52.08mA
-1.073V   31.81mA    26.61mA    44.34mA
-1.036V   26.13mA    21.76mA    36.87mA
-963.6mV  17.41mA    14.08mA    24.42mA
-890.9mV  11.59mA    8.834mA    16.07mA
-818.2mV  8.134mA    5.657mA    11.55mA
-600mV    2.616mA    1.567mA    3.937mA
-345.5mV  117.2uA    78.7uA     135.4uA
1.8V      -127.5uA   -60.72uA   -226.5uA
[Pulldown]
|   voltage   I(typ)   I(min)   I(max)
-1.8V     -2.835mA   -1.376mA   -6.938mA
-1.473V   -6.994mA   -2.229mA   -23.44mA
-1.2V     -18.79mA   -4.282mA   -34.89mA
-1.036V   -25.34mA   -7.531mA   -37.14mA
-872.7mV  -27.39mA   -12.36mA   -35.28mA
-654.5mV  -24.59mA   -14.63mA   -31.68mA
-490.9mV  -19.69mA   -11.65mA   -26.08mA
381.8mV   13.54mA    7.117mA    19.32mA
654.5mV   20.72mA    10.44mA    30.48mA
927.3mV   25mA       12.07mA    37.79mA
1.636V    27.3mA     12.74mA    42.26mA
3.6V      27.12mA    12.64mA    41.97mA
[Pullup]
|   voltage   I(typ)   I(min)   I(max)
-1.8V     7.614mA    2.74mA     26.22mA
-1.527V   17.69mA    4.626mA    37.43mA
-1.309V   25.69mA    8.541mA    43.72mA
-1.036V   29.87mA    15.94mA    41.05mA
-818.2mV  26.95mA    17.52mA    37.49mA
-490.9mV  19.61mA    12.45mA    28.08mA
545.5mV   -19.54mA   -10.94mA   -30.03mA
927.3mV   -29.38mA   -15.56mA   -46.58mA
1.255V    -34.7mA    -17.56mA   -56.51mA
1.691V    -38.25mA   -18.74mA   -63.85mA
2.291V    -40.42mA   -19.45mA   -68.55mA
3.6V      -41.01mA   -19.75mA   -69.5mA
[GND_clamp]
|   voltage   I(typ)   I(min)   I(max)
-1.8V     -274mA     -200.4mA   -365.5mA
-1.109V   -45.43mA   -39.33mA   -55.98mA
-1.073V   -36.51mA   -33.12mA   -44.53mA
-1.036V   -28.36mA   -27.37mA   -34.36mA
-963.6mV  -17.09mA   -18.57mA   -21.02mA
-927.3mV  -12.99mA   -14.94mA   -16.2mA
-890.9mV  -10.53mA   -12.1mA    -13.35mA
-818.2mV  -6.846mA   -7.311mA   -9.151mA
-745.5mV  -4.434mA   -4.029mA   -6.378mA
-563.6mV  -767.1uA   -485.3uA   -1.366mA
-18.18mV  0A         0A         0A
3.6V      0A         0A         0A
[Ramp]
| variable   typ   min   max
dV/dt_f 0.65589233/2.1829413n  0.3695353/6.6957334n 0.82635153/0.78405725n
dV/dt_r 0.69503411/2.5072779n 0.45680545/6.6942219n 0.87168344/1.1950379n
R_load = 50
[Rising Waveform]
R_fixture = 50
V_fixture = 1.8
V_fixture_min = 1.62
V_fixture_max = 1.95
|   time   V(typ)   V(min)   V(max)
0s        709.9mV    1.006V     576.1mV
626.4ps   709.9mV    1.006V     597.1mV
689.9ps   709.9mV    1.006V     796.6mV
828.1ps   735.2mV    1.006V     1.799V
904.5ps   901.4mV    1.006V     1.9V
1.094ns   1.68V      1.002V     1.932V
1.286ns   1.78V      1.055V     1.939V
1.698ns   1.792V     1.563V     1.946V
1.99ns    1.794V     1.611V     1.948V
28.98ns   1.8V       1.62V      1.95V
[Rising Waveform]
R_fixture = 50
V_fixture = 0
V_fixture_min = 0
V_fixture_max = 0
|   time   V(typ)   V(min)   V(max)
0s        2.538mV    0V         3.619mV
999.6ps   2.538mV    0V         33.43mV
1.523ns   25.28mV    0V         447.8mV
2.066ns   172.8mV    0V         895.9mV
2.589ns   360.2mV    6.597mV    1.168V
3.195ns   568.3mV    32.35mV    1.296V
4.149ns   822.2mV    106.1mV    1.373V
6.67ns    1.055V     337.9mV    1.424V
12.23ns   1.133V     629.3mV    1.435V
29.23ns   1.144V     746mV      1.436V
[Falling Waveform]
R_fixture = 50
V_fixture = 1.8
V_fixture_min = 1.62
V_fixture_max = 1.95
|   time   V(typ)   V(min)   V(max)
0s        1.8V       1.619V     1.95V
1.329ns   1.8V       1.619V     1.9V
1.784ns   1.8V       1.619V     1.646V
2.23ns    1.766V     1.619V     1.066V
2.523ns   1.709V     1.619V     855.4mV
3.82ns    1.214V     1.618V     611.7mV
5.507ns   871.8mV    1.524V     581.4mV
7.868ns   747.8mV    1.343V     576.6mV
14.94ns   711.2mV    1.077V     576.1mV
28.98ns   710.3mV    1.011V     576.1mV
[Falling Waveform]
R_fixture = 50
V_fixture = 0
V_fixture_min = 0
V_fixture_max = 0
|   time   V(typ)   V(min)   V(max)
0s        1.144V     753.1mV    1.435V
1.238ns   1.141V     753.1mV    1.336V
1.511ns   1.105V     753.1mV    1.056V
1.959ns   947.7mV    753.1mV    222.6mV
2.347ns   627.7mV    731.6mV    9.738mV
2.832ns   185.3mV    647.1mV    4.153mV
3.198ns   32.51mV    541mV      3.509mV
4.551ns   2.921mV    120.6mV    3.142mV
5.478ns   2.46mV     10.38mV    3.096mV
29.23ns   2.13mV     0V         3.068mV
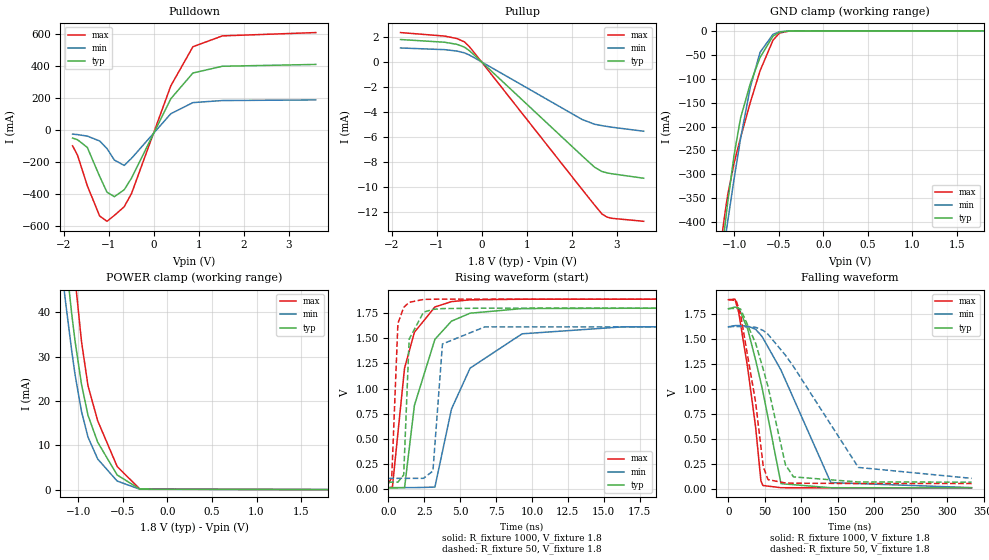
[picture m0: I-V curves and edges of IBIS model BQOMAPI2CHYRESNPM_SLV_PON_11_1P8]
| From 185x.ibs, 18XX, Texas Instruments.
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|   Model Cell BQOMAPI2CHYRESNPM_SLV_PON_11_1P8
|BQOMAPI2CHYRESNPM_SLV_PON_11_1P8
[Model]   BQOMAPI2CHYRESNPM_SLV_PON_11_1P8
Model_type   I/O
Polarity   Non-Inverting
Enable   Active-Low
Vinl =  0.54
Vinh =  1.26
Cref =  400.0000PF
Rref =  1000.0000
Vref =  1.8V
Vmeas =  0.9
C_comp   3.856143p   3.721565p   3.857354p
[Model Spec]
Vinl   0.54   0.486   0.567
Vinh   1.26   1.134   1.323
[Temperature Range]   25   125   -40
[Voltage Range]   1.8   1.62   1.89
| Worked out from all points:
|   slope of the pulldown table from 0 to 0.27 V, typ, clamps not added: 1.82 ohm
|   slope of the pullup table from 0 to 0.27 V, typ, clamps not added: 297 ohm
|   GND clamp passes 1 mA (typ) near -0.43 V on its own axis
|   POWER clamp passes 1 mA (typ) near -0.44 V on its own axis
|   rising waveform, R_fixture 1000, V_fixture 1.8: 20-80 % time 1.65ns typ, 2.52ns min, 1.23ns max; typ from 0.013 V to 1.8 V
|   rising waveform, R_fixture 50, V_fixture 1.8: 20-80 % time 288ps typ, 336ps min, 269ps max; typ from 0.07 V to 1.8 V
|   falling waveform, R_fixture 1000, V_fixture 1.8: 20-80 % time 31ns typ, 58.2ns min, 20.6ns max; typ from 1.8 V to 0.013 V
|   falling waveform, R_fixture 50, V_fixture 1.8: 20-80 % time 35.8ns typ, 75.9ns min, 22.4ns max; typ from 1.8 V to 0.07 V
| Nom Voltages:
|   BIASFET=1.8, VDDS=1.8, VDDU=1.2, BUS_VDD=0, VSS=0, VSSS=0
| Min Voltages:
|   BIASFET=1.62, VDDS=1.62, VDDU=1.08, BUS_VDD=0, VSS=0, VSSS=0
| Max Voltages:
|   BIASFET=1.89, VDDS=1.89, VDDU=1.32, BUS_VDD=0, VSS=0, VSSS=0
[POWER_clamp]
|   voltage   I(typ)   I(min)   I(max)
-1.8V     219.8mA    174.8mA    280.3mA
-1.218V   68.59mA    55.65mA    92.28mA
-1.182V   60.61mA    49.1mA     82.82mA
-1.145V   52.95mA    42.72mA    73.55mA
-1.073V   39.56mA    31.2mA     56.02mA
-1.036V   33.49mA    25.92mA    47.65mA
-963.6mV  23.72mA    17.61mA    33.37mA
-890.9mV  16.76mA    11.84mA    23.42mA
-781.8mV  10.67mA    6.886mA    15.5mA
-563.6mV  3.296mA    1.922mA    5.2mA
-309.1mV  100.1uA    71.54uA    112.3uA
1.8V      -2.406uA   -6.294uA   -2.119uA
[Pulldown]
|   voltage   I(typ)   I(min)   I(max)
-1.8V     -50.55mA   -25.79mA   -98.93mA
-1.691V   -60.77mA   -28.75mA   -157.4mA
-1.473V   -109.1mA   -38.23mA   -348.2mA
-1.2V     -289.2mA   -68.4mA    -537.2mA
-1.036V   -388.5mA   -116.2mA   -570.2mA
-872.7mV  -416.3mA   -187.6mA   -533.5mA
-654.5mV  -373.4mA   -221.2mA   -479.4mA
-490.9mV  -300mA     -176.7mA   -396.1mA
381.8mV   195.6mA    101.9mA    276.3mA
872.7mV   356.1mA    171.1mA    520.2mA
1.527V    398.1mA    184mA      587.8mA
3.6V      409.5mA    187.8mA    608.5mA
[Pullup]
|   voltage   I(typ)   I(min)   I(max)
-1.8V     1.788mA    1.113mA    2.344mA
-818.2mV  1.57mA     978uA      2.062mA
-545.5mV  1.402mA    865.9uA    1.865mA
-381.8mV  1.182mA    723.3uA    1.6mA
-272.7mV  902.4uA    552.4uA    1.226mA
-163.6mV  549.3uA    336.9uA    743.2uA
2.236V    -7.521mA   -4.608mA   -10.21mA
2.509V    -8.415mA   -4.98mA    -11.44mA
2.673V    -8.759mA   -5.094mA   -12.15mA
2.782V    -8.863mA   -5.158mA   -12.4mA
2.891V    -8.94mA    -5.218mA   -12.5mA
3.6V      -9.298mA   -5.542mA   -12.74mA
[GND_clamp]
|   voltage   I(typ)   I(min)   I(max)
-1.8V     -1.732A    -1.456A    -1.797A
-1.145V   -477.7mA   -496.1mA   -441.1mA
-1.109V   -417.6mA   -447.5mA   -389.2mA
-1.073V   -360.2mA   -399.8mA   -343.9mA
-1V       -259mA     -308.9mA   -276mA
-927.3mV  -181.9mA   -224.8mA   -222.9mA
-818.2mV  -110mA     -117.7mA   -149.4mA
-709.1mV  -55.63mA   -44.94mA   -83.51mA
-563.6mV  -11.08mA   -7.285mA   -19.53mA
-490.9mV  -2.699mA   -1.926mA   -4.617mA
-381.8mV  -277uA     -254.4uA   -403uA
1.8V      5.734uA    8.877uA    5.605uA
[Ramp]
| variable   typ   min   max
dV/dt_f  1.0789844/31.747321n 0.96546328/59.84594n   1.1356696/20.978021n
dV/dt_r 0.69715193/1.3710802n 0.50881963/1.9416117n  0.8070078/1.0499902n
R_load = 528.0
[Rising Waveform]
R_fixture = 1000
V_fixture = 1.8
V_fixture_min = 1.62
V_fixture_max = 1.89
|   time   V(typ)   V(min)   V(max)
0s        13.29mV    15.35mV    12.97mV
281ps     13.28mV    15.35mV    20.88mV
1.127ns   14.21mV    15.35mV    1.204V
1.812ns   832.4mV    15.35mV    1.56V
3.24ns    1.49V      20.49mV    1.812V
4.394ns   1.671V     796.8mV    1.865V
5.691ns   1.75V      1.204V     1.883V
9.311ns   1.796V     1.545V     1.889V
16.4ns    1.799V     1.615V     1.889V
333.4ns   1.799V     1.618V     1.889V
[Rising Waveform]
R_fixture = 50
V_fixture = 1.8
V_fixture_min = 1.62
V_fixture_max = 1.89
|   time   V(typ)   V(min)   V(max)
0s        69.84mV    107.8mV    55.99mV
232.9ps   69.84mV    107.8mV    110.9mV
663.7ps   69.89mV    107.8mV    1.648V
1.067ns   140.9mV    107.8mV    1.808V
1.447ns   1.492V     107.8mV    1.858V
2.448ns   1.76V      107.7mV    1.887V
3.103ns   1.788V     181.3mV    1.889V
3.766ns   1.796V     1.444V     1.89V
6.717ns   1.8V       1.614V     1.89V
333.5ns   1.8V       1.62V      1.89V
[Falling Waveform]
R_fixture = 1000
V_fixture = 1.8
V_fixture_min = 1.62
V_fixture_max = 1.89
|   time   V(typ)   V(min)   V(max)
0s        1.799V     1.618V     1.889V
8.943ns   1.816V     1.631V     1.895V
14.06ns   1.808V     1.631V     1.762V
26.41ns   1.597V     1.627V     1.208V
37.25ns   1.288V     1.594V     620.6mV
44.55ns   1.061V     1.536V     83.6mV
47.26ns   973.1mV    1.508V     36.43mV
72.09ns   54.79mV    1.187V     14.45mV
140.4ns   14.11mV    65.69mV    13.02mV
333.4ns   13.29mV    15.35mV    12.97mV
[Falling Waveform]
R_fixture = 50
V_fixture = 1.8
V_fixture_min = 1.62
V_fixture_max = 1.89
|   time   V(typ)   V(min)   V(max)
0s        1.8V       1.62V      1.89V
10.6ns    1.803V     1.622V     1.881V
16.72ns   1.796V     1.622V     1.737V
37.33ns   1.454V     1.614V     863.9mV
47.8ns    1.193V     1.582V     224mV
54.29ns   1.022V     1.544V     95.01mV
78.11ns   244.7mV    1.336V     61.52mV
89.21ns   122.5mV    1.223V     59.2mV
178.2ns   71.63mV    216.6mV    56.39mV
333.5ns   69.84mV    107.8mV    56.34mV
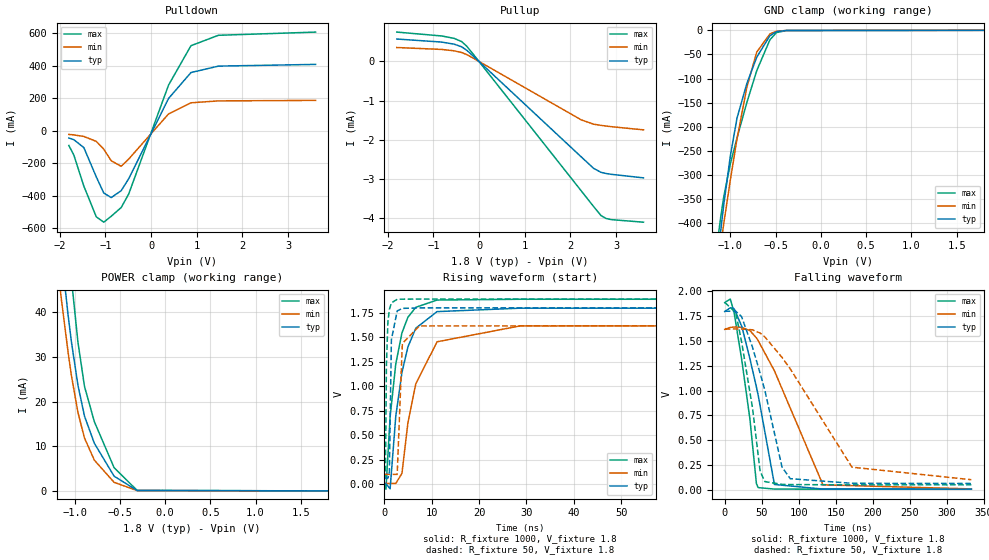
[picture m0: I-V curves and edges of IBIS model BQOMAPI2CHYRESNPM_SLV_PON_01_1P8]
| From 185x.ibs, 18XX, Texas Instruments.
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|   Model Cell BQOMAPI2CHYRESNPM_SLV_PON_01_1P8
|BQOMAPI2CHYRESNPM_SLV_PON_01_1P8
[Model]   BQOMAPI2CHYRESNPM_SLV_PON_01_1P8
Model_type   I/O
Polarity   Non-Inverting
Enable   Active-Low
Vinl =  0.54
Vinh =  1.26
Cref =  400.0000PF
Rref =  1000.0000
Vref =  1.8V
Vmeas =  0.9
C_comp   3.856143p   3.721565p   3.857354p
[Model Spec]
Vinl   0.54   0.486   0.567
Vinh   1.26   1.134   1.323
[Temperature Range]   25   125   -40
[Voltage Range]   1.8   1.62   1.89
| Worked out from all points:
|   slope of the pulldown table from 0 to 0.27 V, typ, clamps not added: 1.83 ohm
|   slope of the pullup table from 0 to 0.27 V, typ, clamps not added: 925 ohm
|   GND clamp passes 1 mA (typ) near -0.43 V on its own axis
|   POWER clamp passes 1 mA (typ) near -0.44 V on its own axis
|   rising waveform, R_fixture 1000, V_fixture 1.8: 20-80 % time 3.41ns typ, 4.57ns min, 2.73ns max; typ from 0.006 V to 1.8 V
|   rising waveform, R_fixture 50, V_fixture 1.8: 20-80 % time 335ps typ, 364ps min, 322ps max; typ from 0.063 V to 1.8 V
|   falling waveform, R_fixture 1000, V_fixture 1.8: 20-80 % time 29.8ns typ, 55.5ns min, 20ns max; typ from 1.8 V to 0.006 V
|   falling waveform, R_fixture 50, V_fixture 1.8: 20-80 % time 35.4ns typ, 74.9ns min, 22.3ns max; typ from 1.8 V to 0.063 V
| Nom Voltages:
|   BIASFET=1.8, VDDS=1.8, VDDU=1.2, BUS_VDD=0, VSS=0, VSSS=0
| Min Voltages:
|   BIASFET=1.62, VDDS=1.62, VDDU=1.08, BUS_VDD=0, VSS=0, VSSS=0
| Max Voltages:
|   BIASFET=1.89, VDDS=1.89, VDDU=1.32, BUS_VDD=0, VSS=0, VSSS=0
[POWER_clamp]
|   voltage   I(typ)   I(min)   I(max)
-1.8V     219.8mA    174.8mA    280.3mA
-1.218V   68.59mA    55.65mA    92.28mA
-1.182V   60.61mA    49.1mA     82.82mA
-1.145V   52.95mA    42.72mA    73.55mA
-1.073V   39.56mA    31.2mA     56.02mA
-1.036V   33.49mA    25.92mA    47.65mA
-963.6mV  23.72mA    17.61mA    33.37mA
-890.9mV  16.76mA    11.84mA    23.42mA
-781.8mV  10.67mA    6.886mA    15.5mA
-563.6mV  3.296mA    1.922mA    5.2mA
-309.1mV  100.1uA    71.54uA    112.3uA
1.8V      -2.406uA   -6.294uA   -2.119uA
[Pulldown]
|   voltage   I(typ)   I(min)   I(max)
-1.8V     -44.23mA   -22.05mA   -90.27mA
-1.691V   -54.48mA   -25.05mA   -148.8mA
-1.473V   -102.9mA   -34.61mA   -339.6mA
-1.2V     -283.1mA   -64.88mA   -528.6mA
-1.036V   -382.4mA   -112.8mA   -561.7mA
-872.7mV  -410.4mA   -184.2mA   -525.1mA
-654.5mV  -367.8mA   -218.1mA   -471.6mA
-490.9mV  -294.8mA   -173.7mA   -388.8mA
381.8mV   198.8mA    103.7mA    281mA
872.7mV   358.2mA    172.2mA    523.3mA
1.473V    397.7mA    183.9mA    587.2mA
3.6V      408.3mA    187mA      606.9mA
[Pullup]
|   voltage   I(typ)   I(min)   I(max)
-1.8V     571.9uA    354.7uA    748.8uA
-818.2mV  493.7uA    305.9uA    650.1uA
-545.5mV  440.8uA    271uA      588.1uA
-381.8mV  374.1uA    228uA      507.7uA
-272.7mV  288.2uA    175.8uA    392.6uA
-163.6mV  176uA      107.6uA    238.5uA
2.236V    -2.437mA   -1.492mA   -3.304mA
2.509V    -2.732mA   -1.603mA   -3.708mA
2.673V    -2.834mA   -1.634mA   -3.94mA
2.782V    -2.863mA   -1.651mA   -4.011mA
2.891V    -2.883mA   -1.666mA   -4.04mA
3.6V      -2.974mA   -1.748mA   -4.106mA
[GND_clamp]
|   voltage   I(typ)   I(min)   I(max)
-1.8V     -1.732A    -1.456A    -1.797A
-1.145V   -477.7mA   -496.1mA   -441.1mA
-1.109V   -417.6mA   -447.5mA   -389.2mA
-1.073V   -360.2mA   -399.8mA   -343.9mA
-1V       -259mA     -308.9mA   -276mA
-927.3mV  -181.9mA   -224.8mA   -222.9mA
-818.2mV  -110mA     -117.7mA   -149.4mA
-709.1mV  -55.63mA   -44.94mA   -83.51mA
-563.6mV  -11.08mA   -7.285mA   -19.53mA
-490.9mV  -2.699mA   -1.926mA   -4.617mA
-381.8mV  -277uA     -254.4uA   -403uA
1.8V      5.734uA    8.877uA    5.605uA
[Ramp]
| variable   typ   min   max
dV/dt_f  1.0894495/31.01121n  0.97251897/58.029553n  1.1491325/20.696517n
dV/dt_r 0.45924644/2.3496157n 0.31064415/2.9148826n 0.55747225/1.9457172n
R_load = 528.0
[Rising Waveform]
R_fixture = 1000
V_fixture = 1.8
V_fixture_min = 1.62
V_fixture_max = 1.89
|   time   V(typ)   V(min)   V(max)
0s        6.366mV    8.358mV    5.201mV
318.4ps   6.365mV    8.358mV    -50.15mV
1.199ns   -46.63mV   8.357mV    688.9mV
2.394ns   693.3mV    8.459mV    1.228V
3.699ns   1.142V     110.5mV    1.545V
4.962ns   1.402V     628.7mV    1.705V
6.63ns    1.593V     1.026V     1.806V
11.12ns   1.762V     1.454V     1.88V
28.67ns   1.797V     1.616V     1.888V
333.4ns   1.797V     1.617V     1.888V
[Rising Waveform]
R_fixture = 50
V_fixture = 1.8
V_fixture_min = 1.62
V_fixture_max = 1.89
|   time   V(typ)   V(min)   V(max)
0s        63.15mV    101.1mV    49.61mV
211ps     63.15mV    101.1mV    92.08mV
417.7ps   63.15mV    101.1mV    1.22V
736.1ps   62.89mV    101.1mV    1.659V
1.045ns   123.4mV    101.1mV    1.784V
1.463ns   1.473V     101.1mV    1.85V
2.697ns   1.769V     100.5mV    1.888V
3.785ns   1.795V     1.437V     1.889V
7.388ns   1.8V       1.616V     1.89V
333.5ns   1.8V       1.62V      1.89V
[Falling Waveform]
R_fixture = 1000
V_fixture = 1.8
V_fixture_min = 1.62
V_fixture_max = 1.89
|   time   V(typ)   V(min)   V(max)
0s        1.797V     1.617V     1.888V
7.583ns   1.835V     1.637V     1.923V
12.63ns   1.827V     1.641V     1.791V
23.03ns   1.649V     1.638V     1.311V
34.12ns   1.321V     1.605V     711.6mV
42.89ns   1.035V     1.531V     61.41mV
45.23ns   955mV      1.504V     21.39mV
67.22ns   53.05mV    1.199V     6.644mV
132.8ns   6.858mV    49.41mV    5.815mV
333.4ns   6.366mV    8.358mV    5.781mV
[Falling Waveform]
R_fixture = 50
V_fixture = 1.8
V_fixture_min = 1.62
V_fixture_max = 1.89
|   time   V(typ)   V(min)   V(max)
0s        1.8V       1.62V      1.89V
15.02ns   1.8V       1.622V     1.786V
22.73ns   1.747V     1.621V     1.496V
37.5ns    1.439V     1.613V     831.2mV
47.88ns   1.175V     1.58V      185.6mV
54.32ns   1.001V     1.541V     81.8mV
77.5ns    228.4mV    1.334V     54.04mV
88.54ns   111.6mV    1.22V      51.96mV
172ns     65.05mV    227.5mV    49.42mV
333.5ns   63.15mV    101.1mV    49.37mV
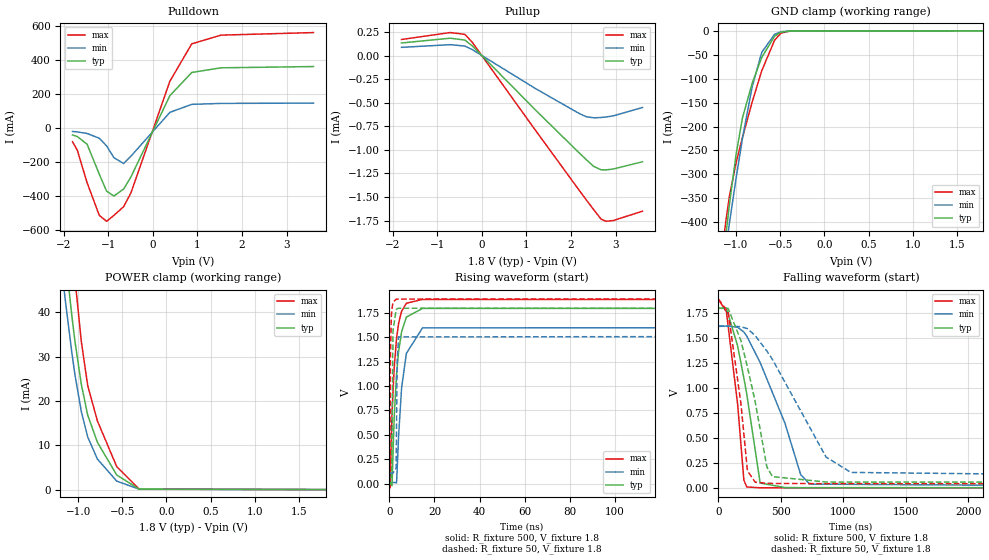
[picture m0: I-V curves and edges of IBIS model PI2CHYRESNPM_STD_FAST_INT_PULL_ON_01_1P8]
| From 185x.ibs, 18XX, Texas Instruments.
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|   Model Cell PI2CHYRESNPM_STD_FAST_INT_PULL_ON_01_1P8
|BQOMAPI2CHYRESNPM_STD_FAST_INT_PULL_ON_01_1P8
[Model]   PI2CHYRESNPM_STD_FAST_INT_PULL_ON_01_1P8
Model_type   I/O
Polarity   Non-Inverting
Enable   Active-Low
Vinl =  0.54
Vinh =  1.26
Cref =  400.0000PF
Rref =  500.0000
Vref =  1.8V
Vmeas =  0.9
C_comp   3.856143p   3.721565p   3.857354p
[Model Spec]
Vinl   0.54   0.486   0.567
Vinh   1.26   1.134   1.323
[Temperature Range]   25   125   -40
[Voltage Range]   1.8   1.62   1.89
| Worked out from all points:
|   slope of the pulldown table from 0 to 0.27 V, typ, clamps not added: 1.9 ohm
|   slope of the pullup table from 0 to 0.27 V, typ, clamps not added: 2.07 kohm
|   GND clamp passes 1 mA (typ) near -0.43 V on its own axis
|   POWER clamp passes 1 mA (typ) near -0.44 V on its own axis
|   rising waveform, R_fixture 500, V_fixture 1.8: 20-80 % time 2.92ns typ, 3.4ns min, 2.57ns max; typ from 0.008 V to 1.8 V
|   rising waveform, R_fixture 50, V_fixture 1.8: 20-80 % time 352ps typ, 375ps min, 338ps max; typ from 0.063 V to 1.8 V
|   falling waveform, R_fixture 500, V_fixture 1.8: 20-80 % time 147ns typ, 293ns min, 95.1ns max; typ from 1.8 V to 0.008 V
|   falling waveform, R_fixture 50, V_fixture 1.8: 20-80 % time 174ns typ, 404ns min, 106ns max; typ from 1.8 V to 0.063 V
| Nom Voltages:
|   BIASFET=1.8, VDDS=1.8, VDDU=1.2, BUS_VDD=0, VSS=0, VSSS=0
| Min Voltages:
|   BIASFET=1.62, VDDS=1.62, VDDU=1.08, BUS_VDD=0, VSS=0, VSSS=0
| Max Voltages:
|   BIASFET=1.89, VDDS=1.89, VDDU=1.32, BUS_VDD=0, VSS=0, VSSS=0
[POWER_clamp]
|   voltage   I(typ)   I(min)   I(max)
-1.8V     219.8mA    174.8mA    280.3mA
-1.218V   68.59mA    55.65mA    92.28mA
-1.182V   60.61mA    49.1mA     82.82mA
-1.145V   52.95mA    42.72mA    73.55mA
-1.073V   39.56mA    31.2mA     56.02mA
-1.036V   33.49mA    25.92mA    47.65mA
-963.6mV  23.72mA    17.61mA    33.37mA
-890.9mV  16.76mA    11.84mA    23.42mA
-781.8mV  10.67mA    6.886mA    15.5mA
-563.6mV  3.296mA    1.922mA    5.2mA
-309.1mV  100.1uA    71.54uA    112.3uA
1.8V      -2.406uA   -6.294uA   -2.119uA
[Pulldown]
|   voltage   I(typ)   I(min)   I(max)
-1.8V     -40.66mA   -19.95mA   -80.65mA
-1.691V   -50.33mA   -22.81mA   -131.6mA
-1.473V   -95.21mA   -31.86mA   -322.4mA
-1.2V     -272.3mA   -60.14mA   -515.4mA
-1.036V   -372.5mA   -105.1mA   -550.4mA
-872.7mV  -401.2mA   -174.9mA   -515.5mA
-654.5mV  -360mA     -209.4mA   -464.2mA
-490.9mV  -288.2mA   -166.2mA   -382.9mA
381.8mV   191.4mA    92.79mA    276.6mA
872.7mV   328.3mA    140mA      497.4mA
1.527V    355.7mA    145.5mA    548.6mA
3.6V      363.2mA    147.5mA    563.8mA
[Pullup]
|   voltage   I(typ)   I(min)   I(max)
-1.8V     132.8uA    86.53uA    169.9uA
-709.1mV  183.6uA    115uA      243.3uA
-381.8mV  164.2uA    100.4uA    224.7uA
-218.2mV  104.8uA    64.18uA    143.5uA
1.2V      -576.1uA   -349.4uA   -790.8uA
2.182V    -1.032mA   -614.2uA   -1.428mA
2.345V    -1.105mA   -649.5uA   -1.532mA
2.509V    -1.176mA   -659.9uA   -1.635mA
2.673V    -1.211mA   -656.9uA   -1.734mA
2.782V    -1.212mA   -651.5uA   -1.757mA
2.945V    -1.203mA   -639.7uA   -1.749mA
3.6V      -1.126mA   -551.1uA   -1.65mA
[GND_clamp]
|   voltage   I(typ)   I(min)   I(max)
-1.8V     -1.732A    -1.456A    -1.797A
-1.145V   -477.7mA   -496.1mA   -441.1mA
-1.109V   -417.6mA   -447.5mA   -389.2mA
-1.073V   -360.2mA   -399.8mA   -343.9mA
-1V       -259mA     -308.9mA   -276.1mA
-927.3mV  -181.9mA   -224.8mA   -222.9mA
-818.2mV  -110mA     -117.7mA   -149.4mA
-709.1mV  -55.63mA   -44.94mA   -83.51mA
-563.6mV  -11.08mA   -7.285mA   -19.53mA
-490.9mV  -2.699mA   -1.926mA   -4.617mA
-381.8mV  -277uA     -254.4uA   -403uA
1.8V      5.734uA    8.877uA    5.605uA
[Ramp]
| variable   typ   min   max
dV/dt_f  1.0783051/0.1473957u 0.96574395/0.29131411u  1.1349301/95.57669n
dV/dt_r 0.30949481/3.6885166n 0.21363131/4.449942n  0.37665835/3.1494785n
R_load = 528.00
[Rising Waveform]
R_fixture = 500
V_fixture = 1.8
V_fixture_min = 1.62
V_fixture_max = 1.89
|   time   V(typ)   V(min)   V(max)
0s        7.737mV    12.33mV    5.683mV
294.2ps   7.735mV    12.33mV    -43.08mV
1.161ns   -22.13mV   12.32mV    716.2mV
2.099ns   664.2mV    12.33mV    1.175V
3.184ns   1.121V     8.296mV    1.49V
4.076ns   1.349V     486.4mV    1.641V
5.415ns   1.556V     980.6mV    1.766V
7.531ns   1.706V     1.334V     1.848V
14.71ns   1.795V     1.596V     1.887V
5us       1.798V     1.618V     1.888V
[Rising Waveform]
R_fixture = 50
V_fixture = 1.8
V_fixture_min = 1.62
V_fixture_max = 1.89
|   time   V(typ)   V(min)   V(max)
0s        63.01mV    107.5mV    47.77mV
203.3ps   63.01mV    107.5mV    90.5mV
435.5ps   63.01mV    107.5mV    1.257V
827.4ps   60.82mV    107.5mV    1.699V
1.032ns   137.9mV    107.5mV    1.774V
1.596ns   1.565V     107.5mV    1.858V
2.994ns   1.781V     161.2mV    1.889V
3.421ns   1.791V     1.221V     1.89V
4.03ns    1.797V     1.503V     1.89V
5us       1.8V       1.62V      1.89V
[Falling Waveform]
R_fixture = 500
V_fixture = 1.8
V_fixture_min = 1.62
V_fixture_max = 1.89
|   time   V(typ)   V(min)   V(max)
0s        1.798V     1.618V     1.888V
64.51ns   1.799V     1.621V     1.763V
154.5ns   1.422V     1.609V     839mV
204.2ns   1.102V     1.562V     84.96mV
226.9ns   946.4mV    1.522V     15.52mV
334.7ns   54.57mV    1.257V     7.076mV
533.5ns   9.213mV    650.2mV    6.366mV
658.9ns   8.314mV    138.4mV    6.301mV
731.2ns   8.098mV    43.74mV    6.286mV
5us       7.737mV    12.34mV    6.269mV
[Falling Waveform]
R_fixture = 50
V_fixture = 1.8
V_fixture_min = 1.62
V_fixture_max = 1.89
|   time   V(typ)   V(min)   V(max)
0s        1.8V       1.62V      1.89V
78.28ns   1.797V     1.62V      1.764V
180.6ns   1.477V     1.615V     849.6mV
232.7ns   1.213V     1.595V     176.1mV
294.6ns   868.1mV    1.526V     63.13mV
388.3ns   215.1mV    1.372V     51.97mV
433ns     118.4mV    1.288V     50.52mV
862ns     64.82mV    314.1mV    48.11mV
1.061us   63.63mV    160.4mV    48.07mV
5us       63.01mV    107.7mV    48.06mV
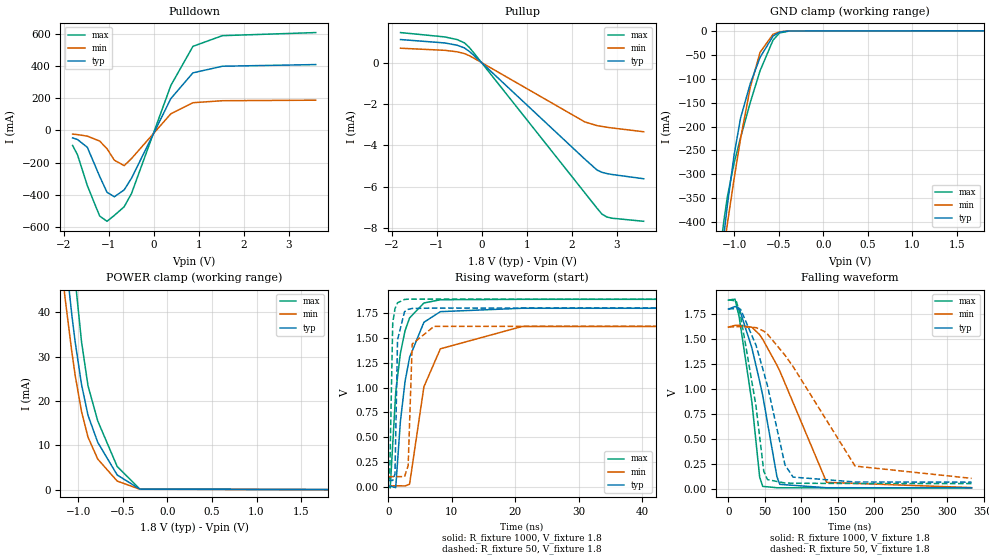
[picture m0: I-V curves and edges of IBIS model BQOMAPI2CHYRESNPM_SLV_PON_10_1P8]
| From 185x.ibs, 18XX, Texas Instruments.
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|   Model Cell BQOMAPI2CHYRESNPM_SLV_PON_10_1P8
|BQOMAPI2CHYRESNPM_SLV_PON_10_1P8
[Model]   BQOMAPI2CHYRESNPM_SLV_PON_10_1P8
Model_type   I/O
Polarity   Non-Inverting
Enable   Active-Low
Vinl =  0.54
Vinh =  1.26
Cref =  400.0000PF
Rref =  1000.0000
Vref =  1.8V
Vmeas =  0.9
C_comp   3.856143p   3.721565p   3.857354p
[Model Spec]
Vinl   0.54   0.486   0.567
Vinh   1.26   1.134   1.323
[Temperature Range]   25   125   -40
[Voltage Range]   1.8   1.62   1.89
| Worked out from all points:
|   slope of the pulldown table from 0 to 0.27 V, typ, clamps not added: 1.83 ohm
|   slope of the pullup table from 0 to 0.27 V, typ, clamps not added: 495 ohm
|   GND clamp passes 1 mA (typ) near -0.43 V on its own axis
|   POWER clamp passes 1 mA (typ) near -0.44 V on its own axis
|   rising waveform, R_fixture 1000, V_fixture 1.8: 20-80 % time 2.37ns typ, 3.41ns min, 1.82ns max; typ from 0.009 V to 1.8 V
|   rising waveform, R_fixture 50, V_fixture 1.8: 20-80 % time 314ps typ, 351ps min, 299ps max; typ from 0.066 V to 1.8 V
|   falling waveform, R_fixture 1000, V_fixture 1.8: 20-80 % time 30.4ns typ, 56.7ns min, 20.3ns max; typ from 1.8 V to 0.009 V
|   falling waveform, R_fixture 50, V_fixture 1.8: 20-80 % time 35.5ns typ, 75.3ns min, 22.4ns max; typ from 1.8 V to 0.066 V
| Nom Voltages:
|   BIASFET=1.8, VDDS=1.8, VDDU=1.2, BUS_VDD=0, VSS=0, VSSS=0
| Min Voltages:
|   BIASFET=1.62, VDDS=1.62, VDDU=1.08, BUS_VDD=0, VSS=0, VSSS=0
| Max Voltages:
|   BIASFET=1.89, VDDS=1.89, VDDU=1.32, BUS_VDD=0, VSS=0, VSSS=0
[POWER_clamp]
|   voltage   I(typ)   I(min)   I(max)
-1.8V     219.8mA    174.8mA    280.3mA
-1.218V   68.59mA    55.65mA    92.28mA
-1.182V   60.61mA    49.1mA     82.82mA
-1.145V   52.95mA    42.72mA    73.55mA
-1.073V   39.56mA    31.2mA     56.02mA
-1.036V   33.49mA    25.92mA    47.65mA
-963.6mV  23.72mA    17.61mA    33.37mA
-890.9mV  16.76mA    11.84mA    23.42mA
-781.8mV  10.67mA    6.886mA    15.5mA
-563.6mV  3.296mA    1.922mA    5.2mA
-309.1mV  100.1uA    71.54uA    112.3uA
1.8V      -2.406uA   -6.294uA   -2.119uA
[Pulldown]
|   voltage   I(typ)   I(min)   I(max)
-1.8V     -46.86mA   -23.61mA   -93.84mA
-1.691V   -57.09mA   -26.6mA    -152.3mA
-1.473V   -105.5mA   -36.12mA   -343.1mA
-1.2V     -285.6mA   -66.35mA   -532.1mA
-1.036V   -384.9mA   -114.2mA   -565.2mA
-872.7mV  -412.8mA   -185.6mA   -528.5mA
-654.5mV  -370.1mA   -219.4mA   -474.8mA
-490.9mV  -296.9mA   -174.9mA   -391.8mA
381.8mV   197.5mA    102.9mA    279.1mA
872.7mV   357.3mA    171.7mA    522mA
1.527V    398.4mA    184.1mA    588.4mA
3.6V      408.8mA    187.4mA    607.6mA
[Pullup]
|   voltage   I(typ)   I(min)   I(max)
-1.8V     1.111mA    692.2uA    1.447mA
-818.2mV  946uA      591uA      1.237mA
-545.5mV  839uA      520uA      1.111mA
-381.8mV  706.4uA    433.9uA    952.2uA
-272.7mV  540.2uA    331.9uA    731.1uA
-163.6mV  329.1uA    202.7uA    443.3uA
2.291V    -4.655mA   -2.862mA   -6.279mA
2.564V    -5.185mA   -3.042mA   -7.027mA
2.673V    -5.295mA   -3.083mA   -7.309mA
2.782V    -5.354mA   -3.119mA   -7.45mA
2.891V    -5.398mA   -3.153mA   -7.508mA
3.6V      -5.605mA   -3.338mA   -7.658mA
[GND_clamp]
|   voltage   I(typ)   I(min)   I(max)
-1.8V     -1.732A    -1.456A    -1.797A
-1.145V   -477.7mA   -496.1mA   -441.1mA
-1.109V   -417.6mA   -447.5mA   -389.2mA
-1.073V   -360.2mA   -399.8mA   -343.9mA
-1V       -259mA     -308.9mA   -276mA
-927.3mV  -181.9mA   -224.8mA   -222.9mA
-818.2mV  -110mA     -117.7mA   -149.4mA
-709.1mV  -55.63mA   -44.94mA   -83.51mA
-563.6mV  -11.08mA   -7.285mA   -19.53mA
-490.9mV  -2.699mA   -1.926mA   -4.617mA
-381.8mV  -277uA     -254.4uA   -403uA
1.8V      5.734uA    8.877uA    5.605uA
[Ramp]
| variable   typ   min   max
dV/dt_f  1.0843092/31.391649n 0.96927667/58.995261n  1.1422515/20.79166n
dV/dt_r 0.59133493/1.8045968n  0.4110771/2.3941835n 0.70112024/1.4515313n
R_load = 528.0
[Rising Waveform]
R_fixture = 1000
V_fixture = 1.8
V_fixture_min = 1.62
V_fixture_max = 1.89
|   time   V(typ)   V(min)   V(max)
0s        9.229mV    11.28mV    8.138mV
291.5ps   9.227mV    11.28mV    -9.181mV
1.161ns   -6.946mV   11.28mV    953.6mV
1.894ns   657.4mV    11.28mV    1.344V
2.638ns   1.065V     10.2mV     1.574V
3.345ns   1.303V     27.64mV    1.701V
5.605ns   1.657V     1.008V     1.851V
8.203ns   1.764V     1.39V      1.884V
21.09ns   1.798V     1.615V     1.888V
333.4ns   1.798V     1.618V     1.888V
[Rising Waveform]
R_fixture = 50
V_fixture = 1.8
V_fixture_min = 1.62
V_fixture_max = 1.89
|   time   V(typ)   V(min)   V(max)
0s        65.92mV    103.9mV    53.22mV
211ps     65.92mV    103.9mV    99.71mV
686.9ps   65.95mV    103.9mV    1.649V
1.045ns   130.6mV    103.9mV    1.795V
1.444ns   1.479V     103.9mV    1.853V
2.551ns   1.764V     103.6mV    1.887V
3.121ns   1.787V     214.3mV    1.889V
3.761ns   1.796V     1.438V     1.89V
7.2ns     1.8V       1.616V     1.89V
333.5ns   1.8V       1.62V      1.89V
[Falling Waveform]
R_fixture = 1000
V_fixture = 1.8
V_fixture_min = 1.62
V_fixture_max = 1.89
|   time   V(typ)   V(min)   V(max)
0s        1.798V     1.618V     1.888V
8.934ns   1.824V     1.635V     1.898V
14.65ns   1.808V     1.636V     1.723V
32.2ns    1.408V     1.616V     865.2mV
42.83ns   1.074V     1.542V     116.7mV
46.99ns   935.4mV    1.496V     23.55mV
66.48ns   121.5mV    1.237V     10.11mV
70.47ns   43.75mV    1.178V     9.765mV
134.7ns   9.903mV    63.7mV     8.768mV
333.4ns   9.229mV    11.28mV    8.719mV
[Falling Waveform]
R_fixture = 50
V_fixture = 1.8
V_fixture_min = 1.62
V_fixture_max = 1.89
|   time   V(typ)   V(min)   V(max)
0s        1.8V       1.62V      1.89V
10.58ns   1.803V     1.622V     1.881V
16.74ns   1.796V     1.622V     1.731V
37.74ns   1.438V     1.613V     830.3mV
48.5ns    1.165V     1.578V     173.9mV
53.62ns   1.028V     1.547V     91.19mV
77.55ns   238.4mV    1.337V     57.27mV
88.64ns   116.5mV    1.223V     55.02mV
173.7ns   67.79mV    226.5mV    52.27mV
333.5ns   65.92mV    103.9mV    52.22mV
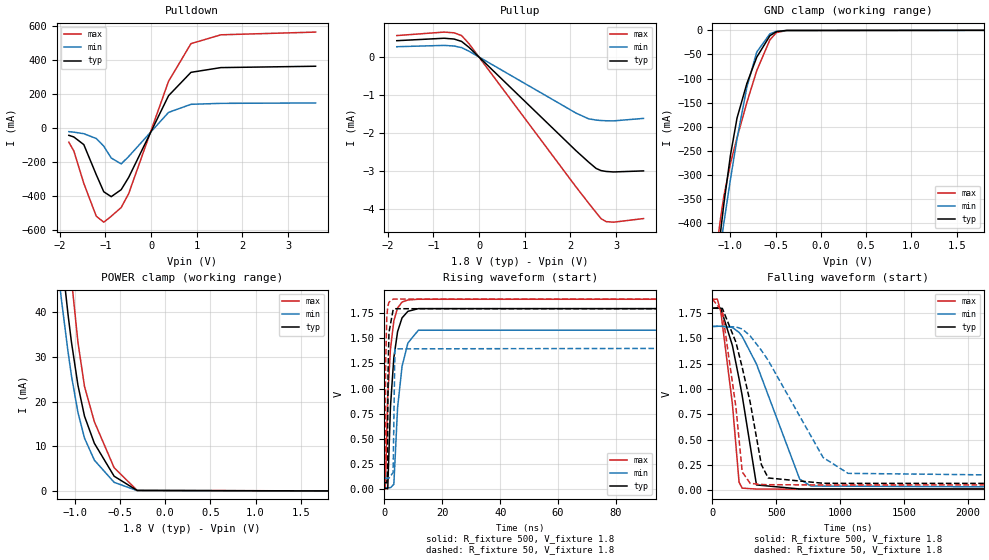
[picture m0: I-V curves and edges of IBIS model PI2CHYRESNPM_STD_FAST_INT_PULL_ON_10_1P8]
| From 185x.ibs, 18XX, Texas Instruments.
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|   Model Cell PI2CHYRESNPM_STD_FAST_INT_PULL_ON_10_1P8
|BQOMAPI2CHYRESNPM_STD_FAST_INT_PULL_ON_10_1P8
[Model]   PI2CHYRESNPM_STD_FAST_INT_PULL_ON_10_1P8
Model_type   I/O
Polarity   Non-Inverting
Enable   Active-Low
Vinl =  0.54
Vinh =  1.26
Cref =  400.0000PF
Rref =  500.0000
Vref =  1.8V
Vmeas =  0.9
C_comp   3.856143p   3.721565p   3.857354p
[Model Spec]
Vinl   0.54   0.486   0.567
Vinh   1.26   1.134   1.323
[Temperature Range]   25   125   -40
[Voltage Range]   1.8   1.62   1.89
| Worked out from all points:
|   slope of the pulldown table from 0 to 0.27 V, typ, clamps not added: 1.9 ohm
|   slope of the pullup table from 0 to 0.27 V, typ, clamps not added: 837 ohm
|   GND clamp passes 1 mA (typ) near -0.43 V on its own axis
|   POWER clamp passes 1 mA (typ) near -0.44 V on its own axis
|   rising waveform, R_fixture 500, V_fixture 1.8: 20-80 % time 2.29ns typ, 2.88ns min, 1.89ns max; typ from 0.01 V to 1.8 V
|   rising waveform, R_fixture 50, V_fixture 1.8: 20-80 % time 337ps typ, 367ps min, 321ps max; typ from 0.065 V to 1.8 V
|   falling waveform, R_fixture 500, V_fixture 1.8: 20-80 % time 149ns typ, 298ns min, 96.1ns max; typ from 1.8 V to 0.01 V
|   falling waveform, R_fixture 50, V_fixture 1.8: 20-80 % time 175ns typ, 410ns min, 106ns max; typ from 1.8 V to 0.065 V
| Nom Voltages:
|   BIASFET=1.8, VDDS=1.8, VDDU=1.2, BUS_VDD=0, VSS=0, VSSS=0
| Min Voltages:
|   BIASFET=1.62, VDDS=1.62, VDDU=1.08, BUS_VDD=0, VSS=0, VSSS=0
| Max Voltages:
|   BIASFET=1.89, VDDS=1.89, VDDU=1.32, BUS_VDD=0, VSS=0, VSSS=0
[POWER_clamp]
|   voltage   I(typ)   I(min)   I(max)
-1.8V     219.8mA    174.8mA    280.3mA
-1.218V   68.59mA    55.65mA    92.28mA
-1.182V   60.61mA    49.1mA     82.82mA
-1.145V   52.95mA    42.72mA    73.55mA
-1.073V   39.56mA    31.2mA     56.02mA
-1.036V   33.49mA    25.92mA    47.65mA
-963.6mV  23.72mA    17.61mA    33.37mA
-890.9mV  16.76mA    11.84mA    23.42mA
-781.8mV  10.67mA    6.886mA    15.5mA
-563.6mV  3.296mA    1.922mA    5.2mA
-309.1mV  100.1uA    71.54uA    112.3uA
1.8V      -2.406uA   -6.294uA   -2.119uA
[Pulldown]
|   voltage   I(typ)   I(min)   I(max)
-1.8V     -42.53mA   -21.01mA   -83.26mA
-1.691V   -52.2mA    -23.87mA   -134.3mA
-1.473V   -97.07mA   -32.91mA   -325.1mA
-1.2V     -274.1mA   -61.17mA   -518mA
-1.036V   -374.3mA   -106.1mA   -553mA
-872.7mV  -403mA     -175.9mA   -518.1mA
-654.5mV  -361.7mA   -210.4mA   -466.6mA
-490.9mV  -289.8mA   -167mA     -385.1mA
381.8mV   190.4mA    92.27mA    275.1mA
872.7mV   327.7mA    139.7mA    496.4mA
1.527V    355.5mA    145.4mA    548.2mA
3.6V      363.5mA    147.7mA    564.2mA
[Pullup]
|   voltage   I(typ)   I(min)   I(max)
-1.8V     437.2uA    277.8uA    572.5uA
-763.6mV  501.6uA    312.7uA    664.5uA
-545.5mV  480.9uA    296.2uA    645.8uA
-381.8mV  417.9uA    254.3uA    572.7uA
-218.2mV  259.5uA    158uA      356uA
2.127V    -2.475mA   -1.479mA   -3.434mA
2.4V      -2.773mA   -1.628mA   -3.858mA
2.564V    -2.94mA    -1.661mA   -4.108mA
2.673V    -2.997mA   -1.673mA   -4.268mA
2.782V    -3.019mA   -1.679mA   -4.345mA
2.945V    -3.032mA   -1.682mA   -4.36mA
3.6V      -3.004mA   -1.617mA   -4.264mA
[GND_clamp]
|   voltage   I(typ)   I(min)   I(max)
-1.8V     -1.732A    -1.456A    -1.797A
-1.145V   -477.7mA   -496.1mA   -441.1mA
-1.109V   -417.6mA   -447.5mA   -389.2mA
-1.073V   -360.2mA   -399.8mA   -343.9mA
-1V       -259mA     -308.9mA   -276.1mA
-927.3mV  -181.9mA   -224.8mA   -222.9mA
-818.2mV  -110mA     -117.7mA   -149.4mA
-709.1mV  -55.63mA   -44.94mA   -83.51mA
-563.6mV  -11.08mA   -7.285mA   -19.53mA
-490.9mV  -2.699mA   -1.926mA   -4.617mA
-381.8mV  -277uA     -254.4uA   -403uA
1.8V      5.734uA    8.877uA    5.605uA
[Ramp]
| variable   typ   min   max
dV/dt_f  1.0763724/0.14915738u 0.96425885/0.29718196u  1.1323133/96.532539n
dV/dt_r 0.47375472/2.3176401n 0.31789843/2.9389316n 0.57811462/1.8899628n
R_load = 528.00
[Rising Waveform]
R_fixture = 500
V_fixture = 1.8
V_fixture_min = 1.62
V_fixture_max = 1.89
|   time   V(typ)   V(min)   V(max)
0s        9.903mV    14.58mV    7.947mV
294.8ps   9.901mV    14.58mV    0V
1.136ns   3.005mV    14.58mV    915.6mV
2.079ns   821.6mV    14.58mV    1.392V
3.248ns   1.307V     48.6mV     1.674V
4.542ns   1.567V     811.2mV    1.802V
6.086ns   1.703V     1.221V     1.86V
8.098ns   1.768V     1.453V     1.881V
11.72ns   1.795V     1.58V      1.888V
5us       1.798V     1.618V     1.888V
[Rising Waveform]
R_fixture = 50
V_fixture = 1.8
V_fixture_min = 1.62
V_fixture_max = 1.89
|   time   V(typ)   V(min)   V(max)
0s        65.12mV    109.7mV    50.53mV
203.3ps   65.11mV    109.7mV    96.49mV
418.1ps   65.12mV    109.7mV    1.245V
804.4ps   63.3mV     109.7mV    1.702V
1.032ns   144.2mV    109.7mV    1.784V
1.244ns   1.15V      109.7mV    1.825V
1.559ns   1.557V     109.7mV    1.859V
2.994ns   1.783V     165mV      1.889V
3.615ns   1.794V     1.395V     1.89V
5us       1.8V       1.62V      1.89V
[Falling Waveform]
R_fixture = 500
V_fixture = 1.8
V_fixture_min = 1.62
V_fixture_max = 1.89
|   time   V(typ)   V(min)   V(max)
0s        1.798V     1.618V     1.888V
38.92ns   1.803V     1.621V     1.889V
66.49ns   1.797V     1.621V     1.762V
156.7ns   1.431V     1.609V     852.8mV
209ns     1.1V       1.56V      77.63mV
233ns     937.5mV    1.521V     18.76mV
345.3ns   50.49mV    1.247V     9.501mV
683.2ns   10.55mV    108.4mV    8.57mV
770.8ns   10.28mV    39.73mV    8.551mV
5us       9.903mV    14.59mV    8.535mV
[Falling Waveform]
R_fixture = 50
V_fixture = 1.8
V_fixture_min = 1.62
V_fixture_max = 1.89
|   time   V(typ)   V(min)   V(max)
0s        1.8V       1.62V      1.89V
78.39ns   1.797V     1.62V      1.766V
184.6ns   1.462V     1.614V     817.9mV
233.7ns   1.213V     1.594V     179.7mV
295.9ns   868.6mV    1.526V     65.85mV
383.4ns   251.9mV    1.383V     54.72mV
436.8ns   119.5mV    1.283V     52.74mV
866.5ns   66.96mV    322.4mV    50.32mV
1.062us   65.76mV    165.1mV    50.27mV
5us       65.12mV    109.9mV    50.26mV
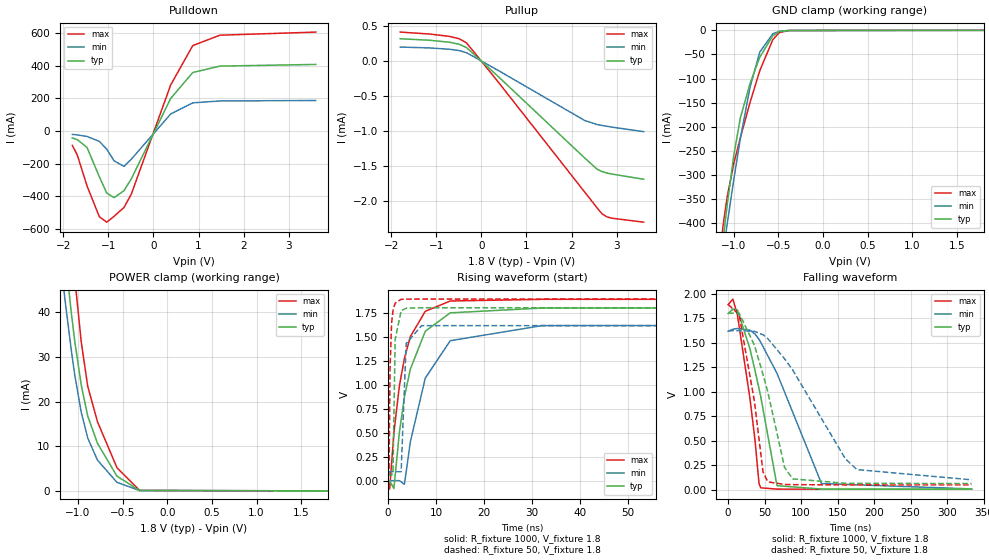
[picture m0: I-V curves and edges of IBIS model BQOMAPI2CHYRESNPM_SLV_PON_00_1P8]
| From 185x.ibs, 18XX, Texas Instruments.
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|   Model Cell BQOMAPI2CHYRESNPM_SLV_PON_00_1P8
|BQOMAPI2CHYRESNPM_SLV_PON_00_1P8
[Model]   BQOMAPI2CHYRESNPM_SLV_PON_00_1P8
Model_type   I/O
Polarity   Non-Inverting
Enable   Active-Low
Vinl =  0.54
Vinh =  1.26
Cref =  400.0000PF
Rref =  1000.0000
Vref =  1.8V
Vmeas =  0.9
C_comp   3.856143p   3.721565p   3.857354p
[Model Spec]
Vinl   0.54   0.486   0.567
Vinh   1.26   1.134   1.323
[Temperature Range]   25   125   -40
[Voltage Range]   1.8   1.62   1.89
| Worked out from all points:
|   slope of the pulldown table from 0 to 0.27 V, typ, clamps not added: 1.83 ohm
|   slope of the pullup table from 0 to 0.27 V, typ, clamps not added: 1.66 kohm
|   GND clamp passes 1 mA (typ) near -0.43 V on its own axis
|   POWER clamp passes 1 mA (typ) near -0.44 V on its own axis
|   rising waveform, R_fixture 1000, V_fixture 1.8: 20-80 % time 4.43ns typ, 5.56ns min, 3.72ns max; typ from 0.005 V to 1.8 V
|   rising waveform, R_fixture 50, V_fixture 1.8: 20-80 % time 348ps typ, 372ps min, 337ps max; typ from 0.062 V to 1.8 V
|   falling waveform, R_fixture 1000, V_fixture 1.8: 20-80 % time 29.5ns typ, 54.7ns min, 19.8ns max; typ from 1.8 V to 0.005 V
|   falling waveform, R_fixture 50, V_fixture 1.8: 20-80 % time 35.3ns typ, 74.7ns min, 22.2ns max; typ from 1.8 V to 0.062 V
| Nom Voltages:
|   BIASFET=1.8, VDDS=1.8, VDDU=1.2, BUS_VDD=0, VSS=0, VSSS=0
| Min Voltages:
|   BIASFET=1.62, VDDS=1.62, VDDU=1.08, BUS_VDD=0, VSS=0, VSSS=0
| Max Voltages:
|   BIASFET=1.89, VDDS=1.89, VDDU=1.32, BUS_VDD=0, VSS=0, VSSS=0
[POWER_clamp]
|   voltage   I(typ)   I(min)   I(max)
-1.8V     219.8mA    174.8mA    280.3mA
-1.218V   68.59mA    55.65mA    92.28mA
-1.182V   60.61mA    49.1mA     82.82mA
-1.145V   52.95mA    42.72mA    73.55mA
-1.073V   39.56mA    31.2mA     56.02mA
-1.036V   33.49mA    25.92mA    47.65mA
-963.6mV  23.72mA    17.61mA    33.37mA
-890.9mV  16.76mA    11.84mA    23.42mA
-781.8mV  10.67mA    6.886mA    15.5mA
-563.6mV  3.296mA    1.922mA    5.2mA
-309.1mV  100.1uA    71.54uA    112.3uA
1.8V      -2.406uA   -6.294uA   -2.119uA
[Pulldown]
|   voltage   I(typ)   I(min)   I(max)
-1.8V     -42.94mA   -21.31mA   -88.47mA
-1.691V   -53.19mA   -24.31mA   -146.9mA
-1.473V   -101.6mA   -33.88mA   -337.8mA
-1.2V     -281.8mA   -64.16mA   -526.8mA
-1.036V   -381.2mA   -112.1mA   -559.9mA
-872.7mV  -409.1mA   -183.5mA   -523.3mA
-654.5mV  -366.6mA   -217.4mA   -469.9mA
-490.9mV  -293.7mA   -173.1mA   -387.2mA
381.8mV   199.5mA    104mA      282mA
872.7mV   358.7mA    172.4mA    524mA
1.473V    397.9mA    183.9mA    587.5mA
3.6V      408.1mA    186.9mA    606.6mA
[Pullup]
|   voltage   I(typ)   I(min)   I(max)
-1.8V     313.7uA    195.7uA    408.9uA
-1.145V   292.3uA    182.6uA    381.1uA
-709.1mV  264.1uA    164.2uA    347.5uA
-490.9mV  235.4uA    145uA      314.1uA
-327.3mV  186.8uA    114.4uA    253.6uA
381.8mV   -229.5uA   -141.2uA   -309.4uA
2.291V    -1.386mA   -851.4uA   -1.872mA
2.564V    -1.545mA   -908.6uA   -2.095mA
2.673V    -1.58mA    -922.2uA   -2.181mA
2.782V    -1.6mA     -934.4uA   -2.225mA
2.891V    -1.615mA   -945.8uA   -2.245mA
3.6V      -1.69mA    -1.011mA   -2.302mA
[GND_clamp]
|   voltage   I(typ)   I(min)   I(max)
-1.8V     -1.732A    -1.456A    -1.797A
-1.145V   -477.7mA   -496.1mA   -441.1mA
-1.109V   -417.6mA   -447.5mA   -389.2mA
-1.073V   -360.2mA   -399.8mA   -343.9mA
-1V       -259mA     -308.9mA   -276mA
-927.3mV  -181.9mA   -224.8mA   -222.9mA
-818.2mV  -110mA     -117.7mA   -149.4mA
-709.1mV  -55.63mA   -44.94mA   -83.51mA
-563.6mV  -11.08mA   -7.285mA   -19.53mA
-490.9mV  -2.699mA   -1.926mA   -4.617mA
-381.8mV  -277uA     -254.4uA   -403uA
1.8V      5.734uA    8.877uA    5.605uA
[Ramp]
| variable   typ   min   max
dV/dt_f  1.0930366/30.856495n 0.97440324/57.586869n  1.1542928/20.683486n
dV/dt_r 0.34939998/3.5131149n 0.23976122/4.3201751n 0.42387781/2.4067401n
R_load = 528.0
[Rising Waveform]
R_fixture = 1000
V_fixture = 1.8
V_fixture_min = 1.62
V_fixture_max = 1.89
|   time   V(typ)   V(min)   V(max)
0s        4.894mV    6.883mV    3.664mV
331.9ps   4.892mV    6.883mV    -81.51mV
1.218ns   -75.69mV   6.882mV    503.1mV
2.363ns   509.5mV    6.971mV    990.8mV
3.411ns   876.2mV    -31.09mV   1.274V
4.654ns   1.164V     410.4mV    1.501V
7.761ns   1.556V     1.07V      1.763V
12.98ns   1.747V     1.458V     1.87V
32.16ns   1.797V     1.615V     1.887V
333.4ns   1.796V     1.616V     1.887V
[Rising Waveform]
R_fixture = 50
V_fixture = 1.8
V_fixture_min = 1.62
V_fixture_max = 1.89
|   time   V(typ)   V(min)   V(max)
0s        61.73mV    99.71mV    47.73mV
211ps     61.73mV    99.71mV    88.11mV
409.3ps   61.73mV    99.71mV    1.168V
741.8ps   61.4mV     99.71mV    1.648V
1.045ns   119.7mV    99.71mV    1.777V
1.474ns   1.469V     99.71mV    1.848V
2.724ns   1.769V     99.48mV    1.887V
3.775ns   1.795V     1.428V     1.889V
6.985ns   1.8V       1.614V     1.89V
333.5ns   1.8V       1.62V      1.89V
[Falling Waveform]
R_fixture = 1000
V_fixture = 1.8
V_fixture_min = 1.62
V_fixture_max = 1.89
|   time   V(typ)   V(min)   V(max)
0s        1.796V     1.616V     1.887V
6.48ns    1.842V     1.636V     1.944V
12.66ns   1.834V     1.644V     1.784V
29.99ns   1.433V     1.626V     922.3mV
36.83ns   1.213V     1.587V     501.7mV
42.28ns   1.031V     1.533V     61.93mV
44.57ns   951.1mV    1.504V     17.98mV
66.93ns   39.88mV    1.186V     4.878mV
127.9ns   5.332mV    61.35mV    4.276mV
333.4ns   4.894mV    6.883mV    4.244mV
[Falling Waveform]
R_fixture = 50
V_fixture = 1.8
V_fixture_min = 1.62
V_fixture_max = 1.89
|   time   V(typ)   V(min)   V(max)
0s        1.8V       1.62V      1.89V
15.07ns   1.8V       1.622V     1.783V
35.87ns   1.476V     1.615V     906mV
47.79ns   1.174V     1.58V      180.1mV
54.32ns   996.3mV    1.54V      78.79mV
77.28ns   226.2mV    1.335V     52.47mV
88.4ns    109.2mV    1.22V      50.41mV
160.5ns   64.28mV    315.1mV    47.98mV
176.4ns   63.36mV    203.9mV    47.92mV
333.5ns   61.73mV    99.71mV    47.88mV
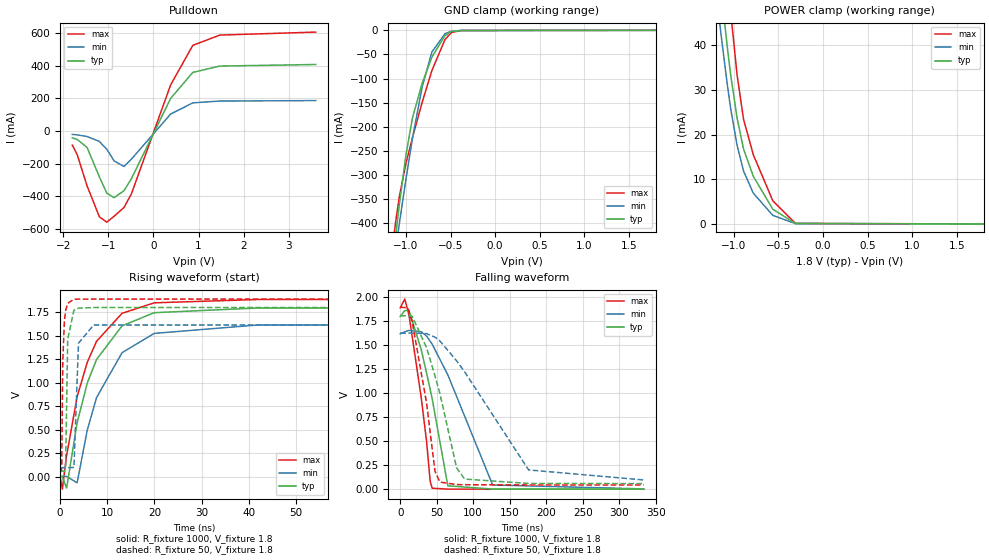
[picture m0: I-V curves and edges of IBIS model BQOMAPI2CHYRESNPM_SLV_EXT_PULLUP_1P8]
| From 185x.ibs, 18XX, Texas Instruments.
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|   Model Cell BQOMAPI2CHYRESNPM_SLV_EXT_PULLUP_1P8
|BQOMAPI2CHYRESNPM_SLV_EXT_PULLUP_1P8
[Model]   BQOMAPI2CHYRESNPM_SLV_EXT_PULLUP_1P8
Model_type   I/O_open_drain
Polarity   Non-Inverting
Enable   Active-Low
Vinl =  0.54
Vinh =  1.26
Cref =  400.0000PF
Rref =  1000.0000
Vref =  1.8V
Vmeas =  0.9
C_comp   3.856143p   3.721565p   3.857354p
[Model Spec]
Vinl   0.54   0.486   0.567
Vinh   1.26   1.134   1.323
[Temperature Range]   25   125   -40
[Voltage Range]   1.8   1.62   1.89
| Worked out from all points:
|   slope of the pulldown table from 0 to 0.27 V, typ, clamps not added: 1.83 ohm
|   GND clamp passes 1 mA (typ) near -0.43 V on its own axis
|   POWER clamp passes 1 mA (typ) near -0.44 V on its own axis
|   rising waveform, R_fixture 1000, V_fixture 1.8: 20-80 % time 7.05ns typ, 7.59ns min, 6.69ns max; typ from 0.003 V to 1.79 V
|   rising waveform, R_fixture 50, V_fixture 1.8: 20-80 % time 364ps typ, 382ps min, 355ps max; typ from 0.06 V to 1.8 V
|   falling waveform, R_fixture 1000, V_fixture 1.8: 20-80 % time 28.9ns typ, 53.5ns min, 19.4ns max; typ from 1.79 V to 0.003 V
|   falling waveform, R_fixture 50, V_fixture 1.8: 20-80 % time 35.3ns typ, 74.4ns min, 22.2ns max; typ from 1.8 V to 0.06 V
| Nom Voltages:
|   BIASFET=1.8, VDDS=1.8, VDDU=1.2, BUS_VDD=0, VSS=0, VSSS=0
| Min Voltages:
|   BIASFET=1.62, VDDS=1.62, VDDU=1.08, BUS_VDD=0, VSS=0, VSSS=0
| Max Voltages:
|   BIASFET=1.89, VDDS=1.89, VDDU=1.32, BUS_VDD=0, VSS=0, VSSS=0
[POWER_clamp]
|   voltage   I(typ)   I(min)   I(max)
-1.8V     219.8mA    174.8mA    280.3mA
-1.218V   68.59mA    55.65mA    92.28mA
-1.182V   60.61mA    49.1mA     82.82mA
-1.145V   52.95mA    42.72mA    73.55mA
-1.073V   39.56mA    31.2mA     56.02mA
-1.036V   33.49mA    25.92mA    47.65mA
-963.6mV  23.72mA    17.61mA    33.37mA
-890.9mV  16.76mA    11.84mA    23.42mA
-781.8mV  10.67mA    6.886mA    15.5mA
-563.6mV  3.296mA    1.922mA    5.2mA
-309.1mV  100.1uA    71.54uA    112.3uA
1.8V      -2.406uA   -6.294uA   -2.119uA
[Pulldown]
|   voltage   I(typ)   I(min)   I(max)
-1.8V     -41.25mA   -20.32mA   -86.16mA
-1.691V   -51.51mA   -23.33mA   -144.6mA
-1.473V   -99.94mA   -32.91mA   -335.5mA
-1.2V     -280.2mA   -63.22mA   -524.6mA
-1.036V   -379.6mA   -111.1mA   -557.7mA
-872.7mV  -407.5mA   -182.6mA   -521.1mA
-654.5mV  -365.1mA   -216.6mA   -467.8mA
-490.9mV  -292.3mA   -172.3mA   -385.3mA
381.8mV   200.4mA    104.5mA    283.2mA
872.7mV   359.2mA    172.7mA    524.8mA
1.473V    398.1mA    184mA      587.8mA
3.6V      407.7mA    186.7mA    606.1mA
[GND_clamp]
|   voltage   I(typ)   I(min)   I(max)
-1.8V     -1.732A    -1.456A    -1.797A
-1.145V   -477.7mA   -496.1mA   -441.1mA
-1.109V   -417.6mA   -447.5mA   -389.2mA
-1.073V   -360.2mA   -399.8mA   -343.9mA
-1V       -259mA     -308.9mA   -276mA
-927.3mV  -181.9mA   -224.8mA   -222.9mA
-818.2mV  -110mA     -117.7mA   -149.4mA
-709.1mV  -55.63mA   -44.94mA   -83.51mA
-563.6mV  -11.08mA   -7.285mA   -19.53mA
-490.9mV  -2.699mA   -1.926mA   -4.617mA
-381.8mV  -277uA     -254.4uA   -403uA
1.8V      5.734uA    8.877uA    5.605uA
[Ramp]
| variable   typ   min   max
dV/dt_f  1.0990664/30.598421n 0.97724765/56.906674n  1.1639693/20.648906n
dV/dt_r 0.12831179/0.11277173n  0.1180365/0.23402154n 0.12092629/69.357885p
R_load = 528.0
[Rising Waveform]
R_fixture = 1000
V_fixture = 1.8
V_fixture_min = 1.62
V_fixture_max = 1.89
|   time   V(typ)   V(min)   V(max)
0s        3.053mV    5.022mV    0V
459.9ps   3.051mV    5.022mV    -130.7mV
1.371ns   -119.3mV   5.021mV    226.9mV
3.6ns     575.9mV    -63.8mV    852.1mV
5.753ns   997.2mV    497mV      1.218V
7.716ns   1.248V     842.6mV    1.441V
13.13ns   1.605V     1.32V      1.739V
19.95ns   1.745V     1.525V     1.85V
41.79ns   1.795V     1.614V     1.885V
333.5ns   1.794V     1.615V     1.884V
[Rising Waveform]
R_fixture = 50
V_fixture = 1.8
V_fixture_min = 1.62
V_fixture_max = 1.89
|   time   V(typ)   V(min)   V(max)
0s        59.95mV    97.94mV    46.03mV
325.5ps   59.95mV    97.94mV    83.25mV
553.7ps   59.95mV    97.94mV    1.219V
904.4ps   58.38mV    97.94mV    1.661V
1.16ns    115.1mV    97.94mV    1.767V
1.602ns   1.464V     97.94mV    1.845V
2.918ns   1.771V     99.78mV    1.888V
3.89ns    1.794V     1.421V     1.889V
7.098ns   1.8V       1.614V     1.89V
333.4ns   1.8V       1.62V      1.89V
[Falling Waveform]
R_fixture = 1000
V_fixture = 1.8
V_fixture_min = 1.62
V_fixture_max = 1.89
|   time   V(typ)   V(min)   V(max)
0s        1.794V     1.615V     1.884V
6.193ns   1.855V     1.636V     1.975V
12.02ns   1.858V     1.65V      1.809V
28.76ns   1.45V      1.636V     951.8mV
36.21ns   1.204V     1.59V      488.2mV
41.03ns   1.037V     1.537V     84.58mV
43.72ns   942.2mV    1.507V     12.07mV
65.17ns   37.29mV    1.189V     2.745mV
126.6ns   3.34mV     45.78mV    2.36mV
333.5ns   3.053mV    5.022mV    2.34mV
[Falling Waveform]
R_fixture = 50
V_fixture = 1.8
V_fixture_min = 1.62
V_fixture_max = 1.89
|   time   V(typ)   V(min)   V(max)
0s        1.8V       1.62V      1.89V
10.09ns   1.803V     1.622V     1.885V
16.33ns   1.797V     1.622V     1.743V
36.03ns   1.472V     1.616V     898.7mV
47.6ns    1.178V     1.58V      187.2mV
54.37ns   993.8mV    1.54V      76.02mV
77.19ns   224.5mV    1.335V     50.48mV
88.15ns   107.2mV    1.221V     48.5mV
175.9ns   61.56mV    201.8mV    46.08mV
333.4ns   59.95mV    97.94mV    46.03mV
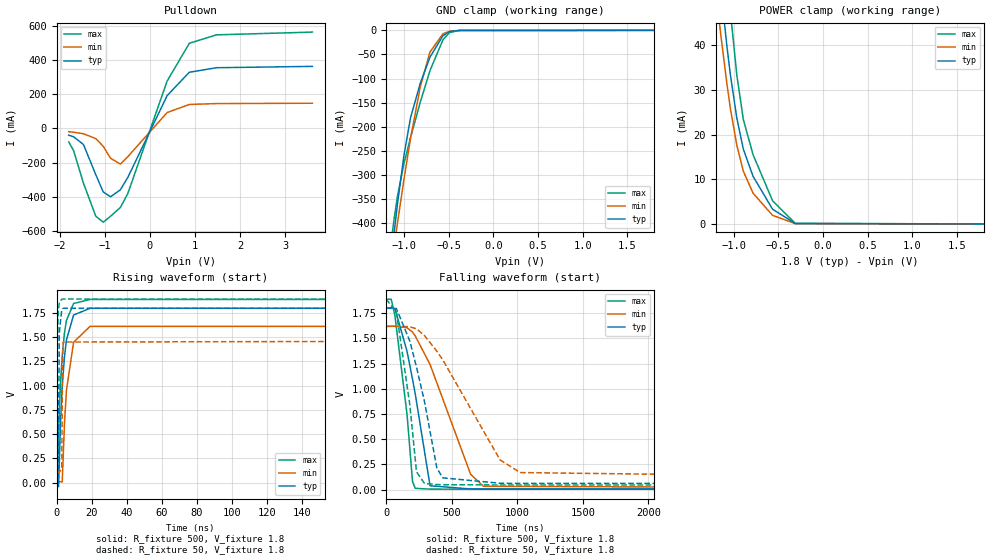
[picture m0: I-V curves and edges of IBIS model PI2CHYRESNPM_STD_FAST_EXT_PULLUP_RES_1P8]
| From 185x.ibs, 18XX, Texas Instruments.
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|   Model Cell PI2CHYRESNPM_STD_FAST_EXT_PULLUP_RES_1P8
|BQOMAPI2CHYRESNPM_STD_FAST_EXT_PULLUP_RES_1P8
[Model]   PI2CHYRESNPM_STD_FAST_EXT_PULLUP_RES_1P8
Model_type   I/O_open_drain
Polarity   Non-Inverting
Enable   Active-Low
Vinl =  0.54
Vinh =  1.26
Cref =  400.0000PF
Rref =  500.0000
Vref =  1.8V
Vmeas =  0.9
C_comp   3.856143p   3.721565p   3.857354p
[Model Spec]
Vinl   0.54   0.486   0.567
Vinh   1.26   1.134   1.323
[Temperature Range]   25   125   -40
[Voltage Range]   1.8   1.62   1.89
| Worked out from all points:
|   slope of the pulldown table from 0 to 0.27 V, typ, clamps not added: 1.9 ohm
|   GND clamp passes 1 mA (typ) near -0.43 V on its own axis
|   POWER clamp passes 1 mA (typ) near -0.44 V on its own axis
|   rising waveform, R_fixture 500, V_fixture 1.8: 20-80 % time 3.62ns typ, 3.91ns min, 3.41ns max; typ from 0.006 V to 1.8 V
|   rising waveform, R_fixture 50, V_fixture 1.8: 20-80 % time 366ps typ, 384ps min, 354ps max; typ from 0.062 V to 1.8 V
|   falling waveform, R_fixture 500, V_fixture 1.8: 20-80 % time 145ns typ, 288ns min, 94.3ns max; typ from 1.8 V to 0.006 V
|   falling waveform, R_fixture 50, V_fixture 1.8: 20-80 % time 174ns typ, 402ns min, 106ns max; typ from 1.8 V to 0.062 V
| Nom Voltages:
|   BIASFET=1.8, VDDS=1.8, VDDU=1.2, BUS_VDD=0, VSS=0, VSSS=0
| Min Voltages:
|   BIASFET=1.62, VDDS=1.62, VDDU=1.08, BUS_VDD=0, VSS=0, VSSS=0
| Max Voltages:
|   BIASFET=1.89, VDDS=1.89, VDDU=1.32, BUS_VDD=0, VSS=0, VSSS=0
[POWER_clamp]
|   voltage   I(typ)   I(min)   I(max)
-1.8V     219.8mA    174.8mA    280.3mA
-1.218V   68.59mA    55.65mA    92.28mA
-1.182V   60.61mA    49.1mA     82.82mA
-1.145V   52.95mA    42.72mA    73.55mA
-1.073V   39.56mA    31.2mA     56.02mA
-1.036V   33.49mA    25.92mA    47.65mA
-963.6mV  23.72mA    17.61mA    33.37mA
-890.9mV  16.76mA    11.84mA    23.42mA
-781.8mV  10.67mA    6.886mA    15.5mA
-563.6mV  3.296mA    1.922mA    5.2mA
-309.1mV  100.1uA    71.54uA    112.3uA
1.8V      -2.406uA   -6.294uA   -2.119uA
[Pulldown]
|   voltage   I(typ)   I(min)   I(max)
-1.8V     -39.53mA   -19.37mA   -79.02mA
-1.691V   -49.18mA   -22.21mA   -130mA
-1.473V   -94.04mA   -31.23mA   -320.7mA
-1.2V     -271.1mA   -59.49mA   -513.7mA
-1.036V   -371.2mA   -104.4mA   -548.7mA
-872.7mV  -400mA     -174.2mA   -513.8mA
-654.5mV  -358.9mA   -208.8mA   -462.5mA
-490.9mV  -287.1mA   -165.6mA   -381.3mA
381.8mV   192.1mA    93.15mA    277.6mA
872.7mV   328.8mA    140.2mA    498.1mA
1.473V    355.2mA    145.4mA    547.5mA
3.6V      363.1mA    147.4mA    563.7mA
[GND_clamp]
|   voltage   I(typ)   I(min)   I(max)
-1.8V     -1.732A    -1.456A    -1.797A
-1.145V   -477.7mA   -496.1mA   -441.1mA
-1.109V   -417.6mA   -447.5mA   -389.2mA
-1.073V   -360.2mA   -399.8mA   -343.9mA
-1V       -259mA     -308.9mA   -276.1mA
-927.3mV  -181.9mA   -224.8mA   -222.9mA
-818.2mV  -110mA     -117.7mA   -149.4mA
-709.1mV  -55.63mA   -44.94mA   -83.51mA
-563.6mV  -11.08mA   -7.285mA   -19.53mA
-490.9mV  -2.699mA   -1.926mA   -4.617mA
-381.8mV  -277uA     -254.4uA   -403uA
1.8V      5.734uA    8.877uA    5.605uA
[Ramp]
| variable   typ   min   max
dV/dt_f  1.0798885/0.14578998u 0.96679074/0.28786213u  1.1374204/95.167159n
dV/dt_r 0.12445843/0.12240501n 0.11489804/0.2394155n 0.11609134/75.902177p
R_load = 528.00
[Rising Waveform]
R_fixture = 500
V_fixture = 1.8
V_fixture_min = 1.62
V_fixture_max = 1.89
|   time   V(typ)   V(min)   V(max)
0s        6.252mV    10.78mV    4.138mV
315.3ps   6.25mV     10.78mV    -66.32mV
1.192ns   -40.86mV   10.78mV    550.7mV
2.23ns    592.4mV    10.81mV    1.017V
3.251ns   987mV      7.593mV    1.307V
4.508ns   1.29V      599.1mV    1.538V
5.674ns   1.471V     953.3mV    1.671V
9.742ns   1.726V     1.446V     1.844V
19.12ns   1.795V     1.609V     1.886V
5us       1.797V     1.617V     1.887V
[Rising Waveform]
R_fixture = 50
V_fixture = 1.8
V_fixture_min = 1.62
V_fixture_max = 1.89
|   time   V(typ)   V(min)   V(max)
0s        61.57mV    106mV      45.9mV
203.3ps   61.57mV    106mV      86.47mV
436.5ps   61.57mV    106mV      1.232V
849ps     59.38mV    106mV      1.697V
1.032ns   133.6mV    106mV      1.766V
1.58ns    1.544V     106mV      1.854V
2.994ns   1.78V      158.6mV    1.889V
3.393ns   1.79V      1.169V     1.889V
3.792ns   1.795V     1.448V     1.89V
5us       1.8V       1.62V      1.89V
[Falling Waveform]
R_fixture = 500
V_fixture = 1.8
V_fixture_min = 1.62
V_fixture_max = 1.89
|   time   V(typ)   V(min)   V(max)
0s        1.797V     1.617V     1.887V
38.58ns   1.805V     1.621V     1.889V
67.15ns   1.795V     1.621V     1.727V
159.8ns   1.37V      1.605V     742.7mV
201.5ns   1.094V     1.562V     79.02mV
222.1ns   950.1mV    1.524V     13.11mV
334.9ns   38.6mV     1.242V     5.32mV
644.4ns   6.75mV     152.2mV    4.75mV
741.6ns   6.526mV    33.32mV    4.735mV
5us       6.252mV    10.79mV    4.724mV
[Falling Waveform]
R_fixture = 50
V_fixture = 1.8
V_fixture_min = 1.62
V_fixture_max = 1.89
|   time   V(typ)   V(min)   V(max)
0s        1.8V       1.62V      1.89V
78.23ns   1.796V     1.62V      1.763V
180.8ns   1.474V     1.615V     841.4mV
231.7ns   1.215V     1.595V     177mV
292.4ns   875.8mV    1.528V     61.7mV
386.8ns   215.4mV    1.373V     50.42mV
431.1ns   117mV      1.289V     48.94mV
868.7ns   63.28mV    295.1mV    46.6mV
1.022us   62.3mV     169.3mV    46.57mV
5us       61.57mV    106.2mV    46.56mV
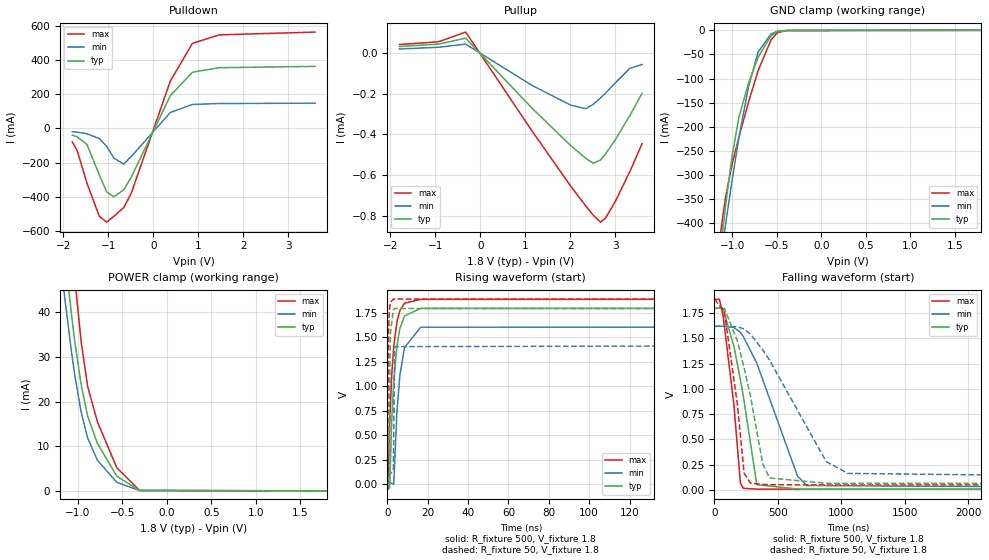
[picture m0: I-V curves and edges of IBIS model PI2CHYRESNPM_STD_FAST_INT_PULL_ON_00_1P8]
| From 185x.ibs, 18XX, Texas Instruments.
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|   Model Cell PI2CHYRESNPM_STD_FAST_INT_PULL_ON_00_1P8
|BQOMAPI2CHYRESNPM_STD_FAST_INT_PULL_ON_00_1P8
[Model]   PI2CHYRESNPM_STD_FAST_INT_PULL_ON_00_1P8
Model_type   I/O
Polarity   Non-Inverting
Enable   Active-Low
Vinl =  0.54
Vinh =  1.26
Cref =  400.0000PF
Rref =  500.0000
Vref =  1.8V
Vmeas =  0.9
C_comp   3.856143p   3.721565p   3.857354p
[Model Spec]
Vinl   0.54   0.486   0.567
Vinh   1.26   1.134   1.323
[Temperature Range]   25   125   -40
[Voltage Range]   1.8   1.62   1.89
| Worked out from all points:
|   slope of the pulldown table from 0 to 0.27 V, typ, clamps not added: 1.9 ohm
|   slope of the pullup table from 0 to 0.27 V, typ, clamps not added: 4.14 kohm
|   GND clamp passes 1 mA (typ) near -0.43 V on its own axis
|   POWER clamp passes 1 mA (typ) near -0.44 V on its own axis
|   rising waveform, R_fixture 500, V_fixture 1.8: 20-80 % time 3.22ns typ, 3.63ns min, 2.91ns max; typ from 0.007 V to 1.8 V
|   rising waveform, R_fixture 50, V_fixture 1.8: 20-80 % time 358ps typ, 378ps min, 345ps max; typ from 0.062 V to 1.8 V
|   falling waveform, R_fixture 500, V_fixture 1.8: 20-80 % time 146ns typ, 290ns min, 94.9ns max; typ from 1.8 V to 0.007 V
|   falling waveform, R_fixture 50, V_fixture 1.8: 20-80 % time 174ns typ, 403ns min, 106ns max; typ from 1.8 V to 0.062 V
| Nom Voltages:
|   BIASFET=1.8, VDDS=1.8, VDDU=1.2, BUS_VDD=0, VSS=0, VSSS=0
| Min Voltages:
|   BIASFET=1.62, VDDS=1.62, VDDU=1.08, BUS_VDD=0, VSS=0, VSSS=0
| Max Voltages:
|   BIASFET=1.89, VDDS=1.89, VDDU=1.32, BUS_VDD=0, VSS=0, VSSS=0
[POWER_clamp]
|   voltage   I(typ)   I(min)   I(max)
-1.8V     219.8mA    174.8mA    280.3mA
-1.218V   68.59mA    55.65mA    92.28mA
-1.182V   60.61mA    49.1mA     82.82mA
-1.145V   52.95mA    42.72mA    73.55mA
-1.073V   39.56mA    31.2mA     56.02mA
-1.036V   33.49mA    25.92mA    47.65mA
-963.6mV  23.72mA    17.61mA    33.37mA
-890.9mV  16.76mA    11.84mA    23.42mA
-781.8mV  10.67mA    6.886mA    15.5mA
-563.6mV  3.296mA    1.922mA    5.2mA
-309.1mV  100.1uA    71.54uA    112.3uA
1.8V      -2.406uA   -6.294uA   -2.119uA
[Pulldown]
|   voltage   I(typ)   I(min)   I(max)
-1.8V     -39.73mA   -19.43mA   -79.42mA
-1.691V   -49.43mA   -22.29mA   -130.4mA
-1.473V   -94.37mA   -31.36mA   -321.3mA
-1.2V     -271.5mA   -59.68mA   -514.4mA
-1.036V   -371.7mA   -104.7mA   -549.4mA
-872.7mV  -400.6mA   -174.5mA   -514.6mA
-654.5mV  -359.4mA   -209.1mA   -463.3mA
-490.9mV  -287.6mA   -165.8mA   -382.1mA
381.8mV   191.8mA    92.98mA    277.1mA
872.7mV   328.6mA    140.1mA    497.8mA
1.473V    355.2mA    145.4mA    547.4mA
3.6V      363.1mA    147.5mA    563.7mA
[Pullup]
|   voltage   I(typ)   I(min)   I(max)
-1.8V     31.44uA    19.17uA    41.21uA
-927.3mV  43.37uA    27.74uA    54.81uA
-327.3mV  72.36uA    43.24uA    102.3uA
1.145V    -270.7uA   -159.2uA   -382.3uA
2.018V    -457.4uA   -257.5uA   -657.4uA
2.345V    -517.9uA   -274.2uA   -752.5uA
2.509V    -542.7uA   -253.2uA   -797.1uA
2.673V    -526.7uA   -221.7uA   -832.2uA
2.782V    -497.7uA   -198.3uA   -812.9uA
3V        -427.7uA   -147.9uA   -731.5uA
3.327V    -307.3uA   -75.6uA    -582.9uA
3.6V      -198.1uA   -56.9uA    -445.3uA
[GND_clamp]
|   voltage   I(typ)   I(min)   I(max)
-1.8V     -1.732A    -1.456A    -1.797A
-1.145V   -477.7mA   -496.1mA   -441.1mA
-1.109V   -417.6mA   -447.5mA   -389.2mA
-1.073V   -360.2mA   -399.8mA   -343.9mA
-1V       -259mA     -308.9mA   -276.1mA
-927.3mV  -181.9mA   -224.8mA   -222.9mA
-818.2mV  -110mA     -117.7mA   -149.4mA
-709.1mV  -55.63mA   -44.94mA   -83.51mA
-563.6mV  -11.08mA   -7.285mA   -19.53mA
-490.9mV  -2.699mA   -1.926mA   -4.617mA
-381.8mV  -277uA     -254.4uA   -403uA
1.8V      5.734uA    8.877uA    5.605uA
[Ramp]
| variable   typ   min   max
dV/dt_f  1.0790844/0.14649497u 0.96630759/0.28950378u  1.1360574/95.432022n
dV/dt_r 0.22493055/4.1188484n 0.16474239/4.7806222n 0.26681073/3.591013n
R_load = 528.00
[Rising Waveform]
R_fixture = 500
V_fixture = 1.8
V_fixture_min = 1.62
V_fixture_max = 1.89
|   time   V(typ)   V(min)   V(max)
0s        6.968mV    11.5mV     4.909mV
315.4ps   6.967mV    11.5mV     -48mV
1.161ns   -36.41mV   11.5mV     629.5mV
2.233ns   667.4mV    11.53mV    1.127V
3.185ns   1.05V      3.129mV    1.404V
4.777ns   1.414V     743.5mV    1.66V
6.243ns   1.591V     1.115V     1.773V
8.521ns   1.717V     1.395V     1.848V
16.53ns   1.795V     1.603V     1.887V
5us       1.797V     1.618V     1.887V
[Rising Waveform]
R_fixture = 50
V_fixture = 1.8
V_fixture_min = 1.62
V_fixture_max = 1.89
|   time   V(typ)   V(min)   V(max)
0s        62.26mV    106.7mV    46.84mV
203.3ps   62.26mV    106.7mV    88.45mV
425.7ps   62.27mV    106.7mV    1.219V
802.4ps   60.43mV    106.7mV    1.681V
1.032ns   135.7mV    106.7mV    1.771V
1.261ns   1.161V     106.7mV    1.819V
1.577ns   1.549V     106.7mV    1.856V
2.994ns   1.781V     159.8mV    1.889V
3.657ns   1.794V     1.405V     1.89V
5us       1.8V       1.62V      1.89V
[Falling Waveform]
R_fixture = 500
V_fixture = 1.8
V_fixture_min = 1.62
V_fixture_max = 1.89
|   time   V(typ)   V(min)   V(max)
0s        1.797V     1.618V     1.887V
38.69ns   1.804V     1.621V     1.889V
67.49ns   1.795V     1.621V     1.732V
153.8ns   1.417V     1.608V     834.5mV
204.2ns   1.09V      1.56V      69.98mV
226.4ns   935.8mV    1.52V      13.56mV
333.4ns   49.5mV     1.254V     6.199mV
654ns     7.504mV    134.3mV    5.523mV
726.1ns   7.304mV    41.48mV    5.51mV
5us       6.968mV    11.51mV    5.495mV
[Falling Waveform]
R_fixture = 50
V_fixture = 1.8
V_fixture_min = 1.62
V_fixture_max = 1.89
|   time   V(typ)   V(min)   V(max)
0s        1.8V       1.62V      1.89V
78.25ns   1.797V     1.62V      1.764V
180.6ns   1.476V     1.615V     846.5mV
233.5ns   1.207V     1.594V     165.3mV
282.8ns   933.6mV    1.542V     66.2mV
379.8ns   258.3mV    1.387V     51.71mV
433.6ns   116.2mV    1.285V     49.77mV
879.5ns   63.89mV    279.6mV    47.35mV
1.051us   62.91mV    161.7mV    47.32mV
5us       62.26mV    106.9mV    47.31mV
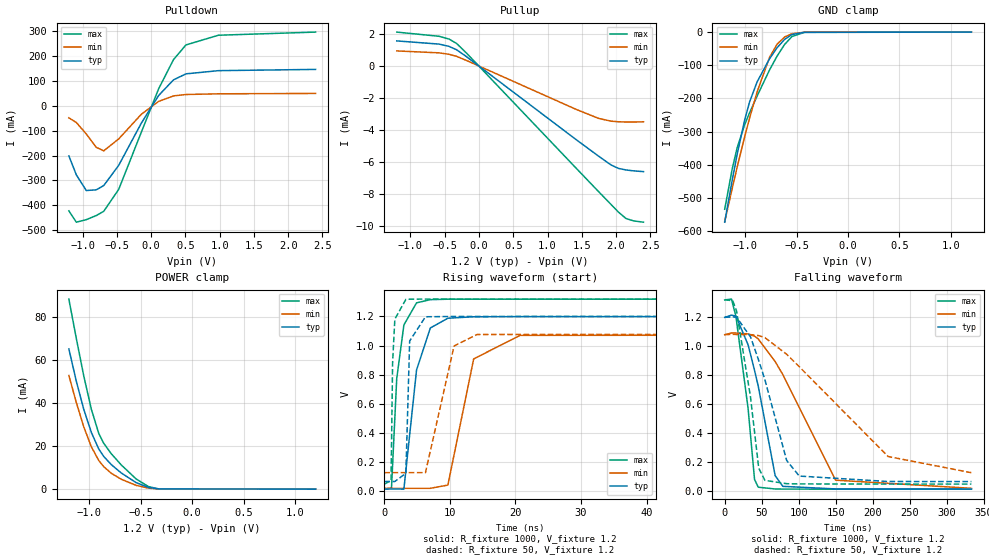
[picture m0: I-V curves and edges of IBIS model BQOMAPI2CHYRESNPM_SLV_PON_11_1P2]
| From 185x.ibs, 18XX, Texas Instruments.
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|   Model Cell BQOMAPI2CHYRESNPM_SLV_PON_11_1P2
|BQOMAPI2CHYRESNPM_SLV_PON_11_1P2
[Model]   BQOMAPI2CHYRESNPM_SLV_PON_11_1P2
Model_type   I/O
Polarity   Non-Inverting
Enable   Active-Low
Vinl =  0.36
Vinh =  0.84
Cref =  400.0000PF
Rref =  1000.0000
Vref =  1.8V
Vmeas =  0.6
C_comp   3.806929p   3.71689p   3.834943p
[Model Spec]
Vinl   0.36   0.324   0.396
Vinh   0.84   0.756   0.924
[Temperature Range]   25   125   -40
[Voltage Range]   1.2   1.08   1.32
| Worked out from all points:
|   slope of the pulldown table from 0 to 0.18 V, typ, clamps not added: 2.61 ohm
|   slope of the pullup table from 0 to 0.18 V, typ, clamps not added: 306 ohm
|   GND clamp passes 1 mA (typ) near -0.45 V on its own axis
|   POWER clamp passes 1 mA (typ) near -0.44 V on its own axis
|   rising waveform, R_fixture 1000, V_fixture 1.2: 20-80 % time 1.78ns typ, 2.93ns min, 1.28ns max; typ from 0.012 V to 1.2 V
|   rising waveform, R_fixture 50, V_fixture 1.2: 20-80 % time 354ps typ, 677ps min, 300ps max; typ from 0.063 V to 1.2 V
|   falling waveform, R_fixture 1000, V_fixture 1.2: 20-80 % time 29.1ns typ, 60.9ns min, 17.2ns max; typ from 1.2 V to 0.012 V
|   falling waveform, R_fixture 50, V_fixture 1.2: 20-80 % time 37.9ns typ, 106ns min, 20ns max; typ from 1.2 V to 0.063 V
| Nom Voltages:
|   BIASFET=1.2, VDDS=1.2, VDDU=1.2, BUS_VDD=0, VSS=0, VSSS=0
| Min Voltages:
|   BIASFET=1.08, VDDS=1.08, VDDU=1.08, BUS_VDD=0, VSS=0, VSSS=0
| Max Voltages:
|   BIASFET=1.32, VDDS=1.32, VDDU=1.32, BUS_VDD=0, VSS=0, VSSS=0
[POWER_clamp]
|   voltage   I(typ)   I(min)   I(max)
-1.2V     64.99mA    52.68mA    88.09mA
-1.127V   49.93mA    40.08mA    69.72mA
-1.055V   36.97mA    28.84mA    52.47mA
-981.8mV  26.35mA    19.7mA     37.12mA
-909.1mV  18.6mA     13.27mA    25.8mA
-860.6mV  15.16mA    10.42mA    21.24mA
-787.9mV  11.4mA     7.386mA    16.45mA
-690.9mV  7.53mA     4.603mA    11.25mA
-545.5mV  3.018mA    1.76mA     4.721mA
-424.2mV  769.6uA    464.5uA    1.162mA
-327.3mV  128.4uA    90.42uA    147.3uA
1.2V      -1.911uA   -2.519uA   -1.532uA
[Pulldown]
|   voltage   I(typ)   I(min)   I(max)
-1.2V     -201.5mA   -48.71mA   -421.8mA
-1.091V   -277.4mA   -67.63mA   -467.2mA
-945.5mV  -340.3mA   -113.5mA   -457mA
-800mV    -337.4mA   -167.1mA   -440.6mA
-690.9mV  -320.3mA   -181.1mA   -423.5mA
-472.7mV  -239.3mA   -133.4mA   -335.6mA
-145.5mV  -71.53mA   -35.41mA   -108.5mA
109.1mV   40.5mA     16.89mA    67.05mA
327.3mV   103.5mA    39.1mA     184.8mA
509.1mV   127.5mA    44.69mA    243.5mA
981.8mV   140.3mA    47.43mA    282.3mA
2.4V      145.3mA    49mA       294.9mA
[Pullup]
|   voltage   I(typ)   I(min)   I(max)
-1.2V     1.578mA    953.2uA    2.128mA
-581.8mV  1.378mA    832.2uA    1.865mA
-436.4mV  1.235mA    741.5uA    1.691mA
-327.3mV  1.026mA    614.6uA    1.419mA
-181.8mV  592.4uA    355.7uA    815.3uA
1.418V    -4.584mA   -2.695mA   -6.367mA
1.745V    -5.613mA   -3.257mA   -7.826mA
1.927V    -6.163mA   -3.43mA    -8.629mA
2.036V    -6.378mA   -3.467mA   -9.108mA
2.145V    -6.474mA   -3.483mA   -9.502mA
2.255V    -6.529mA   -3.484mA   -9.651mA
2.4V      -6.578mA   -3.469mA   -9.732mA
[GND_clamp]
|   voltage   I(typ)   I(min)   I(max)
-1.2V     -573mA     -571.2mA   -534.1mA
-1.127V   -446.8mA   -471.5mA   -412.5mA
-1.079V   -368.8mA   -407.4mA   -349mA
-1.006V   -265.4mA   -316mA     -279.3mA
-957.6mV  -210.2mA   -258.9mA   -243.1mA
-884.8mV  -150.2mA   -180.4mA   -192.7mA
-763.6mV  -80.37mA   -75.96mA   -114.1mA
-690.9mV  -47.36mA   -36.81mA   -72.68mA
-618.2mV  -22.24mA   -15mA      -37.68mA
-545.5mV  -7.311mA   -4.854mA   -13.33mA
-424.2mV  -595.6uA   -473.2uA   -921.5uA
1.2V      4.041uA    4.733uA    3.888uA
[Ramp]
| variable   typ   min   max
dV/dt_f 0.71972821/30.197921n 0.64058254/65.274684n 0.79523475/17.750659n
dV/dt_r 0.45168607/1.5013961n 0.32255733/2.4904674n 0.55527561/1.1005775n
R_load = 528.0
[Rising Waveform]
R_fixture = 1000
V_fixture = 1.2
V_fixture_min = 1.08
V_fixture_max = 1.32
|   time   V(typ)   V(min)   V(max)
0s        11.59mV    16.23mV    10.33mV
1.075ns   11.59mV    16.23mV    17.7mV
1.874ns   11.59mV    16.23mV    771.7mV
2.97ns    10.75mV    16.23mV    1.142V
4.901ns   831.7mV    16.23mV    1.294V
7.008ns   1.121V     16.23mV    1.316V
9.681ns   1.188V     38.57mV    1.319V
13.62ns   1.198V     907.9mV    1.319V
20.71ns   1.199V     1.07V      1.319V
333.4ns   1.199V     1.079V     1.319V
[Rising Waveform]
R_fixture = 50
V_fixture = 1.2
V_fixture_min = 1.08
V_fixture_max = 1.32
|   time   V(typ)   V(min)   V(max)
0s        63.08mV    124.2mV    45.53mV
1.008ns   63.09mV    124.2mV    69.44mV
1.245ns   63.09mV    124.2mV    882mV
1.587ns   63.09mV    124.2mV    1.182V
3.272ns   119.6mV    124.2mV    1.318V
3.849ns   1.031V     124.2mV    1.319V
6.258ns   1.198V     124.2mV    1.32V
10.63ns   1.2V       996.9mV    1.32V
14.15ns   1.2V       1.076V     1.32V
333.4ns   1.2V       1.08V      1.32V
[Falling Waveform]
R_fixture = 1000
V_fixture = 1.2
V_fixture_min = 1.08
V_fixture_max = 1.32
|   time   V(typ)   V(min)   V(max)
0s        1.199V     1.079V     1.32V
9.157ns   1.215V     1.091V     1.326V
15.14ns   1.208V     1.091V     1.207V
31.59ns   1.01V      1.085V     570.4mV
40.33ns   832.7mV    1.069V     77.5mV
45.36ns   723.2mV    1.05V      23.96mV
68.2ns    103.9mV    893.6mV    11.62mV
78.54ns   29.71mV    803.5mV    11mV
149.9ns   12.07mV    72.59mV    10.33mV
333.4ns   11.59mV    16.23mV    10.33mV
[Falling Waveform]
R_fixture = 50
V_fixture = 1.2
V_fixture_min = 1.08
V_fixture_max = 1.32
|   time   V(typ)   V(min)   V(max)
0s        1.2V       1.08V      1.321V
10.85ns   1.202V     1.082V     1.315V
15.92ns   1.201V     1.081V     1.245V
34.83ns   1.065V     1.08V      649.2mV
45.98ns   901.2mV    1.073V     155.9mV
54.35ns   767.4mV    1.059V     71.27mV
83.76ns   208.7mV    944.1mV    48.25mV
100.8ns   101mV      857.6mV    46.54mV
220.8ns   63.38mV    236.4mV    45.53mV
333.4ns   63.08mV    124.2mV    45.53mV
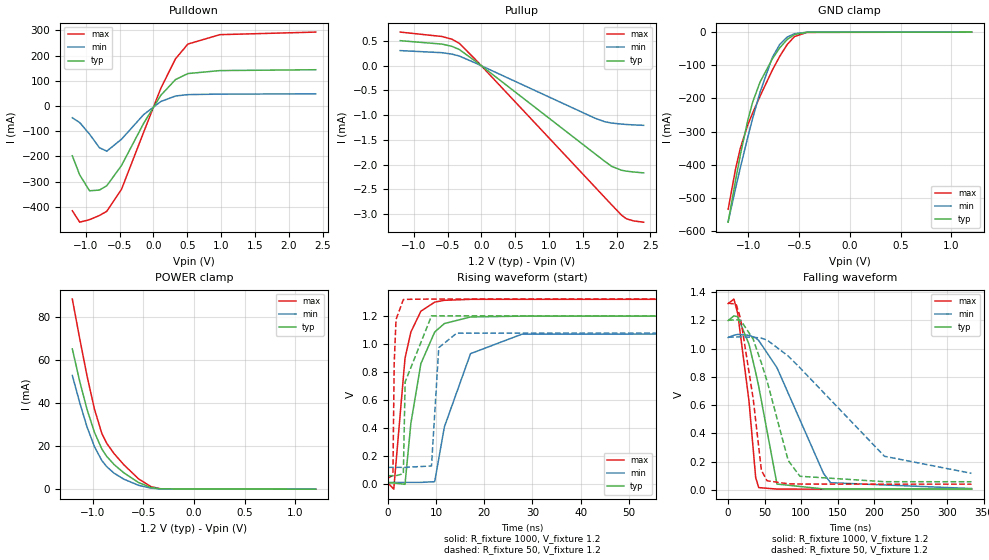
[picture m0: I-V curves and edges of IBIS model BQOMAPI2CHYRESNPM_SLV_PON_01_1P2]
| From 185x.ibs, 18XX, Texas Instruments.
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|   Model Cell BQOMAPI2CHYRESNPM_SLV_PON_01_1P2
|BQOMAPI2CHYRESNPM_SLV_PON_01_1P2
[Model]   BQOMAPI2CHYRESNPM_SLV_PON_01_1P2
Model_type   I/O
Polarity   Non-Inverting
Enable   Active-Low
Vinl =  0.36
Vinh =  0.84
Cref =  400.0000PF
Rref =  1000.0000
Vref =  1.8V
Vmeas =  0.6
C_comp   3.806929p   3.71689p   3.834943p
[Model Spec]
Vinl   0.36   0.324   0.396
Vinh   0.84   0.756   0.924
[Temperature Range]   25   125   -40
[Voltage Range]   1.2   1.08   1.32
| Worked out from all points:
|   slope of the pulldown table from 0 to 0.18 V, typ, clamps not added: 2.63 ohm
|   slope of the pullup table from 0 to 0.18 V, typ, clamps not added: 943 ohm
|   GND clamp passes 1 mA (typ) near -0.45 V on its own axis
|   POWER clamp passes 1 mA (typ) near -0.44 V on its own axis
|   rising waveform, R_fixture 1000, V_fixture 1.2: 20-80 % time 3.57ns typ, 4.9ns min, 2.81ns max; typ from 0.006 V to 1.2 V
|   rising waveform, R_fixture 50, V_fixture 1.2: 20-80 % time 403ps typ, 686ps min, 354ps max; typ from 0.057 V to 1.2 V
|   falling waveform, R_fixture 1000, V_fixture 1.2: 20-80 % time 27.1ns typ, 55.8ns min, 16.4ns max; typ from 1.2 V to 0.006 V
|   falling waveform, R_fixture 50, V_fixture 1.2: 20-80 % time 37.4ns typ, 104ns min, 19.6ns max; typ from 1.2 V to 0.057 V
| Nom Voltages:
|   BIASFET=1.2, VDDS=1.2, VDDU=1.2, BUS_VDD=0, VSS=0, VSSS=0
| Min Voltages:
|   BIASFET=1.08, VDDS=1.08, VDDU=1.08, BUS_VDD=0, VSS=0, VSSS=0
| Max Voltages:
|   BIASFET=1.32, VDDS=1.32, VDDU=1.32, BUS_VDD=0, VSS=0, VSSS=0
[POWER_clamp]
|   voltage   I(typ)   I(min)   I(max)
-1.2V     64.99mA    52.68mA    88.09mA
-1.127V   49.93mA    40.08mA    69.72mA
-1.055V   36.97mA    28.84mA    52.47mA
-981.8mV  26.35mA    19.7mA     37.12mA
-909.1mV  18.6mA     13.27mA    25.8mA
-860.6mV  15.16mA    10.42mA    21.24mA
-787.9mV  11.4mA     7.386mA    16.45mA
-690.9mV  7.53mA     4.603mA    11.25mA
-545.5mV  3.018mA    1.76mA     4.721mA
-424.2mV  769.6uA    464.5uA    1.162mA
-327.3mV  128.4uA    90.42uA    147.3uA
1.2V      -1.911uA   -2.519uA   -1.532uA
[Pulldown]
|   voltage   I(typ)   I(min)   I(max)
-1.2V     -197.1mA   -46.43mA   -415.2mA
-1.091V   -273mA     -65.33mA   -460.6mA
-945.5mV  -336mA     -111.2mA   -450.5mA
-800mV    -333.2mA   -164.9mA   -434.2mA
-690.9mV  -316.2mA   -179mA     -417.4mA
-472.7mV  -235.7mA   -131.5mA   -330.2mA
-145.5mV  -68.6mA    -33.84mA   -104mA
109.1mV   42.89mA    18.14mA    70.72mA
327.3mV   105.4mA    40.08mA    187.9mA
509.1mV   129mA      45.44mA    246mA
981.8mV   140.8mA    47.56mA    283.3mA
2.4V      144.2mA    48.35mA    293.5mA
[Pullup]
|   voltage   I(typ)   I(min)   I(max)
-1.2V     508.6uA    307.5uA    682.4uA
-581.8mV  438.8uA    265.1uA    592.8uA
-436.4mV  394.2uA    236.8uA    538.5uA
-327.3mV  330.1uA    197.9uA    455.4uA
-72.73mV  76.96uA    46.33uA    105.4uA
1.673V    -1.775mA   -1.057mA   -2.445mA
1.818V    -1.928mA   -1.131mA   -2.658mA
1.927V    -2.037mA   -1.16mA    -2.817mA
2.073V    -2.116mA   -1.181mA   -3.026mA
2.145V    -2.134mA   -1.189mA   -3.099mA
2.255V    -2.152mA   -1.198mA   -3.143mA
2.4V      -2.169mA   -1.206mA   -3.168mA
[GND_clamp]
|   voltage   I(typ)   I(min)   I(max)
-1.2V     -573mA     -571.2mA   -534.1mA
-1.127V   -446.8mA   -471.5mA   -412.5mA
-1.079V   -368.8mA   -407.4mA   -349mA
-1.006V   -265.4mA   -316mA     -279.3mA
-957.6mV  -210.2mA   -258.9mA   -243.1mA
-884.8mV  -150.2mA   -180.4mA   -192.7mA
-763.6mV  -80.37mA   -75.96mA   -114.1mA
-690.9mV  -47.36mA   -36.81mA   -72.68mA
-618.2mV  -22.24mA   -15mA      -37.68mA
-545.5mV  -7.311mA   -4.854mA   -13.33mA
-424.2mV  -595.6uA   -473.2uA   -921.5uA
1.2V      4.041uA    4.733uA    3.888uA
[Ramp]
| variable   typ   min   max
dV/dt_f 0.72884397/28.85733n  0.64750814/60.600095n 0.80703218/17.327956n
dV/dt_r  0.2981017/2.4544946n 0.17958597/3.2934636n 0.39523858/2.0096025n
R_load = 528.0
[Rising Waveform]
R_fixture = 1000
V_fixture = 1.2
V_fixture_min = 1.08
V_fixture_max = 1.32
|   time   V(typ)   V(min)   V(max)
0s        5.64mV     9.082mV    4.638mV
1.18ns    5.64mV     9.082mV    -39.29mV
3.518ns   -4.648mV   9.082mV    896.6mV
4.735ns   431.1mV    9.082mV    1.084V
6.811ns   858mV      9.082mV    1.233V
9.682ns   1.084V     14.28mV    1.298V
11.7ns    1.145V     406mV      1.311V
17.13ns   1.192V     929.7mV    1.318V
27.81ns   1.198V     1.069V     1.318V
333.5ns   1.198V     1.078V     1.318V
[Rising Waveform]
R_fixture = 50
V_fixture = 1.2
V_fixture_min = 1.08
V_fixture_max = 1.32
|   time   V(typ)   V(min)   V(max)
0s        57.2mV     116.7mV    39.97mV
1.008ns   57.2mV     116.7mV    59.15mV
1.269ns   57.2mV     116.7mV    855.4mV
1.65ns    57.2mV     116.7mV    1.174V
3.173ns   71.22mV    116.7mV    1.316V
3.545ns   727.5mV    116.7mV    1.318V
9.021ns   1.2V       126.7mV    1.32V
10.53ns   1.2V       972.3mV    1.32V
14.25ns   1.2V       1.076V     1.32V
333.4ns   1.2V       1.08V      1.32V
[Falling Waveform]
R_fixture = 1000
V_fixture = 1.2
V_fixture_min = 1.08
V_fixture_max = 1.32
|   time   V(typ)   V(min)   V(max)
0s        1.198V     1.078V     1.318V
7.882ns   1.231V     1.094V     1.35V
13.09ns   1.225V     1.1V       1.248V
28.58ns   1.03V      1.093V     626.2mV
37.71ns   830.6mV    1.076V     86.89mV
41.87ns   731.7mV    1.057V     15.79mV
66.89ns   40.77mV    864.2mV    5.214mV
130.8ns   6.081mV    114.6mV    4.646mV
140.4ns   5.955mV    50.22mV    4.641mV
333.5ns   5.64mV     9.082mV    4.638mV
[Falling Waveform]
R_fixture = 50
V_fixture = 1.2
V_fixture_min = 1.08
V_fixture_max = 1.32
|   time   V(typ)   V(min)   V(max)
0s        1.2V       1.08V      1.321V
10.92ns   1.203V     1.082V     1.314V
17.05ns   1.2V       1.082V     1.212V
34.29ns   1.066V     1.08V      645.2mV
45.54ns   897.1mV    1.073V     138.2mV
53.35ns   769.1mV    1.06V      63.97mV
82.25ns   207.8mV    946.9mV    42.51mV
98.32ns   95.86mV    863.7mV    40.93mV
214.2ns   57.52mV    237.3mV    39.96mV
333.4ns   57.2mV     116.7mV    39.97mV
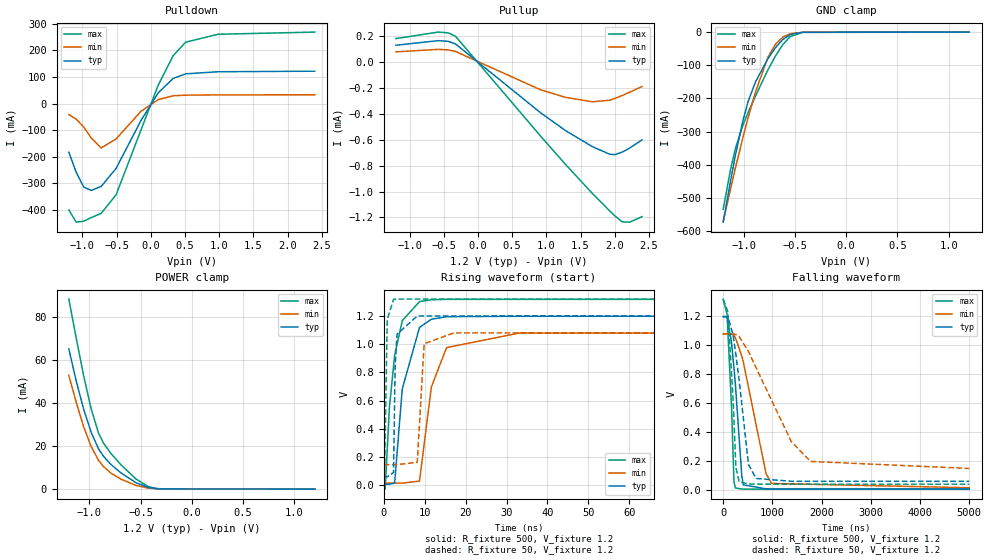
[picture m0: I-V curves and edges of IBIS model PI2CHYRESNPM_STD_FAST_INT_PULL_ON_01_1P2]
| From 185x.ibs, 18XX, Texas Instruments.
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|   Model Cell PI2CHYRESNPM_STD_FAST_INT_PULL_ON_01_1P2
|BQOMAPI2CHYRESNPM_STD_FAST_INT_PULL_ON_01_1P2
[Model]   PI2CHYRESNPM_STD_FAST_INT_PULL_ON_01_1P2
Model_type   I/O
Polarity   Non-Inverting
Enable   Active-Low
Vinl =  0.36
Vinh =  0.84
Cref =  400.0000PF
Rref =  500.0000
Vref =  1.8V
Vmeas =  0.6
C_comp   3.806929p   3.71689p   3.834943p
[Model Spec]
Vinl   0.36   0.324   0.396
Vinh   0.84   0.756   0.924
[Temperature Range]   25   125   -40
[Voltage Range]   1.2   1.08   1.32
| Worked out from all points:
|   slope of the pulldown table from 0 to 0.18 V, typ, clamps not added: 2.87 ohm
|   slope of the pullup table from 0 to 0.18 V, typ, clamps not added: 2.24 kohm
|   GND clamp passes 1 mA (typ) near -0.45 V on its own axis
|   POWER clamp passes 1 mA (typ) near -0.44 V on its own axis
|   rising waveform, R_fixture 500, V_fixture 1.2: 20-80 % time 3.07ns typ, 3.75ns min, 2.65ns max; typ from 0.007 V to 1.2 V
|   rising waveform, R_fixture 50, V_fixture 1.2: 20-80 % time 422ps typ, 715ps min, 372ps max; typ from 0.059 V to 1.2 V
|   falling waveform, R_fixture 500, V_fixture 1.2: 20-80 % time 163ns typ, 382ns min, 94.1ns max; typ from 1.2 V to 0.007 V
|   falling waveform, R_fixture 50, V_fixture 1.2: 20-80 % time 230ns typ, 782ns min, 111ns max; typ from 1.2 V to 0.059 V
| Nom Voltages:
|   BIASFET=1.2, VDDS=1.2, VDDU=1.2, BUS_VDD=0, VSS=0, VSSS=0
| Min Voltages:
|   BIASFET=1.08, VDDS=1.08, VDDU=1.08, BUS_VDD=0, VSS=0, VSSS=0
| Max Voltages:
|   BIASFET=1.32, VDDS=1.32, VDDU=1.32, BUS_VDD=0, VSS=0, VSSS=0
[POWER_clamp]
|   voltage   I(typ)   I(min)   I(max)
-1.2V     64.99mA    52.68mA    88.09mA
-1.127V   49.93mA    40.08mA    69.72mA
-1.055V   36.97mA    28.84mA    52.47mA
-981.8mV  26.35mA    19.7mA     37.12mA
-909.1mV  18.6mA     13.27mA    25.8mA
-860.6mV  15.16mA    10.42mA    21.24mA
-787.9mV  11.4mA     7.386mA    16.45mA
-690.9mV  7.53mA     4.603mA    11.25mA
-545.5mV  3.018mA    1.76mA     4.721mA
-424.2mV  769.6uA    464.5uA    1.162mA
-327.3mV  128.4uA    90.42uA    147.3uA
1.2V      -1.911uA   -2.519uA   -1.532uA
[Pulldown]
|   voltage   I(typ)   I(min)   I(max)
-1.2V     -183.4mA   -41.91mA   -400.8mA
-1.091V   -259.8mA   -59.09mA   -446.7mA
-981.8mV  -314.4mA   -88.65mA   -442.9mA
-872.7mV  -327.3mA   -129.6mA   -429.5mA
-727.3mV  -312.2mA   -167.3mA   -413.5mA
-509.1mV  -244.7mA   -133.5mA   -344mA
-145.5mV  -64.58mA   -29.53mA   -100.7mA
109.1mV   40.4mA     14.8mA     69.7mA
327.3mV   94.41mA    29.08mA    180.2mA
509.1mV   111.6mA    31.43mA    230.7mA
981.8mV   119.5mA    32.36mA    260.6mA
2.4V      121.7mA    32.72mA    268.8mA
[Pullup]
|   voltage   I(typ)   I(min)   I(max)
-1.2V     129.5uA    78.28uA    180.8uA
-581.8mV  164.9uA    97.64uA    231uA
-436.4mV  159.5uA    93.77uA    225.3uA
-327.3mV  138.6uA    81.2uA     197.6uA
909.1mV   -389.3uA   -213.3uA   -568.4uA
1.273V    -527.1uA   -271.9uA   -786.6uA
1.673V    -653.7uA   -307.1uA   -1.015mA
1.927V    -712.3uA   -295.1uA   -1.15mA
2V        -715.4uA   -281.7uA   -1.187mA
2.109V    -696.3uA   -258.7uA   -1.234mA
2.218V    -664.7uA   -233.6uA   -1.237mA
2.4V      -601.3uA   -189.4uA   -1.194mA
[GND_clamp]
|   voltage   I(typ)   I(min)   I(max)
-1.2V     -573mA     -571.2mA   -534.1mA
-1.127V   -446.8mA   -471.5mA   -412.5mA
-1.079V   -368.8mA   -407.4mA   -349mA
-1.006V   -265.4mA   -316mA     -279.3mA
-957.6mV  -210.2mA   -258.9mA   -243.1mA
-884.8mV  -150.2mA   -180.4mA   -192.7mA
-763.6mV  -80.37mA   -75.96mA   -114.1mA
-690.9mV  -47.36mA   -36.81mA   -72.68mA
-618.2mV  -22.24mA   -15mA      -37.68mA
-545.5mV  -7.311mA   -4.854mA   -13.33mA
-424.2mV  -595.7uA   -473.2uA   -921.5uA
1.2V      4.041uA    4.733uA    3.888uA
[Ramp]
| variable   typ   min   max
dV/dt_f 0.71815892/0.16365491u 0.64011765/0.38004103u  0.7929152/94.792394n
dV/dt_r 0.20531056/4.0740211n 0.12544596/5.2883217n 0.27358427/3.3073772n
R_load = 528.00
[Rising Waveform]
R_fixture = 500
V_fixture = 1.2
V_fixture_min = 1.08
V_fixture_max = 1.32
|   time   V(typ)   V(min)   V(max)
0s        7.038mV    14.91mV    4.453mV
366.7ps   7.038mV    14.91mV    -27.84mV
1.391ns   7.038mV    14.91mV    548.5mV
2.67ns    15.3mV     14.91mV    920mV
4.54ns    683.4mV    14.91mV    1.167V
8.746ns   1.119V     29.49mV    1.302V
11.64ns   1.177V     696.1mV    1.315V
15.34ns   1.195V     975.4mV    1.318V
33.05ns   1.198V     1.079V     1.318V
5us       1.198V     1.078V     1.318V
[Rising Waveform]
R_fixture = 50
V_fixture = 1.2
V_fixture_min = 1.08
V_fixture_max = 1.32
|   time   V(typ)   V(min)   V(max)
0s        59.38mV    146.3mV    39.85mV
214.2ps   59.38mV    146.3mV    79.34mV
865.6ps   59.38mV    146.3mV    1.177V
2.401ns   90.01mV    146.3mV    1.317V
2.789ns   837.6mV    146.3mV    1.319V
3.251ns   1.071V     146.3mV    1.32V
8.191ns   1.2V       162.5mV    1.32V
9.879ns   1.2V       1.003V     1.32V
17.12ns   1.2V       1.08V      1.32V
5us       1.2V       1.08V      1.32V
[Falling Waveform]
R_fixture = 500
V_fixture = 1.2
V_fixture_min = 1.08
V_fixture_max = 1.32
|   time   V(typ)   V(min)   V(max)
0s        1.198V     1.078V     1.318V
78.83ns   1.198V     1.081V     1.216V
169ns     1.022V     1.078V     581.6mV
219.5ns   843.4mV    1.068V     56.87mV
247.3ns   735.7mV    1.054V     13.34mV
379.3ns   94.4mV     924.4mV    5.712mV
409.1ns   34.96mV    886.3mV    5.511mV
871.2ns   7.333mV    112.6mV    5.053mV
981.9ns   7.187mV    44.57mV    5.051mV
5us       7.038mV    14.94mV    5.05mV
[Falling Waveform]
R_fixture = 50
V_fixture = 1.2
V_fixture_min = 1.08
V_fixture_max = 1.32
|   time   V(typ)   V(min)   V(max)
0s        1.2V       1.08V      1.32V
95.27ns   1.198V     1.08V      1.232V
200.4ns   1.075V     1.079V     632.4mV
259ns     933.7mV    1.075V     154.3mV
324.6ns   759.6mV    1.061V     56.32mV
514.5ns   175.1mV    957mV      41.01mV
671ns     79.13mV    842.7mV    39.7mV
1.385us   59.63mV    334mV      39.38mV
1.775us   59.41mV    196.8mV    39.38mV
5us       59.38mV    148.3mV    39.38mV
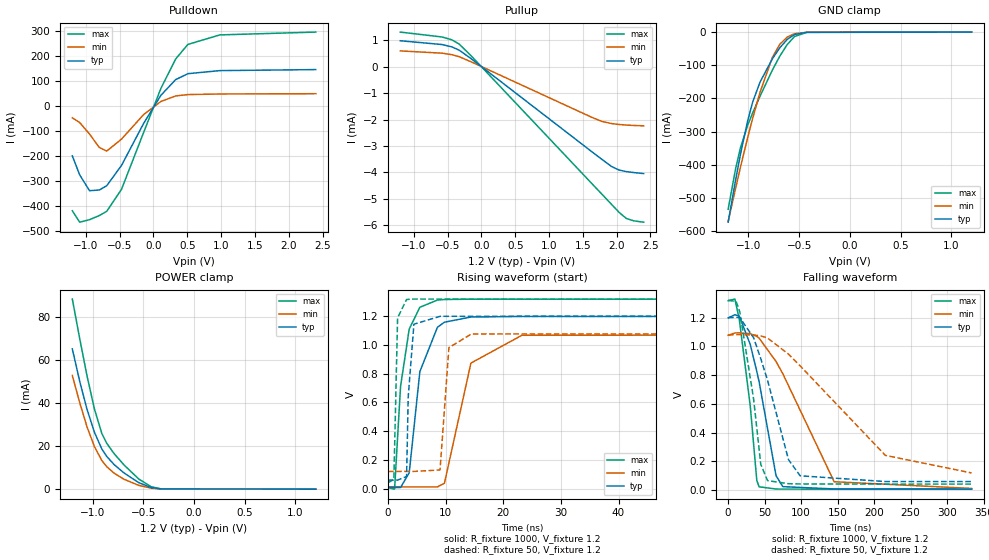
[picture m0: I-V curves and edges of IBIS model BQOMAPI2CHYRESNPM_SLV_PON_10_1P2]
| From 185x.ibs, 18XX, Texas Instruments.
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|   Model Cell BQOMAPI2CHYRESNPM_SLV_PON_10_1P2
|BQOMAPI2CHYRESNPM_SLV_PON_10_1P2
[Model]   BQOMAPI2CHYRESNPM_SLV_PON_10_1P2
Model_type   I/O
Polarity   Non-Inverting
Enable   Active-Low
Vinl =  0.36
Vinh =  0.84
Cref =  400.0000PF
Rref =  1000.0000
Vref =  1.8V
Vmeas =  0.6
C_comp   3.806929p   3.71689p   3.834943p
[Model Spec]
Vinl   0.36   0.324   0.396
Vinh   0.84   0.756   0.924
[Temperature Range]   25   125   -40
[Voltage Range]   1.2   1.08   1.32
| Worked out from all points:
|   slope of the pulldown table from 0 to 0.18 V, typ, clamps not added: 2.62 ohm
|   slope of the pullup table from 0 to 0.18 V, typ, clamps not added: 507 ohm
|   GND clamp passes 1 mA (typ) near -0.45 V on its own axis
|   POWER clamp passes 1 mA (typ) near -0.44 V on its own axis
|   rising waveform, R_fixture 1000, V_fixture 1.2: 20-80 % time 2.51ns typ, 3.8ns min, 1.89ns max; typ from 0.008 V to 1.2 V
|   rising waveform, R_fixture 50, V_fixture 1.2: 20-80 % time 381ps typ, 683ps min, 330ps max; typ from 0.06 V to 1.2 V
|   falling waveform, R_fixture 1000, V_fixture 1.2: 20-80 % time 28ns typ, 58.2ns min, 16.8ns max; typ from 1.2 V to 0.008 V
|   falling waveform, R_fixture 50, V_fixture 1.2: 20-80 % time 37.6ns typ, 105ns min, 19.8ns max; typ from 1.2 V to 0.06 V
| Nom Voltages:
|   BIASFET=1.2, VDDS=1.2, VDDU=1.2, BUS_VDD=0, VSS=0, VSSS=0
| Min Voltages:
|   BIASFET=1.08, VDDS=1.08, VDDU=1.08, BUS_VDD=0, VSS=0, VSSS=0
| Max Voltages:
|   BIASFET=1.32, VDDS=1.32, VDDU=1.32, BUS_VDD=0, VSS=0, VSSS=0
[POWER_clamp]
|   voltage   I(typ)   I(min)   I(max)
-1.2V     64.99mA    52.68mA    88.09mA
-1.127V   49.93mA    40.08mA    69.72mA
-1.055V   36.97mA    28.84mA    52.47mA
-981.8mV  26.35mA    19.7mA     37.12mA
-909.1mV  18.6mA     13.27mA    25.8mA
-860.6mV  15.16mA    10.42mA    21.24mA
-787.9mV  11.4mA     7.386mA    16.45mA
-690.9mV  7.53mA     4.603mA    11.25mA
-545.5mV  3.018mA    1.76mA     4.721mA
-424.2mV  769.6uA    464.5uA    1.162mA
-327.3mV  128.4uA    90.42uA    147.3uA
1.2V      -1.911uA   -2.519uA   -1.532uA
[Pulldown]
|   voltage   I(typ)   I(min)   I(max)
-1.2V     -199mA     -47.46mA   -417.9mA
-1.091V   -274.8mA   -66.35mA   -463.3mA
-945.5mV  -337.8mA   -112.2mA   -453.2mA
-800mV    -335mA     -165.9mA   -436.8mA
-690.9mV  -317.9mA   -179.9mA   -419.9mA
-472.7mV  -237.2mA   -132.3mA   -332.4mA
-145.5mV  -69.82mA   -34.51mA   -105.9mA
109.1mV   41.89mA    17.61mA    69.21mA
327.3mV   104.6mA    39.66mA    186.6mA
509.1mV   128.4mA    45.12mA    245mA
981.8mV   140.6mA    47.51mA    282.9mA
2.4V      144.7mA    48.64mA    294.1mA
[Pullup]
|   voltage   I(typ)   I(min)   I(max)
-1.2V     976uA      593.2uA    1.303mA
-581.8mV  832.7uA    506.4uA    1.118mA
-436.4mV  744uA      449.8uA    1.011mA
-327.3mV  618.5uA    372.9uA    848.9uA
-145.5mV  286.5uA    173.3uA    391uA
1.636V    -3.221mA   -1.92mA    -4.426mA
1.782V    -3.504mA   -2.07mA    -4.819mA
1.927V    -3.777mA   -2.154mA   -5.211mA
2.036V    -3.908mA   -2.187mA   -5.505mA
2.145V    -3.968mA   -2.209mA   -5.739mA
2.255V    -4.004mA   -2.224mA   -5.827mA
2.4V      -4.041mA   -2.238mA   -5.878mA
[GND_clamp]
|   voltage   I(typ)   I(min)   I(max)
-1.2V     -573mA     -571.2mA   -534.1mA
-1.127V   -446.8mA   -471.5mA   -412.5mA
-1.079V   -368.8mA   -407.4mA   -349mA
-1.006V   -265.4mA   -316mA     -279.3mA
-957.6mV  -210.2mA   -258.9mA   -243.1mA
-884.8mV  -150.2mA   -180.4mA   -192.7mA
-763.6mV  -80.37mA   -75.96mA   -114.1mA
-690.9mV  -47.36mA   -36.81mA   -72.68mA
-618.2mV  -22.24mA   -15mA      -37.68mA
-545.5mV  -7.311mA   -4.854mA   -13.33mA
-424.2mV  -595.6uA   -473.2uA   -921.5uA
1.2V      4.041uA    4.733uA    3.888uA
[Ramp]
| variable   typ   min   max
dV/dt_f 0.72435015/29.489206n 0.64432246/62.4583n   0.80097904/17.4942n
dV/dt_r 0.37292241/1.9359392n 0.24738564/2.8540921n 0.48560715/1.502555n
R_load = 528.0
[Rising Waveform]
R_fixture = 1000
V_fixture = 1.2
V_fixture_min = 1.08
V_fixture_max = 1.32
|   time   V(typ)   V(min)   V(max)
0s        8.125mV    12.13mV    6.976mV
1.128ns   8.125mV    12.13mV    -3.522mV
2.171ns   8.125mV    12.13mV    713.2mV
3.671ns   110.2mV    12.13mV    1.111V
5.521ns   815.5mV    12.13mV    1.263V
8.564ns   1.123V     12.04mV    1.313V
9.783ns   1.159V     37.3mV     1.317V
14.38ns   1.195V     874.2mV    1.319V
23.24ns   1.199V     1.068V     1.319V
333.5ns   1.199V     1.078V     1.319V
[Rising Waveform]
R_fixture = 50
V_fixture = 1.2
V_fixture_min = 1.08
V_fixture_max = 1.32
|   time   V(typ)   V(min)   V(max)
0s        59.66mV    119.9mV    42.25mV
1.008ns   59.66mV    119.9mV    63.35mV
1.651ns   59.66mV    119.9mV    1.189V
3.214ns   84.74mV    119.9mV    1.317V
3.498ns   639.7mV    119.9mV    1.318V
4.483ns   1.145V     119.9mV    1.32V
9.021ns   1.2V       130.3mV    1.32V
10.56ns   1.2V       982mV      1.32V
14.48ns   1.2V       1.077V     1.32V
333.4ns   1.2V       1.08V      1.32V
[Falling Waveform]
R_fixture = 1000
V_fixture = 1.2
V_fixture_min = 1.08
V_fixture_max = 1.32
|   time   V(typ)   V(min)   V(max)
0s        1.199V     1.078V     1.319V
9.197ns   1.221V     1.094V     1.33V
15.21ns   1.212V     1.095V     1.191V
30.33ns   1.013V     1.089V     584.2mV
39.24ns   826.2mV    1.07V      68.19mV
42.4ns    754.9mV    1.058V     23.47mV
65.61ns   100.6mV    895.4mV    7.965mV
74.87ns   24.57mV    810.6mV    7.513mV
145.2ns   8.519mV    58.69mV    6.976mV
333.5ns   8.125mV    12.13mV    6.976mV
[Falling Waveform]
R_fixture = 50
V_fixture = 1.2
V_fixture_min = 1.08
V_fixture_max = 1.32
|   time   V(typ)   V(min)   V(max)
0s        1.2V       1.08V      1.321V
10.89ns   1.203V     1.082V     1.314V
15.99ns   1.201V     1.082V     1.24V
34.83ns   1.061V     1.08V      636.1mV
44.69ns   915.1mV    1.074V     179.6mV
53.94ns   765.6mV    1.059V     66.6mV
82.68ns   212.3mV    946.8mV    44.95mV
98.57ns   100.1mV    865.3mV    43.24mV
215.4ns   59.98mV    242.1mV    42.25mV
333.4ns   59.66mV    119.9mV    42.25mV
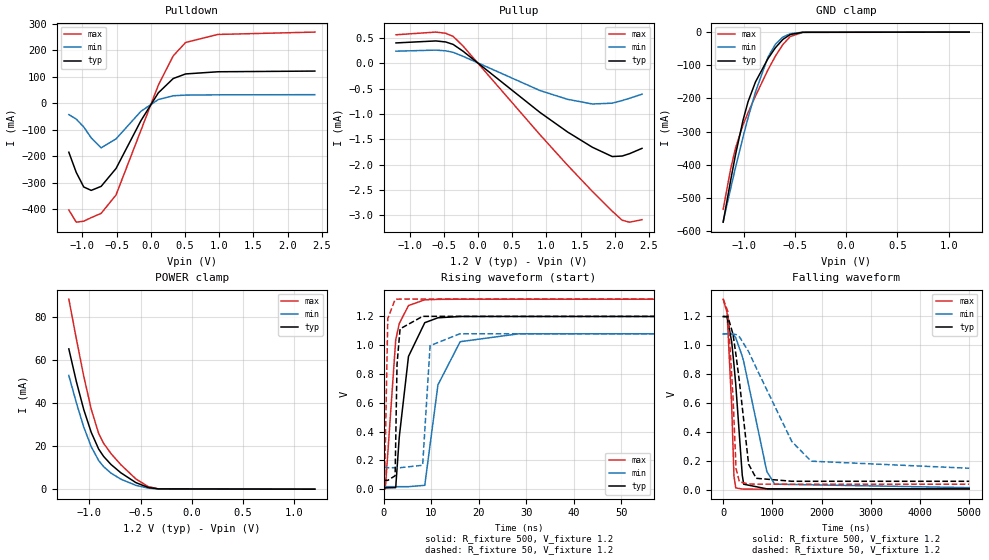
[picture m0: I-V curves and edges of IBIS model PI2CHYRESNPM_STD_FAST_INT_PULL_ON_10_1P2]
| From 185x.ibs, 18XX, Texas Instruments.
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|   Model Cell PI2CHYRESNPM_STD_FAST_INT_PULL_ON_10_1P2
|BQOMAPI2CHYRESNPM_STD_FAST_INT_PULL_ON_10_1P2
[Model]   PI2CHYRESNPM_STD_FAST_INT_PULL_ON_10_1P2
Model_type   I/O
Polarity   Non-Inverting
Enable   Active-Low
Vinl =  0.36
Vinh =  0.84
Cref =  400.0000PF
Rref =  500.0000
Vref =  1.8V
Vmeas =  0.6
C_comp   3.806929p   3.71689p   3.834943p
[Model Spec]
Vinl   0.36   0.324   0.396
Vinh   0.84   0.756   0.924
[Temperature Range]   25   125   -40
[Voltage Range]   1.2   1.08   1.32
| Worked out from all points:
|   slope of the pulldown table from 0 to 0.18 V, typ, clamps not added: 2.87 ohm
|   slope of the pullup table from 0 to 0.18 V, typ, clamps not added: 904 ohm
|   GND clamp passes 1 mA (typ) near -0.45 V on its own axis
|   POWER clamp passes 1 mA (typ) near -0.44 V on its own axis
|   rising waveform, R_fixture 500, V_fixture 1.2: 20-80 % time 2.45ns typ, 3.3ns min, 1.97ns max; typ from 0.009 V to 1.2 V
|   rising waveform, R_fixture 50, V_fixture 1.2: 20-80 % time 407ps typ, 714ps min, 354ps max; typ from 0.061 V to 1.2 V
|   falling waveform, R_fixture 500, V_fixture 1.2: 20-80 % time 167ns typ, 396ns min, 95.1ns max; typ from 1.2 V to 0.009 V
|   falling waveform, R_fixture 50, V_fixture 1.2: 20-80 % time 232ns typ, 789ns min, 112ns max; typ from 1.2 V to 0.061 V
| Nom Voltages:
|   BIASFET=1.2, VDDS=1.2, VDDU=1.2, BUS_VDD=0, VSS=0, VSSS=0
| Min Voltages:
|   BIASFET=1.08, VDDS=1.08, VDDU=1.08, BUS_VDD=0, VSS=0, VSSS=0
| Max Voltages:
|   BIASFET=1.32, VDDS=1.32, VDDU=1.32, BUS_VDD=0, VSS=0, VSSS=0
[POWER_clamp]
|   voltage   I(typ)   I(min)   I(max)
-1.2V     64.99mA    52.68mA    88.09mA
-1.127V   49.93mA    40.08mA    69.72mA
-1.055V   36.97mA    28.84mA    52.47mA
-981.8mV  26.35mA    19.7mA     37.12mA
-909.1mV  18.6mA     13.27mA    25.8mA
-860.6mV  15.16mA    10.42mA    21.24mA
-787.9mV  11.4mA     7.386mA    16.45mA
-690.9mV  7.53mA     4.603mA    11.25mA
-545.5mV  3.018mA    1.76mA     4.721mA
-424.2mV  769.6uA    464.5uA    1.162mA
-327.3mV  128.4uA    90.42uA    147.3uA
1.2V      -1.911uA   -2.519uA   -1.532uA
[Pulldown]
|   voltage   I(typ)   I(min)   I(max)
-1.2V     -184.4mA   -42.35mA   -402.7mA
-1.091V   -260.9mA   -59.55mA   -448.6mA
-981.8mV  -315.6mA   -89.13mA   -444.8mA
-872.7mV  -328.5mA   -130.1mA   -431.4mA
-727.3mV  -313.3mA   -167.8mA   -415.3mA
-509.1mV  -245.8mA   -134mA     -345.7mA
-145.5mV  -65.41mA   -29.94mA   -102mA
109.1mV   39.71mA    14.46mA    68.58mA
327.3mV   93.85mA    28.81mA    179.3mA
509.1mV   111.2mA    31.22mA    230mA
981.8mV   119.4mA    32.32mA    260.3mA
2.4V      122mA      32.88mA    269.2mA
[Pullup]
|   voltage   I(typ)   I(min)   I(max)
-1.2V     407uA      243.6uA    568.3uA
-618.2mV  446.4uA    264.7uA    621.4uA
-472.7mV  426.1uA    250.9uA    598.2uA
-363.6mV  377.3uA    220.9uA    536uA
-218.2mV  242.2uA    141.9uA    343.6uA
909.1mV   -970.8uA   -536.4uA   -1.413mA
1.309V    -1.354mA   -708.2uA   -2.011mA
1.673V    -1.657mA   -801uA     -2.531mA
1.964V    -1.841mA   -785.3uA   -2.923mA
2.109V    -1.831mA   -733.2uA   -3.101mA
2.218V    -1.784mA   -688.2uA   -3.14mA
2.4V      -1.679mA   -607.3uA   -3.09mA
[GND_clamp]
|   voltage   I(typ)   I(min)   I(max)
-1.2V     -573mA     -571.2mA   -534.1mA
-1.127V   -446.8mA   -471.5mA   -412.5mA
-1.079V   -368.8mA   -407.4mA   -349mA
-1.006V   -265.4mA   -316mA     -279.3mA
-957.6mV  -210.2mA   -258.9mA   -243.1mA
-884.8mV  -150.2mA   -180.4mA   -192.7mA
-763.6mV  -80.37mA   -75.96mA   -114.1mA
-690.9mV  -47.36mA   -36.81mA   -72.68mA
-618.2mV  -22.24mA   -15mA      -37.68mA
-545.5mV  -7.311mA   -4.854mA   -13.33mA
-424.2mV  -595.7uA   -473.2uA   -921.5uA
1.2V      4.041uA    4.733uA    3.888uA
[Ramp]
| variable   typ   min   max
dV/dt_f  0.7165809/0.16771294u 0.63861113/0.39060158u 0.79081678/95.914567n
dV/dt_r 0.30005912/2.4964753n  0.1756427/3.3482568n 0.40514306/1.9812044n
R_load = 528.00
[Rising Waveform]
R_fixture = 500
V_fixture = 1.2
V_fixture_min = 1.08
V_fixture_max = 1.32
|   time   V(typ)   V(min)   V(max)
0s        8.864mV    17.26mV    6.224mV
334.5ps   8.864mV    17.26mV    0V
2.526ns   10.78mV    17.26mV    1.036V
3.275ns   362.4mV    17.26mV    1.15V
5.215ns   921.8mV    17.26mV    1.275V
8.638ns   1.156V     26.89mV    1.315V
11.41ns   1.19V      724.2mV    1.318V
16.08ns   1.199V     1.024V     1.319V
28.46ns   1.199V     1.079V     1.319V
5us       1.199V     1.079V     1.319V
[Rising Waveform]
R_fixture = 50
V_fixture = 1.2
V_fixture_min = 1.08
V_fixture_max = 1.32
|   time   V(typ)   V(min)   V(max)
0s        61.22mV    149.1mV    41.82mV
214.3ps   61.22mV    149.1mV    83.95mV
859.6ps   61.22mV    149.1mV    1.185V
2.401ns   93.19mV    149.1mV    1.317V
2.805ns   868.3mV    149.1mV    1.319V
3.444ns   1.113V     149.1mV    1.32V
8.191ns   1.2V       165.9mV    1.32V
9.76ns    1.2V       996.4mV    1.32V
16.03ns   1.2V       1.079V     1.32V
5us       1.2V       1.08V      1.32V
[Falling Waveform]
R_fixture = 500
V_fixture = 1.2
V_fixture_min = 1.08
V_fixture_max = 1.32
|   time   V(typ)   V(min)   V(max)
0s        1.199V     1.079V     1.319V
79.25ns   1.198V     1.081V     1.227V
173.4ns   1.024V     1.078V     579.3mV
219ns     868.6mV    1.069V     98.18mV
255.5ns   731.4mV    1.053V     15.8mV
388.2ns   102.5mV    924.7mV    7.638mV
418.1ns   41.01mV    887.1mV    7.397mV
887ns     9.219mV    129.1mV    6.822mV
1.048us   8.996mV    41.16mV    6.819mV
5us       8.864mV    17.29mV    6.818mV
[Falling Waveform]
R_fixture = 50
V_fixture = 1.2
V_fixture_min = 1.08
V_fixture_max = 1.32
|   time   V(typ)   V(min)   V(max)
0s        1.2V       1.08V      1.32V
95.28ns   1.199V     1.08V      1.234V
200.5ns   1.077V     1.079V     639.6mV
261.8ns   930.2mV    1.075V     148.3mV
331.3ns   746.4mV    1.059V     56.97mV
516.6ns   179.7mV    957.1mV    42.8mV
671.6ns   81.85mV    844.6mV    41.43mV
1.396us   61.46mV    335.4mV    41.11mV
1.787us   61.24mV    200.1mV    41.11mV
5us       61.22mV    151.3mV    41.11mV
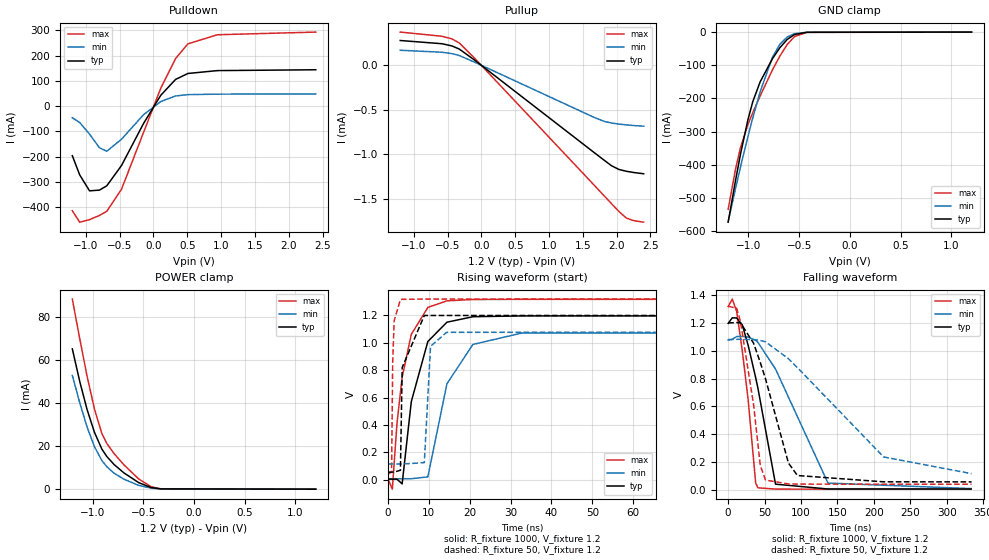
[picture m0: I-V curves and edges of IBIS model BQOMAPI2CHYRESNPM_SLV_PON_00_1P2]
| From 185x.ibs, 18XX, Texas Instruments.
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|   Model Cell BQOMAPI2CHYRESNPM_SLV_PON_00_1P2
|BQOMAPI2CHYRESNPM_SLV_PON_00_1P2
[Model]   BQOMAPI2CHYRESNPM_SLV_PON_00_1P2
Model_type   I/O
Polarity   Non-Inverting
Enable   Active-Low
Vinl =  0.36
Vinh =  0.84
Cref =  400.0000PF
Rref =  1000.0000
Vref =  1.8V
Vmeas =  0.6
C_comp   3.806929p   3.71689p   3.834943p
[Model Spec]
Vinl   0.36   0.324   0.396
Vinh   0.84   0.756   0.924
[Temperature Range]   25   125   -40
[Voltage Range]   1.2   1.08   1.32
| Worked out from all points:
|   slope of the pulldown table from 0 to 0.18 V, typ, clamps not added: 2.63 ohm
|   slope of the pullup table from 0 to 0.18 V, typ, clamps not added: 1.7 kohm
|   GND clamp passes 1 mA (typ) near -0.45 V on its own axis
|   POWER clamp passes 1 mA (typ) near -0.44 V on its own axis
|   rising waveform, R_fixture 1000, V_fixture 1.2: 20-80 % time 4.6ns typ, 5.86ns min, 3.82ns max; typ from 0.004 V to 1.2 V
|   rising waveform, R_fixture 50, V_fixture 1.2: 20-80 % time 417ps typ, 689ps min, 369ps max; typ from 0.056 V to 1.2 V
|   falling waveform, R_fixture 1000, V_fixture 1.2: 20-80 % time 26.4ns typ, 54.6ns min, 16.2ns max; typ from 1.2 V to 0.004 V
|   falling waveform, R_fixture 50, V_fixture 1.2: 20-80 % time 37.2ns typ, 103ns min, 19.5ns max; typ from 1.2 V to 0.056 V
| Nom Voltages:
|   BIASFET=1.2, VDDS=1.2, VDDU=1.2, BUS_VDD=0, VSS=0, VSSS=0
| Min Voltages:
|   BIASFET=1.08, VDDS=1.08, VDDU=1.08, BUS_VDD=0, VSS=0, VSSS=0
| Max Voltages:
|   BIASFET=1.32, VDDS=1.32, VDDU=1.32, BUS_VDD=0, VSS=0, VSSS=0
[POWER_clamp]
|   voltage   I(typ)   I(min)   I(max)
-1.2V     64.99mA    52.68mA    88.09mA
-1.127V   49.93mA    40.08mA    69.72mA
-1.055V   36.97mA    28.84mA    52.47mA
-981.8mV  26.35mA    19.7mA     37.12mA
-909.1mV  18.6mA     13.27mA    25.8mA
-860.6mV  15.16mA    10.42mA    21.24mA
-787.9mV  11.4mA     7.386mA    16.45mA
-690.9mV  7.53mA     4.603mA    11.25mA
-545.5mV  3.018mA    1.76mA     4.721mA
-424.2mV  769.6uA    464.5uA    1.162mA
-327.3mV  128.4uA    90.42uA    147.3uA
1.2V      -1.911uA   -2.519uA   -1.532uA
[Pulldown]
|   voltage   I(typ)   I(min)   I(max)
-1.2V     -196.1mA   -45.91mA   -413.8mA
-1.091V   -272mA     -64.81mA   -459.2mA
-945.5mV  -335.1mA   -110.7mA   -449.1mA
-800mV    -332.3mA   -164.4mA   -432.8mA
-690.9mV  -315.3mA   -178.5mA   -416.1mA
-472.7mV  -234.9mA   -131mA     -329mA
-145.5mV  -67.96mA   -33.5mA    -103.1mA
109.1mV   43.4mA     18.42mA    71.51mA
327.3mV   105.8mA    40.29mA    188.5mA
509.1mV   129.3mA    45.6mA     246.5mA
945.5mV   140.7mA    47.54mA    282.6mA
2.4V      144mA      48.21mA    293.1mA
[Pullup]
|   voltage   I(typ)   I(min)   I(max)
-1.2V     279.3uA    169.5uA    373.7uA
-581.8mV  242.8uA    147.3uA    326.9uA
-436.4mV  218.5uA    131.8uA    297.5uA
-327.3mV  183.1uA    110.2uA    251.7uA
-109.1mV  64.04uA    38.71uA    87.46uA
1.673V    -982.7uA   -586.5uA   -1.35mA
1.818V    -1.067mA   -629.6uA   -1.468mA
1.927V    -1.129mA   -648.4uA   -1.556mA
2.036V    -1.17mA    -660.2uA   -1.643mA
2.145V    -1.19mA    -669uA     -1.716mA
2.255V    -1.204mA   -676.1uA   -1.745mA
2.4V      -1.218mA   -683.7uA   -1.762mA
[GND_clamp]
|   voltage   I(typ)   I(min)   I(max)
-1.2V     -573mA     -571.2mA   -534.1mA
-1.127V   -446.8mA   -471.5mA   -412.5mA
-1.079V   -368.8mA   -407.4mA   -349mA
-1.006V   -265.4mA   -316mA     -279.3mA
-957.6mV  -210.2mA   -258.9mA   -243.1mA
-884.8mV  -150.2mA   -180.4mA   -192.7mA
-763.6mV  -80.37mA   -75.96mA   -114.1mA
-690.9mV  -47.36mA   -36.81mA   -72.68mA
-618.2mV  -22.24mA   -15mA      -37.68mA
-545.5mV  -7.311mA   -4.854mA   -13.33mA
-424.2mV  -595.6uA   -473.2uA   -921.5uA
1.2V      4.041uA    4.733uA    3.888uA
[Ramp]
| variable   typ   min   max
dV/dt_f 0.73195566/28.471484n 0.64937418/59.595464n 0.81165707/17.245314n
dV/dt_r 0.23430379/3.7862841n  0.1442944/5.1479068n 0.30784417/3.0937179n
R_load = 528.0
[Rising Waveform]
R_fixture = 1000
V_fixture = 1.2
V_fixture_min = 1.08
V_fixture_max = 1.32
|   time   V(typ)   V(min)   V(max)
0s        4.346mV    7.512mV    3.408mV
1.047ns   4.346mV    7.512mV    -68.71mV
2.185ns   4.345mV    7.512mV    413.8mV
3.446ns   -30.01mV   7.512mV    748.6mV
5.688ns   571mV      7.511mV    1.062V
9.735ns   1.01V      21.2mV     1.259V
14.41ns   1.151V     701.4mV    1.307V
20.76ns   1.191V     988.4mV    1.317V
32.77ns   1.197V     1.072V     1.318V
333.4ns   1.197V     1.077V     1.318V
[Rising Waveform]
R_fixture = 50
V_fixture = 1.2
V_fixture_min = 1.08
V_fixture_max = 1.32
|   time   V(typ)   V(min)   V(max)
0s        55.92mV    115.1mV    39.13mV
857.5ps   55.92mV    115.1mV    56.94mV
1.129ns   55.92mV    115.1mV    855.1mV
1.49ns    55.92mV    115.1mV    1.161V
3.023ns   69.47mV    115.1mV    1.316V
3.459ns   820.3mV    115.1mV    1.318V
8.87ns    1.2V       124.9mV    1.32V
10.4ns    1.2V       974.7mV    1.32V
14.32ns   1.2V       1.077V     1.32V
334.1ns   1.2V       1.08V      1.32V
[Falling Waveform]
R_fixture = 1000
V_fixture = 1.2
V_fixture_min = 1.08
V_fixture_max = 1.32
|   time   V(typ)   V(min)   V(max)
0s        1.197V     1.077V     1.318V
5.7ns     1.237V     1.083V     1.372V
11.68ns   1.236V     1.102V     1.283V
19.44ns   1.185V     1.103V     998.5mV
27.46ns   1.039V     1.098V     646.8mV
37.76ns   806.4mV    1.075V     47.73mV
40.86ns   730.5mV    1.06V      13.09mV
65ns      39.38mV    868.3mV    3.886mV
137ns     4.613mV    47.31mV    3.411mV
333.4ns   4.346mV    7.512mV    3.408mV
[Falling Waveform]
R_fixture = 50
V_fixture = 1.2
V_fixture_min = 1.08
V_fixture_max = 1.32
|   time   V(typ)   V(min)   V(max)
0s        1.2V       1.08V      1.32V
11.63ns   1.203V     1.082V     1.307V
16.98ns   1.2V       1.082V     1.209V
34.92ns   1.054V     1.08V      610.4mV
44.12ns   914.9mV    1.074V     172.6mV
51.32ns   797.4mV    1.064V     68.58mV
82.69ns   191.8mV    943mV      41.19mV
95.11ns   101.6mV    878.2mV    39.93mV
213.4ns   56.25mV    235.2mV    38.76mV
334.1ns   55.92mV    115.1mV    38.77mV
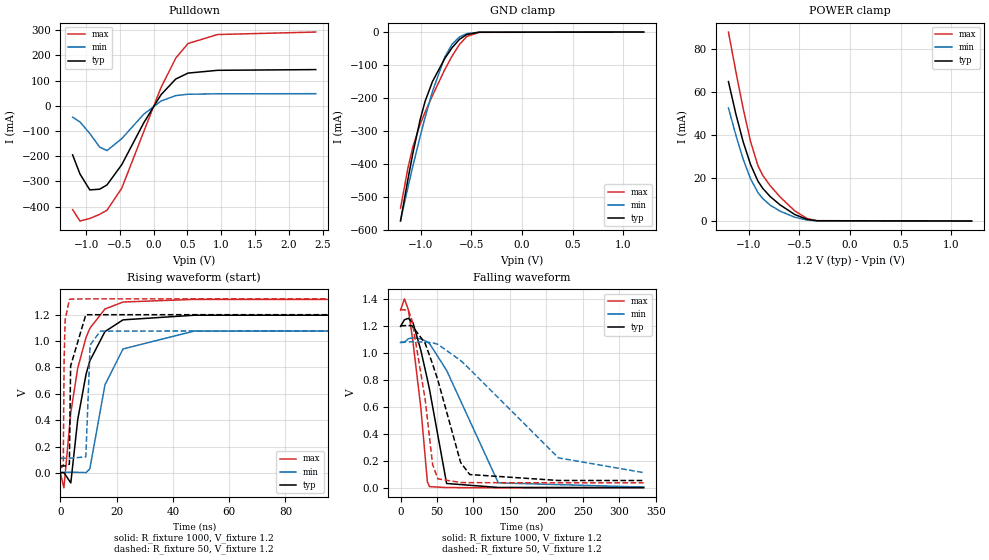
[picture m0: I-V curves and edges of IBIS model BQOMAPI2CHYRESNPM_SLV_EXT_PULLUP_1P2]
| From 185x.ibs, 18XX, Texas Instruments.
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|   Model Cell BQOMAPI2CHYRESNPM_SLV_EXT_PULLUP_1P2
|BQOMAPI2CHYRESNPM_SLV_EXT_PULLUP_1P2
[Model]   BQOMAPI2CHYRESNPM_SLV_EXT_PULLUP_1P2
Model_type   I/O_open_drain
Polarity   Non-Inverting
Enable   Active-Low
Vinl =  0.36
Vinh =  0.84
Cref =  400.0000PF
Rref =  1000.0000
Vref =  1.8V
Vmeas =  0.6
C_comp   3.806929p   3.71689p   3.834943p
[Model Spec]
Vinl   0.36   0.324   0.396
Vinh   0.84   0.756   0.924
[Temperature Range]   25   125   -40
[Voltage Range]   1.2   1.08   1.32
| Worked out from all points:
|   slope of the pulldown table from 0 to 0.18 V, typ, clamps not added: 2.64 ohm
|   GND clamp passes 1 mA (typ) near -0.45 V on its own axis
|   POWER clamp passes 1 mA (typ) near -0.44 V on its own axis
|   rising waveform, R_fixture 1000, V_fixture 1.2: 20-80 % time 7.23ns typ, 7.86ns min, 6.85ns max; typ from 0.003 V to 1.2 V
|   rising waveform, R_fixture 50, V_fixture 1.2: 20-80 % time 433ps typ, 693ps min, 388ps max; typ from 0.054 V to 1.2 V
|   falling waveform, R_fixture 1000, V_fixture 1.2: 20-80 % time 25.5ns typ, 52.3ns min, 15.7ns max; typ from 1.2 V to 0.003 V
|   falling waveform, R_fixture 50, V_fixture 1.2: 20-80 % time 36.8ns typ, 103ns min, 19.4ns max; typ from 1.2 V to 0.054 V
| Nom Voltages:
|   BIASFET=1.2, VDDS=1.2, VDDU=1.2, BUS_VDD=0, VSS=0, VSSS=0
| Min Voltages:
|   BIASFET=1.08, VDDS=1.08, VDDU=1.08, BUS_VDD=0, VSS=0, VSSS=0
| Max Voltages:
|   BIASFET=1.32, VDDS=1.32, VDDU=1.32, BUS_VDD=0, VSS=0, VSSS=0
[POWER_clamp]
|   voltage   I(typ)   I(min)   I(max)
-1.2V     64.99mA    52.68mA    88.09mA
-1.127V   49.93mA    40.08mA    69.72mA
-1.055V   36.97mA    28.84mA    52.47mA
-981.8mV  26.35mA    19.7mA     37.12mA
-909.1mV  18.6mA     13.27mA    25.8mA
-860.6mV  15.16mA    10.42mA    21.24mA
-787.9mV  11.4mA     7.386mA    16.45mA
-690.9mV  7.53mA     4.603mA    11.25mA
-545.5mV  3.018mA    1.76mA     4.721mA
-424.2mV  769.6uA    464.5uA    1.162mA
-327.3mV  128.4uA    90.42uA    147.3uA
1.2V      -1.911uA   -2.519uA   -1.532uA
[Pulldown]
|   voltage   I(typ)   I(min)   I(max)
-1.2V     -194.9mA   -45.23mA   -412mA
-1.091V   -270.8mA   -64.14mA   -457.4mA
-945.5mV  -333.9mA   -110mA     -447.3mA
-800mV    -331.1mA   -163.7mA   -431.1mA
-690.9mV  -314.2mA   -177.8mA   -414.5mA
-472.7mV  -233.9mA   -130.5mA   -327.6mA
-145.5mV  -67.17mA   -33.06mA   -101.9mA
109.1mV   44.04mA    18.76mA    72.48mA
327.3mV   106.3mA    40.55mA    189.3mA
509.1mV   129.8mA    45.8mA     247.2mA
945.5mV   140.8mA    47.59mA    282.9mA
2.4V      143.7mA    48.04mA    292.8mA
[GND_clamp]
|   voltage   I(typ)   I(min)   I(max)
-1.2V     -573mA     -571.2mA   -534.1mA
-1.127V   -446.8mA   -471.5mA   -412.5mA
-1.079V   -368.8mA   -407.4mA   -349mA
-1.006V   -265.4mA   -316mA     -279.3mA
-957.6mV  -210.2mA   -258.9mA   -243.1mA
-884.8mV  -150.2mA   -180.4mA   -192.7mA
-763.6mV  -80.37mA   -75.96mA   -114.1mA
-690.9mV  -47.36mA   -36.81mA   -72.68mA
-618.2mV  -22.24mA   -15mA      -37.68mA
-545.5mV  -7.311mA   -4.854mA   -13.33mA
-424.2mV  -595.6uA   -473.2uA   -921.5uA
1.2V      4.041uA    4.733uA    3.888uA
[Ramp]
| variable   typ   min   max
dV/dt_f 0.73718075/28.027133n 0.65207483/58.333094n 0.82017063/17.165219n
dV/dt_r 0.10246575/0.19931393n 82.981175m/0.51391683n  0.1054655/96.663125p
R_load = 528.0
[Rising Waveform]
R_fixture = 1000
V_fixture = 1.2
V_fixture_min = 1.08
V_fixture_max = 1.32
|   time   V(typ)   V(min)   V(max)
0s        2.739mV    5.552mV    0V
1.233ns   2.739mV    5.552mV    -112mV
3.684ns   -74.46mV   5.552mV    459.8mV
6.144ns   405.2mV    5.551mV    795.4mV
9.105ns   748.7mV    3.573mV    1.028V
10.46ns   850.8mV    32.88mV    1.097V
15.82ns   1.072V     668.4mV    1.243V
22.25ns   1.161V     940.3mV    1.296V
47.55ns   1.196V     1.076V     1.316V
333.5ns   1.196V     1.076V     1.316V
[Rising Waveform]
R_fixture = 50
V_fixture = 1.2
V_fixture_min = 1.08
V_fixture_max = 1.32
|   time   V(typ)   V(min)   V(max)
0s        54.34mV    113mV      37.28mV
1.008ns   54.34mV    113mV      54.24mV
1.292ns   54.34mV    113mV      853mV
1.667ns   54.34mV    113mV      1.161V
3.173ns   67.29mV    113mV      1.315V
3.613ns   810.9mV    113mV      1.318V
9.021ns   1.2V       122.6mV    1.32V
10.55ns   1.2V       970.4mV    1.32V
14.24ns   1.2V       1.076V     1.32V
333.4ns   1.2V       1.08V      1.32V
[Falling Waveform]
R_fixture = 1000
V_fixture = 1.2
V_fixture_min = 1.08
V_fixture_max = 1.32
|   time   V(typ)   V(min)   V(max)
0s        1.196V     1.076V     1.316V
5.348ns   1.245V     1.078V     1.4V
10.78ns   1.256V     1.105V     1.32V
17.13ns   1.223V     1.111V     1.078V
27.94ns   1.017V     1.104V     589.4mV
36.82ns   804mV      1.08V      44.74mV
39.76ns   728.6mV    1.069V     9.051mV
63.2ns    32.33mV    870.5mV    2.192mV
134.1ns   2.921mV    36.98mV    0V
333.5ns   2.739mV    5.552mV    0V
[Falling Waveform]
R_fixture = 50
V_fixture = 1.2
V_fixture_min = 1.08
V_fixture_max = 1.32
|   time   V(typ)   V(min)   V(max)
0s        1.2V       1.08V      1.321V
10.78ns   1.203V     1.082V     1.315V
15.83ns   1.201V     1.082V     1.24V
33.74ns   1.071V     1.08V      657.4mV
44ns      916.8mV    1.074V     173mV
51.11ns   800mV      1.064V     66.98mV
82.4ns    188.4mV    943.7mV    39.65mV
94.91ns   98.7mV     879.1mV    38.41mV
216.6ns   54.6mV     222mV      37.28mV
333.4ns   54.34mV    113mV      37.28mV
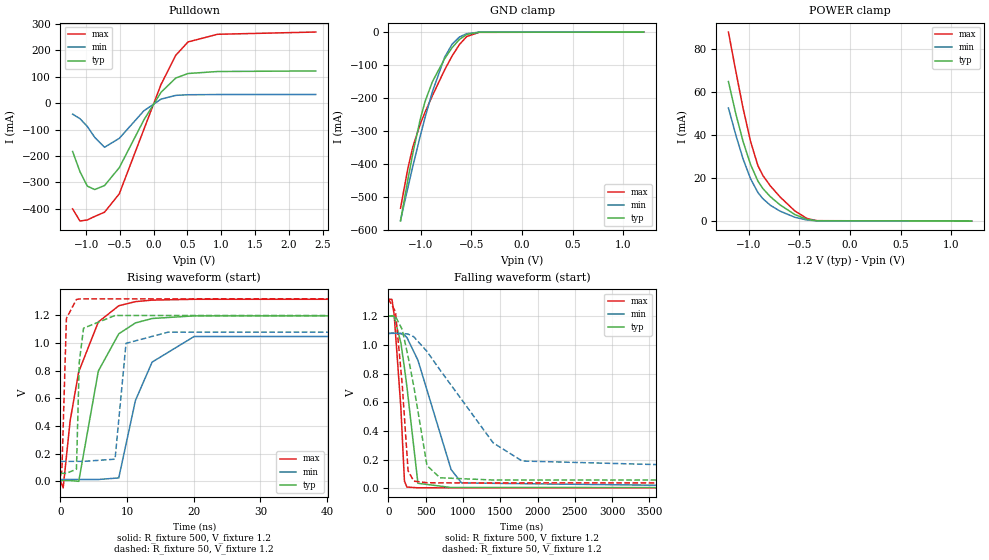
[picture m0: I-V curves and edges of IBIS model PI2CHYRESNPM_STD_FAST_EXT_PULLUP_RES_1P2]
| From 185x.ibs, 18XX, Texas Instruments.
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|   Model Cell PI2CHYRESNPM_STD_FAST_EXT_PULLUP_RES_1P2
|BQOMAPI2CHYRESNPM_STD_FAST_EXT_PULLUP_RES_1P2
[Model]   PI2CHYRESNPM_STD_FAST_EXT_PULLUP_RES_1P2
Model_type   I/O_open_drain
Polarity   Non-Inverting
Enable   Active-Low
Vinl =  0.36
Vinh =  0.84
Cref =  400.0000PF
Rref =  500.0000
Vref =  1.8V
Vmeas =  0.6
C_comp   3.806929p   3.71689p   3.834943p
[Model Spec]
Vinl   0.36   0.324   0.396
Vinh   0.84   0.756   0.924
[Temperature Range]   25   125   -40
[Voltage Range]   1.2   1.08   1.32
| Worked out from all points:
|   slope of the pulldown table from 0 to 0.18 V, typ, clamps not added: 2.87 ohm
|   GND clamp passes 1 mA (typ) near -0.45 V on its own axis
|   POWER clamp passes 1 mA (typ) near -0.44 V on its own axis
|   rising waveform, R_fixture 500, V_fixture 1.2: 20-80 % time 3.72ns typ, 4.17ns min, 3.48ns max; typ from 0.006 V to 1.2 V
|   rising waveform, R_fixture 50, V_fixture 1.2: 20-80 % time 437ps typ, 717ps min, 387ps max; typ from 0.058 V to 1.2 V
|   falling waveform, R_fixture 500, V_fixture 1.2: 20-80 % time 160ns typ, 375ns min, 93ns max; typ from 1.2 V to 0.006 V
|   falling waveform, R_fixture 50, V_fixture 1.2: 20-80 % time 226ns typ, 777ns min, 111ns max; typ from 1.2 V to 0.058 V
| Nom Voltages:
|   BIASFET=1.2, VDDS=1.2, VDDU=1.2, BUS_VDD=0, VSS=0, VSSS=0
| Min Voltages:
|   BIASFET=1.08, VDDS=1.08, VDDU=1.08, BUS_VDD=0, VSS=0, VSSS=0
| Max Voltages:
|   BIASFET=1.32, VDDS=1.32, VDDU=1.32, BUS_VDD=0, VSS=0, VSSS=0
[POWER_clamp]
|   voltage   I(typ)   I(min)   I(max)
-1.2V     64.99mA    52.68mA    88.09mA
-1.127V   49.93mA    40.08mA    69.72mA
-1.055V   36.97mA    28.84mA    52.47mA
-981.8mV  26.35mA    19.7mA     37.12mA
-909.1mV  18.6mA     13.27mA    25.8mA
-860.6mV  15.16mA    10.42mA    21.24mA
-787.9mV  11.4mA     7.386mA    16.45mA
-690.9mV  7.53mA     4.603mA    11.25mA
-545.5mV  3.018mA    1.76mA     4.721mA
-424.2mV  769.6uA    464.5uA    1.162mA
-327.3mV  128.4uA    90.42uA    147.3uA
1.2V      -1.911uA   -2.519uA   -1.532uA
[Pulldown]
|   voltage   I(typ)   I(min)   I(max)
-1.2V     -182.8mA   -41.69mA   -399.6mA
-1.091V   -259.2mA   -58.84mA   -445.6mA
-981.8mV  -313.8mA   -88.38mA   -441.6mA
-872.7mV  -326.6mA   -129.3mA   -428.3mA
-727.3mV  -311.5mA   -167mA     -412.3mA
-509.1mV  -244.1mA   -133.2mA   -342.9mA
-145.5mV  -64.03mA   -29.26mA   -99.8mA
109.1mV   40.86mA    15.03mA    70.45mA
327.3mV   94.79mA    29.27mA    180.8mA
509.1mV   111.9mA    31.57mA    231.2mA
945.5mV   119.4mA    32.37mA    260.1mA
2.4V      121.6mA    32.65mA    268.6mA
[GND_clamp]
|   voltage   I(typ)   I(min)   I(max)
-1.2V     -573mA     -571.2mA   -534.1mA
-1.127V   -446.8mA   -471.5mA   -412.5mA
-1.079V   -368.8mA   -407.4mA   -349mA
-1.006V   -265.4mA   -316mA     -279.3mA
-957.6mV  -210.2mA   -258.9mA   -243.1mA
-884.8mV  -150.2mA   -180.4mA   -192.7mA
-763.6mV  -80.37mA   -75.96mA   -114.1mA
-690.9mV  -47.36mA   -36.81mA   -72.68mA
-618.2mV  -22.24mA   -15mA      -37.68mA
-545.5mV  -7.311mA   -4.854mA   -13.33mA
-424.2mV  -595.7uA   -473.2uA   -921.5uA
1.2V      4.041uA    4.733uA    3.888uA
[Ramp]
| variable   typ   min   max
dV/dt_f 0.71940328/0.1608273u  0.6411206/0.37250105u 0.79486715/93.851669n
dV/dt_r 0.10165098/0.20612657n 82.278455m/0.52692629n 0.10449814/98.37411p
R_load = 528.00
[Rising Waveform]
R_fixture = 500
V_fixture = 1.2
V_fixture_min = 1.08
V_fixture_max = 1.32
|   time   V(typ)   V(min)   V(max)
0s        5.823mV    13.39mV    3.262mV
407.4ps   5.823mV    13.39mV    -47.12mV
1.453ns   5.821mV    13.39mV    438.1mV
2.742ns   0V         13.39mV    793.1mV
5.685ns   798.2mV    13.39mV    1.153V
8.747ns   1.067V     24.72mV    1.27V
11.25ns   1.146V     585.5mV    1.3V
13.75ns   1.178V     862.6mV    1.311V
20.06ns   1.197V     1.048V     1.317V
5us       1.198V     1.078V     1.318V
[Rising Waveform]
R_fixture = 50
V_fixture = 1.2
V_fixture_min = 1.08
V_fixture_max = 1.32
|   time   V(typ)   V(min)   V(max)
0s        58.16mV    144.4mV    38.52mV
214.2ps   58.16mV    144.4mV    76.24mV
895.8ps   58.16mV    144.4mV    1.179V
2.401ns   87.89mV    144.4mV    1.316V
2.821ns   861mV      144.4mV    1.319V
3.464ns   1.108V     144.4mV    1.32V
8.191ns   1.2V       160.3mV    1.32V
9.835ns   1.2V       998.2mV    1.32V
16.14ns   1.2V       1.079V     1.32V
5us       1.2V       1.08V      1.32V
[Falling Waveform]
R_fixture = 500
V_fixture = 1.2
V_fixture_min = 1.08
V_fixture_max = 1.32
|   time   V(typ)   V(min)   V(max)
0s        1.198V     1.078V     1.318V
48.51ns   1.203V     1.081V     1.316V
78.31ns   1.198V     1.081V     1.207V
167.7ns   1.013V     1.078V     560.1mV
215.7ns   838.8mV    1.068V     50.84mV
248.3ns   709.9mV    1.051V     9.386mV
396.3ns   35.66mV    893mV      4.263mV
840.5ns   6.109mV    132mV      3.865mV
981.2ns   5.944mV    38.08mV    3.862mV
5us       5.823mV    13.41mV    3.861mV
[Falling Waveform]
R_fixture = 50
V_fixture = 1.2
V_fixture_min = 1.08
V_fixture_max = 1.32
|   time   V(typ)   V(min)   V(max)
0s        1.2V       1.08V      1.32V
95.23ns   1.198V     1.08V      1.231V
186.1ns   1.106V     1.079V     721.2mV
264.2ns   918.2mV    1.075V     123.4mV
341ns     710.6mV    1.056V     50.42mV
517.2ns   159.6mV    954.2mV    39.67mV
691.1ns   74.05mV    826mV      38.45mV
1.405us   58.37mV    317.3mV    38.21mV
1.793us   58.18mV    190.8mV    38.21mV
5us       58.16mV    146.4mV    38.21mV
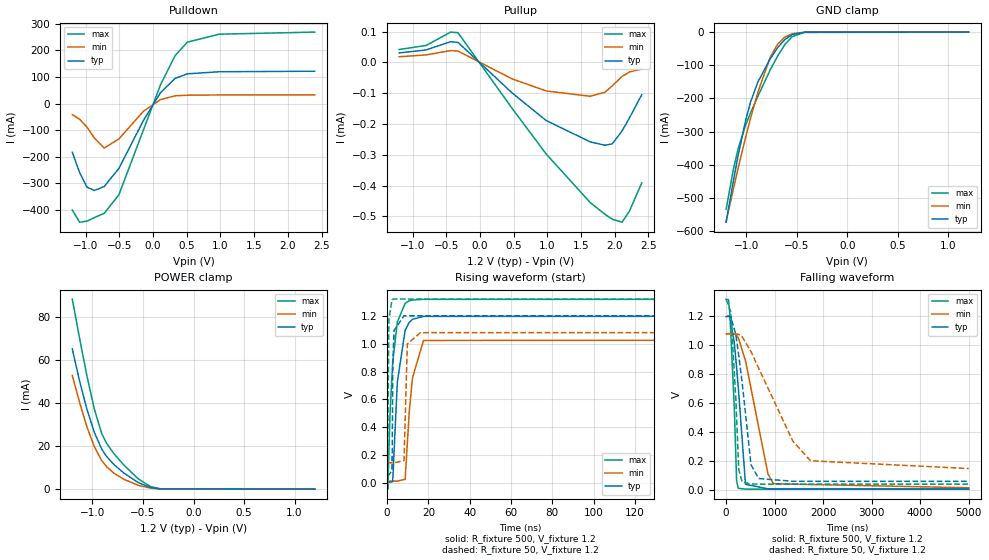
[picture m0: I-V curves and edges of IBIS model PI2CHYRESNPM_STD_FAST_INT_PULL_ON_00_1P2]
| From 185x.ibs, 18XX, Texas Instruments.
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|   Model Cell PI2CHYRESNPM_STD_FAST_INT_PULL_ON_00_1P2
|BQOMAPI2CHYRESNPM_STD_FAST_INT_PULL_ON_00_1P2
[Model]   PI2CHYRESNPM_STD_FAST_INT_PULL_ON_00_1P2
Model_type   I/O
Polarity   Non-Inverting
Enable   Active-Low
Vinl =  0.36
Vinh =  0.84
Cref =  400.0000PF
Rref =  500.0000
Vref =  1.8V
Vmeas =  0.6
C_comp   3.806929p   3.71689p   3.834943p
[Model Spec]
Vinl   0.36   0.324   0.396
Vinh   0.84   0.756   0.924
[Temperature Range]   25   125   -40
[Voltage Range]   1.2   1.08   1.32
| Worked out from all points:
|   slope of the pulldown table from 0 to 0.18 V, typ, clamps not added: 2.87 ohm
|   slope of the pullup table from 0 to 0.18 V, typ, clamps not added: 4.66 kohm
|   GND clamp passes 1 mA (typ) near -0.45 V on its own axis
|   POWER clamp passes 1 mA (typ) near -0.44 V on its own axis
|   rising waveform, R_fixture 500, V_fixture 1.2: 20-80 % time 3.37ns typ, 3.95ns min, 3.01ns max; typ from 0.006 V to 1.2 V
|   rising waveform, R_fixture 50, V_fixture 1.2: 20-80 % time 429ps typ, 715ps min, 379ps max; typ from 0.059 V to 1.2 V
|   falling waveform, R_fixture 500, V_fixture 1.2: 20-80 % time 162ns typ, 378ns min, 93.5ns max; typ from 1.2 V to 0.006 V
|   falling waveform, R_fixture 50, V_fixture 1.2: 20-80 % time 229ns typ, 779ns min, 111ns max; typ from 1.2 V to 0.059 V
| Nom Voltages:
|   BIASFET=1.2, VDDS=1.2, VDDU=1.2, BUS_VDD=0, VSS=0, VSSS=0
| Min Voltages:
|   BIASFET=1.08, VDDS=1.08, VDDU=1.08, BUS_VDD=0, VSS=0, VSSS=0
| Max Voltages:
|   BIASFET=1.32, VDDS=1.32, VDDU=1.32, BUS_VDD=0, VSS=0, VSSS=0
[POWER_clamp]
|   voltage   I(typ)   I(min)   I(max)
-1.2V     64.99mA    52.68mA    88.09mA
-1.127V   49.93mA    40.08mA    69.72mA
-1.055V   36.97mA    28.84mA    52.47mA
-981.8mV  26.35mA    19.7mA     37.12mA
-909.1mV  18.6mA     13.27mA    25.8mA
-860.6mV  15.16mA    10.42mA    21.24mA
-787.9mV  11.4mA     7.386mA    16.45mA
-690.9mV  7.53mA     4.603mA    11.25mA
-545.5mV  3.018mA    1.76mA     4.721mA
-424.2mV  769.6uA    464.5uA    1.162mA
-327.3mV  128.4uA    90.42uA    147.3uA
1.2V      -1.911uA   -2.519uA   -1.532uA
[Pulldown]
|   voltage   I(typ)   I(min)   I(max)
-1.2V     -182.9mA   -41.72mA   -400mA
-1.091V   -259.3mA   -58.88mA   -445.9mA
-981.8mV  -314mA     -88.44mA   -442.1mA
-872.7mV  -326.8mA   -129.4mA   -428.8mA
-727.3mV  -311.8mA   -167.1mA   -412.8mA
-509.1mV  -244.3mA   -133.3mA   -343.4mA
-145.5mV  -64.26mA   -29.37mA   -100.2mA
109.1mV   40.65mA    14.93mA    70.09mA
327.3mV   94.62mA    29.19mA    180.5mA
509.1mV   111.8mA    31.51mA    231mA
981.8mV   119.6mA    32.38mA    260.8mA
2.4V      121.6mA    32.66mA    268.7mA
[Pullup]
|   voltage   I(typ)   I(min)   I(max)
-1.2V     30.77uA    18.3uA     41.81uA
-800mV    40.53uA    24.31uA    55.05uA
-436.4mV  67.2uA     38.25uA    98.41uA
-327.3mV  64.89uA    36.82uA    96.31uA
472.7mV   -98.5uA    -53.27uA   -148.3uA
981.8mV   -188.9uA   -92.82uA   -297.6uA
1.636V    -258.2uA   -110.1uA   -455.4uA
1.855V    -269.2uA   -96.82uA   -493.6uA
1.964V    -264.5uA   -75.96uA   -509.6uA
2.109V    -222.3uA   -45.37uA   -519.1uA
2.218V    -180.4uA   -31.08uA   -483.1uA
2.4V      -105.1uA   -21.72uA   -391.6uA
[GND_clamp]
|   voltage   I(typ)   I(min)   I(max)
-1.2V     -573mA     -571.2mA   -534.1mA
-1.127V   -446.8mA   -471.5mA   -412.5mA
-1.079V   -368.8mA   -407.4mA   -349mA
-1.006V   -265.4mA   -316mA     -279.3mA
-957.6mV  -210.2mA   -258.9mA   -243.1mA
-884.8mV  -150.2mA   -180.4mA   -192.7mA
-763.6mV  -80.37mA   -75.96mA   -114.1mA
-690.9mV  -47.36mA   -36.81mA   -72.68mA
-618.2mV  -22.24mA   -15mA      -37.68mA
-545.5mV  -7.311mA   -4.854mA   -13.33mA
-424.2mV  -595.7uA   -473.2uA   -921.5uA
1.2V      4.041uA    4.733uA    3.888uA
[Ramp]
| variable   typ   min   max
dV/dt_f 0.71881475/0.16200546u 0.64071702/0.37556651u 0.79383333/94.309956n
dV/dt_r 0.15342875/4.4704332n 0.10081085/5.4129882n 0.19873602/3.7431095n
R_load = 528.00
[Rising Waveform]
R_fixture = 500
V_fixture = 1.2
V_fixture_min = 1.08
V_fixture_max = 1.32
|   time   V(typ)   V(min)   V(max)
0s        6.354mV    14mV       3.827mV
366.6ps   6.354mV    14mV       -43.98mV
1.43ns    6.353mV    14mV       498mV
2.726ns   10.54mV    14mV       866.4mV
4.962ns   723.8mV    14mV       1.155V
8.746ns   1.096V     26.63mV    1.29V
10.75ns   1.153V     515mV      1.307V
12.31ns   1.175V     755.2mV    1.313V
17.64ns   1.196V     1.023V     1.318V
5us       1.198V     1.078V     1.318V
[Rising Waveform]
R_fixture = 50
V_fixture = 1.2
V_fixture_min = 1.08
V_fixture_max = 1.32
|   time   V(typ)   V(min)   V(max)
0s        58.7mV     145.2mV    39.15mV
214.2ps   58.7mV     145.2mV    77.72mV
876ps     58.7mV     145.2mV    1.177V
2.401ns   88.84mV    145.2mV    1.316V
2.82ns    866mV      145.2mV    1.319V
3.374ns   1.094V     145.2mV    1.32V
8.191ns   1.2V       161.2mV    1.32V
9.814ns   1.2V       997.8mV    1.32V
16.14ns   1.2V       1.079V     1.32V
5us       1.2V       1.08V      1.32V
[Falling Waveform]
R_fixture = 500
V_fixture = 1.2
V_fixture_min = 1.08
V_fixture_max = 1.32
|   time   V(typ)   V(min)   V(max)
0s        1.198V     1.078V     1.318V
48.66ns   1.203V     1.081V     1.316V
78.61ns   1.198V     1.081V     1.211V
168.5ns   1.018V     1.078V     570.9mV
216.8ns   844mV      1.068V     58.97mV
252.9ns   701.9mV    1.05V      10.04mV
399.5ns   37.99mV    893.5mV    4.872mV
864ns     6.631mV    108.6mV    4.428mV
974.8ns   6.494mV    42.16mV    4.426mV
5us       6.354mV    14.02mV    4.425mV
[Falling Waveform]
R_fixture = 50
V_fixture = 1.2
V_fixture_min = 1.08
V_fixture_max = 1.32
|   time   V(typ)   V(min)   V(max)
0s        1.2V       1.08V      1.32V
95.26ns   1.198V     1.08V      1.231V
200.4ns   1.074V     1.079V     629.9mV
260.7ns   928.3mV    1.075V     141.2mV
330.5ns   741.6mV    1.059V     53.62mV
514ns     173.2mV    956.9mV    40.37mV
671.4ns   78.03mV    841.4mV    39.06mV
1.373us   58.96mV    338.5mV    38.77mV
1.739us   58.73mV    200.9mV    38.77mV
5us       58.7mV     147.2mV    38.76mV
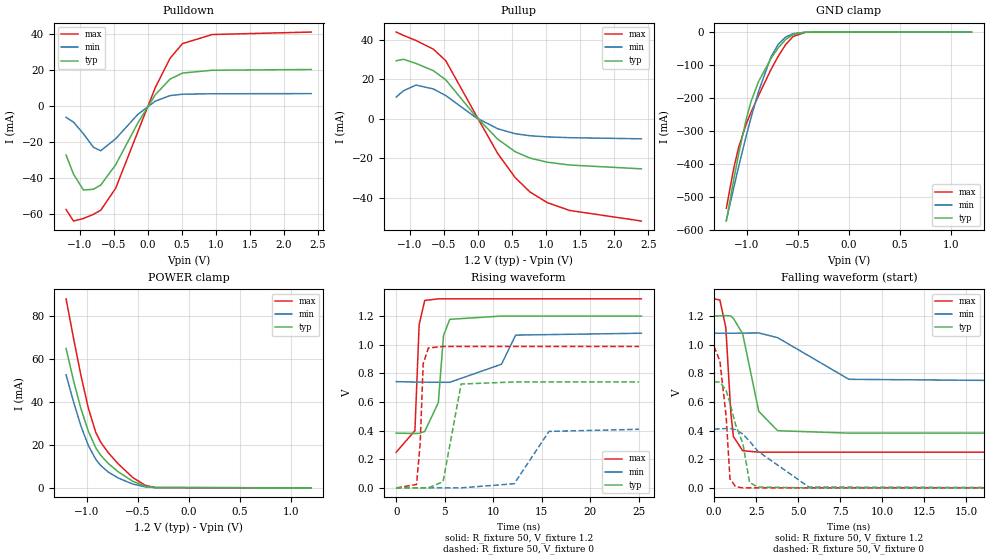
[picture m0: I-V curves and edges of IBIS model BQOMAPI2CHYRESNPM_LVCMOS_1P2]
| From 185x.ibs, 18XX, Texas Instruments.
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|   Model Cell BQOMAPI2CHYRESNPM_LVCMOS_1P2
|BQOMAPI2CHYRESNPM_LVCMOS_1P2
[Model]   BQOMAPI2CHYRESNPM_LVCMOS_1P2
Model_type   I/O
Polarity   Non-Inverting
Enable   Active-Low
Vinl =  0.36
Vinh =  0.84
Cref =  15.0000PF
Rref =  150.0000
Vref =  0V
Vmeas =  0.6
C_comp   3.806929p   3.71689p   3.834943p
[Model Spec]
Vinl   0.36   0.324   0.396
Vinh   0.84   0.756   0.924
[Temperature Range]   25   125   -40
[Voltage Range]   1.2   1.08   1.32
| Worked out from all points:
|   slope of the pulldown table from 0 to 0.18 V, typ, clamps not added: 18.7 ohm
|   slope of the pullup table from 0 to 0.18 V, typ, clamps not added: 26.7 ohm
|   GND clamp passes 1 mA (typ) near -0.45 V on its own axis
|   POWER clamp passes 1 mA (typ) near -0.44 V on its own axis
|   rising waveform, R_fixture 50, V_fixture 1.2: 20-80 % time 1.01ns typ, 3.03ns min, 327ps max; typ from 0.382 V to 1.2 V
|   rising waveform, R_fixture 50, V_fixture 0: 20-80 % time 666ps typ, 1.61ns min, 350ps max; typ from 0 V to 0.74 V
|   falling waveform, R_fixture 50, V_fixture 1.2: 20-80 % time 798ps typ, 1.84ns min, 326ps max; typ from 1.2 V to 0.382 V
|   falling waveform, R_fixture 50, V_fixture 0: 20-80 % time 975ps typ, 2.62ns min, 424ps max; typ from 0.74 V to 0 V
| Nom Voltages:
|   BIASFET=1.2, VDDS=1.2, VDDU=1.2, BUS_VDD=0, VSS=0, VSSS=0
| Min Voltages:
|   BIASFET=1.08, VDDS=1.08, VDDU=1.08, BUS_VDD=0, VSS=0, VSSS=0
| Max Voltages:
|   BIASFET=1.32, VDDS=1.32, VDDU=1.32, BUS_VDD=0, VSS=0, VSSS=0
[POWER_clamp]
|   voltage   I(typ)   I(min)   I(max)
-1.2V     64.99mA    52.68mA    88.09mA
-1.127V   49.93mA    40.08mA    69.72mA
-1.055V   36.97mA    28.84mA    52.47mA
-981.8mV  26.35mA    19.7mA     37.12mA
-909.1mV  18.6mA     13.27mA    25.8mA
-860.6mV  15.16mA    10.42mA    21.24mA
-787.9mV  11.4mA     7.386mA    16.45mA
-690.9mV  7.53mA     4.603mA    11.25mA
-545.5mV  3.018mA    1.76mA     4.721mA
-424.2mV  769.6uA    464.5uA    1.162mA
-327.3mV  128.4uA    90.42uA    147.3uA
1.2V      -1.911uA   -2.519uA   -1.532uA
[Pulldown]
|   voltage   I(typ)   I(min)   I(max)
-1.2V     -27.38mA   -6.362mA   -57.77mA
-1.091V   -38mA      -9.025mA   -64.14mA
-945.5mV  -46.83mA   -15.47mA   -62.73mA
-800mV    -46.45mA   -23mA      -60.45mA
-690.9mV  -44.08mA   -24.98mA   -58.11mA
-472.7mV  -32.82mA   -18.34mA   -45.94mA
-145.5mV  -9.435mA   -4.662mA   -14.29mA
109.1mV   6.195mA    2.658mA    10.17mA
327.3mV   14.98mA    5.779mA    26.59mA
509.1mV   18.32mA    6.547mA    34.75mA
945.5mV   19.91mA    6.81mA     39.82mA
2.4V      20.32mA    6.875mA    41.21mA
[Pullup]
|   voltage   I(typ)   I(min)   I(max)
-1.2V     29.35mA    11.01mA    43.86mA
-1.091V   30.09mA    14.23mA    42.11mA
-909.1mV  27.99mA    17.07mA    39.59mA
-654.5mV  24.33mA    15.09mA    35.19mA
-472.7mV  19.72mA    11.78mA    29.41mA
-36.36mV  1.487mA    788.1uA    2.392mA
290.9mV   -10.31mA   -5.028mA   -17.54mA
545.5mV   -16.57mA   -7.519mA   -29.63mA
763.6mV   -19.83mA   -8.544mA   -36.96mA
1.018V    -21.91mA   -9.128mA   -42.34mA
1.345V    -23.34mA   -9.527mA   -46.29mA
2.4V      -25.27mA   -10.1mA    -51.64mA
[GND_clamp]
|   voltage   I(typ)   I(min)   I(max)
-1.2V     -573mA     -571.2mA   -534.1mA
-1.127V   -446.8mA   -471.5mA   -412.5mA
-1.079V   -368.8mA   -407.4mA   -349mA
-1.006V   -265.4mA   -316mA     -279.3mA
-957.6mV  -210.2mA   -258.9mA   -243.1mA
-884.8mV  -150.2mA   -180.4mA   -192.7mA
-763.6mV  -80.37mA   -75.96mA   -114.1mA
-690.9mV  -47.36mA   -36.81mA   -72.68mA
-618.2mV  -22.24mA   -15mA      -37.68mA
-545.5mV  -7.311mA   -4.854mA   -13.33mA
-424.2mV  -595.7uA   -473.2uA   -921.5uA
1.2V      4.041uA    4.733uA    3.888uA
[Ramp]
| variable   typ   min   max
dV/dt_f 0.49281774/0.8035115n 0.20420642/1.8654958n 0.64495668/0.3287543n
dV/dt_r 0.44457959/0.66907529n 0.24589987/1.6209847n 0.59374771/0.35157781n
R_load = 50.0000
[Rising Waveform]
R_fixture = 50
V_fixture = 1.2
V_fixture_min = 1.08
V_fixture_max = 1.32
|   time   V(typ)   V(min)   V(max)
0s        382.3mV    742mV      249.1mV
1.928ns   379.4mV    738.9mV    399.8mV
2.364ns   380.7mV    738.6mV    1.139V
2.936ns   393.6mV    738.2mV    1.309V
4.341ns   595.3mV    737.4mV    1.32V
4.876ns   1.064V     737.1mV    1.32V
5.517ns   1.177V     737.1mV    1.32V
10.85ns   1.2V       863.6mV    1.32V
12.31ns   1.2V       1.067V     1.32V
25.26ns   1.2V       1.08V      1.32V
[Rising Waveform]
R_fixture = 50
V_fixture = 0
V_fixture_min = 0
V_fixture_max = 0
|   time   V(typ)   V(min)   V(max)
0s        0V         0V         0V
2.096ns   0V         0V         23.42mV
2.476ns   0V         0V         315.6mV
2.779ns   0V         0V         866.4mV
3.317ns   0V         0V         977.3mV
4.829ns   42.82mV    0V         987.5mV
6.688ns   725.1mV    0V         987.6mV
12.16ns   739.6mV    28.87mV    987.6mV
15.74ns   739.6mV    394.4mV    987.6mV
25.02ns   739.6mV    409mV      987.6mV
[Falling Waveform]
R_fixture = 50
V_fixture = 1.2
V_fixture_min = 1.08
V_fixture_max = 1.32
|   time   V(typ)   V(min)   V(max)
0s        1.2V       1.08V      1.32V
345.3ps   1.201V     1.08V      1.312V
697.1ps   1.203V     1.08V      1.12V
995.3ps   1.2V       1.08V      524.1mV
1.148ns   1.184V     1.08V      358.7mV
1.697ns   1.077V     1.081V     259.4mV
2.656ns   534.4mV    1.082V     249.4mV
3.778ns   399.2mV    1.049V     249.2mV
8.014ns   382.3mV    758.1mV    249.1mV
25.26ns   382.3mV    742.1mV    249.1mV
[Falling Waveform]
R_fixture = 50
V_fixture = 0
V_fixture_min = 0
V_fixture_max = 0
|   time   V(typ)   V(min)   V(max)
0s        739.6mV    409.7mV    987.6mV
345.3ps   739.3mV    412.1mV    886.2mV
715.5ps   681.2mV    414.6mV    502.4mV
946.3ps   592.3mV    414.5mV    62.45mV
1.285ns   437.9mV    406.6mV    8.146mV
1.706ns   313mV      375.7mV    0V
2.109ns   38.2mV     325.6mV    0V
2.595ns   5.591mV    256.7mV    0V
5.635ns   0V         5.467mV    0V
25.02ns   0V         0V         0V
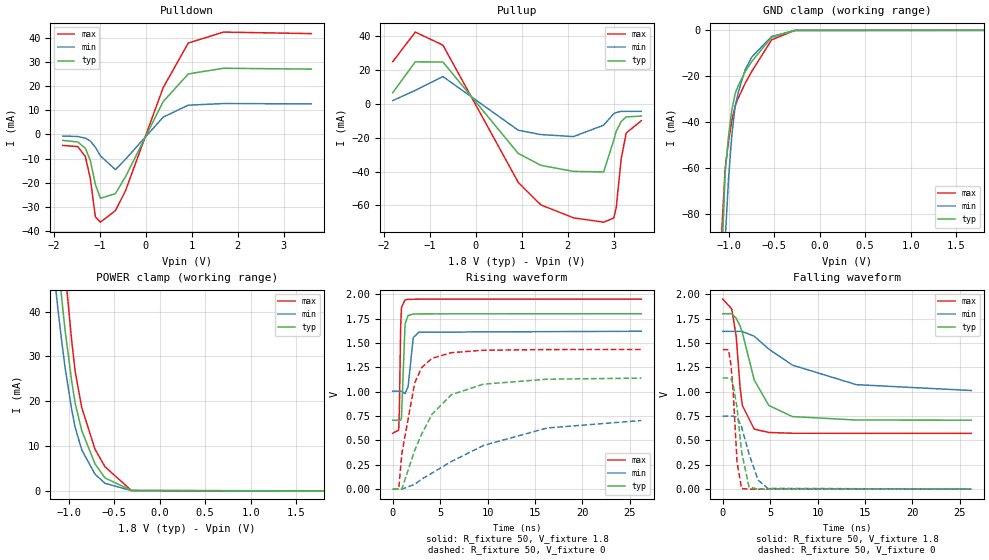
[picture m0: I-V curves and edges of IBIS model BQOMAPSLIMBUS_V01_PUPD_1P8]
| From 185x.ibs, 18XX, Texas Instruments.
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|   Model Cell BQOMAPSLIMBUS_V01_PUPD_1P8
|BQOMAPSLIMBUS_V01_PUPD_1P8
[Model]   BQOMAPSLIMBUS_V01_PUPD_1P8
Model_type   I/O
Polarity   Non-Inverting
Enable   Active-Low
Vinl =  0.63
Vinh =  1.17
Cref =  15pF
Rref =  100.0000M
Vref =  0V
Vmeas =  0.9
C_comp   1.636035p   1.481314p   1.795483p
[Model Spec]
Vinl   0.63   0.567   0.6825
Vinh   1.17   1.053   1.2675
[Temperature Range]   25   125   -40
[Voltage Range]   1.8   1.62   1.95
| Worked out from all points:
|   slope of the pulldown table from 0 to 0.27 V, typ, clamps not added: 27.2 ohm
|   slope of the pullup table from 0 to 0.27 V, typ, clamps not added: 26.2 ohm
|   GND clamp passes 1 mA (typ) near -0.44 V on its own axis
|   POWER clamp passes 1 mA (typ) near -0.47 V on its own axis
|   rising waveform, R_fixture 50, V_fixture 1.8: 20-80 % time 195ps typ, 355ps min, 132ps max; typ from 0.707 V to 1.8 V
|   rising waveform, R_fixture 50, V_fixture 0: 20-80 % time 3.75ns typ, 9.33ns min, 1.65ns max; typ from 0 V to 1.14 V
|   falling waveform, R_fixture 50, V_fixture 1.8: 20-80 % time 2.15ns typ, 6.71ns min, 810ps max; typ from 1.8 V to 0.708 V
|   falling waveform, R_fixture 50, V_fixture 0: 20-80 % time 769ps typ, 1.35ns min, 505ps max; typ from 1.14 V to 0 V
| Nom Voltages:
|   BIASFET=1.8, VBBNW=1.1, VDD=1.1, VDDS=1.8, VDDU=1.05, VSS=0, VSSS=0
| Min Voltages:
|   BIASFET=1.62, VBBNW=0.99, VDD=0.99, VDDS=1.62, VDDU=0.95, VSS=0,
|   VSSS=0
| Max Voltages:
|   BIASFET=1.95, VBBNW=1.21, VDD=1.21, VDDS=1.95, VDDU=1.16, VSS=0,
|   VSSS=0
[POWER_clamp]
|   voltage   I(typ)   I(min)   I(max)
-1.8V     243.4mA    191.6mA    307.8mA
-1.182V   67.09mA    52.86mA    87.7mA
-1.109V   50.21mA    39.28mA    67.42mA
-1.073V   42.63mA    33.1mA     57.9mA
-1.036V   35.53mA    27.26mA    48.72mA
-963.6mV  24.25mA    17.98mA    33.21mA
-927.3mV  19.59mA    14.17mA    26.67mA
-854.5mV  13.42mA    9.147mA    18.56mA
-709.1mV  6.025mA    3.712mA    9.28mA
-600mV    2.9mA      1.702mA    5.383mA
-309.1mV  90.44uA    54uA       81.09uA
1.8V      -20.23nA   -5.391uA   -126.9nA
[Pulldown]
|   voltage   I(typ)   I(min)   I(max)
-1.8V     -2.487mA   -681.8uA   -4.563mA
-1.473V   -3.152mA   -884.6uA   -5.067mA
-1.309V   -5.739mA   -1.559mA   -9.111mA
-1.2V     -10.86mA   -2.75mA    -18.26mA
-1.091V   -20.62mA   -5.298mA   -34.07mA
-981.8mV  -26.44mA   -8.861mA   -36.32mA
-654.5mV  -24.5mA    -14.59mA   -31.53mA
-436.4mV  -17.53mA   -10.31mA   -23.34mA
381.8mV   13.54mA    7.116mA    19.31mA
927.3mV   25mA       12.07mA    37.77mA
1.691V    27.34mA    12.75mA    42.3mA
3.6V      26.98mA    12.6mA     41.67mA
[Pullup]
|   voltage   I(typ)   I(min)   I(max)
-1.8V     6.703mA    2.011mA    25.06mA
-1.309V   24.97mA    8.116mA    42.58mA
-709.1mV  24.88mA    16.26mA    34.85mA
927.3mV   -29.26mA   -15.5mA    -46.38mA
1.418V    -36.27mA   -18.07mA   -59.68mA
2.127V    -39.86mA   -19.24mA   -67.35mA
2.782V    -40.19mA   -12.5mA    -69.92mA
3V        -21.49mA   -5.748mA   -67.44mA
3.055V    -16.07mA   -5.025mA   -61.28mA
3.164V    -10.24mA   -4.312mA   -32.15mA
3.273V    -7.595mA   -4.315mA   -17.08mA
3.6V      -7.13mA    -4.323mA   -9.859mA
[GND_clamp]
|   voltage   I(typ)   I(min)   I(max)
-1.8V     -5.104A    -4.871A    -5.301A
-1.073V   -98.98mA   -143.7mA   -86.45mA
-1.036V   -61.74mA   -90.7mA    -59.73mA
-1V       -46.06mA   -64.71mA   -48.16mA
-963.6mV  -34.65mA   -45.53mA   -39.21mA
-927.3mV  -27.49mA   -33.15mA   -32.87mA
-890.9mV  -23.84mA   -26.64mA   -29.21mA
-818.2mV  -18.08mA   -17.22mA   -23.12mA
-745.5mV  -13.56mA   -11.62mA   -17.89mA
-527.3mV  -3.048mA   -2.672mA   -4.127mA
-272.7mV  -20.27uA   -57.26uA   -26.95uA
1.8V      7.706nA    2.326uA    10.8nA
[Ramp]
| variable   typ   min   max
dV/dt_f 0.65853489/2.1539745n 0.37104228/6.9049395n 0.82967162/0.81410268n
dV/dt_r 0.69043325/3.7816719n 0.45456038/10.826591n 0.86613088/1.6532349n
R_load = 50
[Rising Waveform]
R_fixture = 50
V_fixture = 1.8
V_fixture_min = 1.62
V_fixture_max = 1.95
|   time   V(typ)   V(min)   V(max)
0s        707.1mV    1.005V     573.1mV
633.3ps   707.1mV    1.005V     606.6mV
704.1ps   707.1mV    1.005V     824.4mV
835.3ps   707.1mV    1.005V     1.651V
918.8ps   726.6mV    1.005V     1.863V
1.3ns     1.695V     980.7mV    1.941V
1.623ns   1.781V     1.051V     1.947V
2.168ns   1.796V     1.555V     1.948V
2.753ns   1.798V     1.61V      1.949V
26.2ns    1.8V       1.62V      1.95V
[Rising Waveform]
R_fixture = 50
V_fixture = 0
V_fixture_min = 0
V_fixture_max = 0
|   time   V(typ)   V(min)   V(max)
0s        0V         0V         0V
637ps     0V         0V         0V
959.8ps   0V         0V         364.7mV
2.325ns   400.1mV    50.53mV    1.092V
3.061ns   566.7mV    103.6mV    1.248V
4.139ns   767.9mV    164.7mV    1.342V
6.181ns   969.2mV    283.8mV    1.4V
9.561ns   1.077V     447.8mV    1.425V
16.27ns   1.128V     627.5mV    1.432V
26.2ns    1.139V     704mV      1.433V
[Falling Waveform]
R_fixture = 50
V_fixture = 1.8
V_fixture_min = 1.62
V_fixture_max = 1.95
|   time   V(typ)   V(min)   V(max)
0s        1.8V       1.619V     1.95V
948.9ps   1.8V       1.619V     1.849V
1.417ns   1.753V     1.619V     1.572V
1.833ns   1.673V     1.619V     1.041V
2.072ns   1.606V     1.617V     858.8mV
3.318ns   1.121V     1.569V     616.3mV
4.862ns   858.2mV    1.437V     581.5mV
7.336ns   744.9mV    1.273V     573.7mV
14.08ns   709.2mV    1.072V     572.8mV
26.2ns    707.7mV    1.012V     572.8mV
[Falling Waveform]
R_fixture = 50
V_fixture = 0
V_fixture_min = 0
V_fixture_max = 0
|   time   V(typ)   V(min)   V(max)
0s        1.14V      749mV      1.432V
614.1ps   1.14V      749mV      1.43V
855.7ps   1.138V     749mV      1.282V
1.096ns   1.074V     749mV      1.016V
1.511ns   837.9mV    740mV      278.5mV
1.987ns   383.4mV    639.4mV    7.138mV
2.77ns    22.84mV    363.7mV    0V
3.724ns   0V         93.34mV    0V
4.736ns   0V         8.804mV    0V
26.2ns    0V         0V         0V
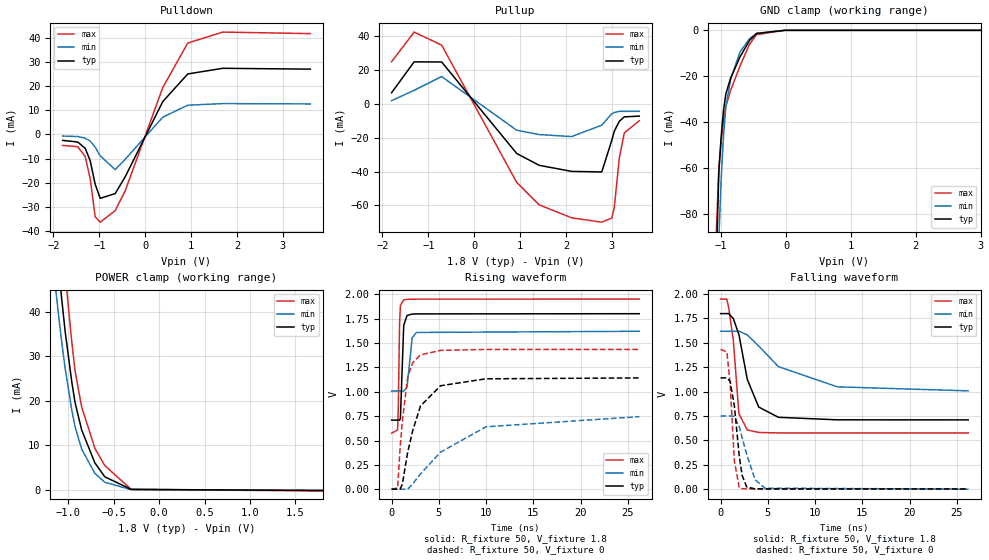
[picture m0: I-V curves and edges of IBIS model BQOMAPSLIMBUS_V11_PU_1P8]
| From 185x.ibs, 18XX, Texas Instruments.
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|   Model Cell BQOMAPSLIMBUS_V11_PU_1P8
|BQOMAPSLIMBUS_V11_PU_1P8
[Model]   BQOMAPSLIMBUS_V11_PU_1P8
Model_type   I/O
Polarity   Non-Inverting
Enable   Active-Low
Vinl =  0.63
Vinh =  1.17
Cref =  15pF
Rref =  100.0000M
Vref =  0V
Vmeas =  0.9
C_comp   1.636035p   1.481314p   1.795483p
[Model Spec]
Vinl   0.63   0.567   0.6825
Vinh   1.17   1.053   1.2675
[Temperature Range]   25   125   -40
[Voltage Range]   1.8   1.62   1.95
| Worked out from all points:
|   slope of the pulldown table from 0 to 0.27 V, typ, clamps not added: 27.2 ohm
|   slope of the pullup table from 0 to 0.27 V, typ, clamps not added: 26.2 ohm
|   GND clamp passes 1 mA (typ) near -0.43 V on its own axis
|   POWER clamp passes 1 mA (typ) near -0.47 V on its own axis
|   rising waveform, R_fixture 50, V_fixture 1.8: 20-80 % time 186ps typ, 346ps min, 128ps max; typ from 0.71 V to 1.8 V
|   rising waveform, R_fixture 50, V_fixture 0: 20-80 % time 2.01ns typ, 5.58ns min, 872ps max; typ from 0.002 V to 1.14 V
|   falling waveform, R_fixture 50, V_fixture 1.8: 20-80 % time 1.53ns typ, 4.79ns min, 674ps max; typ from 1.8 V to 0.71 V
|   falling waveform, R_fixture 50, V_fixture 0: 20-80 % time 735ps typ, 1.31ns min, 497ps max; typ from 1.14 V to 0.002 V
| Nom Voltages:
|   BIASFET=1.8, VBBNW=1.1, VDD=1.1, VDDS=1.8, VDDU=1.05, VSS=0, VSSS=0
| Min Voltages:
|   BIASFET=1.62, VBBNW=0.99, VDD=0.99, VDDS=1.62, VDDU=0.95, VSS=0,
|   VSSS=0
| Max Voltages:
|   BIASFET=1.95, VBBNW=1.21, VDD=1.21, VDDS=1.95, VDDU=1.16, VSS=0,
|   VSSS=0
[POWER_clamp]
|   voltage   I(typ)   I(min)   I(max)
-1.8V     243.4mA    191.6mA    307.8mA
-1.182V   67.16mA    52.88mA    87.81mA
-1.109V   50.28mA    39.31mA    67.52mA
-1.073V   42.7mA     33.13mA    58.01mA
-1.036V   35.6mA     27.29mA    48.83mA
-963.6mV  24.32mA    18.02mA    33.31mA
-927.3mV  19.66mA    14.21mA    26.78mA
-854.5mV  13.49mA    9.184mA    18.66mA
-709.1mV  6.091mA    3.749mA    9.378mA
-600mV    2.963mA    1.738mA    5.478mA
-309.1mV  129.1uA    75.85uA    140.2uA
1.8V      -127.6uA   -66.01uA   -226.6uA
[Pulldown]
|   voltage   I(typ)   I(min)   I(max)
-1.8V     -2.487mA   -681.8uA   -4.563mA
-1.473V   -3.152mA   -884.6uA   -5.068mA
-1.309V   -5.739mA   -1.559mA   -9.113mA
-1.2V     -10.86mA   -2.75mA    -18.27mA
-1.091V   -20.62mA   -5.298mA   -34.08mA
-981.8mV  -26.44mA   -8.862mA   -36.32mA
-654.5mV  -24.5mA    -14.59mA   -31.53mA
-436.4mV  -17.53mA   -10.31mA   -23.34mA
381.8mV   13.54mA    7.116mA    19.32mA
927.3mV   25mA       12.07mA    37.78mA
1.691V    27.34mA    12.75mA    42.32mA
3.6V      26.99mA    12.6mA     41.69mA
[Pullup]
|   voltage   I(typ)   I(min)   I(max)
-1.8V     6.703mA    2.011mA    25.07mA
-1.309V   24.97mA    8.117mA    42.58mA
-709.1mV  24.88mA    16.26mA    34.85mA
927.3mV   -29.26mA   -15.5mA    -46.38mA
1.418V    -36.27mA   -18.07mA   -59.68mA
2.127V    -39.86mA   -19.24mA   -67.35mA
2.782V    -40.19mA   -12.5mA    -69.92mA
3V        -21.5mA    -5.748mA   -67.45mA
3.055V    -16.07mA   -5.025mA   -61.29mA
3.164V    -10.24mA   -4.312mA   -32.15mA
3.273V    -7.595mA   -4.315mA   -17.08mA
3.6V      -7.13mA    -4.323mA   -9.86mA
[GND_clamp]
|   voltage   I(typ)   I(min)   I(max)
-1.8V     -5.104A    -4.871A    -5.301A
-1.073V   -99.03mA   -143.7mA   -86.57mA
-1.036V   -61.8mA    -90.72mA   -59.87mA
-1V       -46.13mA   -64.73mA   -48.3mA
-963.6mV  -34.72mA   -45.55mA   -39.35mA
-927.3mV  -27.57mA   -33.17mA   -33.02mA
-854.5mV  -20.79mA   -21.36mA   -26.11mA
-709.1mV  -11.52mA   -9.383mA   -15.46mA
-563.6mV  -4.448mA   -3.656mA   -6.094mA
-454.5mV  -1.35mA    -1.34mA    -1.873mA
-18.18mV  0A         0A         0A
3.6V      0A         0A         0A
[Ramp]
| variable   typ   min   max
dV/dt_f 0.65702228/1.5409563n 0.37013796/4.8217232n 0.82773106/0.67936041n
dV/dt_r 0.69004073/2.0164555n 0.45473535/5.7223034n 0.86510234/0.87155154n
R_load = 50
[Rising Waveform]
R_fixture = 50
V_fixture = 1.8
V_fixture_min = 1.62
V_fixture_max = 1.95
|   time   V(typ)   V(min)   V(max)
0s        709.5mV    1.008V     576mV
631.3ps   709.5mV    1.008V     608.5mV
707.4ps   709.5mV    1.008V     845.4mV
839.8ps   709.5mV    1.008V     1.69V
929.6ps   727.8mV    1.008V     1.885V
1.28ns    1.681V     1.008V     1.941V
1.633ns   1.782V     1.047V     1.947V
2.172ns   1.796V     1.553V     1.949V
2.626ns   1.798V     1.608V     1.949V
26.2ns    1.8V       1.62V      1.95V
[Rising Waveform]
R_fixture = 50
V_fixture = 0
V_fixture_min = 0
V_fixture_max = 0
|   time   V(typ)   V(min)   V(max)
0s        2.39mV     2.293mV    3.471mV
634.9ps   2.39mV     2.293mV    13mV
898.1ps   2.39mV     2.293mV    426mV
1.129ns   52.82mV    2.293mV    694.1mV
1.701ns   380.3mV    2.293mV    1.152V
2.225ns   600.2mV    54.63mV    1.298V
3.057ns   855.1mV    158.7mV    1.378V
5.177ns   1.062V     381.8mV    1.424V
9.984ns   1.133V     641.3mV    1.434V
26.2ns    1.142V     745.3mV    1.434V
[Falling Waveform]
R_fixture = 50
V_fixture = 1.8
V_fixture_min = 1.62
V_fixture_max = 1.95
|   time   V(typ)   V(min)   V(max)
0s        1.8V       1.62V      1.949V
656.6ps   1.8V       1.62V      1.949V
861.3ps   1.8V       1.62V      1.861V
1.35ns    1.749V     1.62V      1.523V
1.942ns   1.584V     1.62V      772.8mV
2.828ns   1.125V     1.581V     607.1mV
4.031ns   842.1mV    1.468V     581.5mV
6.12ns    736.8mV    1.256V     576.5mV
12.36ns   710.8mV    1.049V     576.2mV
26.2ns    710.3mV    1.008V     576.2mV
[Falling Waveform]
R_fixture = 50
V_fixture = 0
V_fixture_min = 0
V_fixture_max = 0
|   time   V(typ)   V(min)   V(max)
0s        1.141V     750.5mV    1.433V
670.1ps   1.141V     750.5mV    1.407V
1.014ns   1.106V     750.5mV    1.077V
1.461ns   852.7mV    746.4mV    286.4mV
1.984ns   330.7mV    638.3mV    9.688mV
2.289ns   139mV      525.5mV    4.865mV
2.766ns   22.42mV    356mV      3.486mV
3.657ns   3.369mV    96.56mV    3.146mV
4.689ns   2.432mV    10.56mV    3.092mV
26.2ns    2.13mV     0V         3.071mV
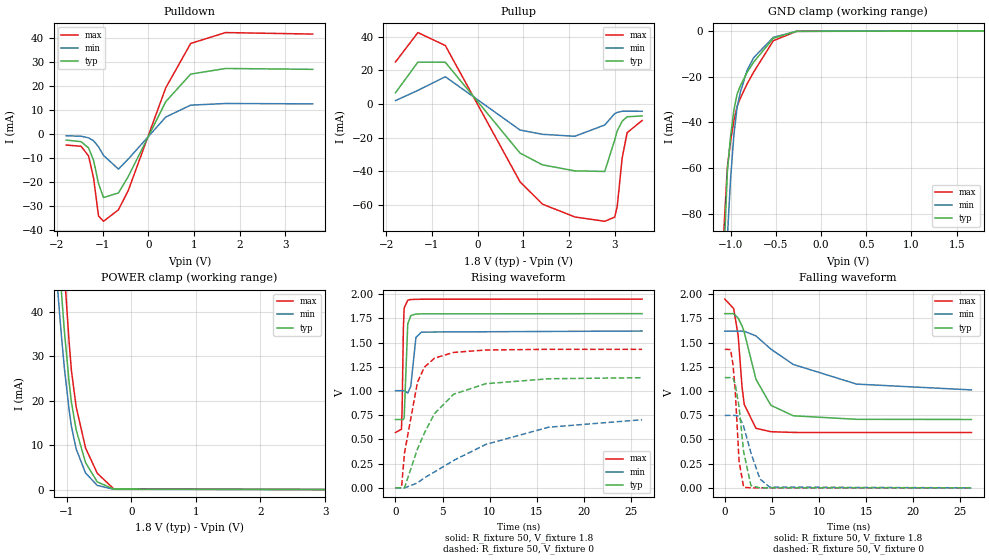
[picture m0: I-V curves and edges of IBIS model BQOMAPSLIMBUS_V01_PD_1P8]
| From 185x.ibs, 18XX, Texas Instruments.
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|   Model Cell BQOMAPSLIMBUS_V01_PD_1P8
|BQOMAPSLIMBUS_V01_PD_1P8
[Model]   BQOMAPSLIMBUS_V01_PD_1P8
Model_type   I/O
Polarity   Non-Inverting
Enable   Active-Low
Vinl =  0.63
Vinh =  1.17
Cref =  15pF
Rref =  100.0000M
Vref =  0V
Vmeas =  0.9
C_comp   1.636035p   1.481314p   1.795483p
[Model Spec]
Vinl   0.63   0.567   0.6825
Vinh   1.17   1.053   1.2675
[Temperature Range]   25   125   -40
[Voltage Range]   1.8   1.62   1.95
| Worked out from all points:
|   slope of the pulldown table from 0 to 0.27 V, typ, clamps not added: 27.2 ohm
|   slope of the pullup table from 0 to 0.27 V, typ, clamps not added: 26.2 ohm
|   GND clamp passes 1 mA (typ) near -0.44 V on its own axis
|   POWER clamp passes 1 mA (typ) near -0.46 V on its own axis
|   rising waveform, R_fixture 50, V_fixture 1.8: 20-80 % time 196ps typ, 356ps min, 132ps max; typ from 0.705 V to 1.8 V
|   rising waveform, R_fixture 50, V_fixture 0: 20-80 % time 3.76ns typ, 9.35ns min, 1.66ns max; typ from 0 V to 1.14 V
|   falling waveform, R_fixture 50, V_fixture 1.8: 20-80 % time 2.14ns typ, 6.69ns min, 804ps max; typ from 1.8 V to 0.706 V
|   falling waveform, R_fixture 50, V_fixture 0: 20-80 % time 768ps typ, 1.35ns min, 504ps max; typ from 1.14 V to 0 V
| Nom Voltages:
|   BIASFET=1.8, VBBNW=1.1, VDD=1.1, VDDS=1.8, VDDU=1.05, VSS=0, VSSS=0
| Min Voltages:
|   BIASFET=1.62, VBBNW=0.99, VDD=0.99, VDDS=1.62, VDDU=0.95, VSS=0,
|   VSSS=0
| Max Voltages:
|   BIASFET=1.95, VBBNW=1.21, VDD=1.21, VDDS=1.95, VDDU=1.16, VSS=0,
|   VSSS=0
[POWER_clamp]
|   voltage   I(typ)   I(min)   I(max)
-1.8V     243.4mA    191.6mA    307.8mA
-1.182V   67.14mA    52.87mA    87.8mA
-1.109V   50.26mA    39.3mA     67.51mA
-1.073V   42.68mA    33.12mA    58mA
-1.036V   35.59mA    27.28mA    48.82mA
-963.6mV  24.31mA    18.01mA    33.31mA
-927.3mV  19.65mA    14.2mA     26.78mA
-854.5mV  13.48mA    9.176mA    18.67mA
-709.1mV  6.095mA    3.747mA    9.4mA
-527.3mV  1.73mA     943.3uA    3.675mA
-272.7mV  118.9uA    74.64uA    178uA
3.6V      0A         0A         0A
[Pulldown]
|   voltage   I(typ)   I(min)   I(max)
-1.8V     -2.487mA   -681.8uA   -4.563mA
-1.473V   -3.152mA   -884.6uA   -5.067mA
-1.309V   -5.739mA   -1.559mA   -9.112mA
-1.2V     -10.86mA   -2.75mA    -18.27mA
-1.091V   -20.62mA   -5.298mA   -34.07mA
-981.8mV  -26.44mA   -8.862mA   -36.32mA
-654.5mV  -24.49mA   -14.59mA   -31.53mA
-436.4mV  -17.53mA   -10.31mA   -23.34mA
381.8mV   13.54mA    7.116mA    19.31mA
927.3mV   25mA       12.07mA    37.77mA
1.691V    27.34mA    12.75mA    42.3mA
3.6V      26.98mA    12.6mA     41.67mA
[Pullup]
|   voltage   I(typ)   I(min)   I(max)
-1.8V     6.703mA    2.011mA    25.06mA
-1.309V   24.97mA    8.117mA    42.58mA
-709.1mV  24.88mA    16.26mA    34.85mA
927.3mV   -29.26mA   -15.5mA    -46.38mA
1.418V    -36.27mA   -18.07mA   -59.68mA
2.127V    -39.86mA   -19.24mA   -67.34mA
2.782V    -40.19mA   -12.5mA    -69.92mA
3V        -21.5mA    -5.748mA   -67.44mA
3.055V    -16.07mA   -5.025mA   -61.28mA
3.164V    -10.24mA   -4.312mA   -32.15mA
3.273V    -7.595mA   -4.315mA   -17.08mA
3.6V      -7.13mA    -4.323mA   -9.859mA
[GND_clamp]
|   voltage   I(typ)   I(min)   I(max)
-1.8V     -5.104A    -4.871A    -5.301A
-1.073V   -99.01mA   -143.7mA   -86.51mA
-1.036V   -61.78mA   -90.71mA   -59.81mA
-1V       -46.11mA   -64.73mA   -48.24mA
-963.6mV  -34.7mA    -45.54mA   -39.29mA
-927.3mV  -27.54mA   -33.17mA   -32.95mA
-890.9mV  -23.9mA    -26.66mA   -29.29mA
-818.2mV  -18.14mA   -17.24mA   -23.2mA
-745.5mV  -13.61mA   -11.65mA   -17.98mA
-527.3mV  -3.104mA   -2.701mA   -4.21mA
-272.7mV  -55.4uA    -76.65uA   -80.17uA
1.8V      92.49uA    51.14uA    157.6uA
[Ramp]
| variable   typ   min   max
dV/dt_f 0.65866055/2.1444365n 0.37160303/6.8965213n  0.8294349/0.80882139n
dV/dt_r 0.68931283/3.7919874n 0.45375598/10.837069n 0.86478748/1.6605466n
R_load = 50
[Rising Waveform]
R_fixture = 50
V_fixture = 1.8
V_fixture_min = 1.62
V_fixture_max = 1.95
|   time   V(typ)   V(min)   V(max)
0s        705.2mV    1.003V     571.5mV
635.8ps   705.2mV    1.003V     604.8mV
706.7ps   705.2mV    1.003V     822.3mV
838.7ps   705.2mV    1.003V     1.651V
921.2ps   724.6mV    1.003V     1.858V
1.304ns   1.693V     978.6mV    1.937V
1.626ns   1.778V     1.049V     1.944V
2.171ns   1.794V     1.552V     1.946V
2.756ns   1.796V     1.608V     1.947V
26.2ns    1.798V     1.619V     1.948V
[Rising Waveform]
R_fixture = 50
V_fixture = 0
V_fixture_min = 0
V_fixture_max = 0
|   time   V(typ)   V(min)   V(max)
0s        0V         0V         0V
639.5ps   0V         0V         0V
953.3ps   0V         0V         358.1mV
2.328ns   398.9mV    50.62mV    1.088V
3.072ns   566.5mV    103.8mV    1.246V
4.146ns   766.3mV    164.6mV    1.339V
6.175ns   966.4mV    282.7mV    1.398V
9.597ns   1.075V     448.2mV    1.423V
16.26ns   1.126V     626mV      1.43V
26.2ns    1.137V     703.2mV    1.43V
[Falling Waveform]
R_fixture = 50
V_fixture = 1.8
V_fixture_min = 1.62
V_fixture_max = 1.95
|   time   V(typ)   V(min)   V(max)
0s        1.798V     1.618V     1.948V
942.1ps   1.798V     1.618V     1.85V
1.42ns    1.751V     1.618V     1.568V
1.825ns   1.673V     1.618V     1.047V
2.061ns   1.607V     1.617V     860.6mV
3.31ns    1.12V      1.568V     614.7mV
4.892ns   852.3mV    1.432V     579.5mV
7.271ns   744mV      1.274V     572.1mV
14ns      707.5mV    1.071V     571.2mV
26.2ns    705.9mV    1.011V     571.2mV
[Falling Waveform]
R_fixture = 50
V_fixture = 0
V_fixture_min = 0
V_fixture_max = 0
|   time   V(typ)   V(min)   V(max)
0s        1.138V     747.7mV    1.43V
612.4ps   1.138V     747.7mV    1.428V
858.2ps   1.136V     747.7mV    1.279V
1.099ns   1.072V     747.7mV    1.013V
1.511ns   837.1mV    739mV      278.7mV
1.995ns   375.1mV    636mV      6.517mV
2.776ns   21.99mV    361.1mV    0V
3.729ns   0V         91.91mV    0V
4.75ns    0V         8.307mV    0V
26.2ns    0V         0V         0V
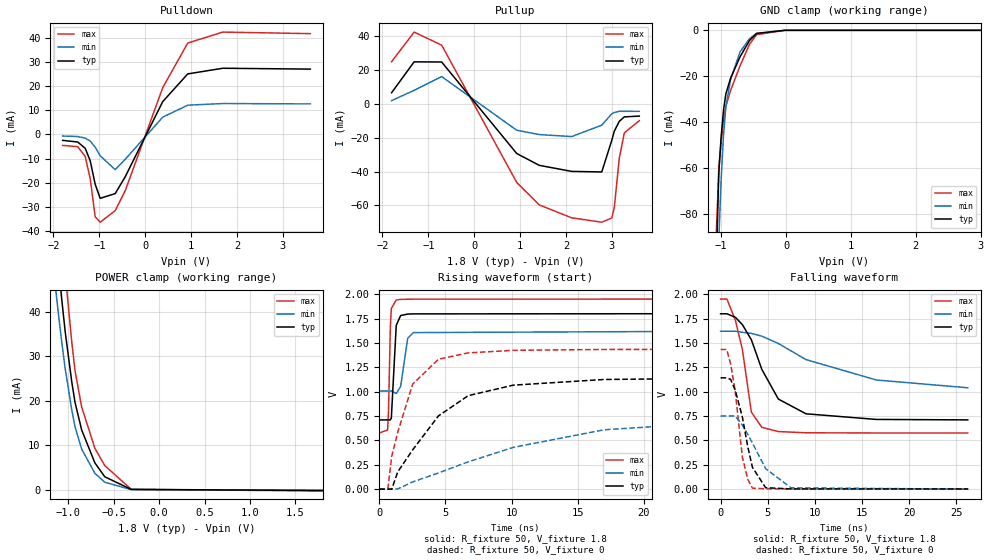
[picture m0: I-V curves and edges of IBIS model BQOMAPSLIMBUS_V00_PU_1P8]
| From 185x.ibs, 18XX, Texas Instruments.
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|   Model Cell BQOMAPSLIMBUS_V00_PU_1P8
|BQOMAPSLIMBUS_V00_PU_1P8
[Model]   BQOMAPSLIMBUS_V00_PU_1P8
Model_type   I/O
Polarity   Non-Inverting
Enable   Active-Low
Vinl =  0.63
Vinh =  1.17
Cref =  15pF
Rref =  100.0000M
Vref =  0V
Vmeas =  0.9
C_comp   1.636035p   1.481314p   1.795483p
[Model Spec]
Vinl   0.63   0.567   0.6825
Vinh   1.17   1.053   1.2675
[Temperature Range]   25   125   -40
[Voltage Range]   1.8   1.62   1.95
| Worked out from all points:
|   slope of the pulldown table from 0 to 0.27 V, typ, clamps not added: 27.2 ohm
|   slope of the pullup table from 0 to 0.27 V, typ, clamps not added: 26.2 ohm
|   GND clamp passes 1 mA (typ) near -0.43 V on its own axis
|   POWER clamp passes 1 mA (typ) near -0.47 V on its own axis
|   rising waveform, R_fixture 50, V_fixture 1.8: 20-80 % time 197ps typ, 359ps min, 133ps max; typ from 0.71 V to 1.8 V
|   rising waveform, R_fixture 50, V_fixture 0: 20-80 % time 4.3ns typ, 10.2ns min, 1.93ns max; typ from 0 V to 1.14 V
|   falling waveform, R_fixture 50, V_fixture 1.8: 20-80 % time 3.07ns typ, 8.7ns min, 1.38ns max; typ from 1.8 V to 0.711 V
|   falling waveform, R_fixture 50, V_fixture 0: 20-80 % time 1.46ns typ, 2.55ns min, 1.05ns max; typ from 1.14 V to 0.002 V
| Nom Voltages:
|   BIASFET=1.8, VBBNW=1.1, VDD=1.1, VDDS=1.8, VDDU=1.05, VSS=0, VSSS=0
| Min Voltages:
|   BIASFET=1.62, VBBNW=0.99, VDD=0.99, VDDS=1.62, VDDU=0.95, VSS=0,
|   VSSS=0
| Max Voltages:
|   BIASFET=1.95, VBBNW=1.21, VDD=1.21, VDDS=1.95, VDDU=1.16, VSS=0,
|   VSSS=0
[POWER_clamp]
|   voltage   I(typ)   I(min)   I(max)
-1.8V     243.4mA    191.6mA    307.8mA
-1.182V   67.16mA    52.88mA    87.81mA
-1.109V   50.28mA    39.31mA    67.52mA
-1.073V   42.7mA     33.13mA    58.01mA
-1.036V   35.6mA     27.29mA    48.83mA
-963.6mV  24.32mA    18.02mA    33.31mA
-927.3mV  19.66mA    14.2mA     26.77mA
-854.5mV  13.49mA    9.183mA    18.66mA
-709.1mV  6.091mA    3.749mA    9.378mA
-600mV    2.963mA    1.738mA    5.478mA
-309.1mV  129.1uA    75.85uA    140.2uA
1.8V      -127.6uA   -66.01uA   -226.6uA
[Pulldown]
|   voltage   I(typ)   I(min)   I(max)
-1.8V     -2.487mA   -681.8uA   -4.562mA
-1.473V   -3.152mA   -884.6uA   -5.067mA
-1.309V   -5.739mA   -1.559mA   -9.111mA
-1.2V     -10.86mA   -2.75mA    -18.26mA
-1.091V   -20.62mA   -5.298mA   -34.07mA
-981.8mV  -26.44mA   -8.861mA   -36.31mA
-654.5mV  -24.49mA   -14.59mA   -31.53mA
-436.4mV  -17.53mA   -10.31mA   -23.34mA
381.8mV   13.54mA    7.116mA    19.31mA
927.3mV   25mA       12.07mA    37.76mA
1.691V    27.34mA    12.75mA    42.29mA
3.6V      26.98mA    12.59mA    41.65mA
[Pullup]
|   voltage   I(typ)   I(min)   I(max)
-1.8V     6.703mA    2.011mA    25.06mA
-1.309V   24.97mA    8.116mA    42.58mA
-709.1mV  24.88mA    16.26mA    34.85mA
927.3mV   -29.26mA   -15.5mA    -46.38mA
1.418V    -36.27mA   -18.07mA   -59.68mA
2.127V    -39.86mA   -19.24mA   -67.34mA
2.782V    -40.19mA   -12.5mA    -69.92mA
3V        -21.5mA    -5.748mA   -67.44mA
3.055V    -16.07mA   -5.025mA   -61.28mA
3.164V    -10.24mA   -4.312mA   -32.15mA
3.273V    -7.595mA   -4.315mA   -17.08mA
3.6V      -7.13mA    -4.323mA   -9.859mA
[GND_clamp]
|   voltage   I(typ)   I(min)   I(max)
-1.8V     -5.104A    -4.871A    -5.301A
-1.073V   -99.03mA   -143.7mA   -86.57mA
-1.036V   -61.8mA    -90.72mA   -59.87mA
-1V       -46.13mA   -64.73mA   -48.3mA
-963.6mV  -34.72mA   -45.55mA   -39.35mA
-927.3mV  -27.57mA   -33.17mA   -33.02mA
-854.5mV  -20.79mA   -21.36mA   -26.11mA
-709.1mV  -11.52mA   -9.383mA   -15.46mA
-563.6mV  -4.448mA   -3.656mA   -6.094mA
-454.5mV  -1.35mA    -1.34mA    -1.873mA
-18.18mV  0A         0A         0A
3.6V      0A         0A         0A
[Ramp]
| variable   typ   min   max
dV/dt_f 0.65572258/3.0850729n 0.36909582/9.8884213n 0.82633108/1.388269n
dV/dt_r 0.68999578/4.3515173n 0.45447221/12.373268n 0.86542213/1.9232098n
R_load = 50
[Rising Waveform]
R_fixture = 50
V_fixture = 1.8
V_fixture_min = 1.62
V_fixture_max = 1.95
|   time   V(typ)   V(min)   V(max)
0s        710.3mV    1.007V     576.2mV
632.8ps   710.3mV    1.007V     607.3mV
701.6ps   710.3mV    1.007V     807.5mV
839.4ps   710.3mV    1.007V     1.66V
914.3ps   729.6mV    1.007V     1.854V
1.285ns   1.68V      981.3mV    1.94V
1.617ns   1.781V     1.053V     1.947V
2.148ns   1.796V     1.547V     1.948V
2.573ns   1.798V     1.606V     1.949V
26.2ns    1.8V       1.62V      1.95V
[Rising Waveform]
R_fixture = 50
V_fixture = 0
V_fixture_min = 0
V_fixture_max = 0
|   time   V(typ)   V(min)   V(max)
0s        0V         2.052mV    2.746mV
656ps     0V         2.052mV    6.238mV
944.9ps   0V         2.052mV    338.3mV
1.4ns     177.8mV    2.052mV    583.8mV
2.519ns   402.1mV    73.81mV    1.076V
4.475ns   751.6mV    166.2mV    1.333V
6.722ns   959.2mV    280.2mV    1.398V
10.13ns   1.067V     428.7mV    1.424V
16.98ns   1.125V     608.9mV    1.433V
26.25ns   1.138V     689.7mV    1.434V
[Falling Waveform]
R_fixture = 50
V_fixture = 1.8
V_fixture_min = 1.62
V_fixture_max = 1.95
|   time   V(typ)   V(min)   V(max)
0s        1.799V     1.62V      1.95V
676.4ps   1.799V     1.62V      1.95V
1.579ns   1.762V     1.62V      1.73V
2.317ns   1.687V     1.609V     1.43V
3.265ns   1.532V     1.598V     789.7mV
4.374ns   1.228V     1.569V     634.3mV
6.125ns   924.2mV    1.494V     590.9mV
9.054ns   773.1mV    1.329V     578.4mV
16.5ns    715.4mV    1.12V      576.3mV
26.2ns    710.6mV    1.04V      576.3mV
[Falling Waveform]
R_fixture = 50
V_fixture = 0
V_fixture_min = 0
V_fixture_max = 0
|   time   V(typ)   V(min)   V(max)
0s        1.142V     750.8mV    1.433V
650.3ps   1.142V     750.8mV    1.433V
1.063ns   1.126V     750.8mV    1.286V
1.555ns   1.016V     750.2mV    1.002V
2.31ns    740mV      656.5mV    328.6mV
2.875ns   438.1mV    564.3mV    103.2mV
3.377ns   224.2mV    472.9mV    10.5mV
4.771ns   15.07mV    211mV      3.366mV
7.46ns    2.428mV    13.92mV    3.095mV
26.25ns   2.13mV     0V         3.071mV
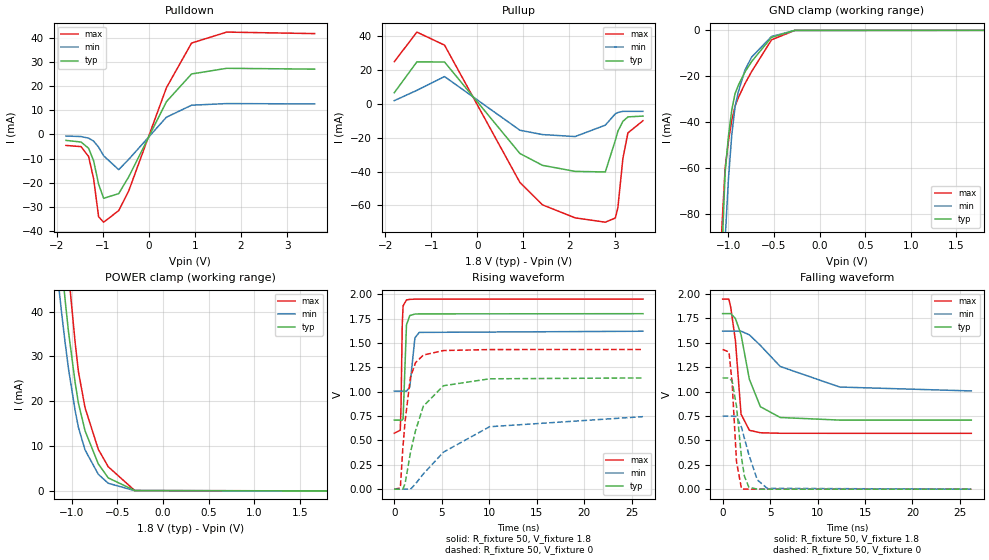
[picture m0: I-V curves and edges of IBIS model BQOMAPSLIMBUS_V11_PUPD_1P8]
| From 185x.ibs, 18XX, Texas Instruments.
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|   Model Cell BQOMAPSLIMBUS_V11_PUPD_1P8
|BQOMAPSLIMBUS_V11_PUPD_1P8
[Model]   BQOMAPSLIMBUS_V11_PUPD_1P8
Model_type   I/O
Polarity   Non-Inverting
Enable   Active-Low
Vinl =  0.63
Vinh =  1.17
Cref =  15pF
Rref =  100.0000M
Vref =  0V
Vmeas =  0.9
C_comp   1.636035p   1.481314p   1.795483p
[Model Spec]
Vinl   0.63   0.567   0.6825
Vinh   1.17   1.053   1.2675
[Temperature Range]   25   125   -40
[Voltage Range]   1.8   1.62   1.95
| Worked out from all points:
|   slope of the pulldown table from 0 to 0.27 V, typ, clamps not added: 27.2 ohm
|   slope of the pullup table from 0 to 0.27 V, typ, clamps not added: 26.2 ohm
|   GND clamp passes 1 mA (typ) near -0.44 V on its own axis
|   POWER clamp passes 1 mA (typ) near -0.47 V on its own axis
|   rising waveform, R_fixture 50, V_fixture 1.8: 20-80 % time 186ps typ, 346ps min, 129ps max; typ from 0.709 V to 1.8 V
|   rising waveform, R_fixture 50, V_fixture 0: 20-80 % time 2.02ns typ, 5.59ns min, 877ps max; typ from 0 V to 1.14 V
|   falling waveform, R_fixture 50, V_fixture 1.8: 20-80 % time 1.53ns typ, 4.79ns min, 672ps max; typ from 1.8 V to 0.708 V
|   falling waveform, R_fixture 50, V_fixture 0: 20-80 % time 734ps typ, 1.3ns min, 496ps max; typ from 1.14 V to 0 V
| Nom Voltages:
|   BIASFET=1.8, VBBNW=1.1, VDD=1.1, VDDS=1.8, VDDU=1.05, VSS=0, VSSS=0
| Min Voltages:
|   BIASFET=1.62, VBBNW=0.99, VDD=0.99, VDDS=1.62, VDDU=0.95, VSS=0,
|   VSSS=0
| Max Voltages:
|   BIASFET=1.95, VBBNW=1.21, VDD=1.21, VDDS=1.95, VDDU=1.16, VSS=0,
|   VSSS=0
[POWER_clamp]
|   voltage   I(typ)   I(min)   I(max)
-1.8V     243.4mA    191.6mA    307.8mA
-1.182V   67.1mA     52.86mA    87.7mA
-1.109V   50.21mA    39.28mA    67.42mA
-1.073V   42.63mA    33.1mA     57.9mA
-1.036V   35.53mA    27.26mA    48.72mA
-963.6mV  24.25mA    17.98mA    33.21mA
-927.3mV  19.59mA    14.17mA    26.67mA
-854.5mV  13.42mA    9.147mA    18.56mA
-709.1mV  6.025mA    3.712mA    9.28mA
-600mV    2.9mA      1.702mA    5.383mA
-309.1mV  90.44uA    54uA       81.09uA
1.8V      -20.23nA   -5.391uA   -126.9nA
[Pulldown]
|   voltage   I(typ)   I(min)   I(max)
-1.8V     -2.487mA   -681.8uA   -4.563mA
-1.473V   -3.152mA   -884.6uA   -5.067mA
-1.309V   -5.739mA   -1.559mA   -9.112mA
-1.2V     -10.86mA   -2.75mA    -18.27mA
-1.091V   -20.62mA   -5.298mA   -34.08mA
-981.8mV  -26.44mA   -8.862mA   -36.32mA
-654.5mV  -24.5mA    -14.59mA   -31.53mA
-436.4mV  -17.53mA   -10.31mA   -23.34mA
381.8mV   13.54mA    7.116mA    19.32mA
927.3mV   25mA       12.07mA    37.78mA
1.691V    27.34mA    12.75mA    42.32mA
3.6V      26.99mA    12.6mA     41.69mA
[Pullup]
|   voltage   I(typ)   I(min)   I(max)
-1.8V     6.703mA    2.011mA    25.06mA
-1.309V   24.97mA    8.117mA    42.58mA
-709.1mV  24.88mA    16.26mA    34.85mA
927.3mV   -29.26mA   -15.5mA    -46.38mA
1.418V    -36.27mA   -18.07mA   -59.68mA
2.127V    -39.86mA   -19.24mA   -67.35mA
2.782V    -40.19mA   -12.5mA    -69.92mA
3V        -21.49mA   -5.748mA   -67.45mA
3.055V    -16.07mA   -5.025mA   -61.28mA
3.164V    -10.24mA   -4.312mA   -32.15mA
3.273V    -7.595mA   -4.315mA   -17.08mA
3.6V      -7.13mA    -4.323mA   -9.86mA
[GND_clamp]
|   voltage   I(typ)   I(min)   I(max)
-1.8V     -5.104A    -4.871A    -5.301A
-1.073V   -98.98mA   -143.7mA   -86.45mA
-1.036V   -61.74mA   -90.7mA    -59.73mA
-1V       -46.06mA   -64.71mA   -48.16mA
-963.6mV  -34.65mA   -45.53mA   -39.21mA
-927.3mV  -27.49mA   -33.15mA   -32.87mA
-890.9mV  -23.84mA   -26.64mA   -29.21mA
-818.2mV  -18.08mA   -17.22mA   -23.12mA
-745.5mV  -13.56mA   -11.62mA   -17.89mA
-527.3mV  -3.048mA   -2.672mA   -4.127mA
-272.7mV  -20.27uA   -57.26uA   -26.95uA
1.8V      7.704nA    2.326uA    10.8nA
[Ramp]
| variable   typ   min   max
dV/dt_f 0.65864439/1.5363615n 0.37112484/4.8198521n   0.829813/0.67811899n
dV/dt_r 0.69042842/2.0212557n 0.45466916/5.7271368n 0.86615511/0.87627905n
R_load = 50
[Rising Waveform]
R_fixture = 50
V_fixture = 1.8
V_fixture_min = 1.62
V_fixture_max = 1.95
|   time   V(typ)   V(min)   V(max)
0s        708.6mV    1.006V     573.7mV
630.2ps   708.6mV    1.006V     604.8mV
706.4ps   708.6mV    1.006V     840.3mV
839.5ps   708.6mV    1.006V     1.687V
927.4ps   724mV      1.006V     1.881V
1.284ns   1.685V     1.006V     1.941V
1.632ns   1.781V     1.046V     1.947V
2.172ns   1.796V     1.552V     1.949V
2.627ns   1.798V     1.608V     1.949V
26.2ns    1.8V       1.62V      1.95V
[Rising Waveform]
R_fixture = 50
V_fixture = 0
V_fixture_min = 0
V_fixture_max = 0
|   time   V(typ)   V(min)   V(max)
0s        0V         0V         0V
637.1ps   0V         0V         12.03mV
896.5ps   0V         0V         417.4mV
1.141ns   58.12mV    0V         700.3mV
1.706ns   377.6mV    0V         1.15V
2.232ns   598.3mV    53.79mV    1.297V
3.058ns   851.6mV    156.1mV    1.376V
5.187ns   1.061V     380.2mV    1.422V
10.04ns   1.132V     640.6mV    1.432V
26.2ns    1.141V     743.8mV    1.433V
[Falling Waveform]
R_fixture = 50
V_fixture = 1.8
V_fixture_min = 1.62
V_fixture_max = 1.95
|   time   V(typ)   V(min)   V(max)
0s        1.8V       1.62V      1.949V
655.5ps   1.8V       1.62V      1.949V
860.3ps   1.8V       1.62V      1.861V
1.35ns    1.749V     1.62V      1.521V
1.941ns   1.584V     1.62V      768.8mV
2.818ns   1.126V     1.582V     603.7mV
3.976ns   845.6mV    1.474V     578.3mV
6.068ns   734.8mV    1.258V     573.1mV
12.34ns   708.1mV    1.047V     572.7mV
26.2ns    707.6mV    1.007V     572.7mV
[Falling Waveform]
R_fixture = 50
V_fixture = 0
V_fixture_min = 0
V_fixture_max = 0
|   time   V(typ)   V(min)   V(max)
0s        1.14V      748.9mV    1.432V
667.1ps   1.14V      748.9mV    1.407V
1.006ns   1.107V     748.9mV    1.086V
1.46ns    850.5mV    744.8mV    283mV
1.984ns   326mV      636mV      6.399mV
2.293ns   134.3mV    521.6mV    0V
2.762ns   20.28mV    354.5mV    0V
3.653ns   0V         94.95mV    0V
4.704ns   0V         8.367mV    0V
26.2ns    0V         0V         0V
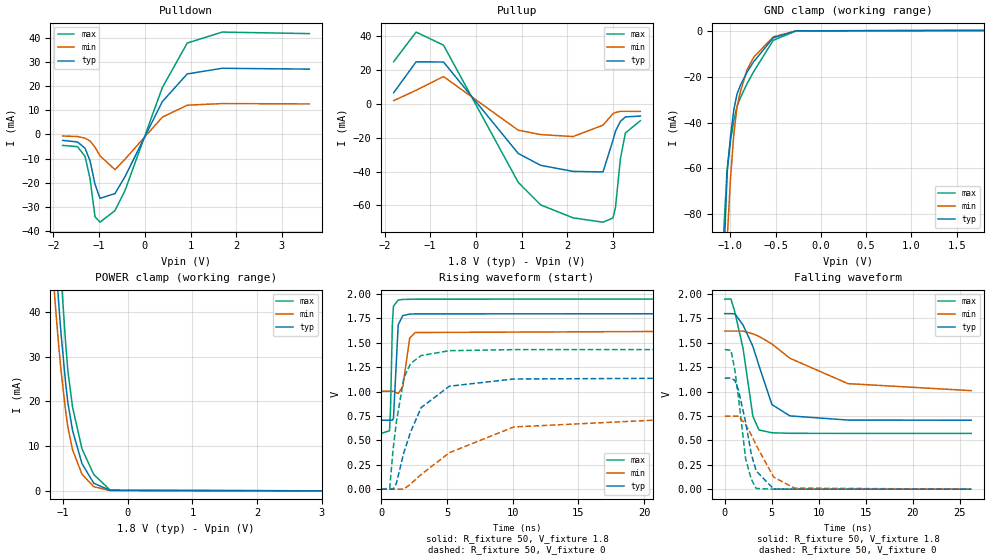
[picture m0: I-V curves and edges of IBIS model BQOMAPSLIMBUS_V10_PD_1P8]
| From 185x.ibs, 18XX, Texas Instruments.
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|   Model Cell BQOMAPSLIMBUS_V10_PD_1P8
|BQOMAPSLIMBUS_V10_PD_1P8
[Model]   BQOMAPSLIMBUS_V10_PD_1P8
Model_type   I/O
Polarity   Non-Inverting
Enable   Active-Low
Vinl =  0.63
Vinh =  1.17
Cref =  15pF
Rref =  100.0000M
Vref =  0V
Vmeas =  0.9
C_comp   1.636035p   1.481314p   1.795483p
[Model Spec]
Vinl   0.63   0.567   0.6825
Vinh   1.17   1.053   1.2675
[Temperature Range]   25   125   -40
[Voltage Range]   1.8   1.62   1.95
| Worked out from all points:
|   slope of the pulldown table from 0 to 0.27 V, typ, clamps not added: 27.2 ohm
|   slope of the pullup table from 0 to 0.27 V, typ, clamps not added: 26.2 ohm
|   GND clamp passes 1 mA (typ) near -0.44 V on its own axis
|   POWER clamp passes 1 mA (typ) near -0.46 V on its own axis
|   rising waveform, R_fixture 50, V_fixture 1.8: 20-80 % time 188ps typ, 351ps min, 129ps max; typ from 0.707 V to 1.8 V
|   rising waveform, R_fixture 50, V_fixture 0: 20-80 % time 2.06ns typ, 5.68ns min, 901ps max; typ from 0 V to 1.14 V
|   falling waveform, R_fixture 50, V_fixture 1.8: 20-80 % time 2.22ns typ, 6.05ns min, 1.36ns max; typ from 1.8 V to 0.706 V
|   falling waveform, R_fixture 50, V_fixture 0: 20-80 % time 1.43ns typ, 2.4ns min, 1.08ns max; typ from 1.14 V to 0 V
| Nom Voltages:
|   BIASFET=1.8, VBBNW=1.1, VDD=1.1, VDDS=1.8, VDDU=1.05, VSS=0, VSSS=0
| Min Voltages:
|   BIASFET=1.62, VBBNW=0.99, VDD=0.99, VDDS=1.62, VDDU=0.95, VSS=0,
|   VSSS=0
| Max Voltages:
|   BIASFET=1.95, VBBNW=1.21, VDD=1.21, VDDS=1.95, VDDU=1.16, VSS=0,
|   VSSS=0
[POWER_clamp]
|   voltage   I(typ)   I(min)   I(max)
-1.8V     243.4mA    191.6mA    307.8mA
-1.182V   67.14mA    52.87mA    87.8mA
-1.109V   50.26mA    39.3mA     67.51mA
-1.073V   42.68mA    33.12mA    58mA
-1.036V   35.59mA    27.28mA    48.82mA
-963.6mV  24.31mA    18.01mA    33.31mA
-927.3mV  19.65mA    14.2mA     26.78mA
-854.5mV  13.48mA    9.176mA    18.67mA
-709.1mV  6.095mA    3.747mA    9.4mA
-527.3mV  1.73mA     943.2uA    3.675mA
-272.7mV  118.9uA    74.64uA    178uA
3.6V      0A         0A         0A
[Pulldown]
|   voltage   I(typ)   I(min)   I(max)
-1.8V     -2.487mA   -681.8uA   -4.563mA
-1.473V   -3.152mA   -884.6uA   -5.067mA
-1.309V   -5.739mA   -1.559mA   -9.112mA
-1.2V     -10.86mA   -2.75mA    -18.27mA
-1.091V   -20.62mA   -5.298mA   -34.07mA
-981.8mV  -26.44mA   -8.862mA   -36.32mA
-654.5mV  -24.49mA   -14.59mA   -31.53mA
-436.4mV  -17.53mA   -10.31mA   -23.34mA
381.8mV   13.54mA    7.116mA    19.31mA
927.3mV   25mA       12.07mA    37.77mA
1.691V    27.34mA    12.75mA    42.31mA
3.6V      26.99mA    12.6mA     41.68mA
[Pullup]
|   voltage   I(typ)   I(min)   I(max)
-1.8V     6.703mA    2.011mA    25.06mA
-1.309V   24.97mA    8.117mA    42.58mA
-709.1mV  24.88mA    16.26mA    34.85mA
927.3mV   -29.26mA   -15.5mA    -46.38mA
1.418V    -36.27mA   -18.07mA   -59.68mA
2.127V    -39.86mA   -19.24mA   -67.35mA
2.782V    -40.19mA   -12.5mA    -69.92mA
3V        -21.5mA    -5.748mA   -67.45mA
3.055V    -16.07mA   -5.025mA   -61.28mA
3.164V    -10.24mA   -4.312mA   -32.15mA
3.273V    -7.595mA   -4.315mA   -17.08mA
3.6V      -7.13mA    -4.323mA   -9.86mA
[GND_clamp]
|   voltage   I(typ)   I(min)   I(max)
-1.8V     -5.104A    -4.871A    -5.301A
-1.073V   -99.01mA   -143.7mA   -86.51mA
-1.036V   -61.78mA   -90.71mA   -59.81mA
-1V       -46.11mA   -64.73mA   -48.24mA
-963.6mV  -34.7mA    -45.54mA   -39.29mA
-927.3mV  -27.54mA   -33.17mA   -32.95mA
-890.9mV  -23.9mA    -26.66mA   -29.29mA
-818.2mV  -18.14mA   -17.24mA   -23.2mA
-745.5mV  -13.61mA   -11.65mA   -17.98mA
-527.3mV  -3.104mA   -2.701mA   -4.21mA
-272.7mV  -55.4uA    -76.65uA   -80.17uA
1.8V      92.49uA    51.14uA    157.6uA
[Ramp]
| variable   typ   min   max
dV/dt_f 0.65759561/2.2342634n 0.37074849/6.2010189n  0.8283685/1.3723263n
dV/dt_r 0.68942052/2.059524n  0.45387751/5.8108556n 0.86503529/0.9007435n
R_load = 50
[Rising Waveform]
R_fixture = 50
V_fixture = 1.8
V_fixture_min = 1.62
V_fixture_max = 1.95
|   time   V(typ)   V(min)   V(max)
0s        706.7mV    1.003V     572.1mV
626.5ps   706.7mV    1.003V     598.8mV
705ps     706.7mV    1.003V     837.3mV
839ps     706.7mV    1.003V     1.687V
924.1ps   724.1mV    1.003V     1.875V
1.284ns   1.684V     981.2mV    1.938V
1.635ns   1.779V     1.051V     1.944V
2.161ns   1.794V     1.548V     1.946V
2.582ns   1.796V     1.605V     1.947V
26.2ns    1.798V     1.619V     1.948V
[Rising Waveform]
R_fixture = 50
V_fixture = 0
V_fixture_min = 0
V_fixture_max = 0
|   time   V(typ)   V(min)   V(max)
0s        0V         0V         0V
638ps     0V         0V         9.723mV
889.3ps   0V         0V         398.7mV
1.142ns   58mV       0V         685.1mV
1.715ns   374.4mV    0V         1.141V
2.228ns   586.3mV    52.62mV    1.288V
3.031ns   835.8mV    150.4mV    1.369V
5.176ns   1.055V     373.4mV    1.419V
10.08ns   1.129V     637.5mV    1.43V
26.22ns   1.139V     742.6mV    1.43V
[Falling Waveform]
R_fixture = 50
V_fixture = 1.8
V_fixture_min = 1.62
V_fixture_max = 1.95
|   time   V(typ)   V(min)   V(max)
0s        1.798V     1.619V     1.947V
669.3ps   1.798V     1.619V     1.947V
1.09ns    1.795V     1.619V     1.811V
1.952ns   1.681V     1.619V     1.441V
2.995ns   1.462V     1.591V     747.3mV
3.645ns   1.265V     1.565V     606.1mV
5.021ns   866.4mV    1.487V     577.7mV
6.927ns   750.6mV    1.341V     572mV
13.1ns    707.6mV    1.081V     571.2mV
26.2ns    705.9mV    1.009V     571.2mV
[Falling Waveform]
R_fixture = 50
V_fixture = 0
V_fixture_min = 0
V_fixture_max = 0
|   time   V(typ)   V(min)   V(max)
0s        1.138V     748mV      1.43V
669.3ps   1.138V     748mV      1.423V
1.087ns   1.113V     748mV      1.217V
1.48ns    1.009V     748mV      926.5mV
2.225ns   686.6mV    660.9mV    311.9mV
2.818ns   364.1mV    557.6mV    103.4mV
3.344ns   186.9mV    450.7mV    7.269mV
5.201ns   2.035mV    123.8mV    0V
7.423ns   0V         10.43mV    0V
26.22ns   0V         0V         0V
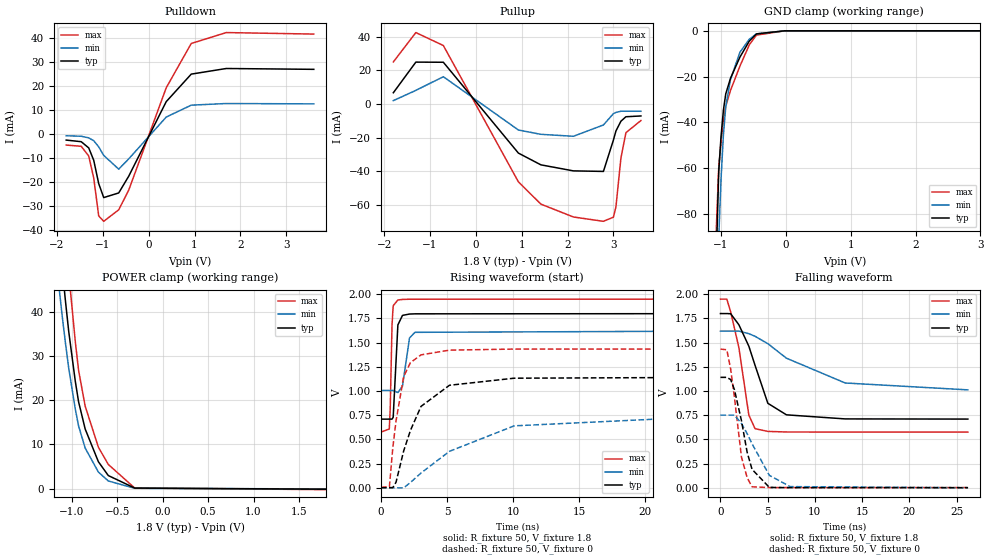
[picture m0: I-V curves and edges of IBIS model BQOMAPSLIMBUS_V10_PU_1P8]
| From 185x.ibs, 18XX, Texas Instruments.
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|   Model Cell BQOMAPSLIMBUS_V10_PU_1P8
|BQOMAPSLIMBUS_V10_PU_1P8
[Model]   BQOMAPSLIMBUS_V10_PU_1P8
Model_type   I/O
Polarity   Non-Inverting
Enable   Active-Low
Vinl =  0.63
Vinh =  1.17
Cref =  15pF
Rref =  100.0000M
Vref =  0V
Vmeas =  0.9
C_comp   1.636035p   1.481314p   1.795483p
[Model Spec]
Vinl   0.63   0.567   0.6825
Vinh   1.17   1.053   1.2675
[Temperature Range]   25   125   -40
[Voltage Range]   1.8   1.62   1.95
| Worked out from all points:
|   slope of the pulldown table from 0 to 0.27 V, typ, clamps not added: 27.2 ohm
|   slope of the pullup table from 0 to 0.27 V, typ, clamps not added: 26.2 ohm
|   GND clamp passes 1 mA (typ) near -0.43 V on its own axis
|   POWER clamp passes 1 mA (typ) near -0.47 V on its own axis
|   rising waveform, R_fixture 50, V_fixture 1.8: 20-80 % time 188ps typ, 350ps min, 128ps max; typ from 0.71 V to 1.8 V
|   rising waveform, R_fixture 50, V_fixture 0: 20-80 % time 2.05ns typ, 5.66ns min, 893ps max; typ from 0.003 V to 1.14 V
|   falling waveform, R_fixture 50, V_fixture 1.8: 20-80 % time 2.23ns typ, 6.07ns min, 1.37ns max; typ from 1.8 V to 0.71 V
|   falling waveform, R_fixture 50, V_fixture 0: 20-80 % time 1.43ns typ, 2.41ns min, 1.08ns max; typ from 1.14 V to 0.002 V
| Nom Voltages:
|   BIASFET=1.8, VBBNW=1.1, VDD=1.1, VDDS=1.8, VDDU=1.05, VSS=0, VSSS=0
| Min Voltages:
|   BIASFET=1.62, VBBNW=0.99, VDD=0.99, VDDS=1.62, VDDU=0.95, VSS=0,
|   VSSS=0
| Max Voltages:
|   BIASFET=1.95, VBBNW=1.21, VDD=1.21, VDDS=1.95, VDDU=1.16, VSS=0,
|   VSSS=0
[POWER_clamp]
|   voltage   I(typ)   I(min)   I(max)
-1.8V     243.4mA    191.6mA    307.8mA
-1.182V   67.16mA    52.88mA    87.81mA
-1.109V   50.28mA    39.31mA    67.52mA
-1.073V   42.7mA     33.13mA    58.01mA
-1.036V   35.6mA     27.29mA    48.83mA
-963.6mV  24.32mA    18.02mA    33.31mA
-927.3mV  19.66mA    14.2mA     26.78mA
-854.5mV  13.49mA    9.184mA    18.66mA
-709.1mV  6.091mA    3.749mA    9.378mA
-600mV    2.963mA    1.738mA    5.478mA
-309.1mV  129.1uA    75.85uA    140.2uA
1.8V      -127.6uA   -66.01uA   -226.6uA
[Pulldown]
|   voltage   I(typ)   I(min)   I(max)
-1.8V     -2.487mA   -681.8uA   -4.563mA
-1.473V   -3.152mA   -884.6uA   -5.067mA
-1.309V   -5.739mA   -1.559mA   -9.112mA
-1.2V     -10.86mA   -2.75mA    -18.27mA
-1.091V   -20.62mA   -5.298mA   -34.08mA
-981.8mV  -26.44mA   -8.862mA   -36.32mA
-654.5mV  -24.5mA    -14.59mA   -31.53mA
-436.4mV  -17.53mA   -10.31mA   -23.34mA
381.8mV   13.54mA    7.116mA    19.32mA
927.3mV   25mA       12.07mA    37.77mA
1.691V    27.34mA    12.75mA    42.31mA
3.6V      26.99mA    12.6mA     41.68mA
[Pullup]
|   voltage   I(typ)   I(min)   I(max)
-1.8V     6.703mA    2.011mA    25.07mA
-1.309V   24.97mA    8.117mA    42.58mA
-709.1mV  24.88mA    16.26mA    34.85mA
927.3mV   -29.26mA   -15.5mA    -46.38mA
1.418V    -36.27mA   -18.07mA   -59.68mA
2.127V    -39.86mA   -19.24mA   -67.35mA
2.782V    -40.19mA   -12.5mA    -69.92mA
3V        -21.5mA    -5.748mA   -67.45mA
3.055V    -16.07mA   -5.025mA   -61.29mA
3.164V    -10.24mA   -4.312mA   -32.15mA
3.273V    -7.595mA   -4.315mA   -17.08mA
3.6V      -7.13mA    -4.323mA   -9.86mA
[GND_clamp]
|   voltage   I(typ)   I(min)   I(max)
-1.8V     -5.104A    -4.871A    -5.301A
-1.073V   -99.03mA   -143.7mA   -86.57mA
-1.036V   -61.8mA    -90.72mA   -59.87mA
-1V       -46.13mA   -64.73mA   -48.3mA
-963.6mV  -34.72mA   -45.55mA   -39.35mA
-927.3mV  -27.57mA   -33.17mA   -33.02mA
-854.5mV  -20.79mA   -21.36mA   -26.11mA
-709.1mV  -11.52mA   -9.383mA   -15.46mA
-563.6mV  -4.448mA   -3.656mA   -6.094mA
-454.5mV  -1.35mA    -1.34mA    -1.873mA
-18.18mV  0A         0A         0A
3.6V      0A         0A         0A
[Ramp]
| variable   typ   min   max
dV/dt_f 0.65583819/2.2419017n 0.36918897/6.2144684n 0.82651579/1.3765025n
dV/dt_r 0.69014978/2.049969n  0.45474484/5.8009093n 0.86532337/0.89244268n
R_load = 50
[Rising Waveform]
R_fixture = 50
V_fixture = 1.8
V_fixture_min = 1.62
V_fixture_max = 1.95
|   time   V(typ)   V(min)   V(max)
0s        710.2mV    1.006V     576mV
631.2ps   710.2mV    1.006V     608.4mV
702.6ps   710.2mV    1.006V     823.7mV
837.8ps   710.2mV    1.006V     1.684V
925.9ps   729mV      1.006V     1.882V
1.281ns   1.684V     985.1mV    1.941V
1.63ns    1.782V     1.051V     1.947V
2.161ns   1.796V     1.549V     1.949V
2.576ns   1.798V     1.607V     1.949V
26.2ns    1.8V       1.62V      1.95V
[Rising Waveform]
R_fixture = 50
V_fixture = 0
V_fixture_min = 0
V_fixture_max = 0
|   time   V(typ)   V(min)   V(max)
0s        2.669mV    0V         4.031mV
639.8ps   2.669mV    0V         12.87mV
895ps     2.669mV    0V         412.4mV
1.138ns   57.01mV    0V         688.5mV
1.719ns   381.7mV    0V         1.15V
2.232ns   593.8mV    55.71mV    1.294V
3.033ns   842mV      153.5mV    1.374V
5.183ns   1.06V      377.4mV    1.423V
10.08ns   1.133V     640.7mV    1.434V
26.22ns   1.142V     745.3mV    1.434V
[Falling Waveform]
R_fixture = 50
V_fixture = 1.8
V_fixture_min = 1.62
V_fixture_max = 1.95
|   time   V(typ)   V(min)   V(max)
0s        1.8V       1.619V     1.949V
671.1ps   1.8V       1.619V     1.949V
1.08ns    1.798V     1.619V     1.818V
1.952ns   1.684V     1.619V     1.447V
3.005ns   1.463V     1.592V     751.2mV
3.664ns   1.265V     1.565V     611.2mV
5.017ns   873.3mV    1.489V     583mV
6.987ns   754.1mV    1.339V     577mV
13.21ns   712mV      1.083V     576.2mV
26.2ns    710.3mV    1.012V     576.2mV
[Falling Waveform]
R_fixture = 50
V_fixture = 0
V_fixture_min = 0
V_fixture_max = 0
|   time   V(typ)   V(min)   V(max)
0s        1.141V     750.9mV    1.433V
671.2ps   1.141V     750.9mV    1.426V
1.085ns   1.118V     750.9mV    1.223V
1.481ns   1.013V     750.9mV    933.2mV
2.226ns   693mV      664.3mV    317.3mV
2.823ns   368.2mV    560.9mV    106.3mV
3.341ns   191.9mV    455.8mV    10.81mV
5.179ns   4.446mV    129.1mV    3.164mV
7.38ns    2.326mV    13.09mV    3.075mV
26.22ns   2.13mV     0V         3.071mV
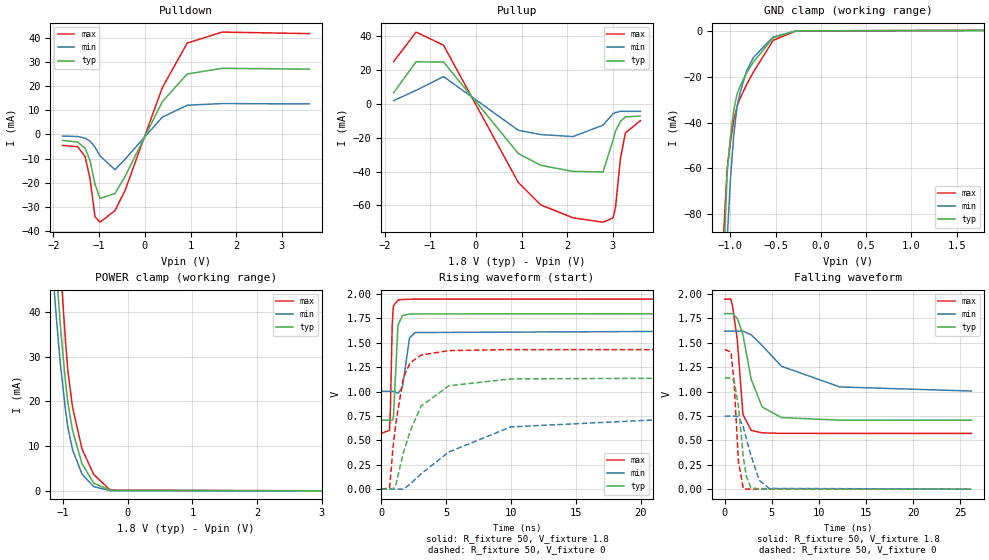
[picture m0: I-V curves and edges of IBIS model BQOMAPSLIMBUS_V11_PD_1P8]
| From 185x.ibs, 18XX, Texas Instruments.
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|   Model Cell BQOMAPSLIMBUS_V11_PD_1P8
|BQOMAPSLIMBUS_V11_PD_1P8
[Model]   BQOMAPSLIMBUS_V11_PD_1P8
Model_type   I/O
Polarity   Non-Inverting
Enable   Active-Low
Vinl =  0.63
Vinh =  1.17
Cref =  15pF
Rref =  100.0000M
Vref =  0V
Vmeas =  0.9
C_comp   1.636035p   1.481314p   1.795483p
[Model Spec]
Vinl   0.63   0.567   0.6825
Vinh   1.17   1.053   1.2675
[Temperature Range]   25   125   -40
[Voltage Range]   1.8   1.62   1.95
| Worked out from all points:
|   slope of the pulldown table from 0 to 0.27 V, typ, clamps not added: 27.2 ohm
|   slope of the pullup table from 0 to 0.27 V, typ, clamps not added: 26.2 ohm
|   GND clamp passes 1 mA (typ) near -0.44 V on its own axis
|   POWER clamp passes 1 mA (typ) near -0.46 V on its own axis
|   rising waveform, R_fixture 50, V_fixture 1.8: 20-80 % time 186ps typ, 348ps min, 129ps max; typ from 0.707 V to 1.8 V
|   rising waveform, R_fixture 50, V_fixture 0: 20-80 % time 2.02ns typ, 5.6ns min, 881ps max; typ from 0 V to 1.14 V
|   falling waveform, R_fixture 50, V_fixture 1.8: 20-80 % time 1.52ns typ, 4.78ns min, 670ps max; typ from 1.8 V to 0.706 V
|   falling waveform, R_fixture 50, V_fixture 0: 20-80 % time 733ps typ, 1.3ns min, 496ps max; typ from 1.14 V to 0 V
| Nom Voltages:
|   BIASFET=1.8, VBBNW=1.1, VDD=1.1, VDDS=1.8, VDDU=1.05, VSS=0, VSSS=0
| Min Voltages:
|   BIASFET=1.62, VBBNW=0.99, VDD=0.99, VDDS=1.62, VDDU=0.95, VSS=0,
|   VSSS=0
| Max Voltages:
|   BIASFET=1.95, VBBNW=1.21, VDD=1.21, VDDS=1.95, VDDU=1.16, VSS=0,
|   VSSS=0
[POWER_clamp]
|   voltage   I(typ)   I(min)   I(max)
-1.8V     243.4mA    191.6mA    307.8mA
-1.182V   67.14mA    52.87mA    87.8mA
-1.109V   50.26mA    39.3mA     67.51mA
-1.073V   42.68mA    33.12mA    58mA
-1.036V   35.59mA    27.28mA    48.82mA
-963.6mV  24.31mA    18.01mA    33.31mA
-927.3mV  19.65mA    14.2mA     26.78mA
-854.5mV  13.48mA    9.177mA    18.67mA
-709.1mV  6.095mA    3.747mA    9.4mA
-527.3mV  1.73mA     943.3uA    3.675mA
-272.7mV  118.9uA    74.64uA    178uA
3.6V      0A         0A         0A
[Pulldown]
|   voltage   I(typ)   I(min)   I(max)
-1.8V     -2.487mA   -681.8uA   -4.563mA
-1.473V   -3.152mA   -884.6uA   -5.068mA
-1.309V   -5.739mA   -1.559mA   -9.112mA
-1.2V     -10.86mA   -2.75mA    -18.27mA
-1.091V   -20.62mA   -5.298mA   -34.08mA
-981.8mV  -26.44mA   -8.862mA   -36.32mA
-654.5mV  -24.5mA    -14.59mA   -31.53mA
-436.4mV  -17.53mA   -10.31mA   -23.34mA
381.8mV   13.54mA    7.116mA    19.32mA
927.3mV   25mA       12.07mA    37.77mA
1.691V    27.34mA    12.75mA    42.32mA
3.6V      26.99mA    12.6mA     41.69mA
[Pullup]
|   voltage   I(typ)   I(min)   I(max)
-1.8V     6.703mA    2.011mA    25.07mA
-1.309V   24.97mA    8.117mA    42.58mA
-709.1mV  24.88mA    16.26mA    34.85mA
927.3mV   -29.26mA   -15.5mA    -46.38mA
1.418V    -36.27mA   -18.07mA   -59.68mA
2.127V    -39.86mA   -19.24mA   -67.35mA
2.782V    -40.19mA   -12.5mA    -69.92mA
3V        -21.5mA    -5.748mA   -67.45mA
3.055V    -16.07mA   -5.025mA   -61.28mA
3.164V    -10.24mA   -4.312mA   -32.15mA
3.273V    -7.595mA   -4.315mA   -17.08mA
3.6V      -7.13mA    -4.323mA   -9.86mA
[GND_clamp]
|   voltage   I(typ)   I(min)   I(max)
-1.8V     -5.104A    -4.871A    -5.301A
-1.073V   -99.01mA   -143.7mA   -86.51mA
-1.036V   -61.78mA   -90.71mA   -59.81mA
-1V       -46.11mA   -64.73mA   -48.24mA
-963.6mV  -34.7mA    -45.54mA   -39.29mA
-927.3mV  -27.54mA   -33.17mA   -32.95mA
-890.9mV  -23.9mA    -26.66mA   -29.29mA
-818.2mV  -18.14mA   -17.24mA   -23.2mA
-745.5mV  -13.61mA   -11.65mA   -17.98mA
-527.3mV  -3.104mA   -2.701mA   -4.21mA
-272.7mV  -55.4uA    -76.65uA   -80.17uA
1.8V      92.49uA    51.14uA    157.6uA
[Ramp]
| variable   typ   min   max
dV/dt_f 0.65876891/1.5296646n 0.37168437/4.8129839n 0.82957656/0.67609979n
dV/dt_r 0.68930839/2.0268381n 0.45386508/5.7323369n 0.86481215/0.87977476n
R_load = 50
[Rising Waveform]
R_fixture = 50
V_fixture = 1.8
V_fixture_min = 1.62
V_fixture_max = 1.95
|   time   V(typ)   V(min)   V(max)
0s        706.8mV    1.003V     572.1mV
630.2ps   706.8mV    1.003V     603mV
706.4ps   706.8mV    1.003V     837.9mV
838.7ps   706.8mV    1.003V     1.679V
927.4ps   722.2mV    1.003V     1.877V
1.284ns   1.681V     983.1mV    1.938V
1.631ns   1.779V     1.043V     1.944V
2.171ns   1.794V     1.55V      1.946V
2.616ns   1.796V     1.605V     1.947V
26.2ns    1.798V     1.619V     1.948V
[Rising Waveform]
R_fixture = 50
V_fixture = 0
V_fixture_min = 0
V_fixture_max = 0
|   time   V(typ)   V(min)   V(max)
0s        0V         0V         0V
637.1ps   0V         0V         12.04mV
896.5ps   0V         0V         416.7mV
1.128ns   49.87mV    0V         684.2mV
1.701ns   374.9mV    0V         1.145V
2.225ns   593.8mV    52.2mV     1.293V
3.064ns   850.7mV    156.5mV    1.374V
5.195ns   1.059V     380.1mV    1.42V
9.987ns   1.13V      638.1mV    1.43V
26.2ns    1.139V     742.7mV    1.43V
[Falling Waveform]
R_fixture = 50
V_fixture = 1.8
V_fixture_min = 1.62
V_fixture_max = 1.95
|   time   V(typ)   V(min)   V(max)
0s        1.798V     1.619V     1.947V
655.5ps   1.798V     1.619V     1.947V
860.3ps   1.798V     1.619V     1.859V
1.341ns   1.748V     1.619V     1.526V
1.94ns    1.582V     1.619V     764.5mV
2.812ns   1.126V     1.581V     602mV
3.991ns   840.5mV    1.47V      576.6mV
6.024ns   733.6mV    1.259V     571.5mV
12.23ns   706.3mV    1.047V     571.1mV
26.2ns    705.9mV    1.005V     571.1mV
[Falling Waveform]
R_fixture = 50
V_fixture = 0
V_fixture_min = 0
V_fixture_max = 0
|   time   V(typ)   V(min)   V(max)
0s        1.138V     747.6mV    1.43V
667.1ps   1.138V     747.6mV    1.405V
1.005ns   1.105V     747.6mV    1.083V
1.46ns    847.6mV    743.4mV    280.3mV
1.984ns   323.7mV    634.4mV    6.166mV
2.294ns   132.5mV    519.4mV    0V
2.764ns   19.6mV     352mV      0V
3.661ns   0V         92.6mV     0V
4.698ns   0V         8.353mV    0V
26.2ns    0V         0V         0V
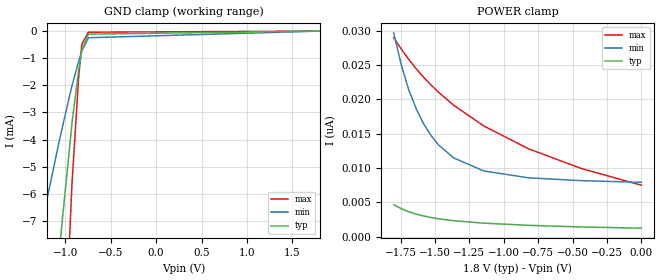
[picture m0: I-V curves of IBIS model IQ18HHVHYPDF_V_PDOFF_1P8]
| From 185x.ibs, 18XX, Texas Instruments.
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|   Model Cell IQ18HHVHYPDF_V_PDOFF_1P8
|IQ18HHVHYPDF_V_PDOFF_1P8
[Model]   IQ18HHVHYPDF_V_PDOFF_1P8
Model_type   Input
Polarity   Non-Inverting
Vinl =  0.63
Vinh =  1.17
C_comp   1.414401p   1.406761p   1.446743p
[Model Spec]
Vinl   0.63   0.567   0.6825
Vinh   1.17   1.053   1.2675
[Temperature Range]   25   125   -40
[Voltage Range]   1.8   1.62   1.95
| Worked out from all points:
|   GND clamp passes 1 mA (typ) near -0.83 V on its own axis
| Nom Voltages:
|   VBBNW=1.1, VDD=1.1, VDDS=1.8, BUS_VSSS=0, ESD_BIASFET=0, ESD_VDDS=0,
|   VSS=0
| Min Voltages:
|   VBBNW=0.99, VDD=0.99, VDDS=1.62, BUS_VSSS=0, ESD_BIASFET=0,
|   ESD_VDDS=0, VSS=0
| Max Voltages:
|   VBBNW=1.21, VDD=1.21, VDDS=1.95, BUS_VSSS=0, ESD_BIASFET=0,
|   ESD_VDDS=0, VSS=0
[POWER_clamp]
|   voltage   I(typ)   I(min)   I(max)
-1.8V     4.658nA    29.69nA    28.99nA
-1.745V   4.083nA    25.04nA    27.33nA
-1.691V   3.638nA    21.42nA    25.83nA
-1.636V   3.291nA    18.61nA    24.46nA
-1.582V   3.016nA    16.41nA    23.21nA
-1.527V   2.794nA    14.7nA     22.07nA
-1.473V   2.613nA    13.35nA    21.02nA
-1.364V   2.335nA    11.48nA    19.15nA
-1.145V   1.976nA    9.578nA    16.13nA
-818.2mV  1.657nA    8.575nA    12.79nA
-436.4mV  1.424nA    8.167nA    9.94nA
0V        1.248nA    7.928nA    7.504nA
[GND_clamp]
|   voltage   I(typ)   I(min)   I(max)
-1.8V     -36.45mA   -16.28mA   -79.2mA
-1.691V   -32.13mA   -14.4mA    -69.62mA
-1.655V   -30.69mA   -13.78mA   -66.44mA
-1.255V   -15.12mA   -7.047mA   -31.81mA
-1.218V   -13.74mA   -6.454mA   -28.74mA
-1.073V   -8.354mA   -4.144mA   -16.69mA
-1.036V   -7.051mA   -3.586mA   -13.77mA
-927.3mV  -3.408mA   -2.016mA   -5.639mA
-854.5mV  -1.469mA   -1.124mA   -1.733mA
-818.2mV  -698.4uA   -732.6uA   -475.1uA
-745.5mV  -112.4uA   -245.6uA   -41.04uA
1.8V      1.248nA    8.014nA    6.812nA
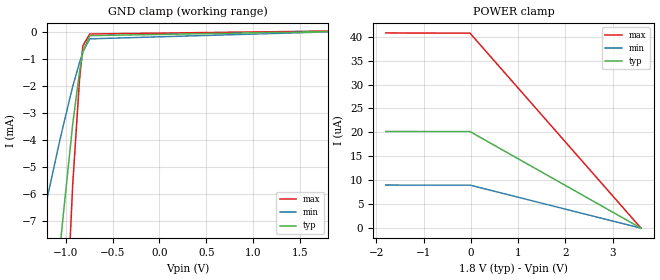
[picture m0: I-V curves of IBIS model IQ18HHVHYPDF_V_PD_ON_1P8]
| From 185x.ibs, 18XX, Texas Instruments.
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|   Model Cell IQ18HHVHYPDF_V_PD_ON_1P8
|IQ18HHVHYPDF_V_PD_ON_1P8
[Model]   IQ18HHVHYPDF_V_PD_ON_1P8
Model_type   Input
Polarity   Non-Inverting
Vinl =  0.63
Vinh =  1.17
C_comp   1.414401p   1.406761p   1.446743p
[Model Spec]
Vinl   0.63   0.567   0.6825
Vinh   1.17   1.053   1.2675
[Temperature Range]   25   125   -40
[Voltage Range]   1.8   1.62   1.95
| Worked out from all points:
|   GND clamp passes 1 mA (typ) near -0.83 V on its own axis
| Nom Voltages:
|   VBBNW=1.1, VDD=1.1, VDDS=1.8, BUS_VSSS=0, ESD_BIASFET=0, ESD_VDDS=0,
|   VSS=0
| Min Voltages:
|   VBBNW=0.99, VDD=0.99, VDDS=1.62, BUS_VSSS=0, ESD_BIASFET=0,
|   ESD_VDDS=0, VSS=0
| Max Voltages:
|   VBBNW=1.21, VDD=1.21, VDDS=1.95, BUS_VSSS=0, ESD_BIASFET=0,
|   ESD_VDDS=0, VSS=0
[POWER_clamp]
|   voltage   I(typ)   I(min)   I(max)
-1.8V     20.2uA     9.018uA    40.79uA
-1.364V   20.19uA    8.995uA    40.76uA
-18.18mV  20.18uA    8.99uA     40.74uA
3.6V      0A         0A         0A
[GND_clamp]
|   voltage   I(typ)   I(min)   I(max)
-1.8V     -36.45mA   -16.28mA   -79.2mA
-1.691V   -32.13mA   -14.4mA    -69.62mA
-1.655V   -30.69mA   -13.78mA   -66.44mA
-1.255V   -15.12mA   -7.048mA   -31.82mA
-1.218V   -13.74mA   -6.455mA   -28.74mA
-1.073V   -8.357mA   -4.145mA   -16.7mA
-1.036V   -7.055mA   -3.587mA   -13.77mA
-927.3mV  -3.414mA   -2.018mA   -5.654mA
-854.5mV  -1.478mA   -1.127mA   -1.756mA
-818.2mV  -710.6uA   -735.2uA   -501.6uA
-745.5mV  -128.7uA   -249.4uA   -69.28uA
1.8V      20.18uA    8.99uA     40.74uA
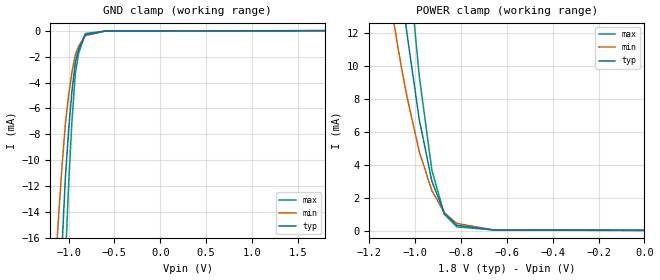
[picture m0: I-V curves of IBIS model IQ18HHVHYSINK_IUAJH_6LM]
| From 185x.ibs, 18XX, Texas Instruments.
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[Model]   IQ18HHVHYSINK_IUAJH_6LM
Model_type   Input
Polarity   Non-Inverting
Vinl =  0.63
Vinh =  1.17
C_comp   0.5850024p   0.4851986p   0.6834494p
[Model Spec]
Vinl   0.63   0.567   0.6825
Vinh   1.17   1.053   1.2675
[Temperature Range]   25   125   -40
[Voltage Range]   1.8   1.62   1.95
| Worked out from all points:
|   GND clamp passes 1 mA (typ) near -0.87 V on its own axis
|   POWER clamp passes 1 mA (typ) near -0.87 V on its own axis
| Nom Voltages:
|   BIASFET=1.8, VBBNW=1.1, VDD=1.1, VDDS=1.8, BUS_VSSS=0, VSS=0
| Min Voltages:
|   BIASFET=1.62, VBBNW=0.99, VDD=0.99, VDDS=1.62, BUS_VSSS=0, VSS=0
| Max Voltages:
|   BIASFET=1.95, VBBNW=1.21, VDD=1.21, VDDS=1.95, BUS_VSSS=0, VSS=0
[POWER_clamp]
|   voltage   I(typ)   I(min)   I(max)
-1.8V     125.2mA    90.56mA    173.6mA
-1.127V   23.02mA    15.54mA    33.29mA
-1.073V   16.23mA    10.95mA    23.49mA
-1.055V   14.11mA    9.55mA     20.4mA
-1.036V   12mA       8.152mA    17.3mA
-1.018V   10.24mA    7.03mA     14.65mA
-981.8mV  6.722mA    4.787mA    9.349mA
-927.3mV  3.006mA    2.437mA    3.683mA
-872.7mV  1.053mA    1.082mA    984.1uA
-818.2mV  322.7uA    439.7uA    228.3uA
-654.5mV  33.19uA    35.8uA     43.15uA
0V        20.78uA    10.58uA    31.81uA
[GND_clamp]
|   voltage   I(typ)   I(min)   I(max)
-1.8V     -188.7mA   -125mA     -285.2mA
-1.145V   -29.78mA   -18.49mA   -47.05mA
-1.109V   -23.02mA   -14.32mA   -36.39mA
-1.073V   -16.91mA   -10.58mA   -26.71mA
-1.036V   -11.46mA   -7.277mA   -18.02mA
-1V       -7.668mA   -5.002mA   -11.89mA
-963.6mV  -4.667mA   -3.197mA   -6.993mA
-927.3mV  -2.457mA   -1.861mA   -3.319mA
-890.9mV  -1.429mA   -1.183mA   -1.75mA
-818.2mV  -297.6uA   -367uA     -201.4uA
-600mV    -7.728uA   -8.609uA   -10.18uA
1.8V      20.78uA    11.73uA    29.42uA
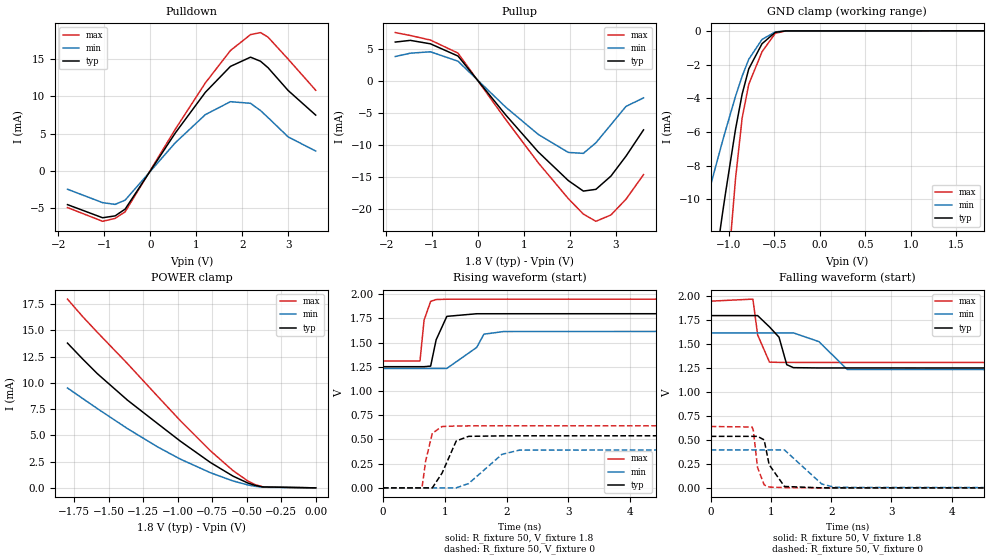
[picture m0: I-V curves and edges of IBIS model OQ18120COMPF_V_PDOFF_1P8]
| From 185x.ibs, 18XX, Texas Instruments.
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|   Model Cell OQ18120COMPF_V_PDOFF_1P8
|OQ18120COMPF_V_PDOFF_1P8
[Model]   OQ18120COMPF_V_PDOFF_1P8
Model_type   3-state
Polarity   Non-Inverting
Enable   Active-Low
Cref =  15pF
Rref =  100.0000M
Vref =  0V
Vmeas =  0.9
C_comp   3.025647p   2.252248p   3.343534p
[Temperature Range]   25   125   -40
[Voltage Range]   1.8   1.62   1.95
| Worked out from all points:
|   slope of the pulldown table from 0 to 0.27 V, typ, clamps not added: 105 ohm
|   slope of the pullup table from 0 to 0.27 V, typ, clamps not added: 110 ohm
|   GND clamp passes 1 mA (typ) near -0.67 V on its own axis
|   POWER clamp passes 1 mA (typ) near -0.58 V on its own axis
|   rising waveform, R_fixture 50, V_fixture 1.8: 20-80 % time 183ps typ, 407ps min, 101ps max; typ from 1.25 V to 1.8 V
|   rising waveform, R_fixture 50, V_fixture 0: 20-80 % time 235ps typ, 309ps min, 120ps max; typ from 0 V to 0.539 V
|   falling waveform, R_fixture 50, V_fixture 1.8: 20-80 % time 254ps typ, 293ps min, 140ps max; typ from 1.8 V to 1.25 V
|   falling waveform, R_fixture 50, V_fixture 0: 20-80 % time 208ps typ, 400ps min, 120ps max; typ from 0.538 V to 0 V
| Nom Voltages:
|   VBBNW=1.1, VDD=1.1, VDDS=1.8, ESD_BIASFET=0, ESD_VDDS=0, ESD_VSS=0,
|   VSS=0, VSSS=0
| Min Voltages:
|   VBBNW=0.99, VDD=0.99, VDDS=1.62, ESD_BIASFET=0, ESD_VDDS=0, ESD_VSS=0,
|   VSS=0, VSSS=0
| Max Voltages:
|   VBBNW=1.21, VDD=1.21, VDDS=1.95, ESD_BIASFET=0, ESD_VDDS=0, ESD_VSS=0,
|   VSS=0, VSSS=0
[POWER_clamp]
|   voltage   I(typ)   I(min)   I(max)
-1.8V     13.79mA    9.516mA    17.98mA
-1.691V   12.29mA    8.522mA    16.33mA
-1.582V   10.86mA    7.539mA    14.8mA
-1.364V   8.345mA    5.636mA    11.82mA
-1.145V   6.107mA    3.891mA    8.703mA
-981.8mV  4.451mA    2.74mA     6.401mA
-763.6mV  2.418mA    1.443mA    3.534mA
-600mV    1.12mA     659.7uA    1.647mA
-490.9mV  454.6uA    272.9uA    642.7uA
-436.4mV  225.3uA    141.7uA    291.2uA
-381.8mV  86.6uA     59.98uA    90.93uA
0V        312.2pA    762.9pA    3.032nA
[Pulldown]
|   voltage   I(typ)   I(min)   I(max)
-1.8V     -4.515mA   -2.451mA   -4.909mA
-1.036V   -6.278mA   -4.249mA   -6.752mA
-763.6mV  -6.024mA   -4.482mA   -6.361mA
-545.5mV  -5.116mA   -3.911mA   -5.476mA
545.5mV   5.097mA    3.788mA    5.6mA
1.2V      10.56mA    7.562mA    11.82mA
1.745V    14.03mA    9.297mA    16.16mA
2.182V    15.27mA    9.079mA    18.3mA
2.4V      14.72mA    8.101mA    18.57mA
2.564V    13.85mA    7.159mA    17.95mA
3V        10.8mA     4.573mA    15.01mA
3.6V      7.496mA    2.676mA    10.83mA
[Pullup]
|   voltage   I(typ)   I(min)   I(max)
-1.8V     6.014mA    3.756mA    7.497mA
-1.473V   6.279mA    4.274mA    7.043mA
-1.036V   5.74mA     4.497mA    6.327mA
-436.4mV  3.832mA    3.025mA    4.29mA
600mV     -5.351mA   -4.136mA   -6.059mA
1.309V    -11.14mA   -8.407mA   -12.83mA
1.964V    -15.62mA   -11.22mA   -18.44mA
2.291V    -17.26mA   -11.37mA   -20.85mA
2.564V    -16.99mA   -9.716mA   -21.98mA
2.891V    -14.92mA   -6.885mA   -20.99mA
3.218V    -11.81mA   -4.041mA   -18.54mA
3.6V      -7.699mA   -2.699mA   -14.69mA
[GND_clamp]
|   voltage   I(typ)   I(min)   I(max)
-1.8V     -40.54mA   -21.7mA    -74.86mA
-1.582V   -31.33mA   -17.07mA   -57.53mA
-1.255V   -17.92mA   -10.24mA   -32mA
-1.073V   -10.92mA   -6.597mA   -18.43mA
-1.036V   -9.578mA   -5.892mA   -15.84mA
-927.3mV  -5.833mA   -3.882mA   -8.768mA
-854.5mV  -3.75mA    -2.687mA   -5.167mA
-781.8mV  -2.256mA   -1.686mA   -3.165mA
-636.4mV  -765.4uA   -511.6uA   -1.245mA
-490.9mV  -89.46uA   -65.33uA   -151uA
-381.8mV  -7.537uA   -6.765uA   -11.19uA
1.8V      312.2pA    545.6nA    2.96nA
[Ramp]
| variable   typ   min   max
dV/dt_f 0.33812059/0.2618272n 0.23775486/0.33625941n  0.3971411/0.14133863n
dV/dt_r 0.33310932/0.24307565n 0.24394196/0.32601841n 0.40148762/0.12250966n
R_load = 50
[Rising Waveform]
R_fixture = 50
V_fixture = 1.8
V_fixture_min = 1.62
V_fixture_max = 1.95
|   time   V(typ)   V(min)   V(max)
0s        1.252V     1.234V     1.311V
600ps     1.252V     1.234V     1.311V
665.7ps   1.252V     1.234V     1.732V
772.3ps   1.258V     1.234V     1.927V
861.4ps   1.53V      1.234V     1.946V
1.034ns   1.772V     1.234V     1.949V
1.517ns   1.799V     1.451V     1.95V
1.634ns   1.799V     1.588V     1.95V
1.952ns   1.799V     1.615V     1.95V
11.2ns    1.8V       1.62V      1.95V
[Rising Waveform]
R_fixture = 50
V_fixture = 0
V_fixture_min = 0
V_fixture_max = 0
|   time   V(typ)   V(min)   V(max)
0s        0V         0V         0V
632.2ps   0V         0V         0V
691.7ps   0V         0V         277.4mV
799.2ps   0V         0V         564.2mV
956.9ps   152.4mV    0V         633.9mV
1.186ns   484.7mV    0V         639.2mV
1.387ns   532.3mV    44.89mV    640.4mV
1.925ns   537.2mV    346.2mV    641.1mV
2.208ns   537.9mV    389.9mV    641.2mV
11.23ns   539.1mV    396.9mV    641.8mV
[Falling Waveform]
R_fixture = 50
V_fixture = 1.8
V_fixture_min = 1.62
V_fixture_max = 1.95
|   time   V(typ)   V(min)   V(max)
0s        1.8V       1.619V     1.951V
700.5ps   1.8V       1.619V     1.972V
778.9ps   1.8V       1.619V     1.598V
975.1ps   1.682V     1.619V     1.314V
1.134ns   1.574V     1.619V     1.311V
1.262ns   1.287V     1.619V     1.311V
1.373ns   1.256V     1.619V     1.311V
1.796ns   1.253V     1.528V     1.31V
2.266ns   1.253V     1.237V     1.31V
11.2ns    1.252V     1.234V     1.31V
[Falling Waveform]
R_fixture = 50
V_fixture = 0
V_fixture_min = 0
V_fixture_max = 0
|   time   V(typ)   V(min)   V(max)
0s        538.3mV    396.3mV    641.5mV
687.4ps   538.3mV    396.3mV    635.2mV
708ps     538.3mV    396.3mV    598.2mV
777.2ps   538.3mV    396.3mV    213.7mV
886.9ps   501.5mV    396.3mV    31.07mV
969.6ps   242.7mV    396.3mV    8.306mV
1.224ns   14.55mV    396.3mV    2.926mV
1.842ns   0V         40.8mV     0V
2.058ns   0V         5.062mV    0V
11.23ns   0V         0V         0V
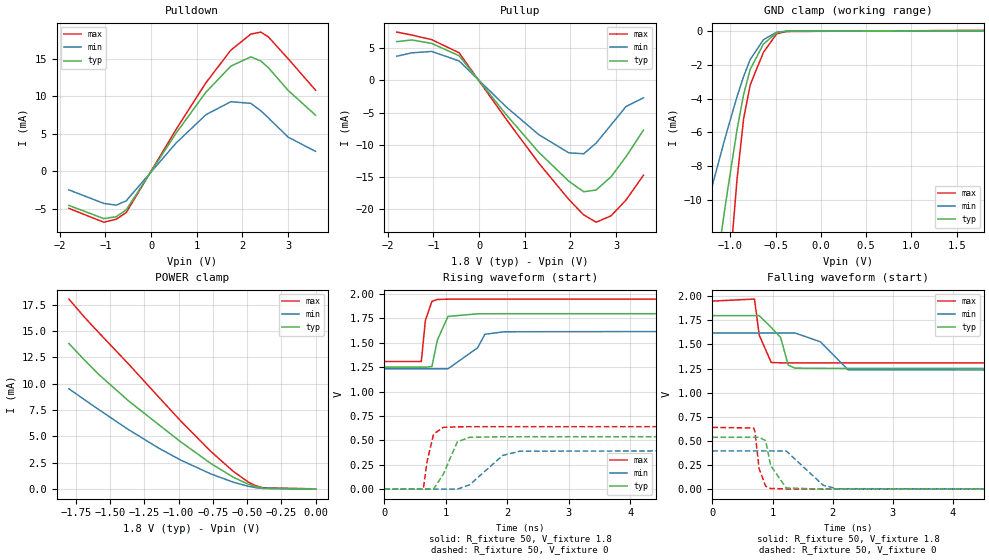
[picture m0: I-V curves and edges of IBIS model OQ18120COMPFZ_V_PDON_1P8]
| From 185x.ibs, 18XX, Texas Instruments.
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|   Model Cell OQ18120COMPFZ_V_PDON_1P8
|OQ18120COMPFZ_V_PDON_1P8
[Model]   OQ18120COMPFZ_V_PDON_1P8
Model_type   3-state
Polarity   Non-Inverting
Enable   Active-Low
Cref =  15pF
Rref =  100.0000M
Vref =  0V
Vmeas =  0.9
C_comp   3.025647p   2.252248p   3.343534p
[Temperature Range]   25   125   -40
[Voltage Range]   1.8   1.62   1.95
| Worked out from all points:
|   slope of the pulldown table from 0 to 0.27 V, typ, clamps not added: 105 ohm
|   slope of the pullup table from 0 to 0.27 V, typ, clamps not added: 110 ohm
|   GND clamp passes 1 mA (typ) near -0.66 V on its own axis
|   POWER clamp passes 1 mA (typ) near -0.58 V on its own axis
|   rising waveform, R_fixture 50, V_fixture 1.8: 20-80 % time 183ps typ, 407ps min, 101ps max; typ from 1.25 V to 1.8 V
|   rising waveform, R_fixture 50, V_fixture 0: 20-80 % time 235ps typ, 309ps min, 120ps max; typ from 0 V to 0.539 V
|   falling waveform, R_fixture 50, V_fixture 1.8: 20-80 % time 255ps typ, 293ps min, 140ps max; typ from 1.8 V to 1.25 V
|   falling waveform, R_fixture 50, V_fixture 0: 20-80 % time 207ps typ, 400ps min, 119ps max; typ from 0.538 V to 0 V
| Nom Voltages:
|   VBBNW=1.1, VDD=1.1, VDDS=1.8, ESD_BIASFET=0, ESD_VDDS=0, ESD_VSS=0,
|   VSS=0, VSSS=0
| Min Voltages:
|   VBBNW=0.99, VDD=0.99, VDDS=1.62, ESD_BIASFET=0, ESD_VDDS=0, ESD_VSS=0,
|   VSS=0, VSSS=0
| Max Voltages:
|   VBBNW=1.21, VDD=1.21, VDDS=1.95, ESD_BIASFET=0, ESD_VDDS=0, ESD_VSS=0,
|   VSS=0, VSSS=0
[POWER_clamp]
|   voltage   I(typ)   I(min)   I(max)
-1.8V     13.81mA    9.525mA    18.02mA
-1.691V   12.31mA    8.531mA    16.37mA
-1.582V   10.88mA    7.548mA    14.84mA
-1.364V   8.366mA    5.645mA    11.86mA
-1.145V   6.127mA    3.9mA      8.744mA
-981.8mV  4.472mA    2.749mA    6.441mA
-763.6mV  2.438mA    1.452mA    3.575mA
-600mV    1.14mA     668.7uA    1.688mA
-490.9mV  474.8uA    281.9uA    683.4uA
-436.4mV  245.5uA    150.7uA    331.9uA
-381.8mV  106.8uA    68.97uA    131.7uA
0V        20.18uA    8.982uA    40.74uA
[Pulldown]
|   voltage   I(typ)   I(min)   I(max)
-1.8V     -4.515mA   -2.451mA   -4.909mA
-1.036V   -6.278mA   -4.249mA   -6.753mA
-763.6mV  -6.024mA   -4.482mA   -6.361mA
-545.5mV  -5.116mA   -3.911mA   -5.476mA
545.5mV   5.097mA    3.788mA    5.6mA
1.2V      10.56mA    7.562mA    11.82mA
1.745V    14.03mA    9.297mA    16.16mA
2.182V    15.27mA    9.079mA    18.3mA
2.4V      14.72mA    8.101mA    18.57mA
2.564V    13.85mA    7.159mA    17.95mA
3V        10.8mA     4.573mA    15.01mA
3.6V      7.496mA    2.676mA    10.83mA
[Pullup]
|   voltage   I(typ)   I(min)   I(max)
-1.8V     6.014mA    3.756mA    7.497mA
-1.473V   6.279mA    4.274mA    7.043mA
-1.036V   5.74mA     4.497mA    6.327mA
-436.4mV  3.832mA    3.025mA    4.29mA
600mV     -5.351mA   -4.136mA   -6.059mA
1.309V    -11.14mA   -8.407mA   -12.83mA
1.964V    -15.62mA   -11.22mA   -18.44mA
2.291V    -17.26mA   -11.37mA   -20.85mA
2.564V    -16.99mA   -9.716mA   -21.98mA
2.891V    -14.92mA   -6.885mA   -20.99mA
3.218V    -11.81mA   -4.041mA   -18.54mA
3.6V      -7.699mA   -2.699mA   -14.69mA
[GND_clamp]
|   voltage   I(typ)   I(min)   I(max)
-1.8V     -40.55mA   -21.7mA    -74.86mA
-1.582V   -31.33mA   -17.07mA   -57.54mA
-1.255V   -17.92mA   -10.24mA   -32mA
-1.073V   -10.92mA   -6.598mA   -18.43mA
-1.036V   -9.581mA   -5.893mA   -15.85mA
-927.3mV  -5.839mA   -3.884mA   -8.783mA
-854.5mV  -3.759mA   -2.69mA    -5.189mA
-781.8mV  -2.27mA    -1.689mA   -3.193mA
-636.4mV  -782.5uA   -518.3uA   -1.272mA
-490.9mV  -104.4uA   -73.25uA   -175.3uA
-381.8mV  -19.43uA   -13.18uA   -31.14uA
1.8V      20.18uA    9.528uA    40.73uA
[Ramp]
| variable   typ   min   max
dV/dt_f 0.33813319/0.2619071n 0.23777009/0.33661996n 0.39714633/0.1414267n
dV/dt_r 0.33283141/0.24296192n 0.24382254/0.32595128n 0.40094352/0.12233847n
R_load = 50
[Rising Waveform]
R_fixture = 50
V_fixture = 1.8
V_fixture_min = 1.62
V_fixture_max = 1.95
|   time   V(typ)   V(min)   V(max)
0s        1.251V     1.234V     1.309V
600ps     1.251V     1.234V     1.309V
666.2ps   1.251V     1.234V     1.73V
772.3ps   1.257V     1.234V     1.925V
861.4ps   1.529V     1.234V     1.945V
1.034ns   1.771V     1.234V     1.948V
1.517ns   1.798V     1.45V      1.949V
1.634ns   1.798V     1.588V     1.949V
1.952ns   1.799V     1.614V     1.949V
11.2ns    1.799V     1.62V      1.949V
[Rising Waveform]
R_fixture = 50
V_fixture = 0
V_fixture_min = 0
V_fixture_max = 0
|   time   V(typ)   V(min)   V(max)
0s        0V         0V         0V
632.2ps   0V         0V         0V
691.7ps   0V         0V         277.4mV
799.2ps   0V         0V         564.1mV
956.9ps   152.4mV    0V         633.7mV
1.186ns   484.7mV    0V         639mV
1.387ns   532.2mV    44.91mV    640.2mV
1.925ns   537.1mV    346.2mV    640.8mV
2.208ns   537.7mV    389.9mV    640.8mV
11.23ns   538.7mV    396.8mV    640.9mV
[Falling Waveform]
R_fixture = 50
V_fixture = 1.8
V_fixture_min = 1.62
V_fixture_max = 1.95
|   time   V(typ)   V(min)   V(max)
0s        1.799V     1.619V     1.95V
700.5ps   1.799V     1.619V     1.971V
778.9ps   1.799V     1.619V     1.597V
978.9ps   1.676V     1.619V     1.313V
1.134ns   1.573V     1.619V     1.31V
1.261ns   1.286V     1.619V     1.309V
1.373ns   1.255V     1.619V     1.309V
1.796ns   1.253V     1.528V     1.309V
2.255ns   1.252V     1.237V     1.309V
11.2ns    1.252V     1.234V     1.309V
[Falling Waveform]
R_fixture = 50
V_fixture = 0
V_fixture_min = 0
V_fixture_max = 0
|   time   V(typ)   V(min)   V(max)
0s        537.9mV    396.1mV    640.5mV
687.4ps   537.9mV    396.1mV    634.2mV
708ps     537.9mV    396.1mV    597.2mV
776.1ps   537.9mV    396.1mV    215mV
885.6ps   503mV      396.1mV    31.06mV
967.8ps   246mV      396.1mV    7.349mV
1.228ns   13.1mV     395.5mV    2.048mV
1.842ns   0V         40.51mV    0V
2.071ns   0V         4.307mV    0V
11.23ns   0V         0V         0V
